VERSION 5.8 ;
BUSBITCHARS "[]" ;
DIVIDERCHAR "/" ;
UNITS
    DATABASE MICRONS 1000 ;
END UNITS

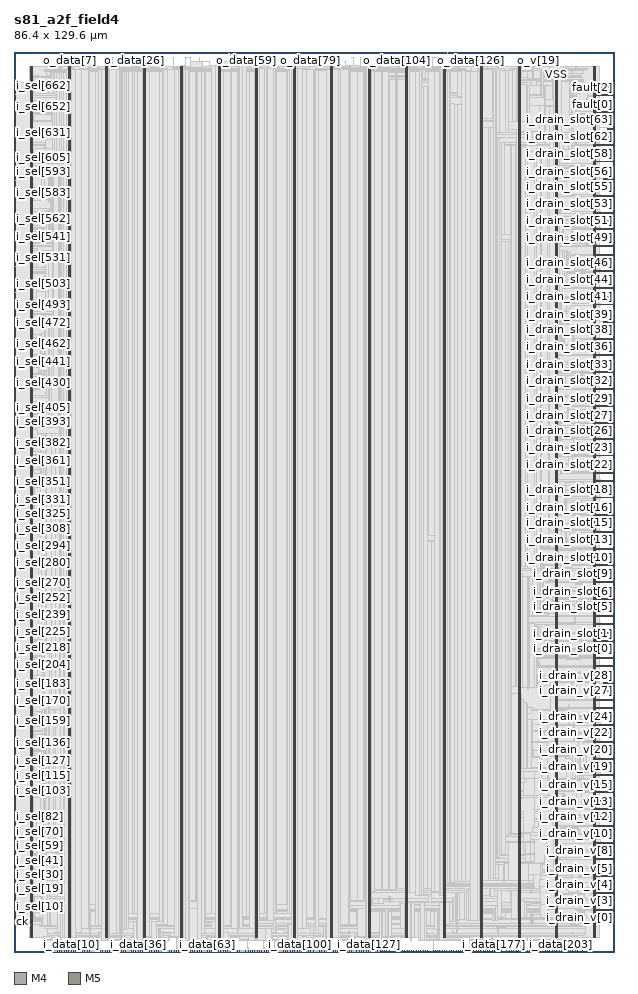
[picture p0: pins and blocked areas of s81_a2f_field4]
MACRO s81_a2f_field4
  FOREIGN s81_a2f_field4 0 0 ;
  CLASS BLOCK ;
  SIZE 86.4 BY 129.6 ;
  PIN ck
    DIRECTION INPUT ;
    USE SIGNAL ;
    PORT
      LAYER M4 ;
        RECT  0 4.32 0.192 4.344 ;
    END
  END ck
  PIN fault[0]
    DIRECTION OUTPUT ;
    USE SIGNAL ;
    PORT
      LAYER M4 ;
        RECT  86.208 120.96 86.4 120.984 ;
    END
    PORT
      LAYER M4 ;
        RECT  83.704 120.96 86.22 120.984 ;
    END
  END fault[0]
  PIN fault[1]
    DIRECTION OUTPUT ;
    USE SIGNAL ;
    PORT
      LAYER M4 ;
        RECT  86.208 122.256 86.4 122.28 ;
    END
    PORT
      LAYER M4 ;
        RECT  83.704 122.256 86.22 122.28 ;
    END
  END fault[1]
  PIN fault[2]
    DIRECTION OUTPUT ;
    USE SIGNAL ;
    PORT
      LAYER M4 ;
        RECT  86.208 123.408 86.4 123.432 ;
    END
    PORT
      LAYER M4 ;
        RECT  83.704 123.408 86.22 123.432 ;
    END
  END fault[2]
  PIN fault[3]
    DIRECTION OUTPUT ;
    USE SIGNAL ;
    PORT
      LAYER M4 ;
        RECT  86.208 124.56 86.4 124.584 ;
    END
    PORT
      LAYER M4 ;
        RECT  83.704 124.56 86.22 124.584 ;
    END
  END fault[3]
  PIN i_data[0]
    DIRECTION INPUT ;
    USE SIGNAL ;
    PORT
      LAYER M5 ;
        RECT  4.464 0 4.488 0.192 ;
    END
  END i_data[0]
  PIN i_data[100]
    DIRECTION INPUT ;
    USE SIGNAL ;
    PORT
      LAYER M5 ;
        RECT  41.136 0 41.16 0.192 ;
    END
  END i_data[100]
  PIN i_data[101]
    DIRECTION INPUT ;
    USE SIGNAL ;
    PORT
      LAYER M5 ;
        RECT  41.424 0 41.448 0.192 ;
    END
  END i_data[101]
  PIN i_data[102]
    DIRECTION INPUT ;
    USE SIGNAL ;
    PORT
      LAYER M5 ;
        RECT  41.712 0 41.736 0.192 ;
    END
  END i_data[102]
  PIN i_data[103]
    DIRECTION INPUT ;
    USE SIGNAL ;
    PORT
      LAYER M5 ;
        RECT  42.144 0 42.168 0.192 ;
    END
  END i_data[103]
  PIN i_data[104]
    DIRECTION INPUT ;
    USE SIGNAL ;
    PORT
      LAYER M5 ;
        RECT  42.432 0 42.456 0.192 ;
    END
  END i_data[104]
  PIN i_data[105]
    DIRECTION INPUT ;
    USE SIGNAL ;
    PORT
      LAYER M5 ;
        RECT  42.72 0 42.744 0.192 ;
    END
  END i_data[105]
  PIN i_data[106]
    DIRECTION INPUT ;
    USE SIGNAL ;
    PORT
      LAYER M5 ;
        RECT  43.152 0 43.176 0.192 ;
    END
  END i_data[106]
  PIN i_data[107]
    DIRECTION INPUT ;
    USE SIGNAL ;
    PORT
      LAYER M5 ;
        RECT  43.968 0 43.992 0.192 ;
    END
  END i_data[107]
  PIN i_data[108]
    DIRECTION INPUT ;
    USE SIGNAL ;
    PORT
      LAYER M5 ;
        RECT  44.256 0 44.28 0.192 ;
    END
  END i_data[108]
  PIN i_data[109]
    DIRECTION INPUT ;
    USE SIGNAL ;
    PORT
      LAYER M5 ;
        RECT  44.688 0 44.712 0.192 ;
    END
  END i_data[109]
  PIN i_data[10]
    DIRECTION INPUT ;
    USE SIGNAL ;
    PORT
      LAYER M5 ;
        RECT  8.304 0 8.328 0.192 ;
    END
  END i_data[10]
  PIN i_data[110]
    DIRECTION INPUT ;
    USE SIGNAL ;
    PORT
      LAYER M5 ;
        RECT  44.976 0 45 0.192 ;
    END
  END i_data[110]
  PIN i_data[111]
    DIRECTION INPUT ;
    USE SIGNAL ;
    PORT
      LAYER M5 ;
        RECT  45.264 0 45.288 0.192 ;
    END
  END i_data[111]
  PIN i_data[112]
    DIRECTION INPUT ;
    USE SIGNAL ;
    PORT
      LAYER M5 ;
        RECT  45.552 0 45.576 0.192 ;
    END
  END i_data[112]
  PIN i_data[113]
    DIRECTION INPUT ;
    USE SIGNAL ;
    PORT
      LAYER M5 ;
        RECT  45.984 0 46.008 0.192 ;
    END
  END i_data[113]
  PIN i_data[114]
    DIRECTION INPUT ;
    USE SIGNAL ;
    PORT
      LAYER M5 ;
        RECT  46.272 0 46.296 0.192 ;
    END
  END i_data[114]
  PIN i_data[115]
    DIRECTION INPUT ;
    USE SIGNAL ;
    PORT
      LAYER M5 ;
        RECT  46.56 0 46.584 0.192 ;
    END
  END i_data[115]
  PIN i_data[116]
    DIRECTION INPUT ;
    USE SIGNAL ;
    PORT
      LAYER M5 ;
        RECT  46.992 0 47.016 0.192 ;
    END
  END i_data[116]
  PIN i_data[117]
    DIRECTION INPUT ;
    USE SIGNAL ;
    PORT
      LAYER M5 ;
        RECT  47.28 0 47.304 0.192 ;
    END
  END i_data[117]
  PIN i_data[118]
    DIRECTION INPUT ;
    USE SIGNAL ;
    PORT
      LAYER M5 ;
        RECT  47.568 0 47.592 0.192 ;
    END
  END i_data[118]
  PIN i_data[119]
    DIRECTION INPUT ;
    USE SIGNAL ;
    PORT
      LAYER M5 ;
        RECT  48 0 48.024 0.192 ;
    END
  END i_data[119]
  PIN i_data[11]
    DIRECTION INPUT ;
    USE SIGNAL ;
    PORT
      LAYER M5 ;
        RECT  8.592 0 8.616 0.192 ;
    END
  END i_data[11]
  PIN i_data[120]
    DIRECTION INPUT ;
    USE SIGNAL ;
    PORT
      LAYER M5 ;
        RECT  48.288 0 48.312 0.192 ;
    END
  END i_data[120]
  PIN i_data[121]
    DIRECTION INPUT ;
    USE SIGNAL ;
    PORT
      LAYER M5 ;
        RECT  48.576 0 48.6 0.192 ;
    END
  END i_data[121]
  PIN i_data[122]
    DIRECTION INPUT ;
    USE SIGNAL ;
    PORT
      LAYER M5 ;
        RECT  49.344 0 49.368 0.192 ;
    END
  END i_data[122]
  PIN i_data[123]
    DIRECTION INPUT ;
    USE SIGNAL ;
    PORT
      LAYER M5 ;
        RECT  49.776 0 49.8 0.192 ;
    END
  END i_data[123]
  PIN i_data[124]
    DIRECTION INPUT ;
    USE SIGNAL ;
    PORT
      LAYER M5 ;
        RECT  50.064 0 50.088 0.192 ;
    END
  END i_data[124]
  PIN i_data[125]
    DIRECTION INPUT ;
    USE SIGNAL ;
    PORT
      LAYER M5 ;
        RECT  50.352 0 50.376 0.192 ;
    END
  END i_data[125]
  PIN i_data[126]
    DIRECTION INPUT ;
    USE SIGNAL ;
    PORT
      LAYER M5 ;
        RECT  50.784 0 50.808 0.192 ;
    END
  END i_data[126]
  PIN i_data[127]
    DIRECTION INPUT ;
    USE SIGNAL ;
    PORT
      LAYER M5 ;
        RECT  51.072 0 51.096 0.192 ;
    END
  END i_data[127]
  PIN i_data[128]
    DIRECTION INPUT ;
    USE SIGNAL ;
    PORT
      LAYER M5 ;
        RECT  51.36 0 51.384 0.192 ;
    END
  END i_data[128]
  PIN i_data[129]
    DIRECTION INPUT ;
    USE SIGNAL ;
    PORT
      LAYER M5 ;
        RECT  51.792 0 51.816 0.192 ;
    END
  END i_data[129]
  PIN i_data[12]
    DIRECTION INPUT ;
    USE SIGNAL ;
    PORT
      LAYER M5 ;
        RECT  8.88 0 8.904 0.192 ;
    END
  END i_data[12]
  PIN i_data[130]
    DIRECTION INPUT ;
    USE SIGNAL ;
    PORT
      LAYER M5 ;
        RECT  52.08 0 52.104 0.192 ;
    END
  END i_data[130]
  PIN i_data[131]
    DIRECTION INPUT ;
    USE SIGNAL ;
    PORT
      LAYER M5 ;
        RECT  52.368 0 52.392 0.192 ;
    END
  END i_data[131]
  PIN i_data[132]
    DIRECTION INPUT ;
    USE SIGNAL ;
    PORT
      LAYER M5 ;
        RECT  52.8 0 52.824 0.192 ;
    END
  END i_data[132]
  PIN i_data[133]
    DIRECTION INPUT ;
    USE SIGNAL ;
    PORT
      LAYER M5 ;
        RECT  53.088 0 53.112 0.192 ;
    END
  END i_data[133]
  PIN i_data[134]
    DIRECTION INPUT ;
    USE SIGNAL ;
    PORT
      LAYER M5 ;
        RECT  53.376 0 53.4 0.192 ;
    END
  END i_data[134]
  PIN i_data[135]
    DIRECTION INPUT ;
    USE SIGNAL ;
    PORT
      LAYER M5 ;
        RECT  53.664 0 53.688 0.192 ;
    END
  END i_data[135]
  PIN i_data[136]
    DIRECTION INPUT ;
    USE SIGNAL ;
    PORT
      LAYER M5 ;
        RECT  54.096 0 54.12 0.192 ;
    END
  END i_data[136]
  PIN i_data[137]
    DIRECTION INPUT ;
    USE SIGNAL ;
    PORT
      LAYER M5 ;
        RECT  54.912 0 54.936 0.192 ;
    END
  END i_data[137]
  PIN i_data[138]
    DIRECTION INPUT ;
    USE SIGNAL ;
    PORT
      LAYER M5 ;
        RECT  55.2 0 55.224 0.192 ;
    END
  END i_data[138]
  PIN i_data[139]
    DIRECTION INPUT ;
    USE SIGNAL ;
    PORT
      LAYER M5 ;
        RECT  55.632 0 55.656 0.192 ;
    END
  END i_data[139]
  PIN i_data[13]
    DIRECTION INPUT ;
    USE SIGNAL ;
    PORT
      LAYER M5 ;
        RECT  9.312 0 9.336 0.192 ;
    END
  END i_data[13]
  PIN i_data[140]
    DIRECTION INPUT ;
    USE SIGNAL ;
    PORT
      LAYER M5 ;
        RECT  55.92 0 55.944 0.192 ;
    END
  END i_data[140]
  PIN i_data[141]
    DIRECTION INPUT ;
    USE SIGNAL ;
    PORT
      LAYER M5 ;
        RECT  56.208 0 56.232 0.192 ;
    END
  END i_data[141]
  PIN i_data[142]
    DIRECTION INPUT ;
    USE SIGNAL ;
    PORT
      LAYER M5 ;
        RECT  56.64 0 56.664 0.192 ;
    END
  END i_data[142]
  PIN i_data[143]
    DIRECTION INPUT ;
    USE SIGNAL ;
    PORT
      LAYER M5 ;
        RECT  56.928 0 56.952 0.192 ;
    END
  END i_data[143]
  PIN i_data[144]
    DIRECTION INPUT ;
    USE SIGNAL ;
    PORT
      LAYER M5 ;
        RECT  57.216 0 57.24 0.192 ;
    END
  END i_data[144]
  PIN i_data[145]
    DIRECTION INPUT ;
    USE SIGNAL ;
    PORT
      LAYER M5 ;
        RECT  57.504 0 57.528 0.192 ;
    END
  END i_data[145]
  PIN i_data[146]
    DIRECTION INPUT ;
    USE SIGNAL ;
    PORT
      LAYER M5 ;
        RECT  57.936 0 57.96 0.192 ;
    END
  END i_data[146]
  PIN i_data[147]
    DIRECTION INPUT ;
    USE SIGNAL ;
    PORT
      LAYER M5 ;
        RECT  58.224 0 58.248 0.192 ;
    END
  END i_data[147]
  PIN i_data[148]
    DIRECTION INPUT ;
    USE SIGNAL ;
    PORT
      LAYER M5 ;
        RECT  58.512 0 58.536 0.192 ;
    END
  END i_data[148]
  PIN i_data[149]
    DIRECTION INPUT ;
    USE SIGNAL ;
    PORT
      LAYER M5 ;
        RECT  58.944 0 58.968 0.192 ;
    END
  END i_data[149]
  PIN i_data[14]
    DIRECTION INPUT ;
    USE SIGNAL ;
    PORT
      LAYER M5 ;
        RECT  9.6 0 9.624 0.192 ;
    END
  END i_data[14]
  PIN i_data[150]
    DIRECTION INPUT ;
    USE SIGNAL ;
    PORT
      LAYER M5 ;
        RECT  59.232 0 59.256 0.192 ;
    END
  END i_data[150]
  PIN i_data[151]
    DIRECTION INPUT ;
    USE SIGNAL ;
    PORT
      LAYER M5 ;
        RECT  59.52 0 59.544 0.192 ;
    END
  END i_data[151]
  PIN i_data[152]
    DIRECTION INPUT ;
    USE SIGNAL ;
    PORT
      LAYER M5 ;
        RECT  60.432 0 60.456 0.192 ;
    END
  END i_data[152]
  PIN i_data[153]
    DIRECTION INPUT ;
    USE SIGNAL ;
    PORT
      LAYER M5 ;
        RECT  60.72 0 60.744 0.192 ;
    END
  END i_data[153]
  PIN i_data[154]
    DIRECTION INPUT ;
    USE SIGNAL ;
    PORT
      LAYER M5 ;
        RECT  61.008 0 61.032 0.192 ;
    END
  END i_data[154]
  PIN i_data[155]
    DIRECTION INPUT ;
    USE SIGNAL ;
    PORT
      LAYER M5 ;
        RECT  61.296 0 61.32 0.192 ;
    END
  END i_data[155]
  PIN i_data[156]
    DIRECTION INPUT ;
    USE SIGNAL ;
    PORT
      LAYER M5 ;
        RECT  61.728 0 61.752 0.192 ;
    END
  END i_data[156]
  PIN i_data[157]
    DIRECTION INPUT ;
    USE SIGNAL ;
    PORT
      LAYER M5 ;
        RECT  62.016 0 62.04 0.192 ;
    END
  END i_data[157]
  PIN i_data[158]
    DIRECTION INPUT ;
    USE SIGNAL ;
    PORT
      LAYER M5 ;
        RECT  62.304 0 62.328 0.192 ;
    END
  END i_data[158]
  PIN i_data[159]
    DIRECTION INPUT ;
    USE SIGNAL ;
    PORT
      LAYER M5 ;
        RECT  62.736 0 62.76 0.192 ;
    END
  END i_data[159]
  PIN i_data[15]
    DIRECTION INPUT ;
    USE SIGNAL ;
    PORT
      LAYER M5 ;
        RECT  9.888 0 9.912 0.192 ;
    END
  END i_data[15]
  PIN i_data[160]
    DIRECTION INPUT ;
    USE SIGNAL ;
    PORT
      LAYER M5 ;
        RECT  63.024 0 63.048 0.192 ;
    END
  END i_data[160]
  PIN i_data[161]
    DIRECTION INPUT ;
    USE SIGNAL ;
    PORT
      LAYER M5 ;
        RECT  63.312 0 63.336 0.192 ;
    END
  END i_data[161]
  PIN i_data[162]
    DIRECTION INPUT ;
    USE SIGNAL ;
    PORT
      LAYER M5 ;
        RECT  63.744 0 63.768 0.192 ;
    END
  END i_data[162]
  PIN i_data[163]
    DIRECTION INPUT ;
    USE SIGNAL ;
    PORT
      LAYER M5 ;
        RECT  64.032 0 64.056 0.192 ;
    END
  END i_data[163]
  PIN i_data[164]
    DIRECTION INPUT ;
    USE SIGNAL ;
    PORT
      LAYER M5 ;
        RECT  64.32 0 64.344 0.192 ;
    END
  END i_data[164]
  PIN i_data[165]
    DIRECTION INPUT ;
    USE SIGNAL ;
    PORT
      LAYER M5 ;
        RECT  64.608 0 64.632 0.192 ;
    END
  END i_data[165]
  PIN i_data[166]
    DIRECTION INPUT ;
    USE SIGNAL ;
    PORT
      LAYER M5 ;
        RECT  65.568 0 65.592 0.192 ;
    END
  END i_data[166]
  PIN i_data[167]
    DIRECTION INPUT ;
    USE SIGNAL ;
    PORT
      LAYER M5 ;
        RECT  65.856 0 65.88 0.192 ;
    END
  END i_data[167]
  PIN i_data[168]
    DIRECTION INPUT ;
    USE SIGNAL ;
    PORT
      LAYER M5 ;
        RECT  66.144 0 66.168 0.192 ;
    END
  END i_data[168]
  PIN i_data[169]
    DIRECTION INPUT ;
    USE SIGNAL ;
    PORT
      LAYER M5 ;
        RECT  66.576 0 66.6 0.192 ;
    END
  END i_data[169]
  PIN i_data[16]
    DIRECTION INPUT ;
    USE SIGNAL ;
    PORT
      LAYER M5 ;
        RECT  10.176 0 10.2 0.192 ;
    END
  END i_data[16]
  PIN i_data[170]
    DIRECTION INPUT ;
    USE SIGNAL ;
    PORT
      LAYER M5 ;
        RECT  66.864 0 66.888 0.192 ;
    END
  END i_data[170]
  PIN i_data[171]
    DIRECTION INPUT ;
    USE SIGNAL ;
    PORT
      LAYER M5 ;
        RECT  67.152 0 67.176 0.192 ;
    END
  END i_data[171]
  PIN i_data[172]
    DIRECTION INPUT ;
    USE SIGNAL ;
    PORT
      LAYER M5 ;
        RECT  67.584 0 67.608 0.192 ;
    END
  END i_data[172]
  PIN i_data[173]
    DIRECTION INPUT ;
    USE SIGNAL ;
    PORT
      LAYER M5 ;
        RECT  67.872 0 67.896 0.192 ;
    END
  END i_data[173]
  PIN i_data[174]
    DIRECTION INPUT ;
    USE SIGNAL ;
    PORT
      LAYER M5 ;
        RECT  68.16 0 68.184 0.192 ;
    END
  END i_data[174]
  PIN i_data[175]
    DIRECTION INPUT ;
    USE SIGNAL ;
    PORT
      LAYER M5 ;
        RECT  68.448 0 68.472 0.192 ;
    END
  END i_data[175]
  PIN i_data[176]
    DIRECTION INPUT ;
    USE SIGNAL ;
    PORT
      LAYER M5 ;
        RECT  68.88 0 68.904 0.192 ;
    END
  END i_data[176]
  PIN i_data[177]
    DIRECTION INPUT ;
    USE SIGNAL ;
    PORT
      LAYER M5 ;
        RECT  69.168 0 69.192 0.192 ;
    END
  END i_data[177]
  PIN i_data[178]
    DIRECTION INPUT ;
    USE SIGNAL ;
    PORT
      LAYER M5 ;
        RECT  69.456 0 69.48 0.192 ;
    END
  END i_data[178]
  PIN i_data[179]
    DIRECTION INPUT ;
    USE SIGNAL ;
    PORT
      LAYER M5 ;
        RECT  69.888 0 69.912 0.192 ;
    END
  END i_data[179]
  PIN i_data[17]
    DIRECTION INPUT ;
    USE SIGNAL ;
    PORT
      LAYER M5 ;
        RECT  10.608 0 10.632 0.192 ;
    END
  END i_data[17]
  PIN i_data[180]
    DIRECTION INPUT ;
    USE SIGNAL ;
    PORT
      LAYER M5 ;
        RECT  70.176 0 70.2 0.192 ;
    END
  END i_data[180]
  PIN i_data[181]
    DIRECTION INPUT ;
    USE SIGNAL ;
    PORT
      LAYER M5 ;
        RECT  70.944 0 70.968 0.192 ;
    END
  END i_data[181]
  PIN i_data[182]
    DIRECTION INPUT ;
    USE SIGNAL ;
    PORT
      LAYER M5 ;
        RECT  71.376 0 71.4 0.192 ;
    END
  END i_data[182]
  PIN i_data[183]
    DIRECTION INPUT ;
    USE SIGNAL ;
    PORT
      LAYER M5 ;
        RECT  71.664 0 71.688 0.192 ;
    END
  END i_data[183]
  PIN i_data[184]
    DIRECTION INPUT ;
    USE SIGNAL ;
    PORT
      LAYER M5 ;
        RECT  71.952 0 71.976 0.192 ;
    END
  END i_data[184]
  PIN i_data[185]
    DIRECTION INPUT ;
    USE SIGNAL ;
    PORT
      LAYER M5 ;
        RECT  72.384 0 72.408 0.192 ;
    END
  END i_data[185]
  PIN i_data[186]
    DIRECTION INPUT ;
    USE SIGNAL ;
    PORT
      LAYER M5 ;
        RECT  72.672 0 72.696 0.192 ;
    END
  END i_data[186]
  PIN i_data[187]
    DIRECTION INPUT ;
    USE SIGNAL ;
    PORT
      LAYER M5 ;
        RECT  72.96 0 72.984 0.192 ;
    END
  END i_data[187]
  PIN i_data[188]
    DIRECTION INPUT ;
    USE SIGNAL ;
    PORT
      LAYER M5 ;
        RECT  73.248 0 73.272 0.192 ;
    END
  END i_data[188]
  PIN i_data[189]
    DIRECTION INPUT ;
    USE SIGNAL ;
    PORT
      LAYER M5 ;
        RECT  73.68 0 73.704 0.192 ;
    END
  END i_data[189]
  PIN i_data[18]
    DIRECTION INPUT ;
    USE SIGNAL ;
    PORT
      LAYER M5 ;
        RECT  10.896 0 10.92 0.192 ;
    END
  END i_data[18]
  PIN i_data[190]
    DIRECTION INPUT ;
    USE SIGNAL ;
    PORT
      LAYER M5 ;
        RECT  73.968 0 73.992 0.192 ;
    END
  END i_data[190]
  PIN i_data[191]
    DIRECTION INPUT ;
    USE SIGNAL ;
    PORT
      LAYER M5 ;
        RECT  74.256 0 74.28 0.192 ;
    END
  END i_data[191]
  PIN i_data[192]
    DIRECTION INPUT ;
    USE SIGNAL ;
    PORT
      LAYER M5 ;
        RECT  74.688 0 74.712 0.192 ;
    END
  END i_data[192]
  PIN i_data[193]
    DIRECTION INPUT ;
    USE SIGNAL ;
    PORT
      LAYER M5 ;
        RECT  74.976 0 75 0.192 ;
    END
  END i_data[193]
  PIN i_data[194]
    DIRECTION INPUT ;
    USE SIGNAL ;
    PORT
      LAYER M5 ;
        RECT  75.264 0 75.288 0.192 ;
    END
  END i_data[194]
  PIN i_data[195]
    DIRECTION INPUT ;
    USE SIGNAL ;
    PORT
      LAYER M5 ;
        RECT  75.696 0 75.72 0.192 ;
    END
  END i_data[195]
  PIN i_data[196]
    DIRECTION INPUT ;
    USE SIGNAL ;
    PORT
      LAYER M5 ;
        RECT  76.512 0 76.536 0.192 ;
    END
  END i_data[196]
  PIN i_data[197]
    DIRECTION INPUT ;
    USE SIGNAL ;
    PORT
      LAYER M5 ;
        RECT  76.8 0 76.824 0.192 ;
    END
  END i_data[197]
  PIN i_data[198]
    DIRECTION INPUT ;
    USE SIGNAL ;
    PORT
      LAYER M5 ;
        RECT  77.088 0 77.112 0.192 ;
    END
  END i_data[198]
  PIN i_data[199]
    DIRECTION INPUT ;
    USE SIGNAL ;
    PORT
      LAYER M5 ;
        RECT  77.52 0 77.544 0.192 ;
    END
  END i_data[199]
  PIN i_data[19]
    DIRECTION INPUT ;
    USE SIGNAL ;
    PORT
      LAYER M5 ;
        RECT  11.712 0 11.736 0.192 ;
    END
  END i_data[19]
  PIN i_data[1]
    DIRECTION INPUT ;
    USE SIGNAL ;
    PORT
      LAYER M5 ;
        RECT  4.752 0 4.776 0.192 ;
    END
  END i_data[1]
  PIN i_data[200]
    DIRECTION INPUT ;
    USE SIGNAL ;
    PORT
      LAYER M5 ;
        RECT  77.808 0 77.832 0.192 ;
    END
  END i_data[200]
  PIN i_data[201]
    DIRECTION INPUT ;
    USE SIGNAL ;
    PORT
      LAYER M5 ;
        RECT  78.096 0 78.12 0.192 ;
    END
  END i_data[201]
  PIN i_data[202]
    DIRECTION INPUT ;
    USE SIGNAL ;
    PORT
      LAYER M5 ;
        RECT  78.528 0 78.552 0.192 ;
    END
  END i_data[202]
  PIN i_data[203]
    DIRECTION INPUT ;
    USE SIGNAL ;
    PORT
      LAYER M5 ;
        RECT  78.816 0 78.84 0.192 ;
    END
  END i_data[203]
  PIN i_data[204]
    DIRECTION INPUT ;
    USE SIGNAL ;
    PORT
      LAYER M5 ;
        RECT  79.104 0 79.128 0.192 ;
    END
  END i_data[204]
  PIN i_data[205]
    DIRECTION INPUT ;
    USE SIGNAL ;
    PORT
      LAYER M5 ;
        RECT  79.536 0 79.56 0.192 ;
    END
  END i_data[205]
  PIN i_data[206]
    DIRECTION INPUT ;
    USE SIGNAL ;
    PORT
      LAYER M5 ;
        RECT  79.824 0 79.848 0.192 ;
    END
  END i_data[206]
  PIN i_data[207]
    DIRECTION INPUT ;
    USE SIGNAL ;
    PORT
      LAYER M5 ;
        RECT  80.112 0 80.136 0.192 ;
    END
  END i_data[207]
  PIN i_data[208]
    DIRECTION INPUT ;
    USE SIGNAL ;
    PORT
      LAYER M5 ;
        RECT  80.4 0 80.424 0.192 ;
    END
  END i_data[208]
  PIN i_data[209]
    DIRECTION INPUT ;
    USE SIGNAL ;
    PORT
      LAYER M5 ;
        RECT  80.832 0 80.856 0.192 ;
    END
  END i_data[209]
  PIN i_data[20]
    DIRECTION INPUT ;
    USE SIGNAL ;
    PORT
      LAYER M5 ;
        RECT  12.144 0 12.168 0.192 ;
    END
  END i_data[20]
  PIN i_data[210]
    DIRECTION INPUT ;
    USE SIGNAL ;
    PORT
      LAYER M5 ;
        RECT  81.12 0 81.144 0.192 ;
    END
  END i_data[210]
  PIN i_data[211]
    DIRECTION INPUT ;
    USE SIGNAL ;
    PORT
      LAYER M5 ;
        RECT  81.888 0 81.912 0.192 ;
    END
  END i_data[211]
  PIN i_data[21]
    DIRECTION INPUT ;
    USE SIGNAL ;
    PORT
      LAYER M5 ;
        RECT  12.432 0 12.456 0.192 ;
    END
  END i_data[21]
  PIN i_data[22]
    DIRECTION INPUT ;
    USE SIGNAL ;
    PORT
      LAYER M5 ;
        RECT  12.72 0 12.744 0.192 ;
    END
  END i_data[22]
  PIN i_data[23]
    DIRECTION INPUT ;
    USE SIGNAL ;
    PORT
      LAYER M5 ;
        RECT  13.152 0 13.176 0.192 ;
    END
  END i_data[23]
  PIN i_data[24]
    DIRECTION INPUT ;
    USE SIGNAL ;
    PORT
      LAYER M5 ;
        RECT  13.44 0 13.464 0.192 ;
    END
  END i_data[24]
  PIN i_data[25]
    DIRECTION INPUT ;
    USE SIGNAL ;
    PORT
      LAYER M5 ;
        RECT  13.728 0 13.752 0.192 ;
    END
  END i_data[25]
  PIN i_data[26]
    DIRECTION INPUT ;
    USE SIGNAL ;
    PORT
      LAYER M5 ;
        RECT  14.16 0 14.184 0.192 ;
    END
  END i_data[26]
  PIN i_data[27]
    DIRECTION INPUT ;
    USE SIGNAL ;
    PORT
      LAYER M5 ;
        RECT  14.448 0 14.472 0.192 ;
    END
  END i_data[27]
  PIN i_data[28]
    DIRECTION INPUT ;
    USE SIGNAL ;
    PORT
      LAYER M5 ;
        RECT  14.736 0 14.76 0.192 ;
    END
  END i_data[28]
  PIN i_data[29]
    DIRECTION INPUT ;
    USE SIGNAL ;
    PORT
      LAYER M5 ;
        RECT  15.024 0 15.048 0.192 ;
    END
  END i_data[29]
  PIN i_data[2]
    DIRECTION INPUT ;
    USE SIGNAL ;
    PORT
      LAYER M5 ;
        RECT  5.04 0 5.064 0.192 ;
    END
  END i_data[2]
  PIN i_data[30]
    DIRECTION INPUT ;
    USE SIGNAL ;
    PORT
      LAYER M5 ;
        RECT  15.456 0 15.48 0.192 ;
    END
  END i_data[30]
  PIN i_data[31]
    DIRECTION INPUT ;
    USE SIGNAL ;
    PORT
      LAYER M5 ;
        RECT  15.744 0 15.768 0.192 ;
    END
  END i_data[31]
  PIN i_data[32]
    DIRECTION INPUT ;
    USE SIGNAL ;
    PORT
      LAYER M5 ;
        RECT  16.032 0 16.056 0.192 ;
    END
  END i_data[32]
  PIN i_data[33]
    DIRECTION INPUT ;
    USE SIGNAL ;
    PORT
      LAYER M5 ;
        RECT  16.944 0 16.968 0.192 ;
    END
  END i_data[33]
  PIN i_data[34]
    DIRECTION INPUT ;
    USE SIGNAL ;
    PORT
      LAYER M5 ;
        RECT  17.232 0 17.256 0.192 ;
    END
  END i_data[34]
  PIN i_data[35]
    DIRECTION INPUT ;
    USE SIGNAL ;
    PORT
      LAYER M5 ;
        RECT  17.52 0 17.544 0.192 ;
    END
  END i_data[35]
  PIN i_data[36]
    DIRECTION INPUT ;
    USE SIGNAL ;
    PORT
      LAYER M5 ;
        RECT  17.952 0 17.976 0.192 ;
    END
  END i_data[36]
  PIN i_data[37]
    DIRECTION INPUT ;
    USE SIGNAL ;
    PORT
      LAYER M5 ;
        RECT  18.24 0 18.264 0.192 ;
    END
  END i_data[37]
  PIN i_data[38]
    DIRECTION INPUT ;
    USE SIGNAL ;
    PORT
      LAYER M5 ;
        RECT  18.528 0 18.552 0.192 ;
    END
  END i_data[38]
  PIN i_data[39]
    DIRECTION INPUT ;
    USE SIGNAL ;
    PORT
      LAYER M5 ;
        RECT  18.816 0 18.84 0.192 ;
    END
  END i_data[39]
  PIN i_data[3]
    DIRECTION INPUT ;
    USE SIGNAL ;
    PORT
      LAYER M5 ;
        RECT  5.472 0 5.496 0.192 ;
    END
  END i_data[3]
  PIN i_data[40]
    DIRECTION INPUT ;
    USE SIGNAL ;
    PORT
      LAYER M5 ;
        RECT  19.248 0 19.272 0.192 ;
    END
  END i_data[40]
  PIN i_data[41]
    DIRECTION INPUT ;
    USE SIGNAL ;
    PORT
      LAYER M5 ;
        RECT  19.536 0 19.56 0.192 ;
    END
  END i_data[41]
  PIN i_data[42]
    DIRECTION INPUT ;
    USE SIGNAL ;
    PORT
      LAYER M5 ;
        RECT  19.824 0 19.848 0.192 ;
    END
  END i_data[42]
  PIN i_data[43]
    DIRECTION INPUT ;
    USE SIGNAL ;
    PORT
      LAYER M5 ;
        RECT  20.256 0 20.28 0.192 ;
    END
  END i_data[43]
  PIN i_data[44]
    DIRECTION INPUT ;
    USE SIGNAL ;
    PORT
      LAYER M5 ;
        RECT  20.544 0 20.568 0.192 ;
    END
  END i_data[44]
  PIN i_data[45]
    DIRECTION INPUT ;
    USE SIGNAL ;
    PORT
      LAYER M5 ;
        RECT  20.832 0 20.856 0.192 ;
    END
  END i_data[45]
  PIN i_data[46]
    DIRECTION INPUT ;
    USE SIGNAL ;
    PORT
      LAYER M5 ;
        RECT  21.264 0 21.288 0.192 ;
    END
  END i_data[46]
  PIN i_data[47]
    DIRECTION INPUT ;
    USE SIGNAL ;
    PORT
      LAYER M5 ;
        RECT  21.552 0 21.576 0.192 ;
    END
  END i_data[47]
  PIN i_data[48]
    DIRECTION INPUT ;
    USE SIGNAL ;
    PORT
      LAYER M5 ;
        RECT  22.368 0 22.392 0.192 ;
    END
  END i_data[48]
  PIN i_data[49]
    DIRECTION INPUT ;
    USE SIGNAL ;
    PORT
      LAYER M5 ;
        RECT  22.656 0 22.68 0.192 ;
    END
  END i_data[49]
  PIN i_data[4]
    DIRECTION INPUT ;
    USE SIGNAL ;
    PORT
      LAYER M5 ;
        RECT  6.288 0 6.312 0.192 ;
    END
  END i_data[4]
  PIN i_data[50]
    DIRECTION INPUT ;
    USE SIGNAL ;
    PORT
      LAYER M5 ;
        RECT  23.088 0 23.112 0.192 ;
    END
  END i_data[50]
  PIN i_data[51]
    DIRECTION INPUT ;
    USE SIGNAL ;
    PORT
      LAYER M5 ;
        RECT  23.376 0 23.4 0.192 ;
    END
  END i_data[51]
  PIN i_data[52]
    DIRECTION INPUT ;
    USE SIGNAL ;
    PORT
      LAYER M5 ;
        RECT  23.664 0 23.688 0.192 ;
    END
  END i_data[52]
  PIN i_data[53]
    DIRECTION INPUT ;
    USE SIGNAL ;
    PORT
      LAYER M5 ;
        RECT  24.096 0 24.12 0.192 ;
    END
  END i_data[53]
  PIN i_data[54]
    DIRECTION INPUT ;
    USE SIGNAL ;
    PORT
      LAYER M5 ;
        RECT  24.384 0 24.408 0.192 ;
    END
  END i_data[54]
  PIN i_data[55]
    DIRECTION INPUT ;
    USE SIGNAL ;
    PORT
      LAYER M5 ;
        RECT  24.672 0 24.696 0.192 ;
    END
  END i_data[55]
  PIN i_data[56]
    DIRECTION INPUT ;
    USE SIGNAL ;
    PORT
      LAYER M5 ;
        RECT  25.104 0 25.128 0.192 ;
    END
  END i_data[56]
  PIN i_data[57]
    DIRECTION INPUT ;
    USE SIGNAL ;
    PORT
      LAYER M5 ;
        RECT  25.392 0 25.416 0.192 ;
    END
  END i_data[57]
  PIN i_data[58]
    DIRECTION INPUT ;
    USE SIGNAL ;
    PORT
      LAYER M5 ;
        RECT  25.68 0 25.704 0.192 ;
    END
  END i_data[58]
  PIN i_data[59]
    DIRECTION INPUT ;
    USE SIGNAL ;
    PORT
      LAYER M5 ;
        RECT  25.968 0 25.992 0.192 ;
    END
  END i_data[59]
  PIN i_data[5]
    DIRECTION INPUT ;
    USE SIGNAL ;
    PORT
      LAYER M5 ;
        RECT  6.576 0 6.6 0.192 ;
    END
  END i_data[5]
  PIN i_data[60]
    DIRECTION INPUT ;
    USE SIGNAL ;
    PORT
      LAYER M5 ;
        RECT  26.4 0 26.424 0.192 ;
    END
  END i_data[60]
  PIN i_data[61]
    DIRECTION INPUT ;
    USE SIGNAL ;
    PORT
      LAYER M5 ;
        RECT  26.688 0 26.712 0.192 ;
    END
  END i_data[61]
  PIN i_data[62]
    DIRECTION INPUT ;
    USE SIGNAL ;
    PORT
      LAYER M5 ;
        RECT  26.976 0 27 0.192 ;
    END
  END i_data[62]
  PIN i_data[63]
    DIRECTION INPUT ;
    USE SIGNAL ;
    PORT
      LAYER M5 ;
        RECT  27.888 0 27.912 0.192 ;
    END
  END i_data[63]
  PIN i_data[64]
    DIRECTION INPUT ;
    USE SIGNAL ;
    PORT
      LAYER M5 ;
        RECT  28.176 0 28.2 0.192 ;
    END
  END i_data[64]
  PIN i_data[65]
    DIRECTION INPUT ;
    USE SIGNAL ;
    PORT
      LAYER M5 ;
        RECT  28.464 0 28.488 0.192 ;
    END
  END i_data[65]
  PIN i_data[66]
    DIRECTION INPUT ;
    USE SIGNAL ;
    PORT
      LAYER M5 ;
        RECT  28.896 0 28.92 0.192 ;
    END
  END i_data[66]
  PIN i_data[67]
    DIRECTION INPUT ;
    USE SIGNAL ;
    PORT
      LAYER M5 ;
        RECT  29.184 0 29.208 0.192 ;
    END
  END i_data[67]
  PIN i_data[68]
    DIRECTION INPUT ;
    USE SIGNAL ;
    PORT
      LAYER M5 ;
        RECT  29.472 0 29.496 0.192 ;
    END
  END i_data[68]
  PIN i_data[69]
    DIRECTION INPUT ;
    USE SIGNAL ;
    PORT
      LAYER M5 ;
        RECT  29.76 0 29.784 0.192 ;
    END
  END i_data[69]
  PIN i_data[6]
    DIRECTION INPUT ;
    USE SIGNAL ;
    PORT
      LAYER M5 ;
        RECT  6.864 0 6.888 0.192 ;
    END
  END i_data[6]
  PIN i_data[70]
    DIRECTION INPUT ;
    USE SIGNAL ;
    PORT
      LAYER M5 ;
        RECT  30.192 0 30.216 0.192 ;
    END
  END i_data[70]
  PIN i_data[71]
    DIRECTION INPUT ;
    USE SIGNAL ;
    PORT
      LAYER M5 ;
        RECT  30.48 0 30.504 0.192 ;
    END
  END i_data[71]
  PIN i_data[72]
    DIRECTION INPUT ;
    USE SIGNAL ;
    PORT
      LAYER M5 ;
        RECT  30.768 0 30.792 0.192 ;
    END
  END i_data[72]
  PIN i_data[73]
    DIRECTION INPUT ;
    USE SIGNAL ;
    PORT
      LAYER M5 ;
        RECT  31.2 0 31.224 0.192 ;
    END
  END i_data[73]
  PIN i_data[74]
    DIRECTION INPUT ;
    USE SIGNAL ;
    PORT
      LAYER M5 ;
        RECT  31.488 0 31.512 0.192 ;
    END
  END i_data[74]
  PIN i_data[75]
    DIRECTION INPUT ;
    USE SIGNAL ;
    PORT
      LAYER M5 ;
        RECT  31.776 0 31.8 0.192 ;
    END
  END i_data[75]
  PIN i_data[76]
    DIRECTION INPUT ;
    USE SIGNAL ;
    PORT
      LAYER M5 ;
        RECT  32.208 0 32.232 0.192 ;
    END
  END i_data[76]
  PIN i_data[77]
    DIRECTION INPUT ;
    USE SIGNAL ;
    PORT
      LAYER M5 ;
        RECT  32.496 0 32.52 0.192 ;
    END
  END i_data[77]
  PIN i_data[78]
    DIRECTION INPUT ;
    USE SIGNAL ;
    PORT
      LAYER M5 ;
        RECT  33.312 0 33.336 0.192 ;
    END
  END i_data[78]
  PIN i_data[79]
    DIRECTION INPUT ;
    USE SIGNAL ;
    PORT
      LAYER M5 ;
        RECT  33.744 0 33.768 0.192 ;
    END
  END i_data[79]
  PIN i_data[7]
    DIRECTION INPUT ;
    USE SIGNAL ;
    PORT
      LAYER M5 ;
        RECT  7.296 0 7.32 0.192 ;
    END
  END i_data[7]
  PIN i_data[80]
    DIRECTION INPUT ;
    USE SIGNAL ;
    PORT
      LAYER M5 ;
        RECT  34.032 0 34.056 0.192 ;
    END
  END i_data[80]
  PIN i_data[81]
    DIRECTION INPUT ;
    USE SIGNAL ;
    PORT
      LAYER M5 ;
        RECT  34.32 0 34.344 0.192 ;
    END
  END i_data[81]
  PIN i_data[82]
    DIRECTION INPUT ;
    USE SIGNAL ;
    PORT
      LAYER M5 ;
        RECT  34.608 0 34.632 0.192 ;
    END
  END i_data[82]
  PIN i_data[83]
    DIRECTION INPUT ;
    USE SIGNAL ;
    PORT
      LAYER M5 ;
        RECT  35.04 0 35.064 0.192 ;
    END
  END i_data[83]
  PIN i_data[84]
    DIRECTION INPUT ;
    USE SIGNAL ;
    PORT
      LAYER M5 ;
        RECT  35.328 0 35.352 0.192 ;
    END
  END i_data[84]
  PIN i_data[85]
    DIRECTION INPUT ;
    USE SIGNAL ;
    PORT
      LAYER M5 ;
        RECT  35.616 0 35.64 0.192 ;
    END
  END i_data[85]
  PIN i_data[86]
    DIRECTION INPUT ;
    USE SIGNAL ;
    PORT
      LAYER M5 ;
        RECT  36.048 0 36.072 0.192 ;
    END
  END i_data[86]
  PIN i_data[87]
    DIRECTION INPUT ;
    USE SIGNAL ;
    PORT
      LAYER M5 ;
        RECT  36.336 0 36.36 0.192 ;
    END
  END i_data[87]
  PIN i_data[88]
    DIRECTION INPUT ;
    USE SIGNAL ;
    PORT
      LAYER M5 ;
        RECT  36.624 0 36.648 0.192 ;
    END
  END i_data[88]
  PIN i_data[89]
    DIRECTION INPUT ;
    USE SIGNAL ;
    PORT
      LAYER M5 ;
        RECT  37.056 0 37.08 0.192 ;
    END
  END i_data[89]
  PIN i_data[8]
    DIRECTION INPUT ;
    USE SIGNAL ;
    PORT
      LAYER M5 ;
        RECT  7.584 0 7.608 0.192 ;
    END
  END i_data[8]
  PIN i_data[90]
    DIRECTION INPUT ;
    USE SIGNAL ;
    PORT
      LAYER M5 ;
        RECT  37.344 0 37.368 0.192 ;
    END
  END i_data[90]
  PIN i_data[91]
    DIRECTION INPUT ;
    USE SIGNAL ;
    PORT
      LAYER M5 ;
        RECT  37.632 0 37.656 0.192 ;
    END
  END i_data[91]
  PIN i_data[92]
    DIRECTION INPUT ;
    USE SIGNAL ;
    PORT
      LAYER M5 ;
        RECT  37.92 0 37.944 0.192 ;
    END
  END i_data[92]
  PIN i_data[93]
    DIRECTION INPUT ;
    USE SIGNAL ;
    PORT
      LAYER M5 ;
        RECT  38.832 0 38.856 0.192 ;
    END
  END i_data[93]
  PIN i_data[94]
    DIRECTION INPUT ;
    USE SIGNAL ;
    PORT
      LAYER M5 ;
        RECT  39.12 0 39.144 0.192 ;
    END
  END i_data[94]
  PIN i_data[95]
    DIRECTION INPUT ;
    USE SIGNAL ;
    PORT
      LAYER M5 ;
        RECT  39.408 0 39.432 0.192 ;
    END
  END i_data[95]
  PIN i_data[96]
    DIRECTION INPUT ;
    USE SIGNAL ;
    PORT
      LAYER M5 ;
        RECT  39.84 0 39.864 0.192 ;
    END
  END i_data[96]
  PIN i_data[97]
    DIRECTION INPUT ;
    USE SIGNAL ;
    PORT
      LAYER M5 ;
        RECT  40.128 0 40.152 0.192 ;
    END
  END i_data[97]
  PIN i_data[98]
    DIRECTION INPUT ;
    USE SIGNAL ;
    PORT
      LAYER M5 ;
        RECT  40.416 0 40.44 0.192 ;
    END
  END i_data[98]
  PIN i_data[99]
    DIRECTION INPUT ;
    USE SIGNAL ;
    PORT
      LAYER M5 ;
        RECT  40.848 0 40.872 0.192 ;
    END
  END i_data[99]
  PIN i_data[9]
    DIRECTION INPUT ;
    USE SIGNAL ;
    PORT
      LAYER M5 ;
        RECT  7.872 0 7.896 0.192 ;
    END
  END i_data[9]
  PIN i_drain_slot[0]
    DIRECTION INPUT ;
    USE SIGNAL ;
    PORT
      LAYER M4 ;
        RECT  86.208 43.632 86.4 43.656 ;
    END
    PORT
      LAYER M4 ;
        RECT  83.704 43.632 86.22 43.656 ;
    END
  END i_drain_slot[0]
  PIN i_drain_slot[10]
    DIRECTION INPUT ;
    USE SIGNAL ;
    PORT
      LAYER M4 ;
        RECT  86.208 55.728 86.4 55.752 ;
    END
    PORT
      LAYER M4 ;
        RECT  83.704 55.728 86.22 55.752 ;
    END
  END i_drain_slot[10]
  PIN i_drain_slot[11]
    DIRECTION INPUT ;
    USE SIGNAL ;
    PORT
      LAYER M4 ;
        RECT  86.208 56.88 86.4 56.904 ;
    END
    PORT
      LAYER M4 ;
        RECT  83.704 56.88 86.22 56.904 ;
    END
  END i_drain_slot[11]
  PIN i_drain_slot[12]
    DIRECTION INPUT ;
    USE SIGNAL ;
    PORT
      LAYER M4 ;
        RECT  86.208 58.032 86.4 58.056 ;
    END
    PORT
      LAYER M4 ;
        RECT  83.704 58.032 86.22 58.056 ;
    END
  END i_drain_slot[12]
  PIN i_drain_slot[13]
    DIRECTION INPUT ;
    USE SIGNAL ;
    PORT
      LAYER M4 ;
        RECT  86.208 59.328 86.4 59.352 ;
    END
    PORT
      LAYER M4 ;
        RECT  84.913 59.328 86.22 59.352 ;
    END
  END i_drain_slot[13]
  PIN i_drain_slot[14]
    DIRECTION INPUT ;
    USE SIGNAL ;
    PORT
      LAYER M4 ;
        RECT  86.208 60.48 86.4 60.504 ;
    END
    PORT
      LAYER M4 ;
        RECT  83.704 60.48 86.22 60.504 ;
    END
  END i_drain_slot[14]
  PIN i_drain_slot[15]
    DIRECTION INPUT ;
    USE SIGNAL ;
    PORT
      LAYER M4 ;
        RECT  86.208 61.776 86.4 61.8 ;
    END
    PORT
      LAYER M4 ;
        RECT  84.913 61.776 86.22 61.8 ;
    END
  END i_drain_slot[15]
  PIN i_drain_slot[16]
    DIRECTION INPUT ;
    USE SIGNAL ;
    PORT
      LAYER M4 ;
        RECT  86.208 62.928 86.4 62.952 ;
    END
    PORT
      LAYER M4 ;
        RECT  83.704 62.928 86.22 62.952 ;
    END
  END i_drain_slot[16]
  PIN i_drain_slot[17]
    DIRECTION INPUT ;
    USE SIGNAL ;
    PORT
      LAYER M4 ;
        RECT  86.208 64.08 86.4 64.104 ;
    END
    PORT
      LAYER M4 ;
        RECT  83.704 64.08 86.22 64.104 ;
    END
  END i_drain_slot[17]
  PIN i_drain_slot[18]
    DIRECTION INPUT ;
    USE SIGNAL ;
    PORT
      LAYER M4 ;
        RECT  86.208 65.376 86.4 65.4 ;
    END
    PORT
      LAYER M4 ;
        RECT  83.704 65.376 86.22 65.4 ;
    END
  END i_drain_slot[18]
  PIN i_drain_slot[19]
    DIRECTION INPUT ;
    USE SIGNAL ;
    PORT
      LAYER M4 ;
        RECT  86.208 66.528 86.4 66.552 ;
    END
    PORT
      LAYER M4 ;
        RECT  83.704 66.528 86.22 66.552 ;
    END
  END i_drain_slot[19]
  PIN i_drain_slot[1]
    DIRECTION INPUT ;
    USE SIGNAL ;
    PORT
      LAYER M4 ;
        RECT  86.208 44.784 86.4 44.808 ;
    END
    PORT
      LAYER M4 ;
        RECT  83.704 44.784 86.22 44.808 ;
    END
  END i_drain_slot[1]
  PIN i_drain_slot[20]
    DIRECTION INPUT ;
    USE SIGNAL ;
    PORT
      LAYER M4 ;
        RECT  86.208 67.824 86.4 67.848 ;
    END
    PORT
      LAYER M4 ;
        RECT  83.704 67.824 86.22 67.848 ;
    END
  END i_drain_slot[20]
  PIN i_drain_slot[21]
    DIRECTION INPUT ;
    USE SIGNAL ;
    PORT
      LAYER M4 ;
        RECT  86.208 68.976 86.4 69 ;
    END
    PORT
      LAYER M4 ;
        RECT  83.704 68.976 86.22 69 ;
    END
  END i_drain_slot[21]
  PIN i_drain_slot[22]
    DIRECTION INPUT ;
    USE SIGNAL ;
    PORT
      LAYER M4 ;
        RECT  86.208 70.128 86.4 70.152 ;
    END
    PORT
      LAYER M4 ;
        RECT  84.913 70.128 86.22 70.152 ;
    END
  END i_drain_slot[22]
  PIN i_drain_slot[23]
    DIRECTION INPUT ;
    USE SIGNAL ;
    PORT
      LAYER M4 ;
        RECT  86.208 71.424 86.4 71.448 ;
    END
    PORT
      LAYER M4 ;
        RECT  83.704 71.424 86.22 71.448 ;
    END
  END i_drain_slot[23]
  PIN i_drain_slot[24]
    DIRECTION INPUT ;
    USE SIGNAL ;
    PORT
      LAYER M4 ;
        RECT  86.208 72.576 86.4 72.6 ;
    END
    PORT
      LAYER M4 ;
        RECT  83.704 72.576 86.22 72.6 ;
    END
  END i_drain_slot[24]
  PIN i_drain_slot[25]
    DIRECTION INPUT ;
    USE SIGNAL ;
    PORT
      LAYER M4 ;
        RECT  86.208 73.872 86.4 73.896 ;
    END
    PORT
      LAYER M4 ;
        RECT  83.704 73.872 86.22 73.896 ;
    END
  END i_drain_slot[25]
  PIN i_drain_slot[26]
    DIRECTION INPUT ;
    USE SIGNAL ;
    PORT
      LAYER M4 ;
        RECT  86.208 75.024 86.4 75.048 ;
    END
    PORT
      LAYER M4 ;
        RECT  84.913 75.024 86.22 75.048 ;
    END
  END i_drain_slot[26]
  PIN i_drain_slot[27]
    DIRECTION INPUT ;
    USE SIGNAL ;
    PORT
      LAYER M4 ;
        RECT  86.208 76.176 86.4 76.2 ;
    END
    PORT
      LAYER M4 ;
        RECT  83.704 76.176 86.22 76.2 ;
    END
  END i_drain_slot[27]
  PIN i_drain_slot[28]
    DIRECTION INPUT ;
    USE SIGNAL ;
    PORT
      LAYER M4 ;
        RECT  86.208 77.472 86.4 77.496 ;
    END
    PORT
      LAYER M4 ;
        RECT  83.704 77.472 86.22 77.496 ;
    END
  END i_drain_slot[28]
  PIN i_drain_slot[29]
    DIRECTION INPUT ;
    USE SIGNAL ;
    PORT
      LAYER M4 ;
        RECT  86.208 78.624 86.4 78.648 ;
    END
    PORT
      LAYER M4 ;
        RECT  83.704 78.624 86.22 78.648 ;
    END
  END i_drain_slot[29]
  PIN i_drain_slot[2]
    DIRECTION INPUT ;
    USE SIGNAL ;
    PORT
      LAYER M4 ;
        RECT  86.208 45.936 86.4 45.96 ;
    END
    PORT
      LAYER M4 ;
        RECT  83.704 45.936 86.22 45.96 ;
    END
  END i_drain_slot[2]
  PIN i_drain_slot[30]
    DIRECTION INPUT ;
    USE SIGNAL ;
    PORT
      LAYER M4 ;
        RECT  86.208 79.92 86.4 79.944 ;
    END
    PORT
      LAYER M4 ;
        RECT  83.704 79.92 86.22 79.944 ;
    END
  END i_drain_slot[30]
  PIN i_drain_slot[31]
    DIRECTION INPUT ;
    USE SIGNAL ;
    PORT
      LAYER M4 ;
        RECT  86.208 81.072 86.4 81.096 ;
    END
    PORT
      LAYER M4 ;
        RECT  83.704 81.072 86.22 81.096 ;
    END
  END i_drain_slot[31]
  PIN i_drain_slot[32]
    DIRECTION INPUT ;
    USE SIGNAL ;
    PORT
      LAYER M4 ;
        RECT  86.208 82.224 86.4 82.248 ;
    END
    PORT
      LAYER M4 ;
        RECT  84.913 82.224 86.22 82.248 ;
    END
  END i_drain_slot[32]
  PIN i_drain_slot[33]
    DIRECTION INPUT ;
    USE SIGNAL ;
    PORT
      LAYER M4 ;
        RECT  86.208 83.52 86.4 83.544 ;
    END
    PORT
      LAYER M4 ;
        RECT  83.704 83.52 86.22 83.544 ;
    END
  END i_drain_slot[33]
  PIN i_drain_slot[34]
    DIRECTION INPUT ;
    USE SIGNAL ;
    PORT
      LAYER M4 ;
        RECT  86.208 84.672 86.4 84.696 ;
    END
    PORT
      LAYER M4 ;
        RECT  83.704 84.672 86.22 84.696 ;
    END
  END i_drain_slot[34]
  PIN i_drain_slot[35]
    DIRECTION INPUT ;
    USE SIGNAL ;
    PORT
      LAYER M4 ;
        RECT  86.208 85.968 86.4 85.992 ;
    END
    PORT
      LAYER M4 ;
        RECT  83.704 85.968 86.22 85.992 ;
    END
  END i_drain_slot[35]
  PIN i_drain_slot[36]
    DIRECTION INPUT ;
    USE SIGNAL ;
    PORT
      LAYER M4 ;
        RECT  86.208 87.12 86.4 87.144 ;
    END
    PORT
      LAYER M4 ;
        RECT  85.489 87.12 86.22 87.144 ;
    END
  END i_drain_slot[36]
  PIN i_drain_slot[37]
    DIRECTION INPUT ;
    USE SIGNAL ;
    PORT
      LAYER M4 ;
        RECT  86.208 88.272 86.4 88.296 ;
    END
    PORT
      LAYER M4 ;
        RECT  83.704 88.272 86.22 88.296 ;
    END
  END i_drain_slot[37]
  PIN i_drain_slot[38]
    DIRECTION INPUT ;
    USE SIGNAL ;
    PORT
      LAYER M4 ;
        RECT  86.208 89.568 86.4 89.592 ;
    END
    PORT
      LAYER M4 ;
        RECT  85.489 89.568 86.22 89.592 ;
    END
  END i_drain_slot[38]
  PIN i_drain_slot[39]
    DIRECTION INPUT ;
    USE SIGNAL ;
    PORT
      LAYER M4 ;
        RECT  86.208 90.72 86.4 90.744 ;
    END
    PORT
      LAYER M4 ;
        RECT  84.913 90.72 86.22 90.744 ;
    END
  END i_drain_slot[39]
  PIN i_drain_slot[3]
    DIRECTION INPUT ;
    USE SIGNAL ;
    PORT
      LAYER M4 ;
        RECT  86.208 47.232 86.4 47.256 ;
    END
    PORT
      LAYER M4 ;
        RECT  83.704 47.232 86.22 47.256 ;
    END
  END i_drain_slot[3]
  PIN i_drain_slot[40]
    DIRECTION INPUT ;
    USE SIGNAL ;
    PORT
      LAYER M4 ;
        RECT  86.208 92.016 86.4 92.04 ;
    END
    PORT
      LAYER M4 ;
        RECT  83.704 92.016 86.22 92.04 ;
    END
  END i_drain_slot[40]
  PIN i_drain_slot[41]
    DIRECTION INPUT ;
    USE SIGNAL ;
    PORT
      LAYER M4 ;
        RECT  86.208 93.168 86.4 93.192 ;
    END
    PORT
      LAYER M4 ;
        RECT  83.704 93.168 86.22 93.192 ;
    END
  END i_drain_slot[41]
  PIN i_drain_slot[42]
    DIRECTION INPUT ;
    USE SIGNAL ;
    PORT
      LAYER M4 ;
        RECT  86.208 94.32 86.4 94.344 ;
    END
    PORT
      LAYER M4 ;
        RECT  83.704 94.32 86.22 94.344 ;
    END
  END i_drain_slot[42]
  PIN i_drain_slot[43]
    DIRECTION INPUT ;
    USE SIGNAL ;
    PORT
      LAYER M4 ;
        RECT  86.208 95.616 86.4 95.64 ;
    END
    PORT
      LAYER M4 ;
        RECT  83.704 95.616 86.22 95.64 ;
    END
  END i_drain_slot[43]
  PIN i_drain_slot[44]
    DIRECTION INPUT ;
    USE SIGNAL ;
    PORT
      LAYER M4 ;
        RECT  86.208 96.768 86.4 96.792 ;
    END
    PORT
      LAYER M4 ;
        RECT  84.913 96.768 86.22 96.792 ;
    END
  END i_drain_slot[44]
  PIN i_drain_slot[45]
    DIRECTION INPUT ;
    USE SIGNAL ;
    PORT
      LAYER M4 ;
        RECT  86.208 98.064 86.4 98.088 ;
    END
    PORT
      LAYER M4 ;
        RECT  83.704 98.064 86.22 98.088 ;
    END
  END i_drain_slot[45]
  PIN i_drain_slot[46]
    DIRECTION INPUT ;
    USE SIGNAL ;
    PORT
      LAYER M4 ;
        RECT  86.208 99.216 86.4 99.24 ;
    END
    PORT
      LAYER M4 ;
        RECT  84.913 99.216 86.22 99.24 ;
    END
  END i_drain_slot[46]
  PIN i_drain_slot[47]
    DIRECTION INPUT ;
    USE SIGNAL ;
    PORT
      LAYER M4 ;
        RECT  86.208 100.368 86.4 100.392 ;
    END
    PORT
      LAYER M4 ;
        RECT  83.704 100.368 86.22 100.392 ;
    END
  END i_drain_slot[47]
  PIN i_drain_slot[48]
    DIRECTION INPUT ;
    USE SIGNAL ;
    PORT
      LAYER M4 ;
        RECT  86.208 101.664 86.4 101.688 ;
    END
    PORT
      LAYER M4 ;
        RECT  83.704 101.664 86.22 101.688 ;
    END
  END i_drain_slot[48]
  PIN i_drain_slot[49]
    DIRECTION INPUT ;
    USE SIGNAL ;
    PORT
      LAYER M4 ;
        RECT  86.208 102.816 86.4 102.84 ;
    END
    PORT
      LAYER M4 ;
        RECT  84.913 102.816 86.22 102.84 ;
    END
  END i_drain_slot[49]
  PIN i_drain_slot[4]
    DIRECTION INPUT ;
    USE SIGNAL ;
    PORT
      LAYER M4 ;
        RECT  86.208 48.384 86.4 48.408 ;
    END
    PORT
      LAYER M4 ;
        RECT  83.704 48.384 86.22 48.408 ;
    END
  END i_drain_slot[4]
  PIN i_drain_slot[50]
    DIRECTION INPUT ;
    USE SIGNAL ;
    PORT
      LAYER M4 ;
        RECT  86.208 104.112 86.4 104.136 ;
    END
    PORT
      LAYER M4 ;
        RECT  83.704 104.112 86.22 104.136 ;
    END
  END i_drain_slot[50]
  PIN i_drain_slot[51]
    DIRECTION INPUT ;
    USE SIGNAL ;
    PORT
      LAYER M4 ;
        RECT  86.208 105.264 86.4 105.288 ;
    END
    PORT
      LAYER M4 ;
        RECT  84.913 105.264 86.22 105.288 ;
    END
  END i_drain_slot[51]
  PIN i_drain_slot[52]
    DIRECTION INPUT ;
    USE SIGNAL ;
    PORT
      LAYER M4 ;
        RECT  86.208 106.416 86.4 106.44 ;
    END
    PORT
      LAYER M4 ;
        RECT  83.704 106.416 86.22 106.44 ;
    END
  END i_drain_slot[52]
  PIN i_drain_slot[53]
    DIRECTION INPUT ;
    USE SIGNAL ;
    PORT
      LAYER M4 ;
        RECT  86.208 107.712 86.4 107.736 ;
    END
    PORT
      LAYER M4 ;
        RECT  84.913 107.712 86.22 107.736 ;
    END
  END i_drain_slot[53]
  PIN i_drain_slot[54]
    DIRECTION INPUT ;
    USE SIGNAL ;
    PORT
      LAYER M4 ;
        RECT  86.208 108.864 86.4 108.888 ;
    END
    PORT
      LAYER M4 ;
        RECT  83.704 108.864 86.22 108.888 ;
    END
  END i_drain_slot[54]
  PIN i_drain_slot[55]
    DIRECTION INPUT ;
    USE SIGNAL ;
    PORT
      LAYER M4 ;
        RECT  86.208 110.16 86.4 110.184 ;
    END
    PORT
      LAYER M4 ;
        RECT  84.913 110.16 86.22 110.184 ;
    END
  END i_drain_slot[55]
  PIN i_drain_slot[56]
    DIRECTION INPUT ;
    USE SIGNAL ;
    PORT
      LAYER M4 ;
        RECT  86.208 111.312 86.4 111.336 ;
    END
    PORT
      LAYER M4 ;
        RECT  84.913 111.312 86.22 111.336 ;
    END
  END i_drain_slot[56]
  PIN i_drain_slot[57]
    DIRECTION INPUT ;
    USE SIGNAL ;
    PORT
      LAYER M4 ;
        RECT  86.208 112.464 86.4 112.488 ;
    END
    PORT
      LAYER M4 ;
        RECT  83.704 112.464 86.22 112.488 ;
    END
  END i_drain_slot[57]
  PIN i_drain_slot[58]
    DIRECTION INPUT ;
    USE SIGNAL ;
    PORT
      LAYER M4 ;
        RECT  86.208 113.76 86.4 113.784 ;
    END
    PORT
      LAYER M4 ;
        RECT  83.704 113.76 86.22 113.784 ;
    END
  END i_drain_slot[58]
  PIN i_drain_slot[59]
    DIRECTION INPUT ;
    USE SIGNAL ;
    PORT
      LAYER M4 ;
        RECT  86.208 114.912 86.4 114.936 ;
    END
    PORT
      LAYER M4 ;
        RECT  83.704 114.912 86.22 114.936 ;
    END
  END i_drain_slot[59]
  PIN i_drain_slot[5]
    DIRECTION INPUT ;
    USE SIGNAL ;
    PORT
      LAYER M4 ;
        RECT  86.208 49.68 86.4 49.704 ;
    END
    PORT
      LAYER M4 ;
        RECT  84.913 49.68 86.22 49.704 ;
    END
  END i_drain_slot[5]
  PIN i_drain_slot[60]
    DIRECTION INPUT ;
    USE SIGNAL ;
    PORT
      LAYER M4 ;
        RECT  86.208 116.208 86.4 116.232 ;
    END
    PORT
      LAYER M4 ;
        RECT  83.704 116.208 86.22 116.232 ;
    END
  END i_drain_slot[60]
  PIN i_drain_slot[61]
    DIRECTION INPUT ;
    USE SIGNAL ;
    PORT
      LAYER M4 ;
        RECT  86.208 117.36 86.4 117.384 ;
    END
    PORT
      LAYER M4 ;
        RECT  83.704 117.36 86.22 117.384 ;
    END
  END i_drain_slot[61]
  PIN i_drain_slot[62]
    DIRECTION INPUT ;
    USE SIGNAL ;
    PORT
      LAYER M4 ;
        RECT  86.208 118.512 86.4 118.536 ;
    END
    PORT
      LAYER M4 ;
        RECT  85.489 118.512 86.22 118.536 ;
    END
  END i_drain_slot[62]
  PIN i_drain_slot[63]
    DIRECTION INPUT ;
    USE SIGNAL ;
    PORT
      LAYER M4 ;
        RECT  86.208 119.808 86.4 119.832 ;
    END
    PORT
      LAYER M4 ;
        RECT  85.489 119.808 86.22 119.832 ;
    END
  END i_drain_slot[63]
  PIN i_drain_slot[6]
    DIRECTION INPUT ;
    USE SIGNAL ;
    PORT
      LAYER M4 ;
        RECT  86.208 50.832 86.4 50.856 ;
    END
    PORT
      LAYER M4 ;
        RECT  83.704 50.832 86.22 50.856 ;
    END
  END i_drain_slot[6]
  PIN i_drain_slot[7]
    DIRECTION INPUT ;
    USE SIGNAL ;
    PORT
      LAYER M4 ;
        RECT  86.208 51.984 86.4 52.008 ;
    END
    PORT
      LAYER M4 ;
        RECT  83.704 51.984 86.22 52.008 ;
    END
  END i_drain_slot[7]
  PIN i_drain_slot[8]
    DIRECTION INPUT ;
    USE SIGNAL ;
    PORT
      LAYER M4 ;
        RECT  86.208 53.28 86.4 53.304 ;
    END
    PORT
      LAYER M4 ;
        RECT  83.704 53.28 86.22 53.304 ;
    END
  END i_drain_slot[8]
  PIN i_drain_slot[9]
    DIRECTION INPUT ;
    USE SIGNAL ;
    PORT
      LAYER M4 ;
        RECT  86.208 54.432 86.4 54.456 ;
    END
    PORT
      LAYER M4 ;
        RECT  84.913 54.432 86.22 54.456 ;
    END
  END i_drain_slot[9]
  PIN i_drain_v[0]
    DIRECTION INPUT ;
    USE SIGNAL ;
    PORT
      LAYER M4 ;
        RECT  86.208 4.896 86.4 4.92 ;
    END
    PORT
      LAYER M4 ;
        RECT  83.704 4.896 86.22 4.92 ;
    END
  END i_drain_v[0]
  PIN i_drain_v[10]
    DIRECTION INPUT ;
    USE SIGNAL ;
    PORT
      LAYER M4 ;
        RECT  86.208 16.992 86.4 17.016 ;
    END
    PORT
      LAYER M4 ;
        RECT  84.913 16.992 86.22 17.016 ;
    END
  END i_drain_v[10]
  PIN i_drain_v[11]
    DIRECTION INPUT ;
    USE SIGNAL ;
    PORT
      LAYER M4 ;
        RECT  86.208 18.144 86.4 18.168 ;
    END
    PORT
      LAYER M4 ;
        RECT  83.704 18.144 86.22 18.168 ;
    END
  END i_drain_v[11]
  PIN i_drain_v[12]
    DIRECTION INPUT ;
    USE SIGNAL ;
    PORT
      LAYER M4 ;
        RECT  86.208 19.44 86.4 19.464 ;
    END
    PORT
      LAYER M4 ;
        RECT  83.704 19.44 86.22 19.464 ;
    END
  END i_drain_v[12]
  PIN i_drain_v[13]
    DIRECTION INPUT ;
    USE SIGNAL ;
    PORT
      LAYER M4 ;
        RECT  86.208 20.592 86.4 20.616 ;
    END
    PORT
      LAYER M4 ;
        RECT  83.704 20.592 86.22 20.616 ;
    END
  END i_drain_v[13]
  PIN i_drain_v[14]
    DIRECTION INPUT ;
    USE SIGNAL ;
    PORT
      LAYER M4 ;
        RECT  86.208 21.744 86.4 21.768 ;
    END
    PORT
      LAYER M4 ;
        RECT  83.704 21.744 86.22 21.768 ;
    END
  END i_drain_v[14]
  PIN i_drain_v[15]
    DIRECTION INPUT ;
    USE SIGNAL ;
    PORT
      LAYER M4 ;
        RECT  86.208 23.04 86.4 23.064 ;
    END
    PORT
      LAYER M4 ;
        RECT  83.704 23.04 86.22 23.064 ;
    END
  END i_drain_v[15]
  PIN i_drain_v[16]
    DIRECTION INPUT ;
    USE SIGNAL ;
    PORT
      LAYER M4 ;
        RECT  86.208 24.192 86.4 24.216 ;
    END
    PORT
      LAYER M4 ;
        RECT  83.704 24.192 86.22 24.216 ;
    END
  END i_drain_v[16]
  PIN i_drain_v[17]
    DIRECTION INPUT ;
    USE SIGNAL ;
    PORT
      LAYER M4 ;
        RECT  86.208 25.488 86.4 25.512 ;
    END
    PORT
      LAYER M4 ;
        RECT  83.704 25.488 86.22 25.512 ;
    END
  END i_drain_v[17]
  PIN i_drain_v[18]
    DIRECTION INPUT ;
    USE SIGNAL ;
    PORT
      LAYER M4 ;
        RECT  86.208 26.64 86.4 26.664 ;
    END
    PORT
      LAYER M4 ;
        RECT  83.704 26.64 86.22 26.664 ;
    END
  END i_drain_v[18]
  PIN i_drain_v[19]
    DIRECTION INPUT ;
    USE SIGNAL ;
    PORT
      LAYER M4 ;
        RECT  86.208 27.792 86.4 27.816 ;
    END
    PORT
      LAYER M4 ;
        RECT  83.704 27.792 86.22 27.816 ;
    END
  END i_drain_v[19]
  PIN i_drain_v[1]
    DIRECTION INPUT ;
    USE SIGNAL ;
    PORT
      LAYER M4 ;
        RECT  86.208 6.048 86.4 6.072 ;
    END
    PORT
      LAYER M4 ;
        RECT  83.704 6.048 86.22 6.072 ;
    END
  END i_drain_v[1]
  PIN i_drain_v[20]
    DIRECTION INPUT ;
    USE SIGNAL ;
    PORT
      LAYER M4 ;
        RECT  86.208 29.088 86.4 29.112 ;
    END
    PORT
      LAYER M4 ;
        RECT  84.913 29.088 86.22 29.112 ;
    END
  END i_drain_v[20]
  PIN i_drain_v[21]
    DIRECTION INPUT ;
    USE SIGNAL ;
    PORT
      LAYER M4 ;
        RECT  86.208 30.24 86.4 30.264 ;
    END
    PORT
      LAYER M4 ;
        RECT  83.704 30.24 86.22 30.264 ;
    END
  END i_drain_v[21]
  PIN i_drain_v[22]
    DIRECTION INPUT ;
    USE SIGNAL ;
    PORT
      LAYER M4 ;
        RECT  86.208 31.536 86.4 31.56 ;
    END
    PORT
      LAYER M4 ;
        RECT  83.704 31.536 86.22 31.56 ;
    END
  END i_drain_v[22]
  PIN i_drain_v[23]
    DIRECTION INPUT ;
    USE SIGNAL ;
    PORT
      LAYER M4 ;
        RECT  86.208 32.688 86.4 32.712 ;
    END
    PORT
      LAYER M4 ;
        RECT  83.704 32.688 86.22 32.712 ;
    END
  END i_drain_v[23]
  PIN i_drain_v[24]
    DIRECTION INPUT ;
    USE SIGNAL ;
    PORT
      LAYER M4 ;
        RECT  86.208 33.84 86.4 33.864 ;
    END
    PORT
      LAYER M4 ;
        RECT  83.704 33.84 86.22 33.864 ;
    END
  END i_drain_v[24]
  PIN i_drain_v[25]
    DIRECTION INPUT ;
    USE SIGNAL ;
    PORT
      LAYER M4 ;
        RECT  86.208 35.136 86.4 35.16 ;
    END
    PORT
      LAYER M4 ;
        RECT  83.704 35.136 86.22 35.16 ;
    END
  END i_drain_v[25]
  PIN i_drain_v[26]
    DIRECTION INPUT ;
    USE SIGNAL ;
    PORT
      LAYER M4 ;
        RECT  86.208 36.288 86.4 36.312 ;
    END
    PORT
      LAYER M4 ;
        RECT  83.704 36.288 86.22 36.312 ;
    END
  END i_drain_v[26]
  PIN i_drain_v[27]
    DIRECTION INPUT ;
    USE SIGNAL ;
    PORT
      LAYER M4 ;
        RECT  86.208 37.584 86.4 37.608 ;
    END
    PORT
      LAYER M4 ;
        RECT  84.913 37.584 86.22 37.608 ;
    END
  END i_drain_v[27]
  PIN i_drain_v[28]
    DIRECTION INPUT ;
    USE SIGNAL ;
    PORT
      LAYER M4 ;
        RECT  86.208 38.736 86.4 38.76 ;
    END
    PORT
      LAYER M4 ;
        RECT  84.913 38.736 86.22 38.76 ;
    END
  END i_drain_v[28]
  PIN i_drain_v[29]
    DIRECTION INPUT ;
    USE SIGNAL ;
    PORT
      LAYER M4 ;
        RECT  86.208 39.888 86.4 39.912 ;
    END
    PORT
      LAYER M4 ;
        RECT  84.913 39.888 86.22 39.912 ;
    END
  END i_drain_v[29]
  PIN i_drain_v[2]
    DIRECTION INPUT ;
    USE SIGNAL ;
    PORT
      LAYER M4 ;
        RECT  86.208 7.344 86.4 7.368 ;
    END
    PORT
      LAYER M4 ;
        RECT  83.704 7.344 86.22 7.368 ;
    END
  END i_drain_v[2]
  PIN i_drain_v[30]
    DIRECTION INPUT ;
    USE SIGNAL ;
    PORT
      LAYER M4 ;
        RECT  86.208 41.184 86.4 41.208 ;
    END
    PORT
      LAYER M4 ;
        RECT  83.704 41.184 86.22 41.208 ;
    END
  END i_drain_v[30]
  PIN i_drain_v[31]
    DIRECTION INPUT ;
    USE SIGNAL ;
    PORT
      LAYER M4 ;
        RECT  86.208 42.336 86.4 42.36 ;
    END
    PORT
      LAYER M4 ;
        RECT  83.704 42.336 86.22 42.36 ;
    END
  END i_drain_v[31]
  PIN i_drain_v[3]
    DIRECTION INPUT ;
    USE SIGNAL ;
    PORT
      LAYER M4 ;
        RECT  86.208 8.496 86.4 8.52 ;
    END
    PORT
      LAYER M4 ;
        RECT  83.704 8.496 86.22 8.52 ;
    END
  END i_drain_v[3]
  PIN i_drain_v[4]
    DIRECTION INPUT ;
    USE SIGNAL ;
    PORT
      LAYER M4 ;
        RECT  86.208 9.648 86.4 9.672 ;
    END
    PORT
      LAYER M4 ;
        RECT  84.913 9.648 86.22 9.672 ;
    END
  END i_drain_v[4]
  PIN i_drain_v[5]
    DIRECTION INPUT ;
    USE SIGNAL ;
    PORT
      LAYER M4 ;
        RECT  86.208 10.944 86.4 10.968 ;
    END
    PORT
      LAYER M4 ;
        RECT  83.704 10.944 86.22 10.968 ;
    END
  END i_drain_v[5]
  PIN i_drain_v[6]
    DIRECTION INPUT ;
    USE SIGNAL ;
    PORT
      LAYER M4 ;
        RECT  86.208 12.096 86.4 12.12 ;
    END
    PORT
      LAYER M4 ;
        RECT  83.704 12.096 86.22 12.12 ;
    END
  END i_drain_v[6]
  PIN i_drain_v[7]
    DIRECTION INPUT ;
    USE SIGNAL ;
    PORT
      LAYER M4 ;
        RECT  86.208 13.392 86.4 13.416 ;
    END
    PORT
      LAYER M4 ;
        RECT  83.704 13.392 86.22 13.416 ;
    END
  END i_drain_v[7]
  PIN i_drain_v[8]
    DIRECTION INPUT ;
    USE SIGNAL ;
    PORT
      LAYER M4 ;
        RECT  86.208 14.544 86.4 14.568 ;
    END
    PORT
      LAYER M4 ;
        RECT  83.704 14.544 86.22 14.568 ;
    END
  END i_drain_v[8]
  PIN i_drain_v[9]
    DIRECTION INPUT ;
    USE SIGNAL ;
    PORT
      LAYER M4 ;
        RECT  86.208 15.696 86.4 15.72 ;
    END
    PORT
      LAYER M4 ;
        RECT  83.704 15.696 86.22 15.72 ;
    END
  END i_drain_v[9]
  PIN i_sel[0]
    DIRECTION INPUT ;
    USE SIGNAL ;
    PORT
      LAYER M4 ;
        RECT  0 4.752 0.192 4.776 ;
    END
  END i_sel[0]
  PIN i_sel[100]
    DIRECTION INPUT ;
    USE SIGNAL ;
    PORT
      LAYER M4 ;
        RECT  0 22.608 0.192 22.632 ;
    END
  END i_sel[100]
  PIN i_sel[101]
    DIRECTION INPUT ;
    USE SIGNAL ;
    PORT
      LAYER M4 ;
        RECT  0 22.752 0.192 22.776 ;
    END
  END i_sel[101]
  PIN i_sel[102]
    DIRECTION INPUT ;
    USE SIGNAL ;
    PORT
      LAYER M4 ;
        RECT  0 23.04 0.192 23.064 ;
    END
  END i_sel[102]
  PIN i_sel[103]
    DIRECTION INPUT ;
    USE SIGNAL ;
    PORT
      LAYER M4 ;
        RECT  0 23.184 0.192 23.208 ;
    END
  END i_sel[103]
  PIN i_sel[104]
    DIRECTION INPUT ;
    USE SIGNAL ;
    PORT
      LAYER M4 ;
        RECT  0 23.328 0.192 23.352 ;
    END
  END i_sel[104]
  PIN i_sel[105]
    DIRECTION INPUT ;
    USE SIGNAL ;
    PORT
      LAYER M4 ;
        RECT  0 23.472 0.192 23.496 ;
    END
  END i_sel[105]
  PIN i_sel[106]
    DIRECTION INPUT ;
    USE SIGNAL ;
    PORT
      LAYER M4 ;
        RECT  0 23.76 0.192 23.784 ;
    END
  END i_sel[106]
  PIN i_sel[107]
    DIRECTION INPUT ;
    USE SIGNAL ;
    PORT
      LAYER M4 ;
        RECT  0 23.904 0.192 23.928 ;
    END
  END i_sel[107]
  PIN i_sel[108]
    DIRECTION INPUT ;
    USE SIGNAL ;
    PORT
      LAYER M4 ;
        RECT  0 24.048 0.192 24.072 ;
    END
  END i_sel[108]
  PIN i_sel[109]
    DIRECTION INPUT ;
    USE SIGNAL ;
    PORT
      LAYER M4 ;
        RECT  0 24.192 0.192 24.216 ;
    END
  END i_sel[109]
  PIN i_sel[10]
    DIRECTION INPUT ;
    USE SIGNAL ;
    PORT
      LAYER M4 ;
        RECT  0 6.48 0.192 6.504 ;
    END
  END i_sel[10]
  PIN i_sel[110]
    DIRECTION INPUT ;
    USE SIGNAL ;
    PORT
      LAYER M4 ;
        RECT  0 24.48 0.192 24.504 ;
    END
  END i_sel[110]
  PIN i_sel[111]
    DIRECTION INPUT ;
    USE SIGNAL ;
    PORT
      LAYER M4 ;
        RECT  0 24.624 0.192 24.648 ;
    END
  END i_sel[111]
  PIN i_sel[112]
    DIRECTION INPUT ;
    USE SIGNAL ;
    PORT
      LAYER M4 ;
        RECT  0 24.768 0.192 24.792 ;
    END
  END i_sel[112]
  PIN i_sel[113]
    DIRECTION INPUT ;
    USE SIGNAL ;
    PORT
      LAYER M4 ;
        RECT  0 24.912 0.192 24.936 ;
    END
  END i_sel[113]
  PIN i_sel[114]
    DIRECTION INPUT ;
    USE SIGNAL ;
    PORT
      LAYER M4 ;
        RECT  0 25.2 0.192 25.224 ;
    END
  END i_sel[114]
  PIN i_sel[115]
    DIRECTION INPUT ;
    USE SIGNAL ;
    PORT
      LAYER M4 ;
        RECT  0 25.344 0.192 25.368 ;
    END
  END i_sel[115]
  PIN i_sel[116]
    DIRECTION INPUT ;
    USE SIGNAL ;
    PORT
      LAYER M4 ;
        RECT  0 25.488 0.192 25.512 ;
    END
  END i_sel[116]
  PIN i_sel[117]
    DIRECTION INPUT ;
    USE SIGNAL ;
    PORT
      LAYER M4 ;
        RECT  0 25.632 0.192 25.656 ;
    END
  END i_sel[117]
  PIN i_sel[118]
    DIRECTION INPUT ;
    USE SIGNAL ;
    PORT
      LAYER M4 ;
        RECT  0 25.92 0.192 25.944 ;
    END
  END i_sel[118]
  PIN i_sel[119]
    DIRECTION INPUT ;
    USE SIGNAL ;
    PORT
      LAYER M4 ;
        RECT  0 26.064 0.192 26.088 ;
    END
  END i_sel[119]
  PIN i_sel[11]
    DIRECTION INPUT ;
    USE SIGNAL ;
    PORT
      LAYER M4 ;
        RECT  0 6.624 0.192 6.648 ;
    END
  END i_sel[11]
  PIN i_sel[120]
    DIRECTION INPUT ;
    USE SIGNAL ;
    PORT
      LAYER M4 ;
        RECT  0 26.208 0.192 26.232 ;
    END
  END i_sel[120]
  PIN i_sel[121]
    DIRECTION INPUT ;
    USE SIGNAL ;
    PORT
      LAYER M4 ;
        RECT  0 26.352 0.192 26.376 ;
    END
  END i_sel[121]
  PIN i_sel[122]
    DIRECTION INPUT ;
    USE SIGNAL ;
    PORT
      LAYER M4 ;
        RECT  0 26.64 0.192 26.664 ;
    END
  END i_sel[122]
  PIN i_sel[123]
    DIRECTION INPUT ;
    USE SIGNAL ;
    PORT
      LAYER M4 ;
        RECT  0 26.784 0.192 26.808 ;
    END
  END i_sel[123]
  PIN i_sel[124]
    DIRECTION INPUT ;
    USE SIGNAL ;
    PORT
      LAYER M4 ;
        RECT  0 26.928 0.192 26.952 ;
    END
  END i_sel[124]
  PIN i_sel[125]
    DIRECTION INPUT ;
    USE SIGNAL ;
    PORT
      LAYER M4 ;
        RECT  0 27.072 0.192 27.096 ;
    END
  END i_sel[125]
  PIN i_sel[126]
    DIRECTION INPUT ;
    USE SIGNAL ;
    PORT
      LAYER M4 ;
        RECT  0 27.36 0.192 27.384 ;
    END
  END i_sel[126]
  PIN i_sel[127]
    DIRECTION INPUT ;
    USE SIGNAL ;
    PORT
      LAYER M4 ;
        RECT  0 27.504 0.192 27.528 ;
    END
  END i_sel[127]
  PIN i_sel[128]
    DIRECTION INPUT ;
    USE SIGNAL ;
    PORT
      LAYER M4 ;
        RECT  0 27.648 0.192 27.672 ;
    END
  END i_sel[128]
  PIN i_sel[129]
    DIRECTION INPUT ;
    USE SIGNAL ;
    PORT
      LAYER M4 ;
        RECT  0 27.792 0.192 27.816 ;
    END
  END i_sel[129]
  PIN i_sel[12]
    DIRECTION INPUT ;
    USE SIGNAL ;
    PORT
      LAYER M4 ;
        RECT  0 6.912 0.192 6.936 ;
    END
  END i_sel[12]
  PIN i_sel[130]
    DIRECTION INPUT ;
    USE SIGNAL ;
    PORT
      LAYER M4 ;
        RECT  0 28.08 0.192 28.104 ;
    END
  END i_sel[130]
  PIN i_sel[131]
    DIRECTION INPUT ;
    USE SIGNAL ;
    PORT
      LAYER M4 ;
        RECT  0 28.224 0.192 28.248 ;
    END
  END i_sel[131]
  PIN i_sel[132]
    DIRECTION INPUT ;
    USE SIGNAL ;
    PORT
      LAYER M4 ;
        RECT  0 28.368 0.192 28.392 ;
    END
  END i_sel[132]
  PIN i_sel[133]
    DIRECTION INPUT ;
    USE SIGNAL ;
    PORT
      LAYER M4 ;
        RECT  0 28.512 0.192 28.536 ;
    END
  END i_sel[133]
  PIN i_sel[134]
    DIRECTION INPUT ;
    USE SIGNAL ;
    PORT
      LAYER M4 ;
        RECT  0 28.8 0.192 28.824 ;
    END
  END i_sel[134]
  PIN i_sel[135]
    DIRECTION INPUT ;
    USE SIGNAL ;
    PORT
      LAYER M4 ;
        RECT  0 28.944 0.192 28.968 ;
    END
  END i_sel[135]
  PIN i_sel[136]
    DIRECTION INPUT ;
    USE SIGNAL ;
    PORT
      LAYER M4 ;
        RECT  0 29.088 0.192 29.112 ;
    END
  END i_sel[136]
  PIN i_sel[137]
    DIRECTION INPUT ;
    USE SIGNAL ;
    PORT
      LAYER M4 ;
        RECT  0 29.232 0.192 29.256 ;
    END
  END i_sel[137]
  PIN i_sel[138]
    DIRECTION INPUT ;
    USE SIGNAL ;
    PORT
      LAYER M4 ;
        RECT  0 29.52 0.192 29.544 ;
    END
  END i_sel[138]
  PIN i_sel[139]
    DIRECTION INPUT ;
    USE SIGNAL ;
    PORT
      LAYER M4 ;
        RECT  0 29.664 0.192 29.688 ;
    END
  END i_sel[139]
  PIN i_sel[13]
    DIRECTION INPUT ;
    USE SIGNAL ;
    PORT
      LAYER M4 ;
        RECT  0 7.056 0.192 7.08 ;
    END
  END i_sel[13]
  PIN i_sel[140]
    DIRECTION INPUT ;
    USE SIGNAL ;
    PORT
      LAYER M4 ;
        RECT  0 29.808 0.192 29.832 ;
    END
  END i_sel[140]
  PIN i_sel[141]
    DIRECTION INPUT ;
    USE SIGNAL ;
    PORT
      LAYER M4 ;
        RECT  0 29.952 0.192 29.976 ;
    END
  END i_sel[141]
  PIN i_sel[142]
    DIRECTION INPUT ;
    USE SIGNAL ;
    PORT
      LAYER M4 ;
        RECT  0 30.24 0.192 30.264 ;
    END
  END i_sel[142]
  PIN i_sel[143]
    DIRECTION INPUT ;
    USE SIGNAL ;
    PORT
      LAYER M4 ;
        RECT  0 30.384 0.192 30.408 ;
    END
  END i_sel[143]
  PIN i_sel[144]
    DIRECTION INPUT ;
    USE SIGNAL ;
    PORT
      LAYER M4 ;
        RECT  0 30.528 0.192 30.552 ;
    END
  END i_sel[144]
  PIN i_sel[145]
    DIRECTION INPUT ;
    USE SIGNAL ;
    PORT
      LAYER M4 ;
        RECT  0 30.672 0.192 30.696 ;
    END
  END i_sel[145]
  PIN i_sel[146]
    DIRECTION INPUT ;
    USE SIGNAL ;
    PORT
      LAYER M4 ;
        RECT  0 30.96 0.192 30.984 ;
    END
  END i_sel[146]
  PIN i_sel[147]
    DIRECTION INPUT ;
    USE SIGNAL ;
    PORT
      LAYER M4 ;
        RECT  0 31.104 0.192 31.128 ;
    END
  END i_sel[147]
  PIN i_sel[148]
    DIRECTION INPUT ;
    USE SIGNAL ;
    PORT
      LAYER M4 ;
        RECT  0 31.248 0.192 31.272 ;
    END
  END i_sel[148]
  PIN i_sel[149]
    DIRECTION INPUT ;
    USE SIGNAL ;
    PORT
      LAYER M4 ;
        RECT  0 31.392 0.192 31.416 ;
    END
  END i_sel[149]
  PIN i_sel[14]
    DIRECTION INPUT ;
    USE SIGNAL ;
    PORT
      LAYER M4 ;
        RECT  0 7.2 0.192 7.224 ;
    END
  END i_sel[14]
  PIN i_sel[150]
    DIRECTION INPUT ;
    USE SIGNAL ;
    PORT
      LAYER M4 ;
        RECT  0 31.68 0.192 31.704 ;
    END
  END i_sel[150]
  PIN i_sel[151]
    DIRECTION INPUT ;
    USE SIGNAL ;
    PORT
      LAYER M4 ;
        RECT  0 31.824 0.192 31.848 ;
    END
  END i_sel[151]
  PIN i_sel[152]
    DIRECTION INPUT ;
    USE SIGNAL ;
    PORT
      LAYER M4 ;
        RECT  0 31.968 0.192 31.992 ;
    END
  END i_sel[152]
  PIN i_sel[153]
    DIRECTION INPUT ;
    USE SIGNAL ;
    PORT
      LAYER M4 ;
        RECT  0 32.112 0.192 32.136 ;
    END
  END i_sel[153]
  PIN i_sel[154]
    DIRECTION INPUT ;
    USE SIGNAL ;
    PORT
      LAYER M4 ;
        RECT  0 32.4 0.192 32.424 ;
    END
  END i_sel[154]
  PIN i_sel[155]
    DIRECTION INPUT ;
    USE SIGNAL ;
    PORT
      LAYER M4 ;
        RECT  0 32.544 0.192 32.568 ;
    END
  END i_sel[155]
  PIN i_sel[156]
    DIRECTION INPUT ;
    USE SIGNAL ;
    PORT
      LAYER M4 ;
        RECT  0 32.688 0.192 32.712 ;
    END
  END i_sel[156]
  PIN i_sel[157]
    DIRECTION INPUT ;
    USE SIGNAL ;
    PORT
      LAYER M4 ;
        RECT  0 32.832 0.192 32.856 ;
    END
  END i_sel[157]
  PIN i_sel[158]
    DIRECTION INPUT ;
    USE SIGNAL ;
    PORT
      LAYER M4 ;
        RECT  0 33.12 0.192 33.144 ;
    END
  END i_sel[158]
  PIN i_sel[159]
    DIRECTION INPUT ;
    USE SIGNAL ;
    PORT
      LAYER M4 ;
        RECT  0 33.264 0.192 33.288 ;
    END
  END i_sel[159]
  PIN i_sel[15]
    DIRECTION INPUT ;
    USE SIGNAL ;
    PORT
      LAYER M4 ;
        RECT  0 7.344 0.192 7.368 ;
    END
  END i_sel[15]
  PIN i_sel[160]
    DIRECTION INPUT ;
    USE SIGNAL ;
    PORT
      LAYER M4 ;
        RECT  0 33.408 0.192 33.432 ;
    END
  END i_sel[160]
  PIN i_sel[161]
    DIRECTION INPUT ;
    USE SIGNAL ;
    PORT
      LAYER M4 ;
        RECT  0 33.552 0.192 33.576 ;
    END
  END i_sel[161]
  PIN i_sel[162]
    DIRECTION INPUT ;
    USE SIGNAL ;
    PORT
      LAYER M4 ;
        RECT  0 33.84 0.192 33.864 ;
    END
  END i_sel[162]
  PIN i_sel[163]
    DIRECTION INPUT ;
    USE SIGNAL ;
    PORT
      LAYER M4 ;
        RECT  0 33.984 0.192 34.008 ;
    END
  END i_sel[163]
  PIN i_sel[164]
    DIRECTION INPUT ;
    USE SIGNAL ;
    PORT
      LAYER M4 ;
        RECT  0 34.128 0.192 34.152 ;
    END
  END i_sel[164]
  PIN i_sel[165]
    DIRECTION INPUT ;
    USE SIGNAL ;
    PORT
      LAYER M4 ;
        RECT  0 34.272 0.192 34.296 ;
    END
  END i_sel[165]
  PIN i_sel[166]
    DIRECTION INPUT ;
    USE SIGNAL ;
    PORT
      LAYER M4 ;
        RECT  0 34.56 0.192 34.584 ;
    END
  END i_sel[166]
  PIN i_sel[167]
    DIRECTION INPUT ;
    USE SIGNAL ;
    PORT
      LAYER M4 ;
        RECT  0 34.704 0.192 34.728 ;
    END
  END i_sel[167]
  PIN i_sel[168]
    DIRECTION INPUT ;
    USE SIGNAL ;
    PORT
      LAYER M4 ;
        RECT  0 34.848 0.192 34.872 ;
    END
  END i_sel[168]
  PIN i_sel[169]
    DIRECTION INPUT ;
    USE SIGNAL ;
    PORT
      LAYER M4 ;
        RECT  0 34.992 0.192 35.016 ;
    END
  END i_sel[169]
  PIN i_sel[16]
    DIRECTION INPUT ;
    USE SIGNAL ;
    PORT
      LAYER M4 ;
        RECT  0 7.632 0.192 7.656 ;
    END
  END i_sel[16]
  PIN i_sel[170]
    DIRECTION INPUT ;
    USE SIGNAL ;
    PORT
      LAYER M4 ;
        RECT  0 35.136 0.192 35.16 ;
    END
  END i_sel[170]
  PIN i_sel[171]
    DIRECTION INPUT ;
    USE SIGNAL ;
    PORT
      LAYER M4 ;
        RECT  0 35.424 0.192 35.448 ;
    END
  END i_sel[171]
  PIN i_sel[172]
    DIRECTION INPUT ;
    USE SIGNAL ;
    PORT
      LAYER M4 ;
        RECT  0 35.568 0.192 35.592 ;
    END
  END i_sel[172]
  PIN i_sel[173]
    DIRECTION INPUT ;
    USE SIGNAL ;
    PORT
      LAYER M4 ;
        RECT  0 35.712 0.192 35.736 ;
    END
  END i_sel[173]
  PIN i_sel[174]
    DIRECTION INPUT ;
    USE SIGNAL ;
    PORT
      LAYER M4 ;
        RECT  0 35.856 0.192 35.88 ;
    END
  END i_sel[174]
  PIN i_sel[175]
    DIRECTION INPUT ;
    USE SIGNAL ;
    PORT
      LAYER M4 ;
        RECT  0 36.144 0.192 36.168 ;
    END
  END i_sel[175]
  PIN i_sel[176]
    DIRECTION INPUT ;
    USE SIGNAL ;
    PORT
      LAYER M4 ;
        RECT  0 36.288 0.192 36.312 ;
    END
  END i_sel[176]
  PIN i_sel[177]
    DIRECTION INPUT ;
    USE SIGNAL ;
    PORT
      LAYER M4 ;
        RECT  0 36.432 0.192 36.456 ;
    END
  END i_sel[177]
  PIN i_sel[178]
    DIRECTION INPUT ;
    USE SIGNAL ;
    PORT
      LAYER M4 ;
        RECT  0 36.576 0.192 36.6 ;
    END
  END i_sel[178]
  PIN i_sel[179]
    DIRECTION INPUT ;
    USE SIGNAL ;
    PORT
      LAYER M4 ;
        RECT  0 36.864 0.192 36.888 ;
    END
  END i_sel[179]
  PIN i_sel[17]
    DIRECTION INPUT ;
    USE SIGNAL ;
    PORT
      LAYER M4 ;
        RECT  0 7.776 0.192 7.8 ;
    END
  END i_sel[17]
  PIN i_sel[180]
    DIRECTION INPUT ;
    USE SIGNAL ;
    PORT
      LAYER M4 ;
        RECT  0 37.008 0.192 37.032 ;
    END
  END i_sel[180]
  PIN i_sel[181]
    DIRECTION INPUT ;
    USE SIGNAL ;
    PORT
      LAYER M4 ;
        RECT  0 37.152 0.192 37.176 ;
    END
  END i_sel[181]
  PIN i_sel[182]
    DIRECTION INPUT ;
    USE SIGNAL ;
    PORT
      LAYER M4 ;
        RECT  0 37.296 0.192 37.32 ;
    END
  END i_sel[182]
  PIN i_sel[183]
    DIRECTION INPUT ;
    USE SIGNAL ;
    PORT
      LAYER M4 ;
        RECT  0 37.584 0.192 37.608 ;
    END
  END i_sel[183]
  PIN i_sel[184]
    DIRECTION INPUT ;
    USE SIGNAL ;
    PORT
      LAYER M4 ;
        RECT  0 37.728 0.192 37.752 ;
    END
  END i_sel[184]
  PIN i_sel[185]
    DIRECTION INPUT ;
    USE SIGNAL ;
    PORT
      LAYER M4 ;
        RECT  0 37.872 0.192 37.896 ;
    END
  END i_sel[185]
  PIN i_sel[186]
    DIRECTION INPUT ;
    USE SIGNAL ;
    PORT
      LAYER M4 ;
        RECT  0 38.016 0.192 38.04 ;
    END
  END i_sel[186]
  PIN i_sel[187]
    DIRECTION INPUT ;
    USE SIGNAL ;
    PORT
      LAYER M4 ;
        RECT  0 38.304 0.192 38.328 ;
    END
  END i_sel[187]
  PIN i_sel[188]
    DIRECTION INPUT ;
    USE SIGNAL ;
    PORT
      LAYER M4 ;
        RECT  0 38.448 0.192 38.472 ;
    END
  END i_sel[188]
  PIN i_sel[189]
    DIRECTION INPUT ;
    USE SIGNAL ;
    PORT
      LAYER M4 ;
        RECT  0 38.592 0.192 38.616 ;
    END
  END i_sel[189]
  PIN i_sel[18]
    DIRECTION INPUT ;
    USE SIGNAL ;
    PORT
      LAYER M4 ;
        RECT  0 7.92 0.192 7.944 ;
    END
  END i_sel[18]
  PIN i_sel[190]
    DIRECTION INPUT ;
    USE SIGNAL ;
    PORT
      LAYER M4 ;
        RECT  0 38.736 0.192 38.76 ;
    END
  END i_sel[190]
  PIN i_sel[191]
    DIRECTION INPUT ;
    USE SIGNAL ;
    PORT
      LAYER M4 ;
        RECT  0 39.024 0.192 39.048 ;
    END
  END i_sel[191]
  PIN i_sel[192]
    DIRECTION INPUT ;
    USE SIGNAL ;
    PORT
      LAYER M4 ;
        RECT  0 39.168 0.192 39.192 ;
    END
  END i_sel[192]
  PIN i_sel[193]
    DIRECTION INPUT ;
    USE SIGNAL ;
    PORT
      LAYER M4 ;
        RECT  0 39.312 0.192 39.336 ;
    END
  END i_sel[193]
  PIN i_sel[194]
    DIRECTION INPUT ;
    USE SIGNAL ;
    PORT
      LAYER M4 ;
        RECT  0 39.456 0.192 39.48 ;
    END
  END i_sel[194]
  PIN i_sel[195]
    DIRECTION INPUT ;
    USE SIGNAL ;
    PORT
      LAYER M4 ;
        RECT  0 39.744 0.192 39.768 ;
    END
  END i_sel[195]
  PIN i_sel[196]
    DIRECTION INPUT ;
    USE SIGNAL ;
    PORT
      LAYER M4 ;
        RECT  0 39.888 0.192 39.912 ;
    END
  END i_sel[196]
  PIN i_sel[197]
    DIRECTION INPUT ;
    USE SIGNAL ;
    PORT
      LAYER M4 ;
        RECT  0 40.032 0.192 40.056 ;
    END
  END i_sel[197]
  PIN i_sel[198]
    DIRECTION INPUT ;
    USE SIGNAL ;
    PORT
      LAYER M4 ;
        RECT  0 40.176 0.192 40.2 ;
    END
  END i_sel[198]
  PIN i_sel[199]
    DIRECTION INPUT ;
    USE SIGNAL ;
    PORT
      LAYER M4 ;
        RECT  0 40.464 0.192 40.488 ;
    END
  END i_sel[199]
  PIN i_sel[19]
    DIRECTION INPUT ;
    USE SIGNAL ;
    PORT
      LAYER M4 ;
        RECT  0 8.064 0.192 8.088 ;
    END
  END i_sel[19]
  PIN i_sel[1]
    DIRECTION INPUT ;
    USE SIGNAL ;
    PORT
      LAYER M4 ;
        RECT  0 4.896 0.192 4.92 ;
    END
  END i_sel[1]
  PIN i_sel[200]
    DIRECTION INPUT ;
    USE SIGNAL ;
    PORT
      LAYER M4 ;
        RECT  0 40.608 0.192 40.632 ;
    END
  END i_sel[200]
  PIN i_sel[201]
    DIRECTION INPUT ;
    USE SIGNAL ;
    PORT
      LAYER M4 ;
        RECT  0 40.752 0.192 40.776 ;
    END
  END i_sel[201]
  PIN i_sel[202]
    DIRECTION INPUT ;
    USE SIGNAL ;
    PORT
      LAYER M4 ;
        RECT  0 40.896 0.192 40.92 ;
    END
  END i_sel[202]
  PIN i_sel[203]
    DIRECTION INPUT ;
    USE SIGNAL ;
    PORT
      LAYER M4 ;
        RECT  0 41.184 0.192 41.208 ;
    END
  END i_sel[203]
  PIN i_sel[204]
    DIRECTION INPUT ;
    USE SIGNAL ;
    PORT
      LAYER M4 ;
        RECT  0 41.328 0.192 41.352 ;
    END
  END i_sel[204]
  PIN i_sel[205]
    DIRECTION INPUT ;
    USE SIGNAL ;
    PORT
      LAYER M4 ;
        RECT  0 41.472 0.192 41.496 ;
    END
  END i_sel[205]
  PIN i_sel[206]
    DIRECTION INPUT ;
    USE SIGNAL ;
    PORT
      LAYER M4 ;
        RECT  0 41.616 0.192 41.64 ;
    END
  END i_sel[206]
  PIN i_sel[207]
    DIRECTION INPUT ;
    USE SIGNAL ;
    PORT
      LAYER M4 ;
        RECT  0 41.904 0.192 41.928 ;
    END
  END i_sel[207]
  PIN i_sel[208]
    DIRECTION INPUT ;
    USE SIGNAL ;
    PORT
      LAYER M4 ;
        RECT  0 42.048 0.192 42.072 ;
    END
  END i_sel[208]
  PIN i_sel[209]
    DIRECTION INPUT ;
    USE SIGNAL ;
    PORT
      LAYER M4 ;
        RECT  0 42.192 0.192 42.216 ;
    END
  END i_sel[209]
  PIN i_sel[20]
    DIRECTION INPUT ;
    USE SIGNAL ;
    PORT
      LAYER M4 ;
        RECT  0 8.352 0.192 8.376 ;
    END
  END i_sel[20]
  PIN i_sel[210]
    DIRECTION INPUT ;
    USE SIGNAL ;
    PORT
      LAYER M4 ;
        RECT  0 42.336 0.192 42.36 ;
    END
  END i_sel[210]
  PIN i_sel[211]
    DIRECTION INPUT ;
    USE SIGNAL ;
    PORT
      LAYER M4 ;
        RECT  0 42.624 0.192 42.648 ;
    END
  END i_sel[211]
  PIN i_sel[212]
    DIRECTION INPUT ;
    USE SIGNAL ;
    PORT
      LAYER M4 ;
        RECT  0 42.768 0.192 42.792 ;
    END
  END i_sel[212]
  PIN i_sel[213]
    DIRECTION INPUT ;
    USE SIGNAL ;
    PORT
      LAYER M4 ;
        RECT  0 42.912 0.192 42.936 ;
    END
  END i_sel[213]
  PIN i_sel[214]
    DIRECTION INPUT ;
    USE SIGNAL ;
    PORT
      LAYER M4 ;
        RECT  0 43.056 0.192 43.08 ;
    END
  END i_sel[214]
  PIN i_sel[215]
    DIRECTION INPUT ;
    USE SIGNAL ;
    PORT
      LAYER M4 ;
        RECT  0 43.344 0.192 43.368 ;
    END
  END i_sel[215]
  PIN i_sel[216]
    DIRECTION INPUT ;
    USE SIGNAL ;
    PORT
      LAYER M4 ;
        RECT  0 43.488 0.192 43.512 ;
    END
  END i_sel[216]
  PIN i_sel[217]
    DIRECTION INPUT ;
    USE SIGNAL ;
    PORT
      LAYER M4 ;
        RECT  0 43.632 0.192 43.656 ;
    END
  END i_sel[217]
  PIN i_sel[218]
    DIRECTION INPUT ;
    USE SIGNAL ;
    PORT
      LAYER M4 ;
        RECT  0 43.776 0.192 43.8 ;
    END
  END i_sel[218]
  PIN i_sel[219]
    DIRECTION INPUT ;
    USE SIGNAL ;
    PORT
      LAYER M4 ;
        RECT  0 44.064 0.192 44.088 ;
    END
  END i_sel[219]
  PIN i_sel[21]
    DIRECTION INPUT ;
    USE SIGNAL ;
    PORT
      LAYER M4 ;
        RECT  0 8.496 0.192 8.52 ;
    END
  END i_sel[21]
  PIN i_sel[220]
    DIRECTION INPUT ;
    USE SIGNAL ;
    PORT
      LAYER M4 ;
        RECT  0 44.208 0.192 44.232 ;
    END
  END i_sel[220]
  PIN i_sel[221]
    DIRECTION INPUT ;
    USE SIGNAL ;
    PORT
      LAYER M4 ;
        RECT  0 44.352 0.192 44.376 ;
    END
  END i_sel[221]
  PIN i_sel[222]
    DIRECTION INPUT ;
    USE SIGNAL ;
    PORT
      LAYER M4 ;
        RECT  0 44.496 0.192 44.52 ;
    END
  END i_sel[222]
  PIN i_sel[223]
    DIRECTION INPUT ;
    USE SIGNAL ;
    PORT
      LAYER M4 ;
        RECT  0 44.784 0.192 44.808 ;
    END
  END i_sel[223]
  PIN i_sel[224]
    DIRECTION INPUT ;
    USE SIGNAL ;
    PORT
      LAYER M4 ;
        RECT  0 44.928 0.192 44.952 ;
    END
  END i_sel[224]
  PIN i_sel[225]
    DIRECTION INPUT ;
    USE SIGNAL ;
    PORT
      LAYER M4 ;
        RECT  0 45.072 0.192 45.096 ;
    END
  END i_sel[225]
  PIN i_sel[226]
    DIRECTION INPUT ;
    USE SIGNAL ;
    PORT
      LAYER M4 ;
        RECT  0 45.216 0.192 45.24 ;
    END
  END i_sel[226]
  PIN i_sel[227]
    DIRECTION INPUT ;
    USE SIGNAL ;
    PORT
      LAYER M4 ;
        RECT  0 45.504 0.192 45.528 ;
    END
  END i_sel[227]
  PIN i_sel[228]
    DIRECTION INPUT ;
    USE SIGNAL ;
    PORT
      LAYER M4 ;
        RECT  0 45.648 0.192 45.672 ;
    END
  END i_sel[228]
  PIN i_sel[229]
    DIRECTION INPUT ;
    USE SIGNAL ;
    PORT
      LAYER M4 ;
        RECT  0 45.792 0.192 45.816 ;
    END
  END i_sel[229]
  PIN i_sel[22]
    DIRECTION INPUT ;
    USE SIGNAL ;
    PORT
      LAYER M4 ;
        RECT  0 8.64 0.192 8.664 ;
    END
  END i_sel[22]
  PIN i_sel[230]
    DIRECTION INPUT ;
    USE SIGNAL ;
    PORT
      LAYER M4 ;
        RECT  0 45.936 0.192 45.96 ;
    END
  END i_sel[230]
  PIN i_sel[231]
    DIRECTION INPUT ;
    USE SIGNAL ;
    PORT
      LAYER M4 ;
        RECT  0 46.224 0.192 46.248 ;
    END
  END i_sel[231]
  PIN i_sel[232]
    DIRECTION INPUT ;
    USE SIGNAL ;
    PORT
      LAYER M4 ;
        RECT  0 46.368 0.192 46.392 ;
    END
  END i_sel[232]
  PIN i_sel[233]
    DIRECTION INPUT ;
    USE SIGNAL ;
    PORT
      LAYER M4 ;
        RECT  0 46.512 0.192 46.536 ;
    END
  END i_sel[233]
  PIN i_sel[234]
    DIRECTION INPUT ;
    USE SIGNAL ;
    PORT
      LAYER M4 ;
        RECT  0 46.656 0.192 46.68 ;
    END
  END i_sel[234]
  PIN i_sel[235]
    DIRECTION INPUT ;
    USE SIGNAL ;
    PORT
      LAYER M4 ;
        RECT  0 46.8 0.192 46.824 ;
    END
  END i_sel[235]
  PIN i_sel[236]
    DIRECTION INPUT ;
    USE SIGNAL ;
    PORT
      LAYER M4 ;
        RECT  0 47.088 0.192 47.112 ;
    END
  END i_sel[236]
  PIN i_sel[237]
    DIRECTION INPUT ;
    USE SIGNAL ;
    PORT
      LAYER M4 ;
        RECT  0 47.232 0.192 47.256 ;
    END
  END i_sel[237]
  PIN i_sel[238]
    DIRECTION INPUT ;
    USE SIGNAL ;
    PORT
      LAYER M4 ;
        RECT  0 47.376 0.192 47.4 ;
    END
  END i_sel[238]
  PIN i_sel[239]
    DIRECTION INPUT ;
    USE SIGNAL ;
    PORT
      LAYER M4 ;
        RECT  0 47.52 0.192 47.544 ;
    END
  END i_sel[239]
  PIN i_sel[23]
    DIRECTION INPUT ;
    USE SIGNAL ;
    PORT
      LAYER M4 ;
        RECT  0 8.784 0.192 8.808 ;
    END
  END i_sel[23]
  PIN i_sel[240]
    DIRECTION INPUT ;
    USE SIGNAL ;
    PORT
      LAYER M4 ;
        RECT  0 47.808 0.192 47.832 ;
    END
  END i_sel[240]
  PIN i_sel[241]
    DIRECTION INPUT ;
    USE SIGNAL ;
    PORT
      LAYER M4 ;
        RECT  0 47.952 0.192 47.976 ;
    END
  END i_sel[241]
  PIN i_sel[242]
    DIRECTION INPUT ;
    USE SIGNAL ;
    PORT
      LAYER M4 ;
        RECT  0 48.096 0.192 48.12 ;
    END
  END i_sel[242]
  PIN i_sel[243]
    DIRECTION INPUT ;
    USE SIGNAL ;
    PORT
      LAYER M4 ;
        RECT  0 48.24 0.192 48.264 ;
    END
  END i_sel[243]
  PIN i_sel[244]
    DIRECTION INPUT ;
    USE SIGNAL ;
    PORT
      LAYER M4 ;
        RECT  0 48.528 0.192 48.552 ;
    END
  END i_sel[244]
  PIN i_sel[245]
    DIRECTION INPUT ;
    USE SIGNAL ;
    PORT
      LAYER M4 ;
        RECT  0 48.672 0.192 48.696 ;
    END
  END i_sel[245]
  PIN i_sel[246]
    DIRECTION INPUT ;
    USE SIGNAL ;
    PORT
      LAYER M4 ;
        RECT  0 48.816 0.192 48.84 ;
    END
  END i_sel[246]
  PIN i_sel[247]
    DIRECTION INPUT ;
    USE SIGNAL ;
    PORT
      LAYER M4 ;
        RECT  0 48.96 0.192 48.984 ;
    END
  END i_sel[247]
  PIN i_sel[248]
    DIRECTION INPUT ;
    USE SIGNAL ;
    PORT
      LAYER M4 ;
        RECT  0 49.248 0.192 49.272 ;
    END
  END i_sel[248]
  PIN i_sel[249]
    DIRECTION INPUT ;
    USE SIGNAL ;
    PORT
      LAYER M4 ;
        RECT  0 49.392 0.192 49.416 ;
    END
  END i_sel[249]
  PIN i_sel[24]
    DIRECTION INPUT ;
    USE SIGNAL ;
    PORT
      LAYER M4 ;
        RECT  0 9.072 0.192 9.096 ;
    END
  END i_sel[24]
  PIN i_sel[250]
    DIRECTION INPUT ;
    USE SIGNAL ;
    PORT
      LAYER M4 ;
        RECT  0 49.536 0.192 49.56 ;
    END
  END i_sel[250]
  PIN i_sel[251]
    DIRECTION INPUT ;
    USE SIGNAL ;
    PORT
      LAYER M4 ;
        RECT  0 49.68 0.192 49.704 ;
    END
  END i_sel[251]
  PIN i_sel[252]
    DIRECTION INPUT ;
    USE SIGNAL ;
    PORT
      LAYER M4 ;
        RECT  0 49.968 0.192 49.992 ;
    END
  END i_sel[252]
  PIN i_sel[253]
    DIRECTION INPUT ;
    USE SIGNAL ;
    PORT
      LAYER M4 ;
        RECT  0 50.112 0.192 50.136 ;
    END
  END i_sel[253]
  PIN i_sel[254]
    DIRECTION INPUT ;
    USE SIGNAL ;
    PORT
      LAYER M4 ;
        RECT  0 50.256 0.192 50.28 ;
    END
  END i_sel[254]
  PIN i_sel[255]
    DIRECTION INPUT ;
    USE SIGNAL ;
    PORT
      LAYER M4 ;
        RECT  0 50.4 0.192 50.424 ;
    END
  END i_sel[255]
  PIN i_sel[256]
    DIRECTION INPUT ;
    USE SIGNAL ;
    PORT
      LAYER M4 ;
        RECT  0 50.688 0.192 50.712 ;
    END
  END i_sel[256]
  PIN i_sel[257]
    DIRECTION INPUT ;
    USE SIGNAL ;
    PORT
      LAYER M4 ;
        RECT  0 50.832 0.192 50.856 ;
    END
  END i_sel[257]
  PIN i_sel[258]
    DIRECTION INPUT ;
    USE SIGNAL ;
    PORT
      LAYER M4 ;
        RECT  0 50.976 0.192 51 ;
    END
  END i_sel[258]
  PIN i_sel[259]
    DIRECTION INPUT ;
    USE SIGNAL ;
    PORT
      LAYER M4 ;
        RECT  0 51.12 0.192 51.144 ;
    END
  END i_sel[259]
  PIN i_sel[25]
    DIRECTION INPUT ;
    USE SIGNAL ;
    PORT
      LAYER M4 ;
        RECT  0 9.216 0.192 9.24 ;
    END
  END i_sel[25]
  PIN i_sel[260]
    DIRECTION INPUT ;
    USE SIGNAL ;
    PORT
      LAYER M4 ;
        RECT  0 51.408 0.192 51.432 ;
    END
  END i_sel[260]
  PIN i_sel[261]
    DIRECTION INPUT ;
    USE SIGNAL ;
    PORT
      LAYER M4 ;
        RECT  0 51.552 0.192 51.576 ;
    END
  END i_sel[261]
  PIN i_sel[262]
    DIRECTION INPUT ;
    USE SIGNAL ;
    PORT
      LAYER M4 ;
        RECT  0 51.696 0.192 51.72 ;
    END
  END i_sel[262]
  PIN i_sel[263]
    DIRECTION INPUT ;
    USE SIGNAL ;
    PORT
      LAYER M4 ;
        RECT  0 51.84 0.192 51.864 ;
    END
  END i_sel[263]
  PIN i_sel[264]
    DIRECTION INPUT ;
    USE SIGNAL ;
    PORT
      LAYER M4 ;
        RECT  0 52.128 0.192 52.152 ;
    END
  END i_sel[264]
  PIN i_sel[265]
    DIRECTION INPUT ;
    USE SIGNAL ;
    PORT
      LAYER M4 ;
        RECT  0 52.272 0.192 52.296 ;
    END
  END i_sel[265]
  PIN i_sel[266]
    DIRECTION INPUT ;
    USE SIGNAL ;
    PORT
      LAYER M4 ;
        RECT  0 52.416 0.192 52.44 ;
    END
  END i_sel[266]
  PIN i_sel[267]
    DIRECTION INPUT ;
    USE SIGNAL ;
    PORT
      LAYER M4 ;
        RECT  0 52.56 0.192 52.584 ;
    END
  END i_sel[267]
  PIN i_sel[268]
    DIRECTION INPUT ;
    USE SIGNAL ;
    PORT
      LAYER M4 ;
        RECT  0 52.848 0.192 52.872 ;
    END
  END i_sel[268]
  PIN i_sel[269]
    DIRECTION INPUT ;
    USE SIGNAL ;
    PORT
      LAYER M4 ;
        RECT  0 52.992 0.192 53.016 ;
    END
  END i_sel[269]
  PIN i_sel[26]
    DIRECTION INPUT ;
    USE SIGNAL ;
    PORT
      LAYER M4 ;
        RECT  0 9.36 0.192 9.384 ;
    END
  END i_sel[26]
  PIN i_sel[270]
    DIRECTION INPUT ;
    USE SIGNAL ;
    PORT
      LAYER M4 ;
        RECT  0 53.136 0.192 53.16 ;
    END
  END i_sel[270]
  PIN i_sel[271]
    DIRECTION INPUT ;
    USE SIGNAL ;
    PORT
      LAYER M4 ;
        RECT  0 53.28 0.192 53.304 ;
    END
  END i_sel[271]
  PIN i_sel[272]
    DIRECTION INPUT ;
    USE SIGNAL ;
    PORT
      LAYER M4 ;
        RECT  0 53.568 0.192 53.592 ;
    END
  END i_sel[272]
  PIN i_sel[273]
    DIRECTION INPUT ;
    USE SIGNAL ;
    PORT
      LAYER M4 ;
        RECT  0 53.712 0.192 53.736 ;
    END
  END i_sel[273]
  PIN i_sel[274]
    DIRECTION INPUT ;
    USE SIGNAL ;
    PORT
      LAYER M4 ;
        RECT  0 53.856 0.192 53.88 ;
    END
  END i_sel[274]
  PIN i_sel[275]
    DIRECTION INPUT ;
    USE SIGNAL ;
    PORT
      LAYER M4 ;
        RECT  0 54 0.192 54.024 ;
    END
  END i_sel[275]
  PIN i_sel[276]
    DIRECTION INPUT ;
    USE SIGNAL ;
    PORT
      LAYER M4 ;
        RECT  0 54.288 0.192 54.312 ;
    END
  END i_sel[276]
  PIN i_sel[277]
    DIRECTION INPUT ;
    USE SIGNAL ;
    PORT
      LAYER M4 ;
        RECT  0 54.432 0.192 54.456 ;
    END
  END i_sel[277]
  PIN i_sel[278]
    DIRECTION INPUT ;
    USE SIGNAL ;
    PORT
      LAYER M4 ;
        RECT  0 54.576 0.192 54.6 ;
    END
  END i_sel[278]
  PIN i_sel[279]
    DIRECTION INPUT ;
    USE SIGNAL ;
    PORT
      LAYER M4 ;
        RECT  0 54.72 0.192 54.744 ;
    END
  END i_sel[279]
  PIN i_sel[27]
    DIRECTION INPUT ;
    USE SIGNAL ;
    PORT
      LAYER M4 ;
        RECT  0 9.504 0.192 9.528 ;
    END
  END i_sel[27]
  PIN i_sel[280]
    DIRECTION INPUT ;
    USE SIGNAL ;
    PORT
      LAYER M4 ;
        RECT  0 55.008 0.192 55.032 ;
    END
  END i_sel[280]
  PIN i_sel[281]
    DIRECTION INPUT ;
    USE SIGNAL ;
    PORT
      LAYER M4 ;
        RECT  0 55.152 0.192 55.176 ;
    END
  END i_sel[281]
  PIN i_sel[282]
    DIRECTION INPUT ;
    USE SIGNAL ;
    PORT
      LAYER M4 ;
        RECT  0 55.296 0.192 55.32 ;
    END
  END i_sel[282]
  PIN i_sel[283]
    DIRECTION INPUT ;
    USE SIGNAL ;
    PORT
      LAYER M4 ;
        RECT  0 55.44 0.192 55.464 ;
    END
  END i_sel[283]
  PIN i_sel[284]
    DIRECTION INPUT ;
    USE SIGNAL ;
    PORT
      LAYER M4 ;
        RECT  0 55.728 0.192 55.752 ;
    END
  END i_sel[284]
  PIN i_sel[285]
    DIRECTION INPUT ;
    USE SIGNAL ;
    PORT
      LAYER M4 ;
        RECT  0 55.872 0.192 55.896 ;
    END
  END i_sel[285]
  PIN i_sel[286]
    DIRECTION INPUT ;
    USE SIGNAL ;
    PORT
      LAYER M4 ;
        RECT  0 56.016 0.192 56.04 ;
    END
  END i_sel[286]
  PIN i_sel[287]
    DIRECTION INPUT ;
    USE SIGNAL ;
    PORT
      LAYER M4 ;
        RECT  0 56.16 0.192 56.184 ;
    END
  END i_sel[287]
  PIN i_sel[288]
    DIRECTION INPUT ;
    USE SIGNAL ;
    PORT
      LAYER M4 ;
        RECT  0 56.448 0.192 56.472 ;
    END
  END i_sel[288]
  PIN i_sel[289]
    DIRECTION INPUT ;
    USE SIGNAL ;
    PORT
      LAYER M4 ;
        RECT  0 56.592 0.192 56.616 ;
    END
  END i_sel[289]
  PIN i_sel[28]
    DIRECTION INPUT ;
    USE SIGNAL ;
    PORT
      LAYER M4 ;
        RECT  0 9.792 0.192 9.816 ;
    END
  END i_sel[28]
  PIN i_sel[290]
    DIRECTION INPUT ;
    USE SIGNAL ;
    PORT
      LAYER M4 ;
        RECT  0 56.736 0.192 56.76 ;
    END
  END i_sel[290]
  PIN i_sel[291]
    DIRECTION INPUT ;
    USE SIGNAL ;
    PORT
      LAYER M4 ;
        RECT  0 56.88 0.192 56.904 ;
    END
  END i_sel[291]
  PIN i_sel[292]
    DIRECTION INPUT ;
    USE SIGNAL ;
    PORT
      LAYER M4 ;
        RECT  0 57.168 0.192 57.192 ;
    END
  END i_sel[292]
  PIN i_sel[293]
    DIRECTION INPUT ;
    USE SIGNAL ;
    PORT
      LAYER M4 ;
        RECT  0 57.312 0.192 57.336 ;
    END
  END i_sel[293]
  PIN i_sel[294]
    DIRECTION INPUT ;
    USE SIGNAL ;
    PORT
      LAYER M4 ;
        RECT  0 57.456 0.192 57.48 ;
    END
  END i_sel[294]
  PIN i_sel[295]
    DIRECTION INPUT ;
    USE SIGNAL ;
    PORT
      LAYER M4 ;
        RECT  0 57.6 0.192 57.624 ;
    END
  END i_sel[295]
  PIN i_sel[296]
    DIRECTION INPUT ;
    USE SIGNAL ;
    PORT
      LAYER M4 ;
        RECT  0 57.888 0.192 57.912 ;
    END
  END i_sel[296]
  PIN i_sel[297]
    DIRECTION INPUT ;
    USE SIGNAL ;
    PORT
      LAYER M4 ;
        RECT  0 58.032 0.192 58.056 ;
    END
  END i_sel[297]
  PIN i_sel[298]
    DIRECTION INPUT ;
    USE SIGNAL ;
    PORT
      LAYER M4 ;
        RECT  0 58.176 0.192 58.2 ;
    END
  END i_sel[298]
  PIN i_sel[299]
    DIRECTION INPUT ;
    USE SIGNAL ;
    PORT
      LAYER M4 ;
        RECT  0 58.32 0.192 58.344 ;
    END
  END i_sel[299]
  PIN i_sel[29]
    DIRECTION INPUT ;
    USE SIGNAL ;
    PORT
      LAYER M4 ;
        RECT  0 9.936 0.192 9.96 ;
    END
  END i_sel[29]
  PIN i_sel[2]
    DIRECTION INPUT ;
    USE SIGNAL ;
    PORT
      LAYER M4 ;
        RECT  0 5.04 0.192 5.064 ;
    END
  END i_sel[2]
  PIN i_sel[300]
    DIRECTION INPUT ;
    USE SIGNAL ;
    PORT
      LAYER M4 ;
        RECT  0 58.608 0.192 58.632 ;
    END
  END i_sel[300]
  PIN i_sel[301]
    DIRECTION INPUT ;
    USE SIGNAL ;
    PORT
      LAYER M4 ;
        RECT  0 58.752 0.192 58.776 ;
    END
  END i_sel[301]
  PIN i_sel[302]
    DIRECTION INPUT ;
    USE SIGNAL ;
    PORT
      LAYER M4 ;
        RECT  0 58.896 0.192 58.92 ;
    END
  END i_sel[302]
  PIN i_sel[303]
    DIRECTION INPUT ;
    USE SIGNAL ;
    PORT
      LAYER M4 ;
        RECT  0 59.04 0.192 59.064 ;
    END
  END i_sel[303]
  PIN i_sel[304]
    DIRECTION INPUT ;
    USE SIGNAL ;
    PORT
      LAYER M4 ;
        RECT  0 59.184 0.192 59.208 ;
    END
  END i_sel[304]
  PIN i_sel[305]
    DIRECTION INPUT ;
    USE SIGNAL ;
    PORT
      LAYER M4 ;
        RECT  0 59.472 0.192 59.496 ;
    END
  END i_sel[305]
  PIN i_sel[306]
    DIRECTION INPUT ;
    USE SIGNAL ;
    PORT
      LAYER M4 ;
        RECT  0 59.616 0.192 59.64 ;
    END
  END i_sel[306]
  PIN i_sel[307]
    DIRECTION INPUT ;
    USE SIGNAL ;
    PORT
      LAYER M4 ;
        RECT  0 59.76 0.192 59.784 ;
    END
  END i_sel[307]
  PIN i_sel[308]
    DIRECTION INPUT ;
    USE SIGNAL ;
    PORT
      LAYER M4 ;
        RECT  0 59.904 0.192 59.928 ;
    END
  END i_sel[308]
  PIN i_sel[309]
    DIRECTION INPUT ;
    USE SIGNAL ;
    PORT
      LAYER M4 ;
        RECT  0 60.192 0.192 60.216 ;
    END
  END i_sel[309]
  PIN i_sel[30]
    DIRECTION INPUT ;
    USE SIGNAL ;
    PORT
      LAYER M4 ;
        RECT  0 10.08 0.192 10.104 ;
    END
  END i_sel[30]
  PIN i_sel[310]
    DIRECTION INPUT ;
    USE SIGNAL ;
    PORT
      LAYER M4 ;
        RECT  0 60.336 0.192 60.36 ;
    END
  END i_sel[310]
  PIN i_sel[311]
    DIRECTION INPUT ;
    USE SIGNAL ;
    PORT
      LAYER M4 ;
        RECT  0 60.48 0.192 60.504 ;
    END
  END i_sel[311]
  PIN i_sel[312]
    DIRECTION INPUT ;
    USE SIGNAL ;
    PORT
      LAYER M4 ;
        RECT  0 60.624 0.192 60.648 ;
    END
  END i_sel[312]
  PIN i_sel[313]
    DIRECTION INPUT ;
    USE SIGNAL ;
    PORT
      LAYER M4 ;
        RECT  0 60.912 0.192 60.936 ;
    END
  END i_sel[313]
  PIN i_sel[314]
    DIRECTION INPUT ;
    USE SIGNAL ;
    PORT
      LAYER M4 ;
        RECT  0 61.056 0.192 61.08 ;
    END
  END i_sel[314]
  PIN i_sel[315]
    DIRECTION INPUT ;
    USE SIGNAL ;
    PORT
      LAYER M4 ;
        RECT  0 61.2 0.192 61.224 ;
    END
  END i_sel[315]
  PIN i_sel[316]
    DIRECTION INPUT ;
    USE SIGNAL ;
    PORT
      LAYER M4 ;
        RECT  0 61.344 0.192 61.368 ;
    END
  END i_sel[316]
  PIN i_sel[317]
    DIRECTION INPUT ;
    USE SIGNAL ;
    PORT
      LAYER M4 ;
        RECT  0 61.632 0.192 61.656 ;
    END
  END i_sel[317]
  PIN i_sel[318]
    DIRECTION INPUT ;
    USE SIGNAL ;
    PORT
      LAYER M4 ;
        RECT  0 61.776 0.192 61.8 ;
    END
  END i_sel[318]
  PIN i_sel[319]
    DIRECTION INPUT ;
    USE SIGNAL ;
    PORT
      LAYER M4 ;
        RECT  0 61.92 0.192 61.944 ;
    END
  END i_sel[319]
  PIN i_sel[31]
    DIRECTION INPUT ;
    USE SIGNAL ;
    PORT
      LAYER M4 ;
        RECT  0 10.224 0.192 10.248 ;
    END
  END i_sel[31]
  PIN i_sel[320]
    DIRECTION INPUT ;
    USE SIGNAL ;
    PORT
      LAYER M4 ;
        RECT  0 62.064 0.192 62.088 ;
    END
  END i_sel[320]
  PIN i_sel[321]
    DIRECTION INPUT ;
    USE SIGNAL ;
    PORT
      LAYER M4 ;
        RECT  0 62.352 0.192 62.376 ;
    END
  END i_sel[321]
  PIN i_sel[322]
    DIRECTION INPUT ;
    USE SIGNAL ;
    PORT
      LAYER M4 ;
        RECT  0 62.496 0.192 62.52 ;
    END
  END i_sel[322]
  PIN i_sel[323]
    DIRECTION INPUT ;
    USE SIGNAL ;
    PORT
      LAYER M4 ;
        RECT  0 62.64 0.192 62.664 ;
    END
  END i_sel[323]
  PIN i_sel[324]
    DIRECTION INPUT ;
    USE SIGNAL ;
    PORT
      LAYER M4 ;
        RECT  0 62.784 0.192 62.808 ;
    END
  END i_sel[324]
  PIN i_sel[325]
    DIRECTION INPUT ;
    USE SIGNAL ;
    PORT
      LAYER M4 ;
        RECT  0 63.072 0.192 63.096 ;
    END
  END i_sel[325]
  PIN i_sel[326]
    DIRECTION INPUT ;
    USE SIGNAL ;
    PORT
      LAYER M4 ;
        RECT  0 63.216 0.192 63.24 ;
    END
  END i_sel[326]
  PIN i_sel[327]
    DIRECTION INPUT ;
    USE SIGNAL ;
    PORT
      LAYER M4 ;
        RECT  0 63.36 0.192 63.384 ;
    END
  END i_sel[327]
  PIN i_sel[328]
    DIRECTION INPUT ;
    USE SIGNAL ;
    PORT
      LAYER M4 ;
        RECT  0 63.504 0.192 63.528 ;
    END
  END i_sel[328]
  PIN i_sel[329]
    DIRECTION INPUT ;
    USE SIGNAL ;
    PORT
      LAYER M4 ;
        RECT  0 63.792 0.192 63.816 ;
    END
  END i_sel[329]
  PIN i_sel[32]
    DIRECTION INPUT ;
    USE SIGNAL ;
    PORT
      LAYER M4 ;
        RECT  0 10.368 0.192 10.392 ;
    END
  END i_sel[32]
  PIN i_sel[330]
    DIRECTION INPUT ;
    USE SIGNAL ;
    PORT
      LAYER M4 ;
        RECT  0 63.936 0.192 63.96 ;
    END
  END i_sel[330]
  PIN i_sel[331]
    DIRECTION INPUT ;
    USE SIGNAL ;
    PORT
      LAYER M4 ;
        RECT  0 64.08 0.192 64.104 ;
    END
  END i_sel[331]
  PIN i_sel[332]
    DIRECTION INPUT ;
    USE SIGNAL ;
    PORT
      LAYER M4 ;
        RECT  0 64.224 0.192 64.248 ;
    END
  END i_sel[332]
  PIN i_sel[333]
    DIRECTION INPUT ;
    USE SIGNAL ;
    PORT
      LAYER M4 ;
        RECT  0 64.512 0.192 64.536 ;
    END
  END i_sel[333]
  PIN i_sel[334]
    DIRECTION INPUT ;
    USE SIGNAL ;
    PORT
      LAYER M4 ;
        RECT  0 64.656 0.192 64.68 ;
    END
  END i_sel[334]
  PIN i_sel[335]
    DIRECTION INPUT ;
    USE SIGNAL ;
    PORT
      LAYER M4 ;
        RECT  0 64.8 0.192 64.824 ;
    END
  END i_sel[335]
  PIN i_sel[336]
    DIRECTION INPUT ;
    USE SIGNAL ;
    PORT
      LAYER M4 ;
        RECT  0 64.944 0.192 64.968 ;
    END
  END i_sel[336]
  PIN i_sel[337]
    DIRECTION INPUT ;
    USE SIGNAL ;
    PORT
      LAYER M4 ;
        RECT  0 65.232 0.192 65.256 ;
    END
  END i_sel[337]
  PIN i_sel[338]
    DIRECTION INPUT ;
    USE SIGNAL ;
    PORT
      LAYER M4 ;
        RECT  0 65.376 0.192 65.4 ;
    END
  END i_sel[338]
  PIN i_sel[339]
    DIRECTION INPUT ;
    USE SIGNAL ;
    PORT
      LAYER M4 ;
        RECT  0 65.52 0.192 65.544 ;
    END
  END i_sel[339]
  PIN i_sel[33]
    DIRECTION INPUT ;
    USE SIGNAL ;
    PORT
      LAYER M4 ;
        RECT  0 10.656 0.192 10.68 ;
    END
  END i_sel[33]
  PIN i_sel[340]
    DIRECTION INPUT ;
    USE SIGNAL ;
    PORT
      LAYER M4 ;
        RECT  0 65.664 0.192 65.688 ;
    END
  END i_sel[340]
  PIN i_sel[341]
    DIRECTION INPUT ;
    USE SIGNAL ;
    PORT
      LAYER M4 ;
        RECT  0 65.952 0.192 65.976 ;
    END
  END i_sel[341]
  PIN i_sel[342]
    DIRECTION INPUT ;
    USE SIGNAL ;
    PORT
      LAYER M4 ;
        RECT  0 66.096 0.192 66.12 ;
    END
  END i_sel[342]
  PIN i_sel[343]
    DIRECTION INPUT ;
    USE SIGNAL ;
    PORT
      LAYER M4 ;
        RECT  0 66.24 0.192 66.264 ;
    END
  END i_sel[343]
  PIN i_sel[344]
    DIRECTION INPUT ;
    USE SIGNAL ;
    PORT
      LAYER M4 ;
        RECT  0 66.384 0.192 66.408 ;
    END
  END i_sel[344]
  PIN i_sel[345]
    DIRECTION INPUT ;
    USE SIGNAL ;
    PORT
      LAYER M4 ;
        RECT  0 66.672 0.192 66.696 ;
    END
  END i_sel[345]
  PIN i_sel[346]
    DIRECTION INPUT ;
    USE SIGNAL ;
    PORT
      LAYER M4 ;
        RECT  0 66.816 0.192 66.84 ;
    END
  END i_sel[346]
  PIN i_sel[347]
    DIRECTION INPUT ;
    USE SIGNAL ;
    PORT
      LAYER M4 ;
        RECT  0 66.96 0.192 66.984 ;
    END
  END i_sel[347]
  PIN i_sel[348]
    DIRECTION INPUT ;
    USE SIGNAL ;
    PORT
      LAYER M4 ;
        RECT  0 67.104 0.192 67.128 ;
    END
  END i_sel[348]
  PIN i_sel[349]
    DIRECTION INPUT ;
    USE SIGNAL ;
    PORT
      LAYER M4 ;
        RECT  0 67.392 0.192 67.416 ;
    END
  END i_sel[349]
  PIN i_sel[34]
    DIRECTION INPUT ;
    USE SIGNAL ;
    PORT
      LAYER M4 ;
        RECT  0 10.8 0.192 10.824 ;
    END
  END i_sel[34]
  PIN i_sel[350]
    DIRECTION INPUT ;
    USE SIGNAL ;
    PORT
      LAYER M4 ;
        RECT  0 67.536 0.192 67.56 ;
    END
  END i_sel[350]
  PIN i_sel[351]
    DIRECTION INPUT ;
    USE SIGNAL ;
    PORT
      LAYER M4 ;
        RECT  0 67.68 0.192 67.704 ;
    END
  END i_sel[351]
  PIN i_sel[352]
    DIRECTION INPUT ;
    USE SIGNAL ;
    PORT
      LAYER M4 ;
        RECT  0 67.824 0.192 67.848 ;
    END
  END i_sel[352]
  PIN i_sel[353]
    DIRECTION INPUT ;
    USE SIGNAL ;
    PORT
      LAYER M4 ;
        RECT  0 68.112 0.192 68.136 ;
    END
  END i_sel[353]
  PIN i_sel[354]
    DIRECTION INPUT ;
    USE SIGNAL ;
    PORT
      LAYER M4 ;
        RECT  0 68.256 0.192 68.28 ;
    END
  END i_sel[354]
  PIN i_sel[355]
    DIRECTION INPUT ;
    USE SIGNAL ;
    PORT
      LAYER M4 ;
        RECT  0 68.4 0.192 68.424 ;
    END
  END i_sel[355]
  PIN i_sel[356]
    DIRECTION INPUT ;
    USE SIGNAL ;
    PORT
      LAYER M4 ;
        RECT  0 68.544 0.192 68.568 ;
    END
  END i_sel[356]
  PIN i_sel[357]
    DIRECTION INPUT ;
    USE SIGNAL ;
    PORT
      LAYER M4 ;
        RECT  0 68.832 0.192 68.856 ;
    END
  END i_sel[357]
  PIN i_sel[358]
    DIRECTION INPUT ;
    USE SIGNAL ;
    PORT
      LAYER M4 ;
        RECT  0 68.976 0.192 69 ;
    END
  END i_sel[358]
  PIN i_sel[359]
    DIRECTION INPUT ;
    USE SIGNAL ;
    PORT
      LAYER M4 ;
        RECT  0 69.12 0.192 69.144 ;
    END
  END i_sel[359]
  PIN i_sel[35]
    DIRECTION INPUT ;
    USE SIGNAL ;
    PORT
      LAYER M4 ;
        RECT  0 10.944 0.192 10.968 ;
    END
  END i_sel[35]
  PIN i_sel[360]
    DIRECTION INPUT ;
    USE SIGNAL ;
    PORT
      LAYER M4 ;
        RECT  0 69.264 0.192 69.288 ;
    END
  END i_sel[360]
  PIN i_sel[361]
    DIRECTION INPUT ;
    USE SIGNAL ;
    PORT
      LAYER M4 ;
        RECT  0 69.552 0.192 69.576 ;
    END
  END i_sel[361]
  PIN i_sel[362]
    DIRECTION INPUT ;
    USE SIGNAL ;
    PORT
      LAYER M4 ;
        RECT  0 69.696 0.192 69.72 ;
    END
  END i_sel[362]
  PIN i_sel[363]
    DIRECTION INPUT ;
    USE SIGNAL ;
    PORT
      LAYER M4 ;
        RECT  0 69.84 0.192 69.864 ;
    END
  END i_sel[363]
  PIN i_sel[364]
    DIRECTION INPUT ;
    USE SIGNAL ;
    PORT
      LAYER M4 ;
        RECT  0 69.984 0.192 70.008 ;
    END
  END i_sel[364]
  PIN i_sel[365]
    DIRECTION INPUT ;
    USE SIGNAL ;
    PORT
      LAYER M4 ;
        RECT  0 70.272 0.192 70.296 ;
    END
  END i_sel[365]
  PIN i_sel[366]
    DIRECTION INPUT ;
    USE SIGNAL ;
    PORT
      LAYER M4 ;
        RECT  0 70.416 0.192 70.44 ;
    END
  END i_sel[366]
  PIN i_sel[367]
    DIRECTION INPUT ;
    USE SIGNAL ;
    PORT
      LAYER M4 ;
        RECT  0 70.56 0.192 70.584 ;
    END
  END i_sel[367]
  PIN i_sel[368]
    DIRECTION INPUT ;
    USE SIGNAL ;
    PORT
      LAYER M4 ;
        RECT  0 70.704 0.192 70.728 ;
    END
  END i_sel[368]
  PIN i_sel[369]
    DIRECTION INPUT ;
    USE SIGNAL ;
    PORT
      LAYER M4 ;
        RECT  0 70.848 0.192 70.872 ;
    END
  END i_sel[369]
  PIN i_sel[36]
    DIRECTION INPUT ;
    USE SIGNAL ;
    PORT
      LAYER M4 ;
        RECT  0 11.088 0.192 11.112 ;
    END
  END i_sel[36]
  PIN i_sel[370]
    DIRECTION INPUT ;
    USE SIGNAL ;
    PORT
      LAYER M4 ;
        RECT  0 71.136 0.192 71.16 ;
    END
  END i_sel[370]
  PIN i_sel[371]
    DIRECTION INPUT ;
    USE SIGNAL ;
    PORT
      LAYER M4 ;
        RECT  0 71.28 0.192 71.304 ;
    END
  END i_sel[371]
  PIN i_sel[372]
    DIRECTION INPUT ;
    USE SIGNAL ;
    PORT
      LAYER M4 ;
        RECT  0 71.424 0.192 71.448 ;
    END
  END i_sel[372]
  PIN i_sel[373]
    DIRECTION INPUT ;
    USE SIGNAL ;
    PORT
      LAYER M4 ;
        RECT  0 71.568 0.192 71.592 ;
    END
  END i_sel[373]
  PIN i_sel[374]
    DIRECTION INPUT ;
    USE SIGNAL ;
    PORT
      LAYER M4 ;
        RECT  0 71.856 0.192 71.88 ;
    END
  END i_sel[374]
  PIN i_sel[375]
    DIRECTION INPUT ;
    USE SIGNAL ;
    PORT
      LAYER M4 ;
        RECT  0 72 0.192 72.024 ;
    END
  END i_sel[375]
  PIN i_sel[376]
    DIRECTION INPUT ;
    USE SIGNAL ;
    PORT
      LAYER M4 ;
        RECT  0 72.144 0.192 72.168 ;
    END
  END i_sel[376]
  PIN i_sel[377]
    DIRECTION INPUT ;
    USE SIGNAL ;
    PORT
      LAYER M4 ;
        RECT  0 72.288 0.192 72.312 ;
    END
  END i_sel[377]
  PIN i_sel[378]
    DIRECTION INPUT ;
    USE SIGNAL ;
    PORT
      LAYER M4 ;
        RECT  0 72.576 0.192 72.6 ;
    END
  END i_sel[378]
  PIN i_sel[379]
    DIRECTION INPUT ;
    USE SIGNAL ;
    PORT
      LAYER M4 ;
        RECT  0 72.72 0.192 72.744 ;
    END
  END i_sel[379]
  PIN i_sel[37]
    DIRECTION INPUT ;
    USE SIGNAL ;
    PORT
      LAYER M4 ;
        RECT  0 11.376 0.192 11.4 ;
    END
  END i_sel[37]
  PIN i_sel[380]
    DIRECTION INPUT ;
    USE SIGNAL ;
    PORT
      LAYER M4 ;
        RECT  0 72.864 0.192 72.888 ;
    END
  END i_sel[380]
  PIN i_sel[381]
    DIRECTION INPUT ;
    USE SIGNAL ;
    PORT
      LAYER M4 ;
        RECT  0 73.008 0.192 73.032 ;
    END
  END i_sel[381]
  PIN i_sel[382]
    DIRECTION INPUT ;
    USE SIGNAL ;
    PORT
      LAYER M4 ;
        RECT  0 73.296 0.192 73.32 ;
    END
  END i_sel[382]
  PIN i_sel[383]
    DIRECTION INPUT ;
    USE SIGNAL ;
    PORT
      LAYER M4 ;
        RECT  0 73.44 0.192 73.464 ;
    END
  END i_sel[383]
  PIN i_sel[384]
    DIRECTION INPUT ;
    USE SIGNAL ;
    PORT
      LAYER M4 ;
        RECT  0 73.584 0.192 73.608 ;
    END
  END i_sel[384]
  PIN i_sel[385]
    DIRECTION INPUT ;
    USE SIGNAL ;
    PORT
      LAYER M4 ;
        RECT  0 73.728 0.192 73.752 ;
    END
  END i_sel[385]
  PIN i_sel[386]
    DIRECTION INPUT ;
    USE SIGNAL ;
    PORT
      LAYER M4 ;
        RECT  0 74.016 0.192 74.04 ;
    END
  END i_sel[386]
  PIN i_sel[387]
    DIRECTION INPUT ;
    USE SIGNAL ;
    PORT
      LAYER M4 ;
        RECT  0 74.16 0.192 74.184 ;
    END
  END i_sel[387]
  PIN i_sel[388]
    DIRECTION INPUT ;
    USE SIGNAL ;
    PORT
      LAYER M4 ;
        RECT  0 74.304 0.192 74.328 ;
    END
  END i_sel[388]
  PIN i_sel[389]
    DIRECTION INPUT ;
    USE SIGNAL ;
    PORT
      LAYER M4 ;
        RECT  0 74.448 0.192 74.472 ;
    END
  END i_sel[389]
  PIN i_sel[38]
    DIRECTION INPUT ;
    USE SIGNAL ;
    PORT
      LAYER M4 ;
        RECT  0 11.52 0.192 11.544 ;
    END
  END i_sel[38]
  PIN i_sel[390]
    DIRECTION INPUT ;
    USE SIGNAL ;
    PORT
      LAYER M4 ;
        RECT  0 74.736 0.192 74.76 ;
    END
  END i_sel[390]
  PIN i_sel[391]
    DIRECTION INPUT ;
    USE SIGNAL ;
    PORT
      LAYER M4 ;
        RECT  0 74.88 0.192 74.904 ;
    END
  END i_sel[391]
  PIN i_sel[392]
    DIRECTION INPUT ;
    USE SIGNAL ;
    PORT
      LAYER M4 ;
        RECT  0 75.024 0.192 75.048 ;
    END
  END i_sel[392]
  PIN i_sel[393]
    DIRECTION INPUT ;
    USE SIGNAL ;
    PORT
      LAYER M4 ;
        RECT  0 75.168 0.192 75.192 ;
    END
  END i_sel[393]
  PIN i_sel[394]
    DIRECTION INPUT ;
    USE SIGNAL ;
    PORT
      LAYER M4 ;
        RECT  0 75.456 0.192 75.48 ;
    END
  END i_sel[394]
  PIN i_sel[395]
    DIRECTION INPUT ;
    USE SIGNAL ;
    PORT
      LAYER M4 ;
        RECT  0 75.6 0.192 75.624 ;
    END
  END i_sel[395]
  PIN i_sel[396]
    DIRECTION INPUT ;
    USE SIGNAL ;
    PORT
      LAYER M4 ;
        RECT  0 75.744 0.192 75.768 ;
    END
  END i_sel[396]
  PIN i_sel[397]
    DIRECTION INPUT ;
    USE SIGNAL ;
    PORT
      LAYER M4 ;
        RECT  0 75.888 0.192 75.912 ;
    END
  END i_sel[397]
  PIN i_sel[398]
    DIRECTION INPUT ;
    USE SIGNAL ;
    PORT
      LAYER M4 ;
        RECT  0 76.176 0.192 76.2 ;
    END
  END i_sel[398]
  PIN i_sel[399]
    DIRECTION INPUT ;
    USE SIGNAL ;
    PORT
      LAYER M4 ;
        RECT  0 76.32 0.192 76.344 ;
    END
  END i_sel[399]
  PIN i_sel[39]
    DIRECTION INPUT ;
    USE SIGNAL ;
    PORT
      LAYER M4 ;
        RECT  0 11.664 0.192 11.688 ;
    END
  END i_sel[39]
  PIN i_sel[3]
    DIRECTION INPUT ;
    USE SIGNAL ;
    PORT
      LAYER M4 ;
        RECT  0 5.184 0.192 5.208 ;
    END
  END i_sel[3]
  PIN i_sel[400]
    DIRECTION INPUT ;
    USE SIGNAL ;
    PORT
      LAYER M4 ;
        RECT  0 76.464 0.192 76.488 ;
    END
  END i_sel[400]
  PIN i_sel[401]
    DIRECTION INPUT ;
    USE SIGNAL ;
    PORT
      LAYER M4 ;
        RECT  0 76.608 0.192 76.632 ;
    END
  END i_sel[401]
  PIN i_sel[402]
    DIRECTION INPUT ;
    USE SIGNAL ;
    PORT
      LAYER M4 ;
        RECT  0 76.896 0.192 76.92 ;
    END
  END i_sel[402]
  PIN i_sel[403]
    DIRECTION INPUT ;
    USE SIGNAL ;
    PORT
      LAYER M4 ;
        RECT  0 77.04 0.192 77.064 ;
    END
  END i_sel[403]
  PIN i_sel[404]
    DIRECTION INPUT ;
    USE SIGNAL ;
    PORT
      LAYER M4 ;
        RECT  0 77.184 0.192 77.208 ;
    END
  END i_sel[404]
  PIN i_sel[405]
    DIRECTION INPUT ;
    USE SIGNAL ;
    PORT
      LAYER M4 ;
        RECT  0 77.328 0.192 77.352 ;
    END
  END i_sel[405]
  PIN i_sel[406]
    DIRECTION INPUT ;
    USE SIGNAL ;
    PORT
      LAYER M4 ;
        RECT  0 77.616 0.192 77.64 ;
    END
  END i_sel[406]
  PIN i_sel[407]
    DIRECTION INPUT ;
    USE SIGNAL ;
    PORT
      LAYER M4 ;
        RECT  0 77.76 0.192 77.784 ;
    END
  END i_sel[407]
  PIN i_sel[408]
    DIRECTION INPUT ;
    USE SIGNAL ;
    PORT
      LAYER M4 ;
        RECT  0 77.904 0.192 77.928 ;
    END
  END i_sel[408]
  PIN i_sel[409]
    DIRECTION INPUT ;
    USE SIGNAL ;
    PORT
      LAYER M4 ;
        RECT  0 78.048 0.192 78.072 ;
    END
  END i_sel[409]
  PIN i_sel[40]
    DIRECTION INPUT ;
    USE SIGNAL ;
    PORT
      LAYER M4 ;
        RECT  0 11.808 0.192 11.832 ;
    END
  END i_sel[40]
  PIN i_sel[410]
    DIRECTION INPUT ;
    USE SIGNAL ;
    PORT
      LAYER M4 ;
        RECT  0 78.336 0.192 78.36 ;
    END
  END i_sel[410]
  PIN i_sel[411]
    DIRECTION INPUT ;
    USE SIGNAL ;
    PORT
      LAYER M4 ;
        RECT  0 78.48 0.192 78.504 ;
    END
  END i_sel[411]
  PIN i_sel[412]
    DIRECTION INPUT ;
    USE SIGNAL ;
    PORT
      LAYER M4 ;
        RECT  0 78.624 0.192 78.648 ;
    END
  END i_sel[412]
  PIN i_sel[413]
    DIRECTION INPUT ;
    USE SIGNAL ;
    PORT
      LAYER M4 ;
        RECT  0 78.768 0.192 78.792 ;
    END
  END i_sel[413]
  PIN i_sel[414]
    DIRECTION INPUT ;
    USE SIGNAL ;
    PORT
      LAYER M4 ;
        RECT  0 79.056 0.192 79.08 ;
    END
  END i_sel[414]
  PIN i_sel[415]
    DIRECTION INPUT ;
    USE SIGNAL ;
    PORT
      LAYER M4 ;
        RECT  0 79.2 0.192 79.224 ;
    END
  END i_sel[415]
  PIN i_sel[416]
    DIRECTION INPUT ;
    USE SIGNAL ;
    PORT
      LAYER M4 ;
        RECT  0 79.344 0.192 79.368 ;
    END
  END i_sel[416]
  PIN i_sel[417]
    DIRECTION INPUT ;
    USE SIGNAL ;
    PORT
      LAYER M4 ;
        RECT  0 79.488 0.192 79.512 ;
    END
  END i_sel[417]
  PIN i_sel[418]
    DIRECTION INPUT ;
    USE SIGNAL ;
    PORT
      LAYER M4 ;
        RECT  0 79.776 0.192 79.8 ;
    END
  END i_sel[418]
  PIN i_sel[419]
    DIRECTION INPUT ;
    USE SIGNAL ;
    PORT
      LAYER M4 ;
        RECT  0 79.92 0.192 79.944 ;
    END
  END i_sel[419]
  PIN i_sel[41]
    DIRECTION INPUT ;
    USE SIGNAL ;
    PORT
      LAYER M4 ;
        RECT  0 12.096 0.192 12.12 ;
    END
  END i_sel[41]
  PIN i_sel[420]
    DIRECTION INPUT ;
    USE SIGNAL ;
    PORT
      LAYER M4 ;
        RECT  0 80.064 0.192 80.088 ;
    END
  END i_sel[420]
  PIN i_sel[421]
    DIRECTION INPUT ;
    USE SIGNAL ;
    PORT
      LAYER M4 ;
        RECT  0 80.208 0.192 80.232 ;
    END
  END i_sel[421]
  PIN i_sel[422]
    DIRECTION INPUT ;
    USE SIGNAL ;
    PORT
      LAYER M4 ;
        RECT  0 80.496 0.192 80.52 ;
    END
  END i_sel[422]
  PIN i_sel[423]
    DIRECTION INPUT ;
    USE SIGNAL ;
    PORT
      LAYER M4 ;
        RECT  0 80.64 0.192 80.664 ;
    END
  END i_sel[423]
  PIN i_sel[424]
    DIRECTION INPUT ;
    USE SIGNAL ;
    PORT
      LAYER M4 ;
        RECT  0 80.784 0.192 80.808 ;
    END
  END i_sel[424]
  PIN i_sel[425]
    DIRECTION INPUT ;
    USE SIGNAL ;
    PORT
      LAYER M4 ;
        RECT  0 80.928 0.192 80.952 ;
    END
  END i_sel[425]
  PIN i_sel[426]
    DIRECTION INPUT ;
    USE SIGNAL ;
    PORT
      LAYER M4 ;
        RECT  0 81.216 0.192 81.24 ;
    END
  END i_sel[426]
  PIN i_sel[427]
    DIRECTION INPUT ;
    USE SIGNAL ;
    PORT
      LAYER M4 ;
        RECT  0 81.36 0.192 81.384 ;
    END
  END i_sel[427]
  PIN i_sel[428]
    DIRECTION INPUT ;
    USE SIGNAL ;
    PORT
      LAYER M4 ;
        RECT  0 81.504 0.192 81.528 ;
    END
  END i_sel[428]
  PIN i_sel[429]
    DIRECTION INPUT ;
    USE SIGNAL ;
    PORT
      LAYER M4 ;
        RECT  0 81.648 0.192 81.672 ;
    END
  END i_sel[429]
  PIN i_sel[42]
    DIRECTION INPUT ;
    USE SIGNAL ;
    PORT
      LAYER M4 ;
        RECT  0 12.24 0.192 12.264 ;
    END
  END i_sel[42]
  PIN i_sel[430]
    DIRECTION INPUT ;
    USE SIGNAL ;
    PORT
      LAYER M4 ;
        RECT  0 81.936 0.192 81.96 ;
    END
  END i_sel[430]
  PIN i_sel[431]
    DIRECTION INPUT ;
    USE SIGNAL ;
    PORT
      LAYER M4 ;
        RECT  0 82.08 0.192 82.104 ;
    END
  END i_sel[431]
  PIN i_sel[432]
    DIRECTION INPUT ;
    USE SIGNAL ;
    PORT
      LAYER M4 ;
        RECT  0 82.224 0.192 82.248 ;
    END
  END i_sel[432]
  PIN i_sel[433]
    DIRECTION INPUT ;
    USE SIGNAL ;
    PORT
      LAYER M4 ;
        RECT  0 82.368 0.192 82.392 ;
    END
  END i_sel[433]
  PIN i_sel[434]
    DIRECTION INPUT ;
    USE SIGNAL ;
    PORT
      LAYER M4 ;
        RECT  0 82.656 0.192 82.68 ;
    END
  END i_sel[434]
  PIN i_sel[435]
    DIRECTION INPUT ;
    USE SIGNAL ;
    PORT
      LAYER M4 ;
        RECT  0 82.8 0.192 82.824 ;
    END
  END i_sel[435]
  PIN i_sel[436]
    DIRECTION INPUT ;
    USE SIGNAL ;
    PORT
      LAYER M4 ;
        RECT  0 82.944 0.192 82.968 ;
    END
  END i_sel[436]
  PIN i_sel[437]
    DIRECTION INPUT ;
    USE SIGNAL ;
    PORT
      LAYER M4 ;
        RECT  0 83.088 0.192 83.112 ;
    END
  END i_sel[437]
  PIN i_sel[438]
    DIRECTION INPUT ;
    USE SIGNAL ;
    PORT
      LAYER M4 ;
        RECT  0 83.232 0.192 83.256 ;
    END
  END i_sel[438]
  PIN i_sel[439]
    DIRECTION INPUT ;
    USE SIGNAL ;
    PORT
      LAYER M4 ;
        RECT  0 83.52 0.192 83.544 ;
    END
  END i_sel[439]
  PIN i_sel[43]
    DIRECTION INPUT ;
    USE SIGNAL ;
    PORT
      LAYER M4 ;
        RECT  0 12.384 0.192 12.408 ;
    END
  END i_sel[43]
  PIN i_sel[440]
    DIRECTION INPUT ;
    USE SIGNAL ;
    PORT
      LAYER M4 ;
        RECT  0 83.664 0.192 83.688 ;
    END
  END i_sel[440]
  PIN i_sel[441]
    DIRECTION INPUT ;
    USE SIGNAL ;
    PORT
      LAYER M4 ;
        RECT  0 83.808 0.192 83.832 ;
    END
  END i_sel[441]
  PIN i_sel[442]
    DIRECTION INPUT ;
    USE SIGNAL ;
    PORT
      LAYER M4 ;
        RECT  0 83.952 0.192 83.976 ;
    END
  END i_sel[442]
  PIN i_sel[443]
    DIRECTION INPUT ;
    USE SIGNAL ;
    PORT
      LAYER M4 ;
        RECT  0 84.24 0.192 84.264 ;
    END
  END i_sel[443]
  PIN i_sel[444]
    DIRECTION INPUT ;
    USE SIGNAL ;
    PORT
      LAYER M4 ;
        RECT  0 84.384 0.192 84.408 ;
    END
  END i_sel[444]
  PIN i_sel[445]
    DIRECTION INPUT ;
    USE SIGNAL ;
    PORT
      LAYER M4 ;
        RECT  0 84.528 0.192 84.552 ;
    END
  END i_sel[445]
  PIN i_sel[446]
    DIRECTION INPUT ;
    USE SIGNAL ;
    PORT
      LAYER M4 ;
        RECT  0 84.672 0.192 84.696 ;
    END
  END i_sel[446]
  PIN i_sel[447]
    DIRECTION INPUT ;
    USE SIGNAL ;
    PORT
      LAYER M4 ;
        RECT  0 84.96 0.192 84.984 ;
    END
  END i_sel[447]
  PIN i_sel[448]
    DIRECTION INPUT ;
    USE SIGNAL ;
    PORT
      LAYER M4 ;
        RECT  0 85.104 0.192 85.128 ;
    END
  END i_sel[448]
  PIN i_sel[449]
    DIRECTION INPUT ;
    USE SIGNAL ;
    PORT
      LAYER M4 ;
        RECT  0 85.248 0.192 85.272 ;
    END
  END i_sel[449]
  PIN i_sel[44]
    DIRECTION INPUT ;
    USE SIGNAL ;
    PORT
      LAYER M4 ;
        RECT  0 12.528 0.192 12.552 ;
    END
  END i_sel[44]
  PIN i_sel[450]
    DIRECTION INPUT ;
    USE SIGNAL ;
    PORT
      LAYER M4 ;
        RECT  0 85.392 0.192 85.416 ;
    END
  END i_sel[450]
  PIN i_sel[451]
    DIRECTION INPUT ;
    USE SIGNAL ;
    PORT
      LAYER M4 ;
        RECT  0 85.68 0.192 85.704 ;
    END
  END i_sel[451]
  PIN i_sel[452]
    DIRECTION INPUT ;
    USE SIGNAL ;
    PORT
      LAYER M4 ;
        RECT  0 85.824 0.192 85.848 ;
    END
  END i_sel[452]
  PIN i_sel[453]
    DIRECTION INPUT ;
    USE SIGNAL ;
    PORT
      LAYER M4 ;
        RECT  0 85.968 0.192 85.992 ;
    END
  END i_sel[453]
  PIN i_sel[454]
    DIRECTION INPUT ;
    USE SIGNAL ;
    PORT
      LAYER M4 ;
        RECT  0 86.112 0.192 86.136 ;
    END
  END i_sel[454]
  PIN i_sel[455]
    DIRECTION INPUT ;
    USE SIGNAL ;
    PORT
      LAYER M4 ;
        RECT  0 86.4 0.192 86.424 ;
    END
  END i_sel[455]
  PIN i_sel[456]
    DIRECTION INPUT ;
    USE SIGNAL ;
    PORT
      LAYER M4 ;
        RECT  0 86.544 0.192 86.568 ;
    END
  END i_sel[456]
  PIN i_sel[457]
    DIRECTION INPUT ;
    USE SIGNAL ;
    PORT
      LAYER M4 ;
        RECT  0 86.688 0.192 86.712 ;
    END
  END i_sel[457]
  PIN i_sel[458]
    DIRECTION INPUT ;
    USE SIGNAL ;
    PORT
      LAYER M4 ;
        RECT  0 86.832 0.192 86.856 ;
    END
  END i_sel[458]
  PIN i_sel[459]
    DIRECTION INPUT ;
    USE SIGNAL ;
    PORT
      LAYER M4 ;
        RECT  0 87.12 0.192 87.144 ;
    END
  END i_sel[459]
  PIN i_sel[45]
    DIRECTION INPUT ;
    USE SIGNAL ;
    PORT
      LAYER M4 ;
        RECT  0 12.816 0.192 12.84 ;
    END
  END i_sel[45]
  PIN i_sel[460]
    DIRECTION INPUT ;
    USE SIGNAL ;
    PORT
      LAYER M4 ;
        RECT  0 87.264 0.192 87.288 ;
    END
  END i_sel[460]
  PIN i_sel[461]
    DIRECTION INPUT ;
    USE SIGNAL ;
    PORT
      LAYER M4 ;
        RECT  0 87.408 0.192 87.432 ;
    END
  END i_sel[461]
  PIN i_sel[462]
    DIRECTION INPUT ;
    USE SIGNAL ;
    PORT
      LAYER M4 ;
        RECT  0 87.552 0.192 87.576 ;
    END
  END i_sel[462]
  PIN i_sel[463]
    DIRECTION INPUT ;
    USE SIGNAL ;
    PORT
      LAYER M4 ;
        RECT  0 87.84 0.192 87.864 ;
    END
  END i_sel[463]
  PIN i_sel[464]
    DIRECTION INPUT ;
    USE SIGNAL ;
    PORT
      LAYER M4 ;
        RECT  0 87.984 0.192 88.008 ;
    END
  END i_sel[464]
  PIN i_sel[465]
    DIRECTION INPUT ;
    USE SIGNAL ;
    PORT
      LAYER M4 ;
        RECT  0 88.128 0.192 88.152 ;
    END
  END i_sel[465]
  PIN i_sel[466]
    DIRECTION INPUT ;
    USE SIGNAL ;
    PORT
      LAYER M4 ;
        RECT  0 88.272 0.192 88.296 ;
    END
  END i_sel[466]
  PIN i_sel[467]
    DIRECTION INPUT ;
    USE SIGNAL ;
    PORT
      LAYER M4 ;
        RECT  0 88.56 0.192 88.584 ;
    END
  END i_sel[467]
  PIN i_sel[468]
    DIRECTION INPUT ;
    USE SIGNAL ;
    PORT
      LAYER M4 ;
        RECT  0 88.704 0.192 88.728 ;
    END
  END i_sel[468]
  PIN i_sel[469]
    DIRECTION INPUT ;
    USE SIGNAL ;
    PORT
      LAYER M4 ;
        RECT  0 88.848 0.192 88.872 ;
    END
  END i_sel[469]
  PIN i_sel[46]
    DIRECTION INPUT ;
    USE SIGNAL ;
    PORT
      LAYER M4 ;
        RECT  0 12.96 0.192 12.984 ;
    END
  END i_sel[46]
  PIN i_sel[470]
    DIRECTION INPUT ;
    USE SIGNAL ;
    PORT
      LAYER M4 ;
        RECT  0 88.992 0.192 89.016 ;
    END
  END i_sel[470]
  PIN i_sel[471]
    DIRECTION INPUT ;
    USE SIGNAL ;
    PORT
      LAYER M4 ;
        RECT  0 89.28 0.192 89.304 ;
    END
  END i_sel[471]
  PIN i_sel[472]
    DIRECTION INPUT ;
    USE SIGNAL ;
    PORT
      LAYER M4 ;
        RECT  0 89.424 0.192 89.448 ;
    END
  END i_sel[472]
  PIN i_sel[473]
    DIRECTION INPUT ;
    USE SIGNAL ;
    PORT
      LAYER M4 ;
        RECT  0 89.568 0.192 89.592 ;
    END
  END i_sel[473]
  PIN i_sel[474]
    DIRECTION INPUT ;
    USE SIGNAL ;
    PORT
      LAYER M4 ;
        RECT  0 89.712 0.192 89.736 ;
    END
  END i_sel[474]
  PIN i_sel[475]
    DIRECTION INPUT ;
    USE SIGNAL ;
    PORT
      LAYER M4 ;
        RECT  0 90 0.192 90.024 ;
    END
  END i_sel[475]
  PIN i_sel[476]
    DIRECTION INPUT ;
    USE SIGNAL ;
    PORT
      LAYER M4 ;
        RECT  0 90.144 0.192 90.168 ;
    END
  END i_sel[476]
  PIN i_sel[477]
    DIRECTION INPUT ;
    USE SIGNAL ;
    PORT
      LAYER M4 ;
        RECT  0 90.288 0.192 90.312 ;
    END
  END i_sel[477]
  PIN i_sel[478]
    DIRECTION INPUT ;
    USE SIGNAL ;
    PORT
      LAYER M4 ;
        RECT  0 90.432 0.192 90.456 ;
    END
  END i_sel[478]
  PIN i_sel[479]
    DIRECTION INPUT ;
    USE SIGNAL ;
    PORT
      LAYER M4 ;
        RECT  0 90.72 0.192 90.744 ;
    END
  END i_sel[479]
  PIN i_sel[47]
    DIRECTION INPUT ;
    USE SIGNAL ;
    PORT
      LAYER M4 ;
        RECT  0 13.104 0.192 13.128 ;
    END
  END i_sel[47]
  PIN i_sel[480]
    DIRECTION INPUT ;
    USE SIGNAL ;
    PORT
      LAYER M4 ;
        RECT  0 90.864 0.192 90.888 ;
    END
  END i_sel[480]
  PIN i_sel[481]
    DIRECTION INPUT ;
    USE SIGNAL ;
    PORT
      LAYER M4 ;
        RECT  0 91.008 0.192 91.032 ;
    END
  END i_sel[481]
  PIN i_sel[482]
    DIRECTION INPUT ;
    USE SIGNAL ;
    PORT
      LAYER M4 ;
        RECT  0 91.152 0.192 91.176 ;
    END
  END i_sel[482]
  PIN i_sel[483]
    DIRECTION INPUT ;
    USE SIGNAL ;
    PORT
      LAYER M4 ;
        RECT  0 91.44 0.192 91.464 ;
    END
  END i_sel[483]
  PIN i_sel[484]
    DIRECTION INPUT ;
    USE SIGNAL ;
    PORT
      LAYER M4 ;
        RECT  0 91.584 0.192 91.608 ;
    END
  END i_sel[484]
  PIN i_sel[485]
    DIRECTION INPUT ;
    USE SIGNAL ;
    PORT
      LAYER M4 ;
        RECT  0 91.728 0.192 91.752 ;
    END
  END i_sel[485]
  PIN i_sel[486]
    DIRECTION INPUT ;
    USE SIGNAL ;
    PORT
      LAYER M4 ;
        RECT  0 91.872 0.192 91.896 ;
    END
  END i_sel[486]
  PIN i_sel[487]
    DIRECTION INPUT ;
    USE SIGNAL ;
    PORT
      LAYER M4 ;
        RECT  0 92.16 0.192 92.184 ;
    END
  END i_sel[487]
  PIN i_sel[488]
    DIRECTION INPUT ;
    USE SIGNAL ;
    PORT
      LAYER M4 ;
        RECT  0 92.304 0.192 92.328 ;
    END
  END i_sel[488]
  PIN i_sel[489]
    DIRECTION INPUT ;
    USE SIGNAL ;
    PORT
      LAYER M4 ;
        RECT  0 92.448 0.192 92.472 ;
    END
  END i_sel[489]
  PIN i_sel[48]
    DIRECTION INPUT ;
    USE SIGNAL ;
    PORT
      LAYER M4 ;
        RECT  0 13.248 0.192 13.272 ;
    END
  END i_sel[48]
  PIN i_sel[490]
    DIRECTION INPUT ;
    USE SIGNAL ;
    PORT
      LAYER M4 ;
        RECT  0 92.592 0.192 92.616 ;
    END
  END i_sel[490]
  PIN i_sel[491]
    DIRECTION INPUT ;
    USE SIGNAL ;
    PORT
      LAYER M4 ;
        RECT  0 92.88 0.192 92.904 ;
    END
  END i_sel[491]
  PIN i_sel[492]
    DIRECTION INPUT ;
    USE SIGNAL ;
    PORT
      LAYER M4 ;
        RECT  0 93.024 0.192 93.048 ;
    END
  END i_sel[492]
  PIN i_sel[493]
    DIRECTION INPUT ;
    USE SIGNAL ;
    PORT
      LAYER M4 ;
        RECT  0 93.168 0.192 93.192 ;
    END
  END i_sel[493]
  PIN i_sel[494]
    DIRECTION INPUT ;
    USE SIGNAL ;
    PORT
      LAYER M4 ;
        RECT  0 93.312 0.192 93.336 ;
    END
  END i_sel[494]
  PIN i_sel[495]
    DIRECTION INPUT ;
    USE SIGNAL ;
    PORT
      LAYER M4 ;
        RECT  0 93.6 0.192 93.624 ;
    END
  END i_sel[495]
  PIN i_sel[496]
    DIRECTION INPUT ;
    USE SIGNAL ;
    PORT
      LAYER M4 ;
        RECT  0 93.744 0.192 93.768 ;
    END
  END i_sel[496]
  PIN i_sel[497]
    DIRECTION INPUT ;
    USE SIGNAL ;
    PORT
      LAYER M4 ;
        RECT  0 93.888 0.192 93.912 ;
    END
  END i_sel[497]
  PIN i_sel[498]
    DIRECTION INPUT ;
    USE SIGNAL ;
    PORT
      LAYER M4 ;
        RECT  0 94.032 0.192 94.056 ;
    END
  END i_sel[498]
  PIN i_sel[499]
    DIRECTION INPUT ;
    USE SIGNAL ;
    PORT
      LAYER M4 ;
        RECT  0 94.32 0.192 94.344 ;
    END
  END i_sel[499]
  PIN i_sel[49]
    DIRECTION INPUT ;
    USE SIGNAL ;
    PORT
      LAYER M4 ;
        RECT  0 13.536 0.192 13.56 ;
    END
  END i_sel[49]
  PIN i_sel[4]
    DIRECTION INPUT ;
    USE SIGNAL ;
    PORT
      LAYER M4 ;
        RECT  0 5.472 0.192 5.496 ;
    END
  END i_sel[4]
  PIN i_sel[500]
    DIRECTION INPUT ;
    USE SIGNAL ;
    PORT
      LAYER M4 ;
        RECT  0 94.464 0.192 94.488 ;
    END
  END i_sel[500]
  PIN i_sel[501]
    DIRECTION INPUT ;
    USE SIGNAL ;
    PORT
      LAYER M4 ;
        RECT  0 94.608 0.192 94.632 ;
    END
  END i_sel[501]
  PIN i_sel[502]
    DIRECTION INPUT ;
    USE SIGNAL ;
    PORT
      LAYER M4 ;
        RECT  0 94.752 0.192 94.776 ;
    END
  END i_sel[502]
  PIN i_sel[503]
    DIRECTION INPUT ;
    USE SIGNAL ;
    PORT
      LAYER M4 ;
        RECT  0 95.04 0.192 95.064 ;
    END
  END i_sel[503]
  PIN i_sel[504]
    DIRECTION INPUT ;
    USE SIGNAL ;
    PORT
      LAYER M4 ;
        RECT  0 95.184 0.192 95.208 ;
    END
  END i_sel[504]
  PIN i_sel[505]
    DIRECTION INPUT ;
    USE SIGNAL ;
    PORT
      LAYER M4 ;
        RECT  0 95.328 0.192 95.352 ;
    END
  END i_sel[505]
  PIN i_sel[506]
    DIRECTION INPUT ;
    USE SIGNAL ;
    PORT
      LAYER M4 ;
        RECT  0 95.472 0.192 95.496 ;
    END
  END i_sel[506]
  PIN i_sel[507]
    DIRECTION INPUT ;
    USE SIGNAL ;
    PORT
      LAYER M4 ;
        RECT  0 95.616 0.192 95.64 ;
    END
  END i_sel[507]
  PIN i_sel[508]
    DIRECTION INPUT ;
    USE SIGNAL ;
    PORT
      LAYER M4 ;
        RECT  0 95.904 0.192 95.928 ;
    END
  END i_sel[508]
  PIN i_sel[509]
    DIRECTION INPUT ;
    USE SIGNAL ;
    PORT
      LAYER M4 ;
        RECT  0 96.048 0.192 96.072 ;
    END
  END i_sel[509]
  PIN i_sel[50]
    DIRECTION INPUT ;
    USE SIGNAL ;
    PORT
      LAYER M4 ;
        RECT  0 13.68 0.192 13.704 ;
    END
  END i_sel[50]
  PIN i_sel[510]
    DIRECTION INPUT ;
    USE SIGNAL ;
    PORT
      LAYER M4 ;
        RECT  0 96.192 0.192 96.216 ;
    END
  END i_sel[510]
  PIN i_sel[511]
    DIRECTION INPUT ;
    USE SIGNAL ;
    PORT
      LAYER M4 ;
        RECT  0 96.336 0.192 96.36 ;
    END
  END i_sel[511]
  PIN i_sel[512]
    DIRECTION INPUT ;
    USE SIGNAL ;
    PORT
      LAYER M4 ;
        RECT  0 96.624 0.192 96.648 ;
    END
  END i_sel[512]
  PIN i_sel[513]
    DIRECTION INPUT ;
    USE SIGNAL ;
    PORT
      LAYER M4 ;
        RECT  0 96.768 0.192 96.792 ;
    END
  END i_sel[513]
  PIN i_sel[514]
    DIRECTION INPUT ;
    USE SIGNAL ;
    PORT
      LAYER M4 ;
        RECT  0 96.912 0.192 96.936 ;
    END
  END i_sel[514]
  PIN i_sel[515]
    DIRECTION INPUT ;
    USE SIGNAL ;
    PORT
      LAYER M4 ;
        RECT  0 97.056 0.192 97.08 ;
    END
  END i_sel[515]
  PIN i_sel[516]
    DIRECTION INPUT ;
    USE SIGNAL ;
    PORT
      LAYER M4 ;
        RECT  0 97.344 0.192 97.368 ;
    END
  END i_sel[516]
  PIN i_sel[517]
    DIRECTION INPUT ;
    USE SIGNAL ;
    PORT
      LAYER M4 ;
        RECT  0 97.488 0.192 97.512 ;
    END
  END i_sel[517]
  PIN i_sel[518]
    DIRECTION INPUT ;
    USE SIGNAL ;
    PORT
      LAYER M4 ;
        RECT  0 97.632 0.192 97.656 ;
    END
  END i_sel[518]
  PIN i_sel[519]
    DIRECTION INPUT ;
    USE SIGNAL ;
    PORT
      LAYER M4 ;
        RECT  0 97.776 0.192 97.8 ;
    END
  END i_sel[519]
  PIN i_sel[51]
    DIRECTION INPUT ;
    USE SIGNAL ;
    PORT
      LAYER M4 ;
        RECT  0 13.824 0.192 13.848 ;
    END
  END i_sel[51]
  PIN i_sel[520]
    DIRECTION INPUT ;
    USE SIGNAL ;
    PORT
      LAYER M4 ;
        RECT  0 98.064 0.192 98.088 ;
    END
  END i_sel[520]
  PIN i_sel[521]
    DIRECTION INPUT ;
    USE SIGNAL ;
    PORT
      LAYER M4 ;
        RECT  0 98.208 0.192 98.232 ;
    END
  END i_sel[521]
  PIN i_sel[522]
    DIRECTION INPUT ;
    USE SIGNAL ;
    PORT
      LAYER M4 ;
        RECT  0 98.352 0.192 98.376 ;
    END
  END i_sel[522]
  PIN i_sel[523]
    DIRECTION INPUT ;
    USE SIGNAL ;
    PORT
      LAYER M4 ;
        RECT  0 98.496 0.192 98.52 ;
    END
  END i_sel[523]
  PIN i_sel[524]
    DIRECTION INPUT ;
    USE SIGNAL ;
    PORT
      LAYER M4 ;
        RECT  0 98.784 0.192 98.808 ;
    END
  END i_sel[524]
  PIN i_sel[525]
    DIRECTION INPUT ;
    USE SIGNAL ;
    PORT
      LAYER M4 ;
        RECT  0 98.928 0.192 98.952 ;
    END
  END i_sel[525]
  PIN i_sel[526]
    DIRECTION INPUT ;
    USE SIGNAL ;
    PORT
      LAYER M4 ;
        RECT  0 99.072 0.192 99.096 ;
    END
  END i_sel[526]
  PIN i_sel[527]
    DIRECTION INPUT ;
    USE SIGNAL ;
    PORT
      LAYER M4 ;
        RECT  0 99.216 0.192 99.24 ;
    END
  END i_sel[527]
  PIN i_sel[528]
    DIRECTION INPUT ;
    USE SIGNAL ;
    PORT
      LAYER M4 ;
        RECT  0 99.504 0.192 99.528 ;
    END
  END i_sel[528]
  PIN i_sel[529]
    DIRECTION INPUT ;
    USE SIGNAL ;
    PORT
      LAYER M4 ;
        RECT  0 99.648 0.192 99.672 ;
    END
  END i_sel[529]
  PIN i_sel[52]
    DIRECTION INPUT ;
    USE SIGNAL ;
    PORT
      LAYER M4 ;
        RECT  0 13.968 0.192 13.992 ;
    END
  END i_sel[52]
  PIN i_sel[530]
    DIRECTION INPUT ;
    USE SIGNAL ;
    PORT
      LAYER M4 ;
        RECT  0 99.792 0.192 99.816 ;
    END
  END i_sel[530]
  PIN i_sel[531]
    DIRECTION INPUT ;
    USE SIGNAL ;
    PORT
      LAYER M4 ;
        RECT  0 99.936 0.192 99.96 ;
    END
  END i_sel[531]
  PIN i_sel[532]
    DIRECTION INPUT ;
    USE SIGNAL ;
    PORT
      LAYER M4 ;
        RECT  0 100.224 0.192 100.248 ;
    END
  END i_sel[532]
  PIN i_sel[533]
    DIRECTION INPUT ;
    USE SIGNAL ;
    PORT
      LAYER M4 ;
        RECT  0 100.368 0.192 100.392 ;
    END
  END i_sel[533]
  PIN i_sel[534]
    DIRECTION INPUT ;
    USE SIGNAL ;
    PORT
      LAYER M4 ;
        RECT  0 100.512 0.192 100.536 ;
    END
  END i_sel[534]
  PIN i_sel[535]
    DIRECTION INPUT ;
    USE SIGNAL ;
    PORT
      LAYER M4 ;
        RECT  0 100.656 0.192 100.68 ;
    END
  END i_sel[535]
  PIN i_sel[536]
    DIRECTION INPUT ;
    USE SIGNAL ;
    PORT
      LAYER M4 ;
        RECT  0 100.944 0.192 100.968 ;
    END
  END i_sel[536]
  PIN i_sel[537]
    DIRECTION INPUT ;
    USE SIGNAL ;
    PORT
      LAYER M4 ;
        RECT  0 101.088 0.192 101.112 ;
    END
  END i_sel[537]
  PIN i_sel[538]
    DIRECTION INPUT ;
    USE SIGNAL ;
    PORT
      LAYER M4 ;
        RECT  0 101.232 0.192 101.256 ;
    END
  END i_sel[538]
  PIN i_sel[539]
    DIRECTION INPUT ;
    USE SIGNAL ;
    PORT
      LAYER M4 ;
        RECT  0 101.376 0.192 101.4 ;
    END
  END i_sel[539]
  PIN i_sel[53]
    DIRECTION INPUT ;
    USE SIGNAL ;
    PORT
      LAYER M4 ;
        RECT  0 14.256 0.192 14.28 ;
    END
  END i_sel[53]
  PIN i_sel[540]
    DIRECTION INPUT ;
    USE SIGNAL ;
    PORT
      LAYER M4 ;
        RECT  0 101.664 0.192 101.688 ;
    END
  END i_sel[540]
  PIN i_sel[541]
    DIRECTION INPUT ;
    USE SIGNAL ;
    PORT
      LAYER M4 ;
        RECT  0 101.808 0.192 101.832 ;
    END
  END i_sel[541]
  PIN i_sel[542]
    DIRECTION INPUT ;
    USE SIGNAL ;
    PORT
      LAYER M4 ;
        RECT  0 101.952 0.192 101.976 ;
    END
  END i_sel[542]
  PIN i_sel[543]
    DIRECTION INPUT ;
    USE SIGNAL ;
    PORT
      LAYER M4 ;
        RECT  0 102.096 0.192 102.12 ;
    END
  END i_sel[543]
  PIN i_sel[544]
    DIRECTION INPUT ;
    USE SIGNAL ;
    PORT
      LAYER M4 ;
        RECT  0 102.384 0.192 102.408 ;
    END
  END i_sel[544]
  PIN i_sel[545]
    DIRECTION INPUT ;
    USE SIGNAL ;
    PORT
      LAYER M4 ;
        RECT  0 102.528 0.192 102.552 ;
    END
  END i_sel[545]
  PIN i_sel[546]
    DIRECTION INPUT ;
    USE SIGNAL ;
    PORT
      LAYER M4 ;
        RECT  0 102.672 0.192 102.696 ;
    END
  END i_sel[546]
  PIN i_sel[547]
    DIRECTION INPUT ;
    USE SIGNAL ;
    PORT
      LAYER M4 ;
        RECT  0 102.816 0.192 102.84 ;
    END
  END i_sel[547]
  PIN i_sel[548]
    DIRECTION INPUT ;
    USE SIGNAL ;
    PORT
      LAYER M4 ;
        RECT  0 103.104 0.192 103.128 ;
    END
  END i_sel[548]
  PIN i_sel[549]
    DIRECTION INPUT ;
    USE SIGNAL ;
    PORT
      LAYER M4 ;
        RECT  0 103.248 0.192 103.272 ;
    END
  END i_sel[549]
  PIN i_sel[54]
    DIRECTION INPUT ;
    USE SIGNAL ;
    PORT
      LAYER M4 ;
        RECT  0 14.4 0.192 14.424 ;
    END
  END i_sel[54]
  PIN i_sel[550]
    DIRECTION INPUT ;
    USE SIGNAL ;
    PORT
      LAYER M4 ;
        RECT  0 103.392 0.192 103.416 ;
    END
  END i_sel[550]
  PIN i_sel[551]
    DIRECTION INPUT ;
    USE SIGNAL ;
    PORT
      LAYER M4 ;
        RECT  0 103.536 0.192 103.56 ;
    END
  END i_sel[551]
  PIN i_sel[552]
    DIRECTION INPUT ;
    USE SIGNAL ;
    PORT
      LAYER M4 ;
        RECT  0 103.824 0.192 103.848 ;
    END
  END i_sel[552]
  PIN i_sel[553]
    DIRECTION INPUT ;
    USE SIGNAL ;
    PORT
      LAYER M4 ;
        RECT  0 103.968 0.192 103.992 ;
    END
  END i_sel[553]
  PIN i_sel[554]
    DIRECTION INPUT ;
    USE SIGNAL ;
    PORT
      LAYER M4 ;
        RECT  0 104.112 0.192 104.136 ;
    END
  END i_sel[554]
  PIN i_sel[555]
    DIRECTION INPUT ;
    USE SIGNAL ;
    PORT
      LAYER M4 ;
        RECT  0 104.256 0.192 104.28 ;
    END
  END i_sel[555]
  PIN i_sel[556]
    DIRECTION INPUT ;
    USE SIGNAL ;
    PORT
      LAYER M4 ;
        RECT  0 104.544 0.192 104.568 ;
    END
  END i_sel[556]
  PIN i_sel[557]
    DIRECTION INPUT ;
    USE SIGNAL ;
    PORT
      LAYER M4 ;
        RECT  0 104.688 0.192 104.712 ;
    END
  END i_sel[557]
  PIN i_sel[558]
    DIRECTION INPUT ;
    USE SIGNAL ;
    PORT
      LAYER M4 ;
        RECT  0 104.832 0.192 104.856 ;
    END
  END i_sel[558]
  PIN i_sel[559]
    DIRECTION INPUT ;
    USE SIGNAL ;
    PORT
      LAYER M4 ;
        RECT  0 104.976 0.192 105 ;
    END
  END i_sel[559]
  PIN i_sel[55]
    DIRECTION INPUT ;
    USE SIGNAL ;
    PORT
      LAYER M4 ;
        RECT  0 14.544 0.192 14.568 ;
    END
  END i_sel[55]
  PIN i_sel[560]
    DIRECTION INPUT ;
    USE SIGNAL ;
    PORT
      LAYER M4 ;
        RECT  0 105.264 0.192 105.288 ;
    END
  END i_sel[560]
  PIN i_sel[561]
    DIRECTION INPUT ;
    USE SIGNAL ;
    PORT
      LAYER M4 ;
        RECT  0 105.408 0.192 105.432 ;
    END
  END i_sel[561]
  PIN i_sel[562]
    DIRECTION INPUT ;
    USE SIGNAL ;
    PORT
      LAYER M4 ;
        RECT  0 105.552 0.192 105.576 ;
    END
  END i_sel[562]
  PIN i_sel[563]
    DIRECTION INPUT ;
    USE SIGNAL ;
    PORT
      LAYER M4 ;
        RECT  0 105.696 0.192 105.72 ;
    END
  END i_sel[563]
  PIN i_sel[564]
    DIRECTION INPUT ;
    USE SIGNAL ;
    PORT
      LAYER M4 ;
        RECT  0 105.984 0.192 106.008 ;
    END
  END i_sel[564]
  PIN i_sel[565]
    DIRECTION INPUT ;
    USE SIGNAL ;
    PORT
      LAYER M4 ;
        RECT  0 106.128 0.192 106.152 ;
    END
  END i_sel[565]
  PIN i_sel[566]
    DIRECTION INPUT ;
    USE SIGNAL ;
    PORT
      LAYER M4 ;
        RECT  0 106.272 0.192 106.296 ;
    END
  END i_sel[566]
  PIN i_sel[567]
    DIRECTION INPUT ;
    USE SIGNAL ;
    PORT
      LAYER M4 ;
        RECT  0 106.416 0.192 106.44 ;
    END
  END i_sel[567]
  PIN i_sel[568]
    DIRECTION INPUT ;
    USE SIGNAL ;
    PORT
      LAYER M4 ;
        RECT  0 106.704 0.192 106.728 ;
    END
  END i_sel[568]
  PIN i_sel[569]
    DIRECTION INPUT ;
    USE SIGNAL ;
    PORT
      LAYER M4 ;
        RECT  0 106.848 0.192 106.872 ;
    END
  END i_sel[569]
  PIN i_sel[56]
    DIRECTION INPUT ;
    USE SIGNAL ;
    PORT
      LAYER M4 ;
        RECT  0 14.688 0.192 14.712 ;
    END
  END i_sel[56]
  PIN i_sel[570]
    DIRECTION INPUT ;
    USE SIGNAL ;
    PORT
      LAYER M4 ;
        RECT  0 106.992 0.192 107.016 ;
    END
  END i_sel[570]
  PIN i_sel[571]
    DIRECTION INPUT ;
    USE SIGNAL ;
    PORT
      LAYER M4 ;
        RECT  0 107.136 0.192 107.16 ;
    END
  END i_sel[571]
  PIN i_sel[572]
    DIRECTION INPUT ;
    USE SIGNAL ;
    PORT
      LAYER M4 ;
        RECT  0 107.28 0.192 107.304 ;
    END
  END i_sel[572]
  PIN i_sel[573]
    DIRECTION INPUT ;
    USE SIGNAL ;
    PORT
      LAYER M4 ;
        RECT  0 107.568 0.192 107.592 ;
    END
  END i_sel[573]
  PIN i_sel[574]
    DIRECTION INPUT ;
    USE SIGNAL ;
    PORT
      LAYER M4 ;
        RECT  0 107.712 0.192 107.736 ;
    END
  END i_sel[574]
  PIN i_sel[575]
    DIRECTION INPUT ;
    USE SIGNAL ;
    PORT
      LAYER M4 ;
        RECT  0 107.856 0.192 107.88 ;
    END
  END i_sel[575]
  PIN i_sel[576]
    DIRECTION INPUT ;
    USE SIGNAL ;
    PORT
      LAYER M4 ;
        RECT  0 108 0.192 108.024 ;
    END
  END i_sel[576]
  PIN i_sel[577]
    DIRECTION INPUT ;
    USE SIGNAL ;
    PORT
      LAYER M4 ;
        RECT  0 108.288 0.192 108.312 ;
    END
  END i_sel[577]
  PIN i_sel[578]
    DIRECTION INPUT ;
    USE SIGNAL ;
    PORT
      LAYER M4 ;
        RECT  0 108.432 0.192 108.456 ;
    END
  END i_sel[578]
  PIN i_sel[579]
    DIRECTION INPUT ;
    USE SIGNAL ;
    PORT
      LAYER M4 ;
        RECT  0 108.576 0.192 108.6 ;
    END
  END i_sel[579]
  PIN i_sel[57]
    DIRECTION INPUT ;
    USE SIGNAL ;
    PORT
      LAYER M4 ;
        RECT  0 14.976 0.192 15 ;
    END
  END i_sel[57]
  PIN i_sel[580]
    DIRECTION INPUT ;
    USE SIGNAL ;
    PORT
      LAYER M4 ;
        RECT  0 108.72 0.192 108.744 ;
    END
  END i_sel[580]
  PIN i_sel[581]
    DIRECTION INPUT ;
    USE SIGNAL ;
    PORT
      LAYER M4 ;
        RECT  0 109.008 0.192 109.032 ;
    END
  END i_sel[581]
  PIN i_sel[582]
    DIRECTION INPUT ;
    USE SIGNAL ;
    PORT
      LAYER M4 ;
        RECT  0 109.152 0.192 109.176 ;
    END
  END i_sel[582]
  PIN i_sel[583]
    DIRECTION INPUT ;
    USE SIGNAL ;
    PORT
      LAYER M4 ;
        RECT  0 109.296 0.192 109.32 ;
    END
  END i_sel[583]
  PIN i_sel[584]
    DIRECTION INPUT ;
    USE SIGNAL ;
    PORT
      LAYER M4 ;
        RECT  0 109.44 0.192 109.464 ;
    END
  END i_sel[584]
  PIN i_sel[585]
    DIRECTION INPUT ;
    USE SIGNAL ;
    PORT
      LAYER M4 ;
        RECT  0 109.728 0.192 109.752 ;
    END
  END i_sel[585]
  PIN i_sel[586]
    DIRECTION INPUT ;
    USE SIGNAL ;
    PORT
      LAYER M4 ;
        RECT  0 109.872 0.192 109.896 ;
    END
  END i_sel[586]
  PIN i_sel[587]
    DIRECTION INPUT ;
    USE SIGNAL ;
    PORT
      LAYER M4 ;
        RECT  0 110.016 0.192 110.04 ;
    END
  END i_sel[587]
  PIN i_sel[588]
    DIRECTION INPUT ;
    USE SIGNAL ;
    PORT
      LAYER M4 ;
        RECT  0 110.16 0.192 110.184 ;
    END
  END i_sel[588]
  PIN i_sel[589]
    DIRECTION INPUT ;
    USE SIGNAL ;
    PORT
      LAYER M4 ;
        RECT  0 110.448 0.192 110.472 ;
    END
  END i_sel[589]
  PIN i_sel[58]
    DIRECTION INPUT ;
    USE SIGNAL ;
    PORT
      LAYER M4 ;
        RECT  0 15.12 0.192 15.144 ;
    END
  END i_sel[58]
  PIN i_sel[590]
    DIRECTION INPUT ;
    USE SIGNAL ;
    PORT
      LAYER M4 ;
        RECT  0 110.592 0.192 110.616 ;
    END
  END i_sel[590]
  PIN i_sel[591]
    DIRECTION INPUT ;
    USE SIGNAL ;
    PORT
      LAYER M4 ;
        RECT  0 110.736 0.192 110.76 ;
    END
  END i_sel[591]
  PIN i_sel[592]
    DIRECTION INPUT ;
    USE SIGNAL ;
    PORT
      LAYER M4 ;
        RECT  0 110.88 0.192 110.904 ;
    END
  END i_sel[592]
  PIN i_sel[593]
    DIRECTION INPUT ;
    USE SIGNAL ;
    PORT
      LAYER M4 ;
        RECT  0 111.168 0.192 111.192 ;
    END
  END i_sel[593]
  PIN i_sel[594]
    DIRECTION INPUT ;
    USE SIGNAL ;
    PORT
      LAYER M4 ;
        RECT  0 111.312 0.192 111.336 ;
    END
  END i_sel[594]
  PIN i_sel[595]
    DIRECTION INPUT ;
    USE SIGNAL ;
    PORT
      LAYER M4 ;
        RECT  0 111.456 0.192 111.48 ;
    END
  END i_sel[595]
  PIN i_sel[596]
    DIRECTION INPUT ;
    USE SIGNAL ;
    PORT
      LAYER M4 ;
        RECT  0 111.6 0.192 111.624 ;
    END
  END i_sel[596]
  PIN i_sel[597]
    DIRECTION INPUT ;
    USE SIGNAL ;
    PORT
      LAYER M4 ;
        RECT  0 111.888 0.192 111.912 ;
    END
  END i_sel[597]
  PIN i_sel[598]
    DIRECTION INPUT ;
    USE SIGNAL ;
    PORT
      LAYER M4 ;
        RECT  0 112.032 0.192 112.056 ;
    END
  END i_sel[598]
  PIN i_sel[599]
    DIRECTION INPUT ;
    USE SIGNAL ;
    PORT
      LAYER M4 ;
        RECT  0 112.176 0.192 112.2 ;
    END
  END i_sel[599]
  PIN i_sel[59]
    DIRECTION INPUT ;
    USE SIGNAL ;
    PORT
      LAYER M4 ;
        RECT  0 15.264 0.192 15.288 ;
    END
  END i_sel[59]
  PIN i_sel[5]
    DIRECTION INPUT ;
    USE SIGNAL ;
    PORT
      LAYER M4 ;
        RECT  0 5.616 0.192 5.64 ;
    END
  END i_sel[5]
  PIN i_sel[600]
    DIRECTION INPUT ;
    USE SIGNAL ;
    PORT
      LAYER M4 ;
        RECT  0 112.32 0.192 112.344 ;
    END
  END i_sel[600]
  PIN i_sel[601]
    DIRECTION INPUT ;
    USE SIGNAL ;
    PORT
      LAYER M4 ;
        RECT  0 112.608 0.192 112.632 ;
    END
  END i_sel[601]
  PIN i_sel[602]
    DIRECTION INPUT ;
    USE SIGNAL ;
    PORT
      LAYER M4 ;
        RECT  0 112.752 0.192 112.776 ;
    END
  END i_sel[602]
  PIN i_sel[603]
    DIRECTION INPUT ;
    USE SIGNAL ;
    PORT
      LAYER M4 ;
        RECT  0 112.896 0.192 112.92 ;
    END
  END i_sel[603]
  PIN i_sel[604]
    DIRECTION INPUT ;
    USE SIGNAL ;
    PORT
      LAYER M4 ;
        RECT  0 113.04 0.192 113.064 ;
    END
  END i_sel[604]
  PIN i_sel[605]
    DIRECTION INPUT ;
    USE SIGNAL ;
    PORT
      LAYER M4 ;
        RECT  0 113.328 0.192 113.352 ;
    END
  END i_sel[605]
  PIN i_sel[606]
    DIRECTION INPUT ;
    USE SIGNAL ;
    PORT
      LAYER M4 ;
        RECT  0 113.472 0.192 113.496 ;
    END
  END i_sel[606]
  PIN i_sel[607]
    DIRECTION INPUT ;
    USE SIGNAL ;
    PORT
      LAYER M4 ;
        RECT  0 113.616 0.192 113.64 ;
    END
  END i_sel[607]
  PIN i_sel[608]
    DIRECTION INPUT ;
    USE SIGNAL ;
    PORT
      LAYER M4 ;
        RECT  0 113.76 0.192 113.784 ;
    END
  END i_sel[608]
  PIN i_sel[609]
    DIRECTION INPUT ;
    USE SIGNAL ;
    PORT
      LAYER M4 ;
        RECT  0 114.048 0.192 114.072 ;
    END
  END i_sel[609]
  PIN i_sel[60]
    DIRECTION INPUT ;
    USE SIGNAL ;
    PORT
      LAYER M4 ;
        RECT  0 15.408 0.192 15.432 ;
    END
  END i_sel[60]
  PIN i_sel[610]
    DIRECTION INPUT ;
    USE SIGNAL ;
    PORT
      LAYER M4 ;
        RECT  0 114.192 0.192 114.216 ;
    END
  END i_sel[610]
  PIN i_sel[611]
    DIRECTION INPUT ;
    USE SIGNAL ;
    PORT
      LAYER M4 ;
        RECT  0 114.336 0.192 114.36 ;
    END
  END i_sel[611]
  PIN i_sel[612]
    DIRECTION INPUT ;
    USE SIGNAL ;
    PORT
      LAYER M4 ;
        RECT  0 114.48 0.192 114.504 ;
    END
  END i_sel[612]
  PIN i_sel[613]
    DIRECTION INPUT ;
    USE SIGNAL ;
    PORT
      LAYER M4 ;
        RECT  0 114.768 0.192 114.792 ;
    END
  END i_sel[613]
  PIN i_sel[614]
    DIRECTION INPUT ;
    USE SIGNAL ;
    PORT
      LAYER M4 ;
        RECT  0 114.912 0.192 114.936 ;
    END
  END i_sel[614]
  PIN i_sel[615]
    DIRECTION INPUT ;
    USE SIGNAL ;
    PORT
      LAYER M4 ;
        RECT  0 115.056 0.192 115.08 ;
    END
  END i_sel[615]
  PIN i_sel[616]
    DIRECTION INPUT ;
    USE SIGNAL ;
    PORT
      LAYER M4 ;
        RECT  0 115.2 0.192 115.224 ;
    END
  END i_sel[616]
  PIN i_sel[617]
    DIRECTION INPUT ;
    USE SIGNAL ;
    PORT
      LAYER M4 ;
        RECT  0 115.488 0.192 115.512 ;
    END
  END i_sel[617]
  PIN i_sel[618]
    DIRECTION INPUT ;
    USE SIGNAL ;
    PORT
      LAYER M4 ;
        RECT  0 115.632 0.192 115.656 ;
    END
  END i_sel[618]
  PIN i_sel[619]
    DIRECTION INPUT ;
    USE SIGNAL ;
    PORT
      LAYER M4 ;
        RECT  0 115.776 0.192 115.8 ;
    END
  END i_sel[619]
  PIN i_sel[61]
    DIRECTION INPUT ;
    USE SIGNAL ;
    PORT
      LAYER M4 ;
        RECT  0 15.696 0.192 15.72 ;
    END
  END i_sel[61]
  PIN i_sel[620]
    DIRECTION INPUT ;
    USE SIGNAL ;
    PORT
      LAYER M4 ;
        RECT  0 115.92 0.192 115.944 ;
    END
  END i_sel[620]
  PIN i_sel[621]
    DIRECTION INPUT ;
    USE SIGNAL ;
    PORT
      LAYER M4 ;
        RECT  0 116.208 0.192 116.232 ;
    END
  END i_sel[621]
  PIN i_sel[622]
    DIRECTION INPUT ;
    USE SIGNAL ;
    PORT
      LAYER M4 ;
        RECT  0 116.352 0.192 116.376 ;
    END
  END i_sel[622]
  PIN i_sel[623]
    DIRECTION INPUT ;
    USE SIGNAL ;
    PORT
      LAYER M4 ;
        RECT  0 116.496 0.192 116.52 ;
    END
  END i_sel[623]
  PIN i_sel[624]
    DIRECTION INPUT ;
    USE SIGNAL ;
    PORT
      LAYER M4 ;
        RECT  0 116.64 0.192 116.664 ;
    END
  END i_sel[624]
  PIN i_sel[625]
    DIRECTION INPUT ;
    USE SIGNAL ;
    PORT
      LAYER M4 ;
        RECT  0 116.928 0.192 116.952 ;
    END
  END i_sel[625]
  PIN i_sel[626]
    DIRECTION INPUT ;
    USE SIGNAL ;
    PORT
      LAYER M4 ;
        RECT  0 117.072 0.192 117.096 ;
    END
  END i_sel[626]
  PIN i_sel[627]
    DIRECTION INPUT ;
    USE SIGNAL ;
    PORT
      LAYER M4 ;
        RECT  0 117.216 0.192 117.24 ;
    END
  END i_sel[627]
  PIN i_sel[628]
    DIRECTION INPUT ;
    USE SIGNAL ;
    PORT
      LAYER M4 ;
        RECT  0 117.36 0.192 117.384 ;
    END
  END i_sel[628]
  PIN i_sel[629]
    DIRECTION INPUT ;
    USE SIGNAL ;
    PORT
      LAYER M4 ;
        RECT  0 117.648 0.192 117.672 ;
    END
  END i_sel[629]
  PIN i_sel[62]
    DIRECTION INPUT ;
    USE SIGNAL ;
    PORT
      LAYER M4 ;
        RECT  0 15.84 0.192 15.864 ;
    END
  END i_sel[62]
  PIN i_sel[630]
    DIRECTION INPUT ;
    USE SIGNAL ;
    PORT
      LAYER M4 ;
        RECT  0 117.792 0.192 117.816 ;
    END
  END i_sel[630]
  PIN i_sel[631]
    DIRECTION INPUT ;
    USE SIGNAL ;
    PORT
      LAYER M4 ;
        RECT  0 117.936 0.192 117.96 ;
    END
  END i_sel[631]
  PIN i_sel[632]
    DIRECTION INPUT ;
    USE SIGNAL ;
    PORT
      LAYER M4 ;
        RECT  0 118.08 0.192 118.104 ;
    END
  END i_sel[632]
  PIN i_sel[633]
    DIRECTION INPUT ;
    USE SIGNAL ;
    PORT
      LAYER M4 ;
        RECT  0 118.368 0.192 118.392 ;
    END
  END i_sel[633]
  PIN i_sel[634]
    DIRECTION INPUT ;
    USE SIGNAL ;
    PORT
      LAYER M4 ;
        RECT  0 118.512 0.192 118.536 ;
    END
  END i_sel[634]
  PIN i_sel[635]
    DIRECTION INPUT ;
    USE SIGNAL ;
    PORT
      LAYER M4 ;
        RECT  0 118.656 0.192 118.68 ;
    END
  END i_sel[635]
  PIN i_sel[636]
    DIRECTION INPUT ;
    USE SIGNAL ;
    PORT
      LAYER M4 ;
        RECT  0 118.8 0.192 118.824 ;
    END
  END i_sel[636]
  PIN i_sel[637]
    DIRECTION INPUT ;
    USE SIGNAL ;
    PORT
      LAYER M4 ;
        RECT  0 119.088 0.192 119.112 ;
    END
  END i_sel[637]
  PIN i_sel[638]
    DIRECTION INPUT ;
    USE SIGNAL ;
    PORT
      LAYER M4 ;
        RECT  0 119.232 0.192 119.256 ;
    END
  END i_sel[638]
  PIN i_sel[639]
    DIRECTION INPUT ;
    USE SIGNAL ;
    PORT
      LAYER M4 ;
        RECT  0 119.376 0.192 119.4 ;
    END
  END i_sel[639]
  PIN i_sel[63]
    DIRECTION INPUT ;
    USE SIGNAL ;
    PORT
      LAYER M4 ;
        RECT  0 15.984 0.192 16.008 ;
    END
  END i_sel[63]
  PIN i_sel[640]
    DIRECTION INPUT ;
    USE SIGNAL ;
    PORT
      LAYER M4 ;
        RECT  0 119.52 0.192 119.544 ;
    END
  END i_sel[640]
  PIN i_sel[641]
    DIRECTION INPUT ;
    USE SIGNAL ;
    PORT
      LAYER M4 ;
        RECT  0 119.664 0.192 119.688 ;
    END
  END i_sel[641]
  PIN i_sel[642]
    DIRECTION INPUT ;
    USE SIGNAL ;
    PORT
      LAYER M4 ;
        RECT  0 119.952 0.192 119.976 ;
    END
  END i_sel[642]
  PIN i_sel[643]
    DIRECTION INPUT ;
    USE SIGNAL ;
    PORT
      LAYER M4 ;
        RECT  0 120.096 0.192 120.12 ;
    END
  END i_sel[643]
  PIN i_sel[644]
    DIRECTION INPUT ;
    USE SIGNAL ;
    PORT
      LAYER M4 ;
        RECT  0 120.24 0.192 120.264 ;
    END
  END i_sel[644]
  PIN i_sel[645]
    DIRECTION INPUT ;
    USE SIGNAL ;
    PORT
      LAYER M4 ;
        RECT  0 120.384 0.192 120.408 ;
    END
  END i_sel[645]
  PIN i_sel[646]
    DIRECTION INPUT ;
    USE SIGNAL ;
    PORT
      LAYER M4 ;
        RECT  0 120.672 0.192 120.696 ;
    END
  END i_sel[646]
  PIN i_sel[647]
    DIRECTION INPUT ;
    USE SIGNAL ;
    PORT
      LAYER M4 ;
        RECT  0 120.816 0.192 120.84 ;
    END
  END i_sel[647]
  PIN i_sel[648]
    DIRECTION INPUT ;
    USE SIGNAL ;
    PORT
      LAYER M4 ;
        RECT  0 120.96 0.192 120.984 ;
    END
  END i_sel[648]
  PIN i_sel[649]
    DIRECTION INPUT ;
    USE SIGNAL ;
    PORT
      LAYER M4 ;
        RECT  0 121.104 0.192 121.128 ;
    END
  END i_sel[649]
  PIN i_sel[64]
    DIRECTION INPUT ;
    USE SIGNAL ;
    PORT
      LAYER M4 ;
        RECT  0 16.128 0.192 16.152 ;
    END
  END i_sel[64]
  PIN i_sel[650]
    DIRECTION INPUT ;
    USE SIGNAL ;
    PORT
      LAYER M4 ;
        RECT  0 121.392 0.192 121.416 ;
    END
  END i_sel[650]
  PIN i_sel[651]
    DIRECTION INPUT ;
    USE SIGNAL ;
    PORT
      LAYER M4 ;
        RECT  0 121.536 0.192 121.56 ;
    END
  END i_sel[651]
  PIN i_sel[652]
    DIRECTION INPUT ;
    USE SIGNAL ;
    PORT
      LAYER M4 ;
        RECT  0 121.68 0.192 121.704 ;
    END
  END i_sel[652]
  PIN i_sel[653]
    DIRECTION INPUT ;
    USE SIGNAL ;
    PORT
      LAYER M4 ;
        RECT  0 121.824 0.192 121.848 ;
    END
  END i_sel[653]
  PIN i_sel[654]
    DIRECTION INPUT ;
    USE SIGNAL ;
    PORT
      LAYER M4 ;
        RECT  0 122.112 0.192 122.136 ;
    END
  END i_sel[654]
  PIN i_sel[655]
    DIRECTION INPUT ;
    USE SIGNAL ;
    PORT
      LAYER M4 ;
        RECT  0 122.256 0.192 122.28 ;
    END
  END i_sel[655]
  PIN i_sel[656]
    DIRECTION INPUT ;
    USE SIGNAL ;
    PORT
      LAYER M4 ;
        RECT  0 122.4 0.192 122.424 ;
    END
  END i_sel[656]
  PIN i_sel[657]
    DIRECTION INPUT ;
    USE SIGNAL ;
    PORT
      LAYER M4 ;
        RECT  0 122.544 0.192 122.568 ;
    END
  END i_sel[657]
  PIN i_sel[658]
    DIRECTION INPUT ;
    USE SIGNAL ;
    PORT
      LAYER M4 ;
        RECT  0 122.832 0.192 122.856 ;
    END
  END i_sel[658]
  PIN i_sel[659]
    DIRECTION INPUT ;
    USE SIGNAL ;
    PORT
      LAYER M4 ;
        RECT  0 122.976 0.192 123 ;
    END
  END i_sel[659]
  PIN i_sel[65]
    DIRECTION INPUT ;
    USE SIGNAL ;
    PORT
      LAYER M4 ;
        RECT  0 16.416 0.192 16.44 ;
    END
  END i_sel[65]
  PIN i_sel[660]
    DIRECTION INPUT ;
    USE SIGNAL ;
    PORT
      LAYER M4 ;
        RECT  0 123.12 0.192 123.144 ;
    END
  END i_sel[660]
  PIN i_sel[661]
    DIRECTION INPUT ;
    USE SIGNAL ;
    PORT
      LAYER M4 ;
        RECT  0 123.264 0.192 123.288 ;
    END
  END i_sel[661]
  PIN i_sel[662]
    DIRECTION INPUT ;
    USE SIGNAL ;
    PORT
      LAYER M4 ;
        RECT  0 123.552 0.192 123.576 ;
    END
  END i_sel[662]
  PIN i_sel[663]
    DIRECTION INPUT ;
    USE SIGNAL ;
    PORT
      LAYER M4 ;
        RECT  0 123.696 0.192 123.72 ;
    END
  END i_sel[663]
  PIN i_sel[664]
    DIRECTION INPUT ;
    USE SIGNAL ;
    PORT
      LAYER M4 ;
        RECT  0 123.84 0.192 123.864 ;
    END
  END i_sel[664]
  PIN i_sel[665]
    DIRECTION INPUT ;
    USE SIGNAL ;
    PORT
      LAYER M4 ;
        RECT  0 123.984 0.192 124.008 ;
    END
  END i_sel[665]
  PIN i_sel[666]
    DIRECTION INPUT ;
    USE SIGNAL ;
    PORT
      LAYER M4 ;
        RECT  0 124.272 0.192 124.296 ;
    END
  END i_sel[666]
  PIN i_sel[667]
    DIRECTION INPUT ;
    USE SIGNAL ;
    PORT
      LAYER M4 ;
        RECT  0 124.416 0.192 124.44 ;
    END
  END i_sel[667]
  PIN i_sel[668]
    DIRECTION INPUT ;
    USE SIGNAL ;
    PORT
      LAYER M4 ;
        RECT  0 124.56 0.192 124.584 ;
    END
  END i_sel[668]
  PIN i_sel[669]
    DIRECTION INPUT ;
    USE SIGNAL ;
    PORT
      LAYER M4 ;
        RECT  0 124.704 0.192 124.728 ;
    END
  END i_sel[669]
  PIN i_sel[66]
    DIRECTION INPUT ;
    USE SIGNAL ;
    PORT
      LAYER M4 ;
        RECT  0 16.56 0.192 16.584 ;
    END
  END i_sel[66]
  PIN i_sel[670]
    DIRECTION INPUT ;
    USE SIGNAL ;
    PORT
      LAYER M4 ;
        RECT  0 124.992 0.192 125.016 ;
    END
  END i_sel[670]
  PIN i_sel[671]
    DIRECTION INPUT ;
    USE SIGNAL ;
    PORT
      LAYER M4 ;
        RECT  0 125.136 0.192 125.16 ;
    END
  END i_sel[671]
  PIN i_sel[67]
    DIRECTION INPUT ;
    USE SIGNAL ;
    PORT
      LAYER M4 ;
        RECT  0 16.704 0.192 16.728 ;
    END
  END i_sel[67]
  PIN i_sel[68]
    DIRECTION INPUT ;
    USE SIGNAL ;
    PORT
      LAYER M4 ;
        RECT  0 16.848 0.192 16.872 ;
    END
  END i_sel[68]
  PIN i_sel[69]
    DIRECTION INPUT ;
    USE SIGNAL ;
    PORT
      LAYER M4 ;
        RECT  0 17.136 0.192 17.16 ;
    END
  END i_sel[69]
  PIN i_sel[6]
    DIRECTION INPUT ;
    USE SIGNAL ;
    PORT
      LAYER M4 ;
        RECT  0 5.76 0.192 5.784 ;
    END
  END i_sel[6]
  PIN i_sel[70]
    DIRECTION INPUT ;
    USE SIGNAL ;
    PORT
      LAYER M4 ;
        RECT  0 17.28 0.192 17.304 ;
    END
  END i_sel[70]
  PIN i_sel[71]
    DIRECTION INPUT ;
    USE SIGNAL ;
    PORT
      LAYER M4 ;
        RECT  0 17.424 0.192 17.448 ;
    END
  END i_sel[71]
  PIN i_sel[72]
    DIRECTION INPUT ;
    USE SIGNAL ;
    PORT
      LAYER M4 ;
        RECT  0 17.568 0.192 17.592 ;
    END
  END i_sel[72]
  PIN i_sel[73]
    DIRECTION INPUT ;
    USE SIGNAL ;
    PORT
      LAYER M4 ;
        RECT  0 17.856 0.192 17.88 ;
    END
  END i_sel[73]
  PIN i_sel[74]
    DIRECTION INPUT ;
    USE SIGNAL ;
    PORT
      LAYER M4 ;
        RECT  0 18 0.192 18.024 ;
    END
  END i_sel[74]
  PIN i_sel[75]
    DIRECTION INPUT ;
    USE SIGNAL ;
    PORT
      LAYER M4 ;
        RECT  0 18.144 0.192 18.168 ;
    END
  END i_sel[75]
  PIN i_sel[76]
    DIRECTION INPUT ;
    USE SIGNAL ;
    PORT
      LAYER M4 ;
        RECT  0 18.288 0.192 18.312 ;
    END
  END i_sel[76]
  PIN i_sel[77]
    DIRECTION INPUT ;
    USE SIGNAL ;
    PORT
      LAYER M4 ;
        RECT  0 18.576 0.192 18.6 ;
    END
  END i_sel[77]
  PIN i_sel[78]
    DIRECTION INPUT ;
    USE SIGNAL ;
    PORT
      LAYER M4 ;
        RECT  0 18.72 0.192 18.744 ;
    END
  END i_sel[78]
  PIN i_sel[79]
    DIRECTION INPUT ;
    USE SIGNAL ;
    PORT
      LAYER M4 ;
        RECT  0 18.864 0.192 18.888 ;
    END
  END i_sel[79]
  PIN i_sel[7]
    DIRECTION INPUT ;
    USE SIGNAL ;
    PORT
      LAYER M4 ;
        RECT  0 5.904 0.192 5.928 ;
    END
  END i_sel[7]
  PIN i_sel[80]
    DIRECTION INPUT ;
    USE SIGNAL ;
    PORT
      LAYER M4 ;
        RECT  0 19.008 0.192 19.032 ;
    END
  END i_sel[80]
  PIN i_sel[81]
    DIRECTION INPUT ;
    USE SIGNAL ;
    PORT
      LAYER M4 ;
        RECT  0 19.296 0.192 19.32 ;
    END
  END i_sel[81]
  PIN i_sel[82]
    DIRECTION INPUT ;
    USE SIGNAL ;
    PORT
      LAYER M4 ;
        RECT  0 19.44 0.192 19.464 ;
    END
  END i_sel[82]
  PIN i_sel[83]
    DIRECTION INPUT ;
    USE SIGNAL ;
    PORT
      LAYER M4 ;
        RECT  0 19.584 0.192 19.608 ;
    END
  END i_sel[83]
  PIN i_sel[84]
    DIRECTION INPUT ;
    USE SIGNAL ;
    PORT
      LAYER M4 ;
        RECT  0 19.728 0.192 19.752 ;
    END
  END i_sel[84]
  PIN i_sel[85]
    DIRECTION INPUT ;
    USE SIGNAL ;
    PORT
      LAYER M4 ;
        RECT  0 20.016 0.192 20.04 ;
    END
  END i_sel[85]
  PIN i_sel[86]
    DIRECTION INPUT ;
    USE SIGNAL ;
    PORT
      LAYER M4 ;
        RECT  0 20.16 0.192 20.184 ;
    END
  END i_sel[86]
  PIN i_sel[87]
    DIRECTION INPUT ;
    USE SIGNAL ;
    PORT
      LAYER M4 ;
        RECT  0 20.304 0.192 20.328 ;
    END
  END i_sel[87]
  PIN i_sel[88]
    DIRECTION INPUT ;
    USE SIGNAL ;
    PORT
      LAYER M4 ;
        RECT  0 20.448 0.192 20.472 ;
    END
  END i_sel[88]
  PIN i_sel[89]
    DIRECTION INPUT ;
    USE SIGNAL ;
    PORT
      LAYER M4 ;
        RECT  0 20.736 0.192 20.76 ;
    END
  END i_sel[89]
  PIN i_sel[8]
    DIRECTION INPUT ;
    USE SIGNAL ;
    PORT
      LAYER M4 ;
        RECT  0 6.192 0.192 6.216 ;
    END
  END i_sel[8]
  PIN i_sel[90]
    DIRECTION INPUT ;
    USE SIGNAL ;
    PORT
      LAYER M4 ;
        RECT  0 20.88 0.192 20.904 ;
    END
  END i_sel[90]
  PIN i_sel[91]
    DIRECTION INPUT ;
    USE SIGNAL ;
    PORT
      LAYER M4 ;
        RECT  0 21.024 0.192 21.048 ;
    END
  END i_sel[91]
  PIN i_sel[92]
    DIRECTION INPUT ;
    USE SIGNAL ;
    PORT
      LAYER M4 ;
        RECT  0 21.168 0.192 21.192 ;
    END
  END i_sel[92]
  PIN i_sel[93]
    DIRECTION INPUT ;
    USE SIGNAL ;
    PORT
      LAYER M4 ;
        RECT  0 21.456 0.192 21.48 ;
    END
  END i_sel[93]
  PIN i_sel[94]
    DIRECTION INPUT ;
    USE SIGNAL ;
    PORT
      LAYER M4 ;
        RECT  0 21.6 0.192 21.624 ;
    END
  END i_sel[94]
  PIN i_sel[95]
    DIRECTION INPUT ;
    USE SIGNAL ;
    PORT
      LAYER M4 ;
        RECT  0 21.744 0.192 21.768 ;
    END
  END i_sel[95]
  PIN i_sel[96]
    DIRECTION INPUT ;
    USE SIGNAL ;
    PORT
      LAYER M4 ;
        RECT  0 21.888 0.192 21.912 ;
    END
  END i_sel[96]
  PIN i_sel[97]
    DIRECTION INPUT ;
    USE SIGNAL ;
    PORT
      LAYER M4 ;
        RECT  0 22.176 0.192 22.2 ;
    END
  END i_sel[97]
  PIN i_sel[98]
    DIRECTION INPUT ;
    USE SIGNAL ;
    PORT
      LAYER M4 ;
        RECT  0 22.32 0.192 22.344 ;
    END
  END i_sel[98]
  PIN i_sel[99]
    DIRECTION INPUT ;
    USE SIGNAL ;
    PORT
      LAYER M4 ;
        RECT  0 22.464 0.192 22.488 ;
    END
  END i_sel[99]
  PIN i_sel[9]
    DIRECTION INPUT ;
    USE SIGNAL ;
    PORT
      LAYER M4 ;
        RECT  0 6.336 0.192 6.36 ;
    END
  END i_sel[9]
  PIN o_data[0]
    DIRECTION OUTPUT ;
    USE SIGNAL ;
    PORT
      LAYER M5 ;
        RECT  4.464 129.408 4.488 129.6 ;
    END
  END o_data[0]
  PIN o_data[100]
    DIRECTION OUTPUT ;
    USE SIGNAL ;
    PORT
      LAYER M5 ;
        RECT  52.944 129.408 52.968 129.6 ;
    END
  END o_data[100]
  PIN o_data[101]
    DIRECTION OUTPUT ;
    USE SIGNAL ;
    PORT
      LAYER M5 ;
        RECT  53.376 129.408 53.4 129.6 ;
    END
  END o_data[101]
  PIN o_data[102]
    DIRECTION OUTPUT ;
    USE SIGNAL ;
    PORT
      LAYER M5 ;
        RECT  53.808 129.408 53.832 129.6 ;
    END
  END o_data[102]
  PIN o_data[103]
    DIRECTION OUTPUT ;
    USE SIGNAL ;
    PORT
      LAYER M5 ;
        RECT  54.768 129.408 54.792 129.6 ;
    END
  END o_data[103]
  PIN o_data[104]
    DIRECTION OUTPUT ;
    USE SIGNAL ;
    PORT
      LAYER M5 ;
        RECT  55.2 129.408 55.224 129.6 ;
    END
  END o_data[104]
  PIN o_data[105]
    DIRECTION OUTPUT ;
    USE SIGNAL ;
    PORT
      LAYER M5 ;
        RECT  55.632 129.408 55.656 129.6 ;
    END
  END o_data[105]
  PIN o_data[106]
    DIRECTION OUTPUT ;
    USE SIGNAL ;
    PORT
      LAYER M5 ;
        RECT  56.064 129.408 56.088 129.6 ;
    END
  END o_data[106]
  PIN o_data[107]
    DIRECTION OUTPUT ;
    USE SIGNAL ;
    PORT
      LAYER M5 ;
        RECT  56.496 129.408 56.52 129.6 ;
    END
  END o_data[107]
  PIN o_data[108]
    DIRECTION OUTPUT ;
    USE SIGNAL ;
    PORT
      LAYER M5 ;
        RECT  56.928 129.408 56.952 129.6 ;
    END
  END o_data[108]
  PIN o_data[109]
    DIRECTION OUTPUT ;
    USE SIGNAL ;
    PORT
      LAYER M5 ;
        RECT  57.36 129.408 57.384 129.6 ;
    END
  END o_data[109]
  PIN o_data[10]
    DIRECTION OUTPUT ;
    USE SIGNAL ;
    PORT
      LAYER M5 ;
        RECT  9.456 129.408 9.48 129.6 ;
    END
  END o_data[10]
  PIN o_data[110]
    DIRECTION OUTPUT ;
    USE SIGNAL ;
    PORT
      LAYER M5 ;
        RECT  57.936 129.408 57.96 129.6 ;
    END
  END o_data[110]
  PIN o_data[111]
    DIRECTION OUTPUT ;
    USE SIGNAL ;
    PORT
      LAYER M5 ;
        RECT  58.368 129.408 58.392 129.6 ;
    END
  END o_data[111]
  PIN o_data[112]
    DIRECTION OUTPUT ;
    USE SIGNAL ;
    PORT
      LAYER M5 ;
        RECT  58.8 129.408 58.824 129.6 ;
    END
  END o_data[112]
  PIN o_data[113]
    DIRECTION OUTPUT ;
    USE SIGNAL ;
    PORT
      LAYER M5 ;
        RECT  59.232 129.408 59.256 129.6 ;
    END
  END o_data[113]
  PIN o_data[114]
    DIRECTION OUTPUT ;
    USE SIGNAL ;
    PORT
      LAYER M5 ;
        RECT  60.144 129.408 60.168 129.6 ;
    END
  END o_data[114]
  PIN o_data[115]
    DIRECTION OUTPUT ;
    USE SIGNAL ;
    PORT
      LAYER M5 ;
        RECT  60.576 129.408 60.6 129.6 ;
    END
  END o_data[115]
  PIN o_data[116]
    DIRECTION OUTPUT ;
    USE SIGNAL ;
    PORT
      LAYER M5 ;
        RECT  61.008 129.408 61.032 129.6 ;
    END
  END o_data[116]
  PIN o_data[117]
    DIRECTION OUTPUT ;
    USE SIGNAL ;
    PORT
      LAYER M5 ;
        RECT  61.44 129.408 61.464 129.6 ;
    END
  END o_data[117]
  PIN o_data[118]
    DIRECTION OUTPUT ;
    USE SIGNAL ;
    PORT
      LAYER M5 ;
        RECT  61.872 129.408 61.896 129.6 ;
    END
  END o_data[118]
  PIN o_data[119]
    DIRECTION OUTPUT ;
    USE SIGNAL ;
    PORT
      LAYER M5 ;
        RECT  62.304 129.408 62.328 129.6 ;
    END
  END o_data[119]
  PIN o_data[11]
    DIRECTION OUTPUT ;
    USE SIGNAL ;
    PORT
      LAYER M5 ;
        RECT  9.888 129.408 9.912 129.6 ;
    END
  END o_data[11]
  PIN o_data[120]
    DIRECTION OUTPUT ;
    USE SIGNAL ;
    PORT
      LAYER M5 ;
        RECT  62.736 129.408 62.76 129.6 ;
    END
  END o_data[120]
  PIN o_data[121]
    DIRECTION OUTPUT ;
    USE SIGNAL ;
    PORT
      LAYER M5 ;
        RECT  63.168 129.408 63.192 129.6 ;
    END
  END o_data[121]
  PIN o_data[122]
    DIRECTION OUTPUT ;
    USE SIGNAL ;
    PORT
      LAYER M5 ;
        RECT  63.6 129.408 63.624 129.6 ;
    END
  END o_data[122]
  PIN o_data[123]
    DIRECTION OUTPUT ;
    USE SIGNAL ;
    PORT
      LAYER M5 ;
        RECT  64.032 129.408 64.056 129.6 ;
    END
  END o_data[123]
  PIN o_data[124]
    DIRECTION OUTPUT ;
    USE SIGNAL ;
    PORT
      LAYER M5 ;
        RECT  64.464 129.408 64.488 129.6 ;
    END
  END o_data[124]
  PIN o_data[125]
    DIRECTION OUTPUT ;
    USE SIGNAL ;
    PORT
      LAYER M5 ;
        RECT  64.896 129.408 64.92 129.6 ;
    END
  END o_data[125]
  PIN o_data[126]
    DIRECTION OUTPUT ;
    USE SIGNAL ;
    PORT
      LAYER M5 ;
        RECT  65.856 129.408 65.88 129.6 ;
    END
  END o_data[126]
  PIN o_data[127]
    DIRECTION OUTPUT ;
    USE SIGNAL ;
    PORT
      LAYER M5 ;
        RECT  66.288 129.408 66.312 129.6 ;
    END
  END o_data[127]
  PIN o_data[12]
    DIRECTION OUTPUT ;
    USE SIGNAL ;
    PORT
      LAYER M5 ;
        RECT  10.32 129.408 10.344 129.6 ;
    END
  END o_data[12]
  PIN o_data[13]
    DIRECTION OUTPUT ;
    USE SIGNAL ;
    PORT
      LAYER M5 ;
        RECT  10.752 129.408 10.776 129.6 ;
    END
  END o_data[13]
  PIN o_data[14]
    DIRECTION OUTPUT ;
    USE SIGNAL ;
    PORT
      LAYER M5 ;
        RECT  11.712 129.408 11.736 129.6 ;
    END
  END o_data[14]
  PIN o_data[15]
    DIRECTION OUTPUT ;
    USE SIGNAL ;
    PORT
      LAYER M5 ;
        RECT  12.144 129.408 12.168 129.6 ;
    END
  END o_data[15]
  PIN o_data[16]
    DIRECTION OUTPUT ;
    USE SIGNAL ;
    PORT
      LAYER M5 ;
        RECT  12.576 129.408 12.6 129.6 ;
    END
  END o_data[16]
  PIN o_data[17]
    DIRECTION OUTPUT ;
    USE SIGNAL ;
    PORT
      LAYER M5 ;
        RECT  13.008 129.408 13.032 129.6 ;
    END
  END o_data[17]
  PIN o_data[18]
    DIRECTION OUTPUT ;
    USE SIGNAL ;
    PORT
      LAYER M5 ;
        RECT  13.44 129.408 13.464 129.6 ;
    END
  END o_data[18]
  PIN o_data[19]
    DIRECTION OUTPUT ;
    USE SIGNAL ;
    PORT
      LAYER M5 ;
        RECT  13.872 129.408 13.896 129.6 ;
    END
  END o_data[19]
  PIN o_data[1]
    DIRECTION OUTPUT ;
    USE SIGNAL ;
    PORT
      LAYER M5 ;
        RECT  4.896 129.408 4.92 129.6 ;
    END
  END o_data[1]
  PIN o_data[20]
    DIRECTION OUTPUT ;
    USE SIGNAL ;
    PORT
      LAYER M5 ;
        RECT  14.304 129.408 14.328 129.6 ;
    END
  END o_data[20]
  PIN o_data[21]
    DIRECTION OUTPUT ;
    USE SIGNAL ;
    PORT
      LAYER M5 ;
        RECT  14.736 129.408 14.76 129.6 ;
    END
  END o_data[21]
  PIN o_data[22]
    DIRECTION OUTPUT ;
    USE SIGNAL ;
    PORT
      LAYER M5 ;
        RECT  15.168 129.408 15.192 129.6 ;
    END
  END o_data[22]
  PIN o_data[23]
    DIRECTION OUTPUT ;
    USE SIGNAL ;
    PORT
      LAYER M5 ;
        RECT  15.6 129.408 15.624 129.6 ;
    END
  END o_data[23]
  PIN o_data[24]
    DIRECTION OUTPUT ;
    USE SIGNAL ;
    PORT
      LAYER M5 ;
        RECT  16.032 129.408 16.056 129.6 ;
    END
  END o_data[24]
  PIN o_data[25]
    DIRECTION OUTPUT ;
    USE SIGNAL ;
    PORT
      LAYER M5 ;
        RECT  16.944 129.408 16.968 129.6 ;
    END
  END o_data[25]
  PIN o_data[26]
    DIRECTION OUTPUT ;
    USE SIGNAL ;
    PORT
      LAYER M5 ;
        RECT  17.376 129.408 17.4 129.6 ;
    END
  END o_data[26]
  PIN o_data[27]
    DIRECTION OUTPUT ;
    USE SIGNAL ;
    PORT
      LAYER M5 ;
        RECT  17.808 129.408 17.832 129.6 ;
    END
  END o_data[27]
  PIN o_data[28]
    DIRECTION OUTPUT ;
    USE SIGNAL ;
    PORT
      LAYER M5 ;
        RECT  18.24 129.408 18.264 129.6 ;
    END
  END o_data[28]
  PIN o_data[29]
    DIRECTION OUTPUT ;
    USE SIGNAL ;
    PORT
      LAYER M5 ;
        RECT  18.672 129.408 18.696 129.6 ;
    END
  END o_data[29]
  PIN o_data[2]
    DIRECTION OUTPUT ;
    USE SIGNAL ;
    PORT
      LAYER M5 ;
        RECT  5.328 129.408 5.352 129.6 ;
    END
  END o_data[2]
  PIN o_data[30]
    DIRECTION OUTPUT ;
    USE SIGNAL ;
    PORT
      LAYER M5 ;
        RECT  19.248 129.408 19.272 129.6 ;
    END
  END o_data[30]
  PIN o_data[31]
    DIRECTION OUTPUT ;
    USE SIGNAL ;
    PORT
      LAYER M5 ;
        RECT  19.68 129.408 19.704 129.6 ;
    END
  END o_data[31]
  PIN o_data[32]
    DIRECTION OUTPUT ;
    USE SIGNAL ;
    PORT
      LAYER M5 ;
        RECT  20.112 129.408 20.136 129.6 ;
    END
  END o_data[32]
  PIN o_data[33]
    DIRECTION OUTPUT ;
    USE SIGNAL ;
    PORT
      LAYER M5 ;
        RECT  20.544 129.408 20.568 129.6 ;
    END
  END o_data[33]
  PIN o_data[34]
    DIRECTION OUTPUT ;
    USE SIGNAL ;
    PORT
      LAYER M5 ;
        RECT  20.976 129.408 21 129.6 ;
    END
  END o_data[34]
  PIN o_data[35]
    DIRECTION OUTPUT ;
    USE SIGNAL ;
    PORT
      LAYER M5 ;
        RECT  21.408 129.408 21.432 129.6 ;
    END
  END o_data[35]
  PIN o_data[36]
    DIRECTION OUTPUT ;
    USE SIGNAL ;
    PORT
      LAYER M5 ;
        RECT  22.368 129.408 22.392 129.6 ;
    END
  END o_data[36]
  PIN o_data[37]
    DIRECTION OUTPUT ;
    USE SIGNAL ;
    PORT
      LAYER M5 ;
        RECT  22.8 129.408 22.824 129.6 ;
    END
  END o_data[37]
  PIN o_data[38]
    DIRECTION OUTPUT ;
    USE SIGNAL ;
    PORT
      LAYER M5 ;
        RECT  23.232 129.408 23.256 129.6 ;
    END
  END o_data[38]
  PIN o_data[39]
    DIRECTION OUTPUT ;
    USE SIGNAL ;
    PORT
      LAYER M5 ;
        RECT  23.664 129.408 23.688 129.6 ;
    END
  END o_data[39]
  PIN o_data[3]
    DIRECTION OUTPUT ;
    USE SIGNAL ;
    PORT
      LAYER M5 ;
        RECT  6.288 129.408 6.312 129.6 ;
    END
  END o_data[3]
  PIN o_data[40]
    DIRECTION OUTPUT ;
    USE SIGNAL ;
    PORT
      LAYER M5 ;
        RECT  24.096 129.408 24.12 129.6 ;
    END
  END o_data[40]
  PIN o_data[41]
    DIRECTION OUTPUT ;
    USE SIGNAL ;
    PORT
      LAYER M5 ;
        RECT  24.528 129.408 24.552 129.6 ;
    END
  END o_data[41]
  PIN o_data[42]
    DIRECTION OUTPUT ;
    USE SIGNAL ;
    PORT
      LAYER M5 ;
        RECT  24.96 129.408 24.984 129.6 ;
    END
  END o_data[42]
  PIN o_data[43]
    DIRECTION OUTPUT ;
    USE SIGNAL ;
    PORT
      LAYER M5 ;
        RECT  25.392 129.408 25.416 129.6 ;
    END
  END o_data[43]
  PIN o_data[44]
    DIRECTION OUTPUT ;
    USE SIGNAL ;
    PORT
      LAYER M5 ;
        RECT  25.824 129.408 25.848 129.6 ;
    END
  END o_data[44]
  PIN o_data[45]
    DIRECTION OUTPUT ;
    USE SIGNAL ;
    PORT
      LAYER M5 ;
        RECT  26.256 129.408 26.28 129.6 ;
    END
  END o_data[45]
  PIN o_data[46]
    DIRECTION OUTPUT ;
    USE SIGNAL ;
    PORT
      LAYER M5 ;
        RECT  26.688 129.408 26.712 129.6 ;
    END
  END o_data[46]
  PIN o_data[47]
    DIRECTION OUTPUT ;
    USE SIGNAL ;
    PORT
      LAYER M5 ;
        RECT  27.12 129.408 27.144 129.6 ;
    END
  END o_data[47]
  PIN o_data[48]
    DIRECTION OUTPUT ;
    USE SIGNAL ;
    PORT
      LAYER M5 ;
        RECT  28.032 129.408 28.056 129.6 ;
    END
  END o_data[48]
  PIN o_data[49]
    DIRECTION OUTPUT ;
    USE SIGNAL ;
    PORT
      LAYER M5 ;
        RECT  28.464 129.408 28.488 129.6 ;
    END
  END o_data[49]
  PIN o_data[4]
    DIRECTION OUTPUT ;
    USE SIGNAL ;
    PORT
      LAYER M5 ;
        RECT  6.72 129.408 6.744 129.6 ;
    END
  END o_data[4]
  PIN o_data[50]
    DIRECTION OUTPUT ;
    USE SIGNAL ;
    PORT
      LAYER M5 ;
        RECT  29.04 129.408 29.064 129.6 ;
    END
  END o_data[50]
  PIN o_data[51]
    DIRECTION OUTPUT ;
    USE SIGNAL ;
    PORT
      LAYER M5 ;
        RECT  29.472 129.408 29.496 129.6 ;
    END
  END o_data[51]
  PIN o_data[52]
    DIRECTION OUTPUT ;
    USE SIGNAL ;
    PORT
      LAYER M5 ;
        RECT  29.904 129.408 29.928 129.6 ;
    END
  END o_data[52]
  PIN o_data[53]
    DIRECTION OUTPUT ;
    USE SIGNAL ;
    PORT
      LAYER M5 ;
        RECT  30.336 129.408 30.36 129.6 ;
    END
  END o_data[53]
  PIN o_data[54]
    DIRECTION OUTPUT ;
    USE SIGNAL ;
    PORT
      LAYER M5 ;
        RECT  30.768 129.408 30.792 129.6 ;
    END
  END o_data[54]
  PIN o_data[55]
    DIRECTION OUTPUT ;
    USE SIGNAL ;
    PORT
      LAYER M5 ;
        RECT  31.2 129.408 31.224 129.6 ;
    END
  END o_data[55]
  PIN o_data[56]
    DIRECTION OUTPUT ;
    USE SIGNAL ;
    PORT
      LAYER M5 ;
        RECT  31.632 129.408 31.656 129.6 ;
    END
  END o_data[56]
  PIN o_data[57]
    DIRECTION OUTPUT ;
    USE SIGNAL ;
    PORT
      LAYER M5 ;
        RECT  32.064 129.408 32.088 129.6 ;
    END
  END o_data[57]
  PIN o_data[58]
    DIRECTION OUTPUT ;
    USE SIGNAL ;
    PORT
      LAYER M5 ;
        RECT  32.496 129.408 32.52 129.6 ;
    END
  END o_data[58]
  PIN o_data[59]
    DIRECTION OUTPUT ;
    USE SIGNAL ;
    PORT
      LAYER M5 ;
        RECT  33.456 129.408 33.48 129.6 ;
    END
  END o_data[59]
  PIN o_data[5]
    DIRECTION OUTPUT ;
    USE SIGNAL ;
    PORT
      LAYER M5 ;
        RECT  7.152 129.408 7.176 129.6 ;
    END
  END o_data[5]
  PIN o_data[60]
    DIRECTION OUTPUT ;
    USE SIGNAL ;
    PORT
      LAYER M5 ;
        RECT  33.888 129.408 33.912 129.6 ;
    END
  END o_data[60]
  PIN o_data[61]
    DIRECTION OUTPUT ;
    USE SIGNAL ;
    PORT
      LAYER M5 ;
        RECT  34.32 129.408 34.344 129.6 ;
    END
  END o_data[61]
  PIN o_data[62]
    DIRECTION OUTPUT ;
    USE SIGNAL ;
    PORT
      LAYER M5 ;
        RECT  34.752 129.408 34.776 129.6 ;
    END
  END o_data[62]
  PIN o_data[63]
    DIRECTION OUTPUT ;
    USE SIGNAL ;
    PORT
      LAYER M5 ;
        RECT  35.184 129.408 35.208 129.6 ;
    END
  END o_data[63]
  PIN o_data[64]
    DIRECTION OUTPUT ;
    USE SIGNAL ;
    PORT
      LAYER M5 ;
        RECT  35.616 129.408 35.64 129.6 ;
    END
  END o_data[64]
  PIN o_data[65]
    DIRECTION OUTPUT ;
    USE SIGNAL ;
    PORT
      LAYER M5 ;
        RECT  36.048 129.408 36.072 129.6 ;
    END
  END o_data[65]
  PIN o_data[66]
    DIRECTION OUTPUT ;
    USE SIGNAL ;
    PORT
      LAYER M5 ;
        RECT  36.48 129.408 36.504 129.6 ;
    END
  END o_data[66]
  PIN o_data[67]
    DIRECTION OUTPUT ;
    USE SIGNAL ;
    PORT
      LAYER M5 ;
        RECT  36.912 129.408 36.936 129.6 ;
    END
  END o_data[67]
  PIN o_data[68]
    DIRECTION OUTPUT ;
    USE SIGNAL ;
    PORT
      LAYER M5 ;
        RECT  37.344 129.408 37.368 129.6 ;
    END
  END o_data[68]
  PIN o_data[69]
    DIRECTION OUTPUT ;
    USE SIGNAL ;
    PORT
      LAYER M5 ;
        RECT  37.776 129.408 37.8 129.6 ;
    END
  END o_data[69]
  PIN o_data[6]
    DIRECTION OUTPUT ;
    USE SIGNAL ;
    PORT
      LAYER M5 ;
        RECT  7.584 129.408 7.608 129.6 ;
    END
  END o_data[6]
  PIN o_data[70]
    DIRECTION OUTPUT ;
    USE SIGNAL ;
    PORT
      LAYER M5 ;
        RECT  38.832 129.408 38.856 129.6 ;
    END
  END o_data[70]
  PIN o_data[71]
    DIRECTION OUTPUT ;
    USE SIGNAL ;
    PORT
      LAYER M5 ;
        RECT  39.264 129.408 39.288 129.6 ;
    END
  END o_data[71]
  PIN o_data[72]
    DIRECTION OUTPUT ;
    USE SIGNAL ;
    PORT
      LAYER M5 ;
        RECT  39.696 129.408 39.72 129.6 ;
    END
  END o_data[72]
  PIN o_data[73]
    DIRECTION OUTPUT ;
    USE SIGNAL ;
    PORT
      LAYER M5 ;
        RECT  40.128 129.408 40.152 129.6 ;
    END
  END o_data[73]
  PIN o_data[74]
    DIRECTION OUTPUT ;
    USE SIGNAL ;
    PORT
      LAYER M5 ;
        RECT  40.56 129.408 40.584 129.6 ;
    END
  END o_data[74]
  PIN o_data[75]
    DIRECTION OUTPUT ;
    USE SIGNAL ;
    PORT
      LAYER M5 ;
        RECT  40.992 129.408 41.016 129.6 ;
    END
  END o_data[75]
  PIN o_data[76]
    DIRECTION OUTPUT ;
    USE SIGNAL ;
    PORT
      LAYER M5 ;
        RECT  41.424 129.408 41.448 129.6 ;
    END
  END o_data[76]
  PIN o_data[77]
    DIRECTION OUTPUT ;
    USE SIGNAL ;
    PORT
      LAYER M5 ;
        RECT  41.856 129.408 41.88 129.6 ;
    END
  END o_data[77]
  PIN o_data[78]
    DIRECTION OUTPUT ;
    USE SIGNAL ;
    PORT
      LAYER M5 ;
        RECT  42.288 129.408 42.312 129.6 ;
    END
  END o_data[78]
  PIN o_data[79]
    DIRECTION OUTPUT ;
    USE SIGNAL ;
    PORT
      LAYER M5 ;
        RECT  42.72 129.408 42.744 129.6 ;
    END
  END o_data[79]
  PIN o_data[7]
    DIRECTION OUTPUT ;
    USE SIGNAL ;
    PORT
      LAYER M5 ;
        RECT  8.016 129.408 8.04 129.6 ;
    END
  END o_data[7]
  PIN o_data[80]
    DIRECTION OUTPUT ;
    USE SIGNAL ;
    PORT
      LAYER M5 ;
        RECT  43.152 129.408 43.176 129.6 ;
    END
  END o_data[80]
  PIN o_data[81]
    DIRECTION OUTPUT ;
    USE SIGNAL ;
    PORT
      LAYER M5 ;
        RECT  44.112 129.408 44.136 129.6 ;
    END
  END o_data[81]
  PIN o_data[82]
    DIRECTION OUTPUT ;
    USE SIGNAL ;
    PORT
      LAYER M5 ;
        RECT  44.544 129.408 44.568 129.6 ;
    END
  END o_data[82]
  PIN o_data[83]
    DIRECTION OUTPUT ;
    USE SIGNAL ;
    PORT
      LAYER M5 ;
        RECT  44.976 129.408 45 129.6 ;
    END
  END o_data[83]
  PIN o_data[84]
    DIRECTION OUTPUT ;
    USE SIGNAL ;
    PORT
      LAYER M5 ;
        RECT  45.408 129.408 45.432 129.6 ;
    END
  END o_data[84]
  PIN o_data[85]
    DIRECTION OUTPUT ;
    USE SIGNAL ;
    PORT
      LAYER M5 ;
        RECT  45.84 129.408 45.864 129.6 ;
    END
  END o_data[85]
  PIN o_data[86]
    DIRECTION OUTPUT ;
    USE SIGNAL ;
    PORT
      LAYER M5 ;
        RECT  46.272 129.408 46.296 129.6 ;
    END
  END o_data[86]
  PIN o_data[87]
    DIRECTION OUTPUT ;
    USE SIGNAL ;
    PORT
      LAYER M5 ;
        RECT  46.704 129.408 46.728 129.6 ;
    END
  END o_data[87]
  PIN o_data[88]
    DIRECTION OUTPUT ;
    USE SIGNAL ;
    PORT
      LAYER M5 ;
        RECT  47.136 129.408 47.16 129.6 ;
    END
  END o_data[88]
  PIN o_data[89]
    DIRECTION OUTPUT ;
    USE SIGNAL ;
    PORT
      LAYER M5 ;
        RECT  47.568 129.408 47.592 129.6 ;
    END
  END o_data[89]
  PIN o_data[8]
    DIRECTION OUTPUT ;
    USE SIGNAL ;
    PORT
      LAYER M5 ;
        RECT  8.448 129.408 8.472 129.6 ;
    END
  END o_data[8]
  PIN o_data[90]
    DIRECTION OUTPUT ;
    USE SIGNAL ;
    PORT
      LAYER M5 ;
        RECT  48.144 129.408 48.168 129.6 ;
    END
  END o_data[90]
  PIN o_data[91]
    DIRECTION OUTPUT ;
    USE SIGNAL ;
    PORT
      LAYER M5 ;
        RECT  48.576 129.408 48.6 129.6 ;
    END
  END o_data[91]
  PIN o_data[92]
    DIRECTION OUTPUT ;
    USE SIGNAL ;
    PORT
      LAYER M5 ;
        RECT  49.488 129.408 49.512 129.6 ;
    END
  END o_data[92]
  PIN o_data[93]
    DIRECTION OUTPUT ;
    USE SIGNAL ;
    PORT
      LAYER M5 ;
        RECT  49.92 129.408 49.944 129.6 ;
    END
  END o_data[93]
  PIN o_data[94]
    DIRECTION OUTPUT ;
    USE SIGNAL ;
    PORT
      LAYER M5 ;
        RECT  50.352 129.408 50.376 129.6 ;
    END
  END o_data[94]
  PIN o_data[95]
    DIRECTION OUTPUT ;
    USE SIGNAL ;
    PORT
      LAYER M5 ;
        RECT  50.784 129.408 50.808 129.6 ;
    END
  END o_data[95]
  PIN o_data[96]
    DIRECTION OUTPUT ;
    USE SIGNAL ;
    PORT
      LAYER M5 ;
        RECT  51.216 129.408 51.24 129.6 ;
    END
  END o_data[96]
  PIN o_data[97]
    DIRECTION OUTPUT ;
    USE SIGNAL ;
    PORT
      LAYER M5 ;
        RECT  51.648 129.408 51.672 129.6 ;
    END
  END o_data[97]
  PIN o_data[98]
    DIRECTION OUTPUT ;
    USE SIGNAL ;
    PORT
      LAYER M5 ;
        RECT  52.08 129.408 52.104 129.6 ;
    END
  END o_data[98]
  PIN o_data[99]
    DIRECTION OUTPUT ;
    USE SIGNAL ;
    PORT
      LAYER M5 ;
        RECT  52.512 129.408 52.536 129.6 ;
    END
  END o_data[99]
  PIN o_data[9]
    DIRECTION OUTPUT ;
    USE SIGNAL ;
    PORT
      LAYER M5 ;
        RECT  8.88 129.408 8.904 129.6 ;
    END
  END o_data[9]
  PIN o_v[0]
    DIRECTION OUTPUT ;
    USE SIGNAL ;
    PORT
      LAYER M5 ;
        RECT  66.72 129.408 66.744 129.6 ;
    END
  END o_v[0]
  PIN o_v[10]
    DIRECTION OUTPUT ;
    USE SIGNAL ;
    PORT
      LAYER M5 ;
        RECT  71.664 129.408 71.688 129.6 ;
    END
  END o_v[10]
  PIN o_v[11]
    DIRECTION OUTPUT ;
    USE SIGNAL ;
    PORT
      LAYER M5 ;
        RECT  72.096 129.408 72.12 129.6 ;
    END
  END o_v[11]
  PIN o_v[12]
    DIRECTION OUTPUT ;
    USE SIGNAL ;
    PORT
      LAYER M5 ;
        RECT  72.528 129.408 72.552 129.6 ;
    END
  END o_v[12]
  PIN o_v[13]
    DIRECTION OUTPUT ;
    USE SIGNAL ;
    PORT
      LAYER M5 ;
        RECT  72.96 129.408 72.984 129.6 ;
    END
  END o_v[13]
  PIN o_v[14]
    DIRECTION OUTPUT ;
    USE SIGNAL ;
    PORT
      LAYER M5 ;
        RECT  73.392 129.408 73.416 129.6 ;
    END
  END o_v[14]
  PIN o_v[15]
    DIRECTION OUTPUT ;
    USE SIGNAL ;
    PORT
      LAYER M5 ;
        RECT  73.824 129.408 73.848 129.6 ;
    END
  END o_v[15]
  PIN o_v[16]
    DIRECTION OUTPUT ;
    USE SIGNAL ;
    PORT
      LAYER M5 ;
        RECT  74.256 129.408 74.28 129.6 ;
    END
  END o_v[16]
  PIN o_v[17]
    DIRECTION OUTPUT ;
    USE SIGNAL ;
    PORT
      LAYER M5 ;
        RECT  74.688 129.408 74.712 129.6 ;
    END
  END o_v[17]
  PIN o_v[18]
    DIRECTION OUTPUT ;
    USE SIGNAL ;
    PORT
      LAYER M5 ;
        RECT  75.12 129.408 75.144 129.6 ;
    END
  END o_v[18]
  PIN o_v[19]
    DIRECTION OUTPUT ;
    USE SIGNAL ;
    PORT
      LAYER M5 ;
        RECT  75.552 129.408 75.576 129.6 ;
    END
  END o_v[19]
  PIN o_v[1]
    DIRECTION OUTPUT ;
    USE SIGNAL ;
    PORT
      LAYER M5 ;
        RECT  67.152 129.408 67.176 129.6 ;
    END
  END o_v[1]
  PIN o_v[20]
    DIRECTION OUTPUT ;
    USE SIGNAL ;
    PORT
      LAYER M5 ;
        RECT  76.512 129.408 76.536 129.6 ;
    END
  END o_v[20]
  PIN o_v[21]
    DIRECTION OUTPUT ;
    USE SIGNAL ;
    PORT
      LAYER M5 ;
        RECT  76.944 129.408 76.968 129.6 ;
    END
  END o_v[21]
  PIN o_v[22]
    DIRECTION OUTPUT ;
    USE SIGNAL ;
    PORT
      LAYER M5 ;
        RECT  77.52 129.408 77.544 129.6 ;
    END
  END o_v[22]
  PIN o_v[23]
    DIRECTION OUTPUT ;
    USE SIGNAL ;
    PORT
      LAYER M5 ;
        RECT  77.952 129.408 77.976 129.6 ;
    END
  END o_v[23]
  PIN o_v[24]
    DIRECTION OUTPUT ;
    USE SIGNAL ;
    PORT
      LAYER M5 ;
        RECT  78.384 129.408 78.408 129.6 ;
    END
  END o_v[24]
  PIN o_v[25]
    DIRECTION OUTPUT ;
    USE SIGNAL ;
    PORT
      LAYER M5 ;
        RECT  78.816 129.408 78.84 129.6 ;
    END
  END o_v[25]
  PIN o_v[26]
    DIRECTION OUTPUT ;
    USE SIGNAL ;
    PORT
      LAYER M5 ;
        RECT  79.248 129.408 79.272 129.6 ;
    END
  END o_v[26]
  PIN o_v[27]
    DIRECTION OUTPUT ;
    USE SIGNAL ;
    PORT
      LAYER M5 ;
        RECT  79.68 129.408 79.704 129.6 ;
    END
  END o_v[27]
  PIN o_v[28]
    DIRECTION OUTPUT ;
    USE SIGNAL ;
    PORT
      LAYER M5 ;
        RECT  80.112 129.408 80.136 129.6 ;
    END
  END o_v[28]
  PIN o_v[29]
    DIRECTION OUTPUT ;
    USE SIGNAL ;
    PORT
      LAYER M5 ;
        RECT  80.544 129.408 80.568 129.6 ;
    END
  END o_v[29]
  PIN o_v[2]
    DIRECTION OUTPUT ;
    USE SIGNAL ;
    PORT
      LAYER M5 ;
        RECT  67.728 129.408 67.752 129.6 ;
    END
  END o_v[2]
  PIN o_v[30]
    DIRECTION OUTPUT ;
    USE SIGNAL ;
    PORT
      LAYER M5 ;
        RECT  80.976 129.408 81 129.6 ;
    END
  END o_v[30]
  PIN o_v[31]
    DIRECTION OUTPUT ;
    USE SIGNAL ;
    PORT
      LAYER M5 ;
        RECT  81.888 129.408 81.912 129.6 ;
    END
  END o_v[31]
  PIN o_v[3]
    DIRECTION OUTPUT ;
    USE SIGNAL ;
    PORT
      LAYER M5 ;
        RECT  68.16 129.408 68.184 129.6 ;
    END
  END o_v[3]
  PIN o_v[4]
    DIRECTION OUTPUT ;
    USE SIGNAL ;
    PORT
      LAYER M5 ;
        RECT  68.592 129.408 68.616 129.6 ;
    END
  END o_v[4]
  PIN o_v[5]
    DIRECTION OUTPUT ;
    USE SIGNAL ;
    PORT
      LAYER M5 ;
        RECT  69.024 129.408 69.048 129.6 ;
    END
  END o_v[5]
  PIN o_v[6]
    DIRECTION OUTPUT ;
    USE SIGNAL ;
    PORT
      LAYER M5 ;
        RECT  69.456 129.408 69.48 129.6 ;
    END
  END o_v[6]
  PIN o_v[7]
    DIRECTION OUTPUT ;
    USE SIGNAL ;
    PORT
      LAYER M5 ;
        RECT  69.888 129.408 69.912 129.6 ;
    END
  END o_v[7]
  PIN o_v[8]
    DIRECTION OUTPUT ;
    USE SIGNAL ;
    PORT
      LAYER M5 ;
        RECT  70.32 129.408 70.344 129.6 ;
    END
  END o_v[8]
  PIN o_v[9]
    DIRECTION OUTPUT ;
    USE SIGNAL ;
    PORT
      LAYER M5 ;
        RECT  71.232 129.408 71.256 129.6 ;
    END
  END o_v[9]
  PIN rst_n
    DIRECTION INPUT ;
    USE SIGNAL ;
    PORT
      LAYER M4 ;
        RECT  0 4.464 0.192 4.488 ;
    END
  END rst_n
  PIN VDD
    DIRECTION INOUT ;
    USE POWER ;
    PORT
      LAYER M5 ;
        RECT  83.592 2.151 83.712 127.449 ;
        RECT  78.192 2.151 78.312 127.449 ;
        RECT  72.792 2.151 72.912 127.449 ;
        RECT  67.392 2.151 67.512 127.449 ;
        RECT  61.992 2.151 62.112 127.449 ;
        RECT  56.592 2.151 56.712 127.449 ;
        RECT  51.192 2.151 51.312 127.449 ;
        RECT  45.792 2.151 45.912 127.449 ;
        RECT  40.392 2.151 40.512 127.449 ;
        RECT  34.992 2.151 35.112 127.449 ;
        RECT  29.592 2.151 29.712 127.449 ;
        RECT  24.192 2.151 24.312 127.449 ;
        RECT  18.792 2.151 18.912 127.449 ;
        RECT  13.392 2.151 13.512 127.449 ;
        RECT  7.992 2.151 8.112 127.449 ;
        RECT  2.592 2.151 2.712 127.449 ;
    END
  END VDD
  PIN VSS
    DIRECTION INOUT ;
    USE GROUND ;
    PORT
      LAYER M5 ;
        RECT  83.4 2.137 83.52 127.463 ;
        RECT  78 2.137 78.12 127.463 ;
        RECT  72.6 2.137 72.72 127.463 ;
        RECT  67.2 2.137 67.32 127.463 ;
        RECT  61.8 2.137 61.92 127.463 ;
        RECT  56.4 2.137 56.52 127.463 ;
        RECT  51 2.137 51.12 127.463 ;
        RECT  45.6 2.137 45.72 127.463 ;
        RECT  40.2 2.137 40.32 127.463 ;
        RECT  34.8 2.137 34.92 127.463 ;
        RECT  29.4 2.137 29.52 127.463 ;
        RECT  24 2.137 24.12 127.463 ;
        RECT  18.6 2.137 18.72 127.463 ;
        RECT  13.2 2.137 13.32 127.463 ;
        RECT  7.8 2.137 7.92 127.463 ;
        RECT  2.4 2.137 2.52 127.463 ;
    END
  END VSS
  # OT_OBS_CLOSED layer=M5 d_um=1.536 added=470
  OBS
    LAYER RVTN ;
     RECT  2.16 2.16 84.24 2.295 ;
     RECT  2.16 2.565 84.24 2.835 ;
     RECT  2.16 3.105 84.24 3.375 ;
     RECT  2.16 3.645 84.24 3.915 ;
     RECT  2.16 4.185 84.24 4.455 ;
     RECT  2.16 4.725 84.24 4.995 ;
     RECT  2.16 5.265 84.24 5.535 ;
     RECT  2.16 5.805 84.24 6.075 ;
     RECT  2.16 6.345 84.24 6.615 ;
     RECT  2.16 6.885 84.24 7.155 ;
     RECT  2.16 7.425 84.24 7.695 ;
     RECT  2.16 7.965 84.24 8.235 ;
     RECT  2.16 8.505 84.24 8.775 ;
     RECT  2.16 9.045 84.24 9.315 ;
     RECT  2.16 9.585 84.24 9.855 ;
     RECT  2.16 10.125 84.24 10.395 ;
     RECT  2.16 10.665 84.24 10.935 ;
     RECT  2.16 11.205 84.24 11.475 ;
     RECT  2.16 11.745 84.24 12.015 ;
     RECT  2.16 12.285 84.24 12.555 ;
     RECT  2.16 12.825 84.24 13.095 ;
     RECT  2.16 13.365 84.24 13.635 ;
     RECT  2.16 13.905 84.24 14.175 ;
     RECT  2.16 14.445 84.24 14.715 ;
     RECT  2.16 14.985 84.24 15.255 ;
     RECT  2.16 15.525 84.24 15.795 ;
     RECT  2.16 16.065 84.24 16.335 ;
     RECT  2.16 16.605 84.24 16.875 ;
     RECT  2.16 17.145 84.24 17.415 ;
     RECT  2.16 17.685 84.24 17.955 ;
     RECT  2.16 18.225 84.24 18.495 ;
     RECT  2.16 18.765 84.24 19.035 ;
     RECT  2.16 19.305 84.24 19.575 ;
     RECT  2.16 19.845 84.24 20.115 ;
     RECT  2.16 20.385 84.24 20.655 ;
     RECT  2.16 20.925 84.24 21.195 ;
     RECT  2.16 21.465 84.24 21.735 ;
     RECT  2.16 22.005 84.24 22.275 ;
     RECT  2.16 22.545 84.24 22.815 ;
     RECT  2.16 23.085 84.24 23.355 ;
     RECT  2.16 23.625 84.24 23.895 ;
     RECT  2.16 24.165 84.24 24.435 ;
     RECT  2.16 24.705 84.24 24.975 ;
     RECT  2.16 25.245 84.24 25.515 ;
     RECT  2.16 25.785 84.24 26.055 ;
     RECT  2.16 26.325 84.24 26.595 ;
     RECT  2.16 26.865 84.24 27.135 ;
     RECT  2.16 27.405 84.24 27.675 ;
     RECT  2.16 27.945 84.24 28.215 ;
     RECT  2.16 28.485 84.24 28.755 ;
     RECT  2.16 29.025 84.24 29.295 ;
     RECT  2.16 29.565 84.24 29.835 ;
     RECT  2.16 30.105 84.24 30.375 ;
     RECT  2.16 30.645 84.24 30.915 ;
     RECT  2.16 31.185 84.24 31.455 ;
     RECT  2.16 31.725 84.24 31.995 ;
     RECT  2.16 32.265 84.24 32.535 ;
     RECT  2.16 32.805 84.24 33.075 ;
     RECT  2.16 33.345 84.24 33.615 ;
     RECT  2.16 33.885 84.24 34.155 ;
     RECT  2.16 34.425 84.24 34.695 ;
     RECT  2.16 34.965 84.24 35.235 ;
     RECT  2.16 35.505 84.24 35.775 ;
     RECT  2.16 36.045 84.24 36.315 ;
     RECT  2.16 36.585 84.24 36.855 ;
     RECT  2.16 37.125 84.24 37.395 ;
     RECT  2.16 37.665 84.24 37.935 ;
     RECT  2.16 38.205 84.24 38.475 ;
     RECT  2.16 38.745 84.24 39.015 ;
     RECT  2.16 39.285 84.24 39.555 ;
     RECT  2.16 39.825 84.24 40.095 ;
     RECT  2.16 40.365 84.24 40.635 ;
     RECT  2.16 40.905 84.24 41.175 ;
     RECT  2.16 41.445 84.24 41.715 ;
     RECT  2.16 41.985 84.24 42.255 ;
     RECT  2.16 42.525 84.24 42.795 ;
     RECT  2.16 43.065 84.24 43.335 ;
     RECT  2.16 43.605 84.24 43.875 ;
     RECT  2.16 44.145 84.24 44.415 ;
     RECT  2.16 44.685 84.24 44.955 ;
     RECT  2.16 45.225 84.24 45.495 ;
     RECT  2.16 45.765 84.24 46.035 ;
     RECT  2.16 46.305 84.24 46.575 ;
     RECT  2.16 46.845 84.24 47.115 ;
     RECT  2.16 47.385 84.24 47.655 ;
     RECT  2.16 47.925 84.24 48.195 ;
     RECT  2.16 48.465 84.24 48.735 ;
     RECT  2.16 49.005 84.24 49.275 ;
     RECT  2.16 49.545 84.24 49.815 ;
     RECT  2.16 50.085 84.24 50.355 ;
     RECT  2.16 50.625 84.24 50.895 ;
     RECT  2.16 51.165 84.24 51.435 ;
     RECT  2.16 51.705 84.24 51.975 ;
     RECT  2.16 52.245 84.24 52.515 ;
     RECT  2.16 52.785 84.24 53.055 ;
     RECT  2.16 53.325 84.24 53.595 ;
     RECT  2.16 53.865 84.24 54.135 ;
     RECT  2.16 54.405 84.24 54.675 ;
     RECT  2.16 54.945 84.24 55.215 ;
     RECT  2.16 55.485 84.24 55.755 ;
     RECT  2.16 56.025 84.24 56.295 ;
     RECT  2.16 56.565 84.24 56.835 ;
     RECT  2.16 57.105 84.24 57.375 ;
     RECT  2.16 57.645 84.24 57.915 ;
     RECT  2.16 58.185 84.24 58.455 ;
     RECT  2.16 58.725 84.24 58.995 ;
     RECT  2.16 59.265 84.24 59.535 ;
     RECT  2.16 59.805 84.24 60.075 ;
     RECT  2.16 60.345 84.24 60.615 ;
     RECT  2.16 60.885 84.24 61.155 ;
     RECT  2.16 61.425 84.24 61.695 ;
     RECT  2.16 61.965 84.24 62.235 ;
     RECT  2.16 62.505 84.24 62.775 ;
     RECT  2.16 63.045 84.24 63.315 ;
     RECT  2.16 63.585 84.24 63.855 ;
     RECT  2.16 64.125 84.24 64.395 ;
     RECT  2.16 64.665 84.24 64.935 ;
     RECT  2.16 65.205 84.24 65.475 ;
     RECT  2.16 65.745 84.24 66.015 ;
     RECT  2.16 66.285 84.24 66.555 ;
     RECT  2.16 66.825 84.24 67.095 ;
     RECT  2.16 67.365 84.24 67.635 ;
     RECT  2.16 67.905 84.24 68.175 ;
     RECT  2.16 68.445 84.24 68.715 ;
     RECT  2.16 68.985 84.24 69.255 ;
     RECT  2.16 69.525 84.24 69.795 ;
     RECT  2.16 70.065 84.24 70.335 ;
     RECT  2.16 70.605 84.24 70.875 ;
     RECT  2.16 71.145 84.24 71.415 ;
     RECT  2.16 71.685 84.24 71.955 ;
     RECT  2.16 72.225 84.24 72.495 ;
     RECT  2.16 72.765 84.24 73.035 ;
     RECT  2.16 73.305 84.24 73.575 ;
     RECT  2.16 73.845 84.24 74.115 ;
     RECT  2.16 74.385 84.24 74.655 ;
     RECT  2.16 74.925 84.24 75.195 ;
     RECT  2.16 75.465 84.24 75.735 ;
     RECT  2.16 76.005 84.24 76.275 ;
     RECT  2.16 76.545 84.24 76.815 ;
     RECT  2.16 77.085 84.24 77.355 ;
     RECT  2.16 77.625 84.24 77.895 ;
     RECT  2.16 78.165 84.24 78.435 ;
     RECT  2.16 78.705 84.24 78.975 ;
     RECT  2.16 79.245 84.24 79.515 ;
     RECT  2.16 79.785 84.24 80.055 ;
     RECT  2.16 80.325 84.24 80.595 ;
     RECT  2.16 80.865 84.24 81.135 ;
     RECT  2.16 81.405 84.24 81.675 ;
     RECT  2.16 81.945 84.24 82.215 ;
     RECT  2.16 82.485 84.24 82.755 ;
     RECT  2.16 83.025 84.24 83.295 ;
     RECT  2.16 83.565 84.24 83.835 ;
     RECT  2.16 84.105 84.24 84.375 ;
     RECT  2.16 84.645 84.24 84.915 ;
     RECT  2.16 85.185 84.24 85.455 ;
     RECT  2.16 85.725 84.24 85.995 ;
     RECT  2.16 86.265 84.24 86.535 ;
     RECT  2.16 86.805 84.24 87.075 ;
     RECT  2.16 87.345 84.24 87.615 ;
     RECT  2.16 87.885 84.24 88.155 ;
     RECT  2.16 88.425 84.24 88.695 ;
     RECT  2.16 88.965 84.24 89.235 ;
     RECT  2.16 89.505 84.24 89.775 ;
     RECT  2.16 90.045 84.24 90.315 ;
     RECT  2.16 90.585 84.24 90.855 ;
     RECT  2.16 91.125 84.24 91.395 ;
     RECT  2.16 91.665 84.24 91.935 ;
     RECT  2.16 92.205 84.24 92.475 ;
     RECT  2.16 92.745 84.24 93.015 ;
     RECT  2.16 93.285 84.24 93.555 ;
     RECT  2.16 93.825 84.24 94.095 ;
     RECT  2.16 94.365 84.24 94.635 ;
     RECT  2.16 94.905 84.24 95.175 ;
     RECT  2.16 95.445 84.24 95.715 ;
     RECT  2.16 95.985 84.24 96.255 ;
     RECT  2.16 96.525 84.24 96.795 ;
     RECT  2.16 97.065 84.24 97.335 ;
     RECT  2.16 97.605 84.24 97.875 ;
     RECT  2.16 98.145 84.24 98.415 ;
     RECT  2.16 98.685 84.24 98.955 ;
     RECT  2.16 99.225 84.24 99.495 ;
     RECT  2.16 99.765 84.24 100.035 ;
     RECT  2.16 100.305 84.24 100.575 ;
     RECT  2.16 100.845 84.24 101.115 ;
     RECT  2.16 101.385 84.24 101.655 ;
     RECT  2.16 101.925 84.24 102.195 ;
     RECT  2.16 102.465 84.24 102.735 ;
     RECT  2.16 103.005 84.24 103.275 ;
     RECT  2.16 103.545 84.24 103.815 ;
     RECT  2.16 104.085 84.24 104.355 ;
     RECT  2.16 104.625 84.24 104.895 ;
     RECT  2.16 105.165 84.24 105.435 ;
     RECT  2.16 105.705 84.24 105.975 ;
     RECT  2.16 106.245 84.24 106.515 ;
     RECT  2.16 106.785 84.24 107.055 ;
     RECT  2.16 107.325 84.24 107.595 ;
     RECT  2.16 107.865 84.24 108.135 ;
     RECT  2.16 108.405 84.24 108.675 ;
     RECT  2.16 108.945 84.24 109.215 ;
     RECT  2.16 109.485 84.24 109.755 ;
     RECT  2.16 110.025 84.24 110.295 ;
     RECT  2.16 110.565 84.24 110.835 ;
     RECT  2.16 111.105 84.24 111.375 ;
     RECT  2.16 111.645 84.24 111.915 ;
     RECT  2.16 112.185 84.24 112.455 ;
     RECT  2.16 112.725 84.24 112.995 ;
     RECT  2.16 113.265 84.24 113.535 ;
     RECT  2.16 113.805 84.24 114.075 ;
     RECT  2.16 114.345 84.24 114.615 ;
     RECT  2.16 114.885 84.24 115.155 ;
     RECT  2.16 115.425 84.24 115.695 ;
     RECT  2.16 115.965 84.24 116.235 ;
     RECT  2.16 116.505 84.24 116.775 ;
     RECT  2.16 117.045 84.24 117.315 ;
     RECT  2.16 117.585 84.24 117.855 ;
     RECT  2.16 118.125 84.24 118.395 ;
     RECT  2.16 118.665 84.24 118.935 ;
     RECT  2.16 119.205 84.24 119.475 ;
     RECT  2.16 119.745 84.24 120.015 ;
     RECT  2.16 120.285 84.24 120.555 ;
     RECT  2.16 120.825 84.24 121.095 ;
     RECT  2.16 121.365 84.24 121.635 ;
     RECT  2.16 121.905 84.24 122.175 ;
     RECT  2.16 122.445 84.24 122.715 ;
     RECT  2.16 122.985 84.24 123.255 ;
     RECT  2.16 123.525 84.24 123.795 ;
     RECT  2.16 124.065 84.24 124.335 ;
     RECT  2.16 124.605 84.24 124.875 ;
     RECT  2.16 125.145 84.24 125.415 ;
     RECT  2.16 125.685 84.24 125.955 ;
     RECT  2.16 126.225 84.24 126.495 ;
     RECT  2.16 126.765 84.24 127.035 ;
     RECT  2.16 127.305 84.24 127.44 ;
    LAYER RVTP ;
     RECT  2.16 2.295 84.24 2.565 ;
     RECT  2.16 2.835 84.24 3.105 ;
     RECT  2.16 3.375 84.24 3.645 ;
     RECT  2.16 3.915 84.24 4.185 ;
     RECT  2.16 4.455 84.24 4.725 ;
     RECT  2.16 4.995 84.24 5.265 ;
     RECT  2.16 5.535 84.24 5.805 ;
     RECT  2.16 6.075 84.24 6.345 ;
     RECT  2.16 6.615 84.24 6.885 ;
     RECT  2.16 7.155 84.24 7.425 ;
     RECT  2.16 7.695 84.24 7.965 ;
     RECT  2.16 8.235 84.24 8.505 ;
     RECT  2.16 8.775 84.24 9.045 ;
     RECT  2.16 9.315 84.24 9.585 ;
     RECT  2.16 9.855 84.24 10.125 ;
     RECT  2.16 10.395 84.24 10.665 ;
     RECT  2.16 10.935 84.24 11.205 ;
     RECT  2.16 11.475 84.24 11.745 ;
     RECT  2.16 12.015 84.24 12.285 ;
     RECT  2.16 12.555 84.24 12.825 ;
     RECT  2.16 13.095 84.24 13.365 ;
     RECT  2.16 13.635 84.24 13.905 ;
     RECT  2.16 14.175 84.24 14.445 ;
     RECT  2.16 14.715 84.24 14.985 ;
     RECT  2.16 15.255 84.24 15.525 ;
     RECT  2.16 15.795 84.24 16.065 ;
     RECT  2.16 16.335 84.24 16.605 ;
     RECT  2.16 16.875 84.24 17.145 ;
     RECT  2.16 17.415 84.24 17.685 ;
     RECT  2.16 17.955 84.24 18.225 ;
     RECT  2.16 18.495 84.24 18.765 ;
     RECT  2.16 19.035 84.24 19.305 ;
     RECT  2.16 19.575 84.24 19.845 ;
     RECT  2.16 20.115 84.24 20.385 ;
     RECT  2.16 20.655 84.24 20.925 ;
     RECT  2.16 21.195 84.24 21.465 ;
     RECT  2.16 21.735 84.24 22.005 ;
     RECT  2.16 22.275 84.24 22.545 ;
     RECT  2.16 22.815 84.24 23.085 ;
     RECT  2.16 23.355 84.24 23.625 ;
     RECT  2.16 23.895 84.24 24.165 ;
     RECT  2.16 24.435 84.24 24.705 ;
     RECT  2.16 24.975 84.24 25.245 ;
     RECT  2.16 25.515 84.24 25.785 ;
     RECT  2.16 26.055 84.24 26.325 ;
     RECT  2.16 26.595 84.24 26.865 ;
     RECT  2.16 27.135 84.24 27.405 ;
     RECT  2.16 27.675 84.24 27.945 ;
     RECT  2.16 28.215 84.24 28.485 ;
     RECT  2.16 28.755 84.24 29.025 ;
     RECT  2.16 29.295 84.24 29.565 ;
     RECT  2.16 29.835 84.24 30.105 ;
     RECT  2.16 30.375 84.24 30.645 ;
     RECT  2.16 30.915 84.24 31.185 ;
     RECT  2.16 31.455 84.24 31.725 ;
     RECT  2.16 31.995 84.24 32.265 ;
     RECT  2.16 32.535 84.24 32.805 ;
     RECT  2.16 33.075 84.24 33.345 ;
     RECT  2.16 33.615 84.24 33.885 ;
     RECT  2.16 34.155 84.24 34.425 ;
     RECT  2.16 34.695 84.24 34.965 ;
     RECT  2.16 35.235 84.24 35.505 ;
     RECT  2.16 35.775 84.24 36.045 ;
     RECT  2.16 36.315 84.24 36.585 ;
     RECT  2.16 36.855 84.24 37.125 ;
     RECT  2.16 37.395 84.24 37.665 ;
     RECT  2.16 37.935 84.24 38.205 ;
     RECT  2.16 38.475 84.24 38.745 ;
     RECT  2.16 39.015 84.24 39.285 ;
     RECT  2.16 39.555 84.24 39.825 ;
     RECT  2.16 40.095 84.24 40.365 ;
     RECT  2.16 40.635 84.24 40.905 ;
     RECT  2.16 41.175 84.24 41.445 ;
     RECT  2.16 41.715 84.24 41.985 ;
     RECT  2.16 42.255 84.24 42.525 ;
     RECT  2.16 42.795 84.24 43.065 ;
     RECT  2.16 43.335 84.24 43.605 ;
     RECT  2.16 43.875 84.24 44.145 ;
     RECT  2.16 44.415 84.24 44.685 ;
     RECT  2.16 44.955 84.24 45.225 ;
     RECT  2.16 45.495 84.24 45.765 ;
     RECT  2.16 46.035 84.24 46.305 ;
     RECT  2.16 46.575 84.24 46.845 ;
     RECT  2.16 47.115 84.24 47.385 ;
     RECT  2.16 47.655 84.24 47.925 ;
     RECT  2.16 48.195 84.24 48.465 ;
     RECT  2.16 48.735 84.24 49.005 ;
     RECT  2.16 49.275 84.24 49.545 ;
     RECT  2.16 49.815 84.24 50.085 ;
     RECT  2.16 50.355 84.24 50.625 ;
     RECT  2.16 50.895 84.24 51.165 ;
     RECT  2.16 51.435 84.24 51.705 ;
     RECT  2.16 51.975 84.24 52.245 ;
     RECT  2.16 52.515 84.24 52.785 ;
     RECT  2.16 53.055 84.24 53.325 ;
     RECT  2.16 53.595 84.24 53.865 ;
     RECT  2.16 54.135 84.24 54.405 ;
     RECT  2.16 54.675 84.24 54.945 ;
     RECT  2.16 55.215 84.24 55.485 ;
     RECT  2.16 55.755 84.24 56.025 ;
     RECT  2.16 56.295 84.24 56.565 ;
     RECT  2.16 56.835 84.24 57.105 ;
     RECT  2.16 57.375 84.24 57.645 ;
     RECT  2.16 57.915 84.24 58.185 ;
     RECT  2.16 58.455 84.24 58.725 ;
     RECT  2.16 58.995 84.24 59.265 ;
     RECT  2.16 59.535 84.24 59.805 ;
     RECT  2.16 60.075 84.24 60.345 ;
     RECT  2.16 60.615 84.24 60.885 ;
     RECT  2.16 61.155 84.24 61.425 ;
     RECT  2.16 61.695 84.24 61.965 ;
     RECT  2.16 62.235 84.24 62.505 ;
     RECT  2.16 62.775 84.24 63.045 ;
     RECT  2.16 63.315 84.24 63.585 ;
     RECT  2.16 63.855 84.24 64.125 ;
     RECT  2.16 64.395 84.24 64.665 ;
     RECT  2.16 64.935 84.24 65.205 ;
     RECT  2.16 65.475 84.24 65.745 ;
     RECT  2.16 66.015 84.24 66.285 ;
     RECT  2.16 66.555 84.24 66.825 ;
     RECT  2.16 67.095 84.24 67.365 ;
     RECT  2.16 67.635 84.24 67.905 ;
     RECT  2.16 68.175 84.24 68.445 ;
     RECT  2.16 68.715 84.24 68.985 ;
     RECT  2.16 69.255 84.24 69.525 ;
     RECT  2.16 69.795 84.24 70.065 ;
     RECT  2.16 70.335 84.24 70.605 ;
     RECT  2.16 70.875 84.24 71.145 ;
     RECT  2.16 71.415 84.24 71.685 ;
     RECT  2.16 71.955 84.24 72.225 ;
     RECT  2.16 72.495 84.24 72.765 ;
     RECT  2.16 73.035 84.24 73.305 ;
     RECT  2.16 73.575 84.24 73.845 ;
     RECT  2.16 74.115 84.24 74.385 ;
     RECT  2.16 74.655 84.24 74.925 ;
     RECT  2.16 75.195 84.24 75.465 ;
     RECT  2.16 75.735 84.24 76.005 ;
     RECT  2.16 76.275 84.24 76.545 ;
     RECT  2.16 76.815 84.24 77.085 ;
     RECT  2.16 77.355 84.24 77.625 ;
     RECT  2.16 77.895 84.24 78.165 ;
     RECT  2.16 78.435 84.24 78.705 ;
     RECT  2.16 78.975 84.24 79.245 ;
     RECT  2.16 79.515 84.24 79.785 ;
     RECT  2.16 80.055 84.24 80.325 ;
     RECT  2.16 80.595 84.24 80.865 ;
     RECT  2.16 81.135 84.24 81.405 ;
     RECT  2.16 81.675 84.24 81.945 ;
     RECT  2.16 82.215 84.24 82.485 ;
     RECT  2.16 82.755 84.24 83.025 ;
     RECT  2.16 83.295 84.24 83.565 ;
     RECT  2.16 83.835 84.24 84.105 ;
     RECT  2.16 84.375 84.24 84.645 ;
     RECT  2.16 84.915 84.24 85.185 ;
     RECT  2.16 85.455 84.24 85.725 ;
     RECT  2.16 85.995 84.24 86.265 ;
     RECT  2.16 86.535 84.24 86.805 ;
     RECT  2.16 87.075 84.24 87.345 ;
     RECT  2.16 87.615 84.24 87.885 ;
     RECT  2.16 88.155 84.24 88.425 ;
     RECT  2.16 88.695 84.24 88.965 ;
     RECT  2.16 89.235 84.24 89.505 ;
     RECT  2.16 89.775 84.24 90.045 ;
     RECT  2.16 90.315 84.24 90.585 ;
     RECT  2.16 90.855 84.24 91.125 ;
     RECT  2.16 91.395 84.24 91.665 ;
     RECT  2.16 91.935 84.24 92.205 ;
     RECT  2.16 92.475 84.24 92.745 ;
     RECT  2.16 93.015 84.24 93.285 ;
     RECT  2.16 93.555 84.24 93.825 ;
     RECT  2.16 94.095 84.24 94.365 ;
     RECT  2.16 94.635 84.24 94.905 ;
     RECT  2.16 95.175 84.24 95.445 ;
     RECT  2.16 95.715 84.24 95.985 ;
     RECT  2.16 96.255 84.24 96.525 ;
     RECT  2.16 96.795 84.24 97.065 ;
     RECT  2.16 97.335 84.24 97.605 ;
     RECT  2.16 97.875 84.24 98.145 ;
     RECT  2.16 98.415 84.24 98.685 ;
     RECT  2.16 98.955 84.24 99.225 ;
     RECT  2.16 99.495 84.24 99.765 ;
     RECT  2.16 100.035 84.24 100.305 ;
     RECT  2.16 100.575 84.24 100.845 ;
     RECT  2.16 101.115 84.24 101.385 ;
     RECT  2.16 101.655 84.24 101.925 ;
     RECT  2.16 102.195 84.24 102.465 ;
     RECT  2.16 102.735 84.24 103.005 ;
     RECT  2.16 103.275 84.24 103.545 ;
     RECT  2.16 103.815 84.24 104.085 ;
     RECT  2.16 104.355 84.24 104.625 ;
     RECT  2.16 104.895 84.24 105.165 ;
     RECT  2.16 105.435 84.24 105.705 ;
     RECT  2.16 105.975 84.24 106.245 ;
     RECT  2.16 106.515 84.24 106.785 ;
     RECT  2.16 107.055 84.24 107.325 ;
     RECT  2.16 107.595 84.24 107.865 ;
     RECT  2.16 108.135 84.24 108.405 ;
     RECT  2.16 108.675 84.24 108.945 ;
     RECT  2.16 109.215 84.24 109.485 ;
     RECT  2.16 109.755 84.24 110.025 ;
     RECT  2.16 110.295 84.24 110.565 ;
     RECT  2.16 110.835 84.24 111.105 ;
     RECT  2.16 111.375 84.24 111.645 ;
     RECT  2.16 111.915 84.24 112.185 ;
     RECT  2.16 112.455 84.24 112.725 ;
     RECT  2.16 112.995 84.24 113.265 ;
     RECT  2.16 113.535 84.24 113.805 ;
     RECT  2.16 114.075 84.24 114.345 ;
     RECT  2.16 114.615 84.24 114.885 ;
     RECT  2.16 115.155 84.24 115.425 ;
     RECT  2.16 115.695 84.24 115.965 ;
     RECT  2.16 116.235 84.24 116.505 ;
     RECT  2.16 116.775 84.24 117.045 ;
     RECT  2.16 117.315 84.24 117.585 ;
     RECT  2.16 117.855 84.24 118.125 ;
     RECT  2.16 118.395 84.24 118.665 ;
     RECT  2.16 118.935 84.24 119.205 ;
     RECT  2.16 119.475 84.24 119.745 ;
     RECT  2.16 120.015 84.24 120.285 ;
     RECT  2.16 120.555 84.24 120.825 ;
     RECT  2.16 121.095 84.24 121.365 ;
     RECT  2.16 121.635 84.24 121.905 ;
     RECT  2.16 122.175 84.24 122.445 ;
     RECT  2.16 122.715 84.24 122.985 ;
     RECT  2.16 123.255 84.24 123.525 ;
     RECT  2.16 123.795 84.24 124.065 ;
     RECT  2.16 124.335 84.24 124.605 ;
     RECT  2.16 124.875 84.24 125.145 ;
     RECT  2.16 125.415 84.24 125.685 ;
     RECT  2.16 125.955 84.24 126.225 ;
     RECT  2.16 126.495 84.24 126.765 ;
     RECT  2.16 127.035 84.24 127.305 ;
    LAYER M1 ;
     RECT  2.16 2.151 84.24 127.449 ;
    LAYER M2 ;
     RECT  0.211 12.528 2.16 12.546 ;
     RECT  0.211 23.328 2.16 23.346 ;
     RECT  0.211 29.034 2.16 29.052 ;
     RECT  0.535 32.346 2.16 32.364 ;
     RECT  1.147 49.014 2.16 49.032 ;
     RECT  0.535 79.056 2.16 79.074 ;
     RECT  0.535 80.91 2.16 80.928 ;
     RECT  0.211 89.982 2.16 90 ;
     RECT  0.211 95.112 2.16 95.13 ;
     RECT  2.16 2.151 22.819 127.449 ;
     RECT  22.819 2.106 23.675 127.449 ;
     RECT  23.675 2.151 29.083 127.449 ;
     RECT  29.083 2.106 29.327 127.449 ;
     RECT  29.327 2.151 48.307 127.449 ;
     RECT  48.307 2.106 49.127 127.449 ;
     RECT  49.127 2.151 84.24 127.449 ;
     RECT  84.24 4.968 84.407 4.986 ;
     RECT  84.24 6.12 84.407 6.138 ;
     RECT  84.24 7.398 84.407 7.416 ;
     RECT  84.24 8.514 84.407 8.532 ;
     RECT  84.24 10.98 84.407 10.998 ;
     RECT  84.24 13.608 84.407 13.626 ;
     RECT  84.24 14.76 84.407 14.778 ;
     RECT  84.24 16.11 84.407 16.128 ;
     RECT  84.24 18.198 84.407 18.216 ;
     RECT  84.24 19.62 84.407 19.638 ;
     RECT  84.24 20.7 84.407 20.718 ;
     RECT  84.24 21.78 84.407 21.798 ;
     RECT  84.24 23.13 84.407 23.148 ;
     RECT  84.24 24.48 84.407 24.498 ;
     RECT  84.24 25.758 84.407 25.776 ;
     RECT  84.24 26.64 84.407 26.658 ;
     RECT  84.24 27.918 84.407 27.936 ;
     RECT  84.24 30.42 84.407 30.438 ;
     RECT  84.24 33.048 84.407 33.066 ;
     RECT  84.24 33.93 84.407 33.948 ;
     RECT  84.24 35.208 84.407 35.226 ;
     RECT  84.24 36.36 84.407 36.378 ;
     RECT  84.24 41.22 84.407 41.238 ;
     RECT  84.24 42.3 84.407 42.318 ;
     RECT  84.24 43.65 84.407 43.668 ;
     RECT  84.24 44.73 84.407 44.748 ;
     RECT  84.24 46.008 84.407 46.026 ;
     RECT  84.24 47.43 84.407 47.448 ;
     RECT  84.24 48.438 84.407 48.456 ;
     RECT  84.24 50.94 84.407 50.958 ;
     RECT  84.24 52.02 84.407 52.038 ;
     RECT  84.24 53.37 84.407 53.388 ;
     RECT  84.24 55.8 84.407 55.818 ;
     RECT  84.24 56.88 84.407 56.898 ;
     RECT  84.24 57.96 84.407 57.978 ;
     RECT  84.24 60.66 84.407 60.678 ;
     RECT  84.24 63.018 84.407 63.036 ;
     RECT  84.24 64.17 84.407 64.188 ;
     RECT  84.24 65.52 84.407 65.538 ;
     RECT  84.24 67.95 84.407 67.968 ;
     RECT  84.24 68.958 84.407 68.976 ;
     RECT  84.24 71.46 84.407 71.478 ;
     RECT  84.24 72.54 84.407 72.558 ;
     RECT  84.24 74.088 84.407 74.106 ;
     RECT  84.24 77.67 84.407 77.688 ;
     RECT  84.24 80.1 84.407 80.118 ;
     RECT  84.24 83.538 84.407 83.556 ;
     RECT  84.24 84.888 84.407 84.906 ;
     RECT  84.24 86.04 84.407 86.058 ;
     RECT  84.24 88.2 84.407 88.218 ;
     RECT  84.24 92.178 84.407 92.196 ;
     RECT  84.24 93.33 84.407 93.348 ;
     RECT  84.24 94.338 84.407 94.356 ;
     RECT  84.24 95.688 84.407 95.706 ;
     RECT  84.24 98.19 84.407 98.208 ;
     RECT  84.24 100.278 84.407 100.296 ;
     RECT  84.24 101.7 84.407 101.718 ;
     RECT  84.24 104.292 84.407 104.31 ;
     RECT  84.24 106.56 84.407 106.578 ;
     RECT  84.24 108.99 84.407 109.008 ;
     RECT  84.24 112.77 84.407 112.788 ;
     RECT  84.24 116.208 84.407 116.226 ;
     RECT  84.24 117.63 84.407 117.648 ;
     RECT  84.24 9.9 84.947 9.918 ;
     RECT  84.24 16.956 84.947 16.974 ;
     RECT  84.24 29.34 84.947 29.358 ;
     RECT  84.24 37.98 84.947 38.7 ;
     RECT  84.24 40.068 84.947 40.086 ;
     RECT  84.24 49.86 84.947 49.878 ;
     RECT  84.24 54.45 84.947 54.468 ;
     RECT  84.24 59.238 84.947 59.256 ;
     RECT  84.24 61.74 84.947 61.758 ;
     RECT  84.24 70.38 84.947 70.398 ;
     RECT  84.24 74.97 84.947 74.988 ;
     RECT  84.24 82.53 84.947 82.548 ;
     RECT  84.24 90.828 84.947 90.846 ;
     RECT  84.24 96.84 84.947 96.858 ;
     RECT  84.24 99.162 84.947 99.18 ;
     RECT  84.24 102.978 84.947 102.996 ;
     RECT  84.24 105.21 84.947 105.228 ;
     RECT  84.24 107.91 84.947 107.928 ;
     RECT  84.24 110.34 84.947 110.358 ;
     RECT  84.24 111.42 84.947 111.438 ;
     RECT  84.24 87.39 85.523 87.408 ;
     RECT  84.24 89.478 85.523 89.496 ;
     RECT  84.24 118.71 85.523 118.728 ;
     RECT  84.24 119.682 85.523 119.7 ;
    LAYER M3 ;
     RECT  6.84 0.523 6.858 0.571 ;
     RECT  65.52 0.187 65.538 0.571 ;
     RECT  79.704 0.187 79.722 0.571 ;
     RECT  18.828 0.571 18.846 1.099 ;
     RECT  12.024 0.571 12.042 1.723 ;
     RECT  18.828 1.099 19.53 1.723 ;
     RECT  27.828 0.187 27.846 1.723 ;
     RECT  33.624 0.571 33.642 1.723 ;
     RECT  35.964 0.571 35.982 1.723 ;
     RECT  37.512 0.187 37.53 1.723 ;
     RECT  38.808 0.571 38.826 1.723 ;
     RECT  43.92 0.571 43.938 1.723 ;
     RECT  50.328 0.571 50.346 1.723 ;
     RECT  52.956 0.187 52.974 1.723 ;
     RECT  60.408 0.187 60.426 1.723 ;
     RECT  65.52 0.571 65.574 1.723 ;
     RECT  67.176 0.523 67.194 1.723 ;
     RECT  72.972 0.571 72.99 1.723 ;
     RECT  76.392 0.571 76.41 1.723 ;
     RECT  77.508 0.187 77.526 1.723 ;
     RECT  79.704 0.571 80.406 1.723 ;
     RECT  18.432 1.723 19.53 1.771 ;
     RECT  20.772 1.723 20.79 1.771 ;
     RECT  43.56 1.723 44.658 1.771 ;
     RECT  47.268 1.723 47.286 1.771 ;
     RECT  48.96 1.723 48.978 1.771 ;
     RECT  65.52 1.723 67.194 1.771 ;
     RECT  67.968 1.723 81.09 1.771 ;
     RECT  31.14 1.723 31.158 1.819 ;
     RECT  45.504 1.723 45.522 1.819 ;
     RECT  6.264 0.571 6.858 2.059 ;
     RECT  23.364 0.571 23.67 2.059 ;
     RECT  24.912 1.723 26.082 2.059 ;
     RECT  22.284 1.723 22.302 2.101 ;
     RECT  23.364 2.059 26.082 2.101 ;
     RECT  28.8 1.723 28.818 2.101 ;
     RECT  29.556 1.723 29.754 2.101 ;
     RECT  47.016 1.771 48.006 2.101 ;
     RECT  48.744 1.771 48.978 2.101 ;
     RECT  18.432 1.771 20.898 2.107 ;
     RECT  6.264 2.059 7.506 2.143 ;
     RECT  13.176 1.723 13.194 2.143 ;
     RECT  14.004 1.723 16.074 2.143 ;
     RECT  45.504 1.819 45.558 2.143 ;
     RECT  50.328 1.723 50.994 2.143 ;
     RECT  51.768 1.723 52.974 2.143 ;
     RECT  57.06 1.723 57.078 2.143 ;
     RECT  59.796 1.723 61.29 2.143 ;
     RECT  62.028 1.723 64.566 2.143 ;
     RECT  12.024 1.723 12.366 2.155 ;
     RECT  13.176 2.143 16.074 2.155 ;
     RECT  47.016 2.101 49.122 2.155 ;
     RECT  56.415 2.143 57.078 2.155 ;
     RECT  17.244 1.723 17.262 2.191 ;
     RECT  18.432 2.107 21.402 2.191 ;
     RECT  27.72 1.723 27.846 2.191 ;
     RECT  28.8 2.101 29.754 2.191 ;
     RECT  31.14 1.819 31.194 2.191 ;
     RECT  32.544 1.723 36.342 2.191 ;
     RECT  40.14 1.723 40.77 2.191 ;
     RECT  41.616 1.723 42.102 2.191 ;
     RECT  43.164 1.771 44.658 2.191 ;
     RECT  45.504 2.143 45.705 2.191 ;
     RECT  46.584 2.155 49.122 2.191 ;
     RECT  50.328 2.143 52.974 2.191 ;
     RECT  54.828 1.723 55.674 2.191 ;
     RECT  56.415 2.155 57.51 2.191 ;
     RECT  37.188 1.723 39.402 2.227 ;
     RECT  58.356 1.723 58.59 2.227 ;
     RECT  59.796 2.143 64.566 2.227 ;
     RECT  8.928 1.723 10.998 2.251 ;
     RECT  12.024 2.155 16.074 2.251 ;
     RECT  37.116 2.227 39.402 2.251 ;
     RECT  40.14 2.191 42.102 2.251 ;
     RECT  4.284 1.723 5.382 2.255 ;
     RECT  6.264 2.143 7.905 2.263 ;
     RECT  8.928 2.251 16.074 2.263 ;
     RECT  22.284 2.101 26.082 2.263 ;
     RECT  26.928 1.723 26.946 2.263 ;
     RECT  31.14 2.191 36.342 2.263 ;
     RECT  59.328 2.227 64.566 2.263 ;
     RECT  65.52 1.771 81.09 2.263 ;
     RECT  30.78 2.263 36.342 2.299 ;
     RECT  37.116 2.251 42.102 2.299 ;
     RECT  53.784 2.191 57.51 2.299 ;
     RECT  58.284 2.227 58.59 2.299 ;
     RECT  6.264 2.263 16.074 2.335 ;
     RECT  16.848 2.191 21.402 2.335 ;
     RECT  4.752 2.255 5.382 2.371 ;
     RECT  6.264 2.335 21.402 2.371 ;
     RECT  22.212 2.263 26.946 2.371 ;
     RECT  27.72 2.191 29.754 2.371 ;
     RECT  30.528 2.299 36.342 2.371 ;
     RECT  37.08 2.299 42.102 2.371 ;
     RECT  43.164 2.191 52.974 2.371 ;
     RECT  53.784 2.299 58.59 2.371 ;
     RECT  59.328 2.263 81.09 2.371 ;
     RECT  81.936 1.723 81.954 2.371 ;
     RECT  2.415 2.143 2.505 2.413 ;
     RECT  83.415 2.143 83.505 2.413 ;
     RECT  4.752 2.371 29.79 2.641 ;
     RECT  30.528 2.371 82.098 2.641 ;
     RECT  4.752 2.641 82.278 3.451 ;
     RECT  4.392 3.451 82.278 3.685 ;
     RECT  3.708 3.685 82.278 3.721 ;
     RECT  3.708 3.721 82.35 3.839 ;
     RECT  2.415 2.413 2.697 3.955 ;
     RECT  3.708 3.839 33.102 3.955 ;
     RECT  33.876 3.839 82.35 4.109 ;
     RECT  83.415 2.413 83.697 4.261 ;
     RECT  0.216 4.219 0.234 4.315 ;
     RECT  0.216 4.315 0.342 4.445 ;
     RECT  0.216 4.445 0.234 4.493 ;
     RECT  2.415 3.955 33.102 4.729 ;
     RECT  33.876 4.109 82.17 4.729 ;
     RECT  2.415 4.729 82.17 4.747 ;
     RECT  2.34 4.747 82.17 4.891 ;
     RECT  82.908 4.261 83.697 4.891 ;
     RECT  2.304 4.891 82.17 4.927 ;
     RECT  82.908 4.891 84.402 4.927 ;
     RECT  2.304 4.927 84.402 4.955 ;
     RECT  81.288 4.955 84.402 4.991 ;
     RECT  81.288 4.991 83.697 5.189 ;
     RECT  2.304 4.955 80.55 5.707 ;
     RECT  81.288 5.189 82.17 5.707 ;
     RECT  2.304 5.707 82.17 5.899 ;
     RECT  2.268 5.899 82.17 6.007 ;
     RECT  82.944 5.189 83.697 6.007 ;
     RECT  2.268 6.007 83.697 6.035 ;
     RECT  2.304 6.035 83.697 6.043 ;
     RECT  2.304 6.043 84.402 6.143 ;
     RECT  2.304 6.143 83.697 6.173 ;
     RECT  43.524 6.173 83.697 6.269 ;
     RECT  81.396 6.269 82.17 6.575 ;
     RECT  43.524 6.269 80.55 6.719 ;
     RECT  76.572 6.719 80.55 6.809 ;
     RECT  76.572 6.809 76.95 7.115 ;
     RECT  2.304 6.173 42.786 7.231 ;
     RECT  43.524 6.719 75.834 7.231 ;
     RECT  82.944 6.269 83.697 7.339 ;
     RECT  81.468 6.575 82.134 7.393 ;
     RECT  82.944 7.339 84.402 7.393 ;
     RECT  81.468 7.393 84.402 7.421 ;
     RECT  2.304 7.231 75.834 7.655 ;
     RECT  81.468 7.421 83.697 7.655 ;
     RECT  2.304 7.655 35.982 7.763 ;
     RECT  81.468 7.655 82.206 7.771 ;
     RECT  77.796 6.809 80.55 7.867 ;
     RECT  81.396 7.771 82.206 7.867 ;
     RECT  77.796 7.867 82.206 8.303 ;
     RECT  76.932 7.115 76.95 8.311 ;
     RECT  77.796 8.303 82.134 8.465 ;
     RECT  82.944 7.655 83.697 8.491 ;
     RECT  76.716 8.311 76.95 8.509 ;
     RECT  82.944 8.491 84.402 8.537 ;
     RECT  2.304 7.763 35.946 8.539 ;
     RECT  36.828 7.655 75.834 8.539 ;
     RECT  2.304 8.539 75.834 8.807 ;
     RECT  78.015 8.465 82.134 9.085 ;
     RECT  82.944 8.537 83.697 9.085 ;
     RECT  50.148 8.807 75.834 9.113 ;
     RECT  2.304 8.807 49.302 9.211 ;
     RECT  78.015 9.085 83.697 9.275 ;
     RECT  75.708 9.113 75.834 9.391 ;
     RECT  76.716 8.509 77.094 9.391 ;
     RECT  50.148 9.113 74.934 9.392 ;
     RECT  2.268 9.211 49.302 9.643 ;
     RECT  50.148 9.392 74.862 9.643 ;
     RECT  2.268 9.643 74.862 9.653 ;
     RECT  0.216 9.499 0.234 9.821 ;
     RECT  2.304 9.653 74.862 9.923 ;
     RECT  84.924 9.643 84.942 9.923 ;
     RECT  78.015 9.275 82.206 10.021 ;
     RECT  82.944 9.275 83.697 10.021 ;
     RECT  2.304 9.923 74.826 10.253 ;
     RECT  74.664 10.253 74.826 10.319 ;
     RECT  75.708 9.391 77.094 10.499 ;
     RECT  78.015 10.021 83.697 10.661 ;
     RECT  78.015 10.661 80.55 10.769 ;
     RECT  2.304 10.253 73.926 10.795 ;
     RECT  81.324 10.661 83.697 10.939 ;
     RECT  81.324 10.939 84.402 11.003 ;
     RECT  2.232 10.795 73.926 11.011 ;
     RECT  75.816 10.499 77.094 11.011 ;
     RECT  78.015 10.769 80.478 11.011 ;
     RECT  74.808 10.319 74.826 11.227 ;
     RECT  2.232 11.011 73.962 11.281 ;
     RECT  74.808 11.227 75.006 11.281 ;
     RECT  2.232 11.281 75.006 11.408 ;
     RECT  75.816 11.011 80.478 11.435 ;
     RECT  70.632 11.408 75.006 11.659 ;
     RECT  75.816 11.435 80.298 11.659 ;
     RECT  70.632 11.659 80.298 11.669 ;
     RECT  2.232 11.408 69.678 11.849 ;
     RECT  70.632 11.669 76.986 11.984 ;
     RECT  81.324 11.003 83.697 12.091 ;
     RECT  70.632 11.984 76.734 12.119 ;
     RECT  81.324 12.091 83.826 12.353 ;
     RECT  77.724 11.669 80.298 12.361 ;
     RECT  81.324 12.353 83.697 12.361 ;
     RECT  0.216 12.523 0.234 12.56 ;
     RECT  70.632 12.119 76.518 12.605 ;
     RECT  70.632 12.605 76.446 12.749 ;
     RECT  75.816 12.749 76.446 12.821 ;
     RECT  2.304 11.849 69.678 12.829 ;
     RECT  70.632 12.749 75.006 12.829 ;
     RECT  2.304 12.829 75.006 13.055 ;
     RECT  77.724 12.361 83.697 13.387 ;
     RECT  2.304 13.055 73.602 13.531 ;
     RECT  77.724 13.387 84.402 13.631 ;
     RECT  2.268 13.531 73.602 13.865 ;
     RECT  76.428 12.821 76.446 13.865 ;
     RECT  2.304 13.865 73.602 13.981 ;
     RECT  2.304 13.981 73.674 14.071 ;
     RECT  74.412 13.055 75.006 14.071 ;
     RECT  2.304 14.071 75.006 14.189 ;
     RECT  2.304 14.189 73.602 14.279 ;
     RECT  77.724 13.631 83.697 14.539 ;
     RECT  77.724 14.539 84.402 14.783 ;
     RECT  2.304 14.279 71.874 15.019 ;
     RECT  72.615 14.279 73.602 15.019 ;
     RECT  77.724 14.783 83.697 15.691 ;
     RECT  2.304 15.019 73.602 15.727 ;
     RECT  74.412 14.189 75.006 15.727 ;
     RECT  2.304 15.727 75.006 15.899 ;
     RECT  76.644 13.981 76.662 16.025 ;
     RECT  77.724 15.691 84.402 16.133 ;
     RECT  74.412 15.899 75.006 16.141 ;
     RECT  2.304 15.899 73.422 16.699 ;
     RECT  74.412 16.141 75.474 16.807 ;
     RECT  2.268 16.699 73.422 16.943 ;
     RECT  77.724 16.133 83.697 16.951 ;
     RECT  84.924 16.951 84.942 17.021 ;
     RECT  77.724 16.951 83.97 17.105 ;
     RECT  74.412 16.807 75.51 17.165 ;
     RECT  77.724 17.105 83.697 17.455 ;
     RECT  74.628 17.165 75.51 17.879 ;
     RECT  77.58 17.455 83.697 18.139 ;
     RECT  77.58 18.139 84.402 18.221 ;
     RECT  77.58 18.221 83.697 18.769 ;
     RECT  74.988 17.879 75.51 18.811 ;
     RECT  76.932 18.769 83.697 18.845 ;
     RECT  76.932 18.845 76.986 18.959 ;
     RECT  74.988 18.811 76.05 19.181 ;
     RECT  2.304 16.943 73.422 19.435 ;
     RECT  78.015 18.845 83.697 19.435 ;
     RECT  78.015 19.435 84.402 19.643 ;
     RECT  2.268 19.435 73.422 19.805 ;
     RECT  74.988 19.181 75.51 20.191 ;
     RECT  2.304 19.805 73.422 20.219 ;
     RECT  74.988 20.191 75.978 20.539 ;
     RECT  74.844 20.539 75.978 20.579 ;
     RECT  78.015 19.643 83.697 20.587 ;
     RECT  78.015 20.587 84.402 20.723 ;
     RECT  2.304 20.219 72.897 21.001 ;
     RECT  78.015 20.723 83.826 21.155 ;
     RECT  2.304 21.001 72.99 21.595 ;
     RECT  81.72 21.155 83.826 21.739 ;
     RECT  2.268 21.595 72.99 21.767 ;
     RECT  81.72 21.739 84.402 21.803 ;
     RECT  2.304 21.767 72.99 22.045 ;
     RECT  2.304 22.045 73.206 22.513 ;
     RECT  81.72 21.803 83.697 23.035 ;
     RECT  78.015 21.155 80.982 23.125 ;
     RECT  81.72 23.035 84.402 23.125 ;
     RECT  78.015 23.125 84.402 23.153 ;
     RECT  2.304 22.513 73.386 23.179 ;
     RECT  78.015 23.153 83.697 23.279 ;
     RECT  2.268 23.179 73.386 23.315 ;
     RECT  0.216 23.323 0.234 23.501 ;
     RECT  81.72 23.279 83.697 24.187 ;
     RECT  81.72 24.187 84.402 24.503 ;
     RECT  81.72 24.503 83.898 24.629 ;
     RECT  76.968 18.959 76.986 24.709 ;
     RECT  78.015 23.279 80.982 24.745 ;
     RECT  81.72 24.629 83.826 24.745 ;
     RECT  78.015 24.745 83.826 24.797 ;
     RECT  81.72 24.797 83.826 25.037 ;
     RECT  82.008 25.037 83.826 25.483 ;
     RECT  82.008 25.483 84.402 25.781 ;
     RECT  2.304 23.315 73.386 25.951 ;
     RECT  74.124 25.861 74.142 25.951 ;
     RECT  74.988 20.579 75.978 25.951 ;
     RECT  76.824 24.709 76.986 25.979 ;
     RECT  82.008 25.781 83.697 26.015 ;
     RECT  78.015 24.797 80.982 26.257 ;
     RECT  82.008 26.015 82.494 26.257 ;
     RECT  78.015 26.257 82.494 26.333 ;
     RECT  78.015 26.333 80.982 26.491 ;
     RECT  77.904 26.491 80.982 26.528 ;
     RECT  83.415 26.015 83.697 26.629 ;
     RECT  83.415 26.629 84.402 26.669 ;
     RECT  82.008 26.333 82.494 26.941 ;
     RECT  83.415 26.669 83.697 26.941 ;
     RECT  82.008 26.941 83.697 27.203 ;
     RECT  78.015 26.528 80.982 27.211 ;
     RECT  82.008 27.203 82.494 27.211 ;
     RECT  78.015 27.211 82.494 27.341 ;
     RECT  0.252 27.499 0.27 27.629 ;
     RECT  83.415 27.203 83.697 27.787 ;
     RECT  83.415 27.787 84.402 27.941 ;
     RECT  2.304 25.951 75.978 28.075 ;
     RECT  83.415 27.941 83.79 28.175 ;
     RECT  82.008 27.341 82.494 28.183 ;
     RECT  78.015 27.341 81.018 28.247 ;
     RECT  2.268 28.075 75.978 28.283 ;
     RECT  81.828 28.183 82.494 28.319 ;
     RECT  2.304 28.283 75.978 28.525 ;
     RECT  76.824 25.979 76.842 28.525 ;
     RECT  2.304 28.525 76.842 28.921 ;
     RECT  2.304 28.921 76.986 28.973 ;
     RECT  2.304 28.973 76.842 29.057 ;
     RECT  0.216 29.029 0.234 29.117 ;
     RECT  84.924 29.083 84.942 29.363 ;
     RECT  82.008 28.319 82.494 29.371 ;
     RECT  83.415 28.175 83.697 29.371 ;
     RECT  78.015 28.247 80.982 29.731 ;
     RECT  2.304 29.057 3.546 30.145 ;
     RECT  4.32 29.057 76.842 30.145 ;
     RECT  82.008 29.371 83.697 30.235 ;
     RECT  78.015 29.731 81.234 30.307 ;
     RECT  77.796 30.307 81.234 30.331 ;
     RECT  82.008 30.235 84.402 30.331 ;
     RECT  77.796 30.331 84.402 30.365 ;
     RECT  78.015 30.365 84.402 30.443 ;
     RECT  78.015 30.443 83.697 31.495 ;
     RECT  78.015 31.495 83.826 31.565 ;
     RECT  2.304 30.145 76.842 31.819 ;
     RECT  2.268 31.819 76.842 31.955 ;
     RECT  78.015 31.565 83.697 32.683 ;
     RECT  0.54 32.341 0.558 32.717 ;
     RECT  2.304 31.955 76.842 32.881 ;
     RECT  78.015 32.683 84.402 33.071 ;
     RECT  2.304 32.881 77.274 33.403 ;
     RECT  78.015 33.071 83.697 33.403 ;
     RECT  2.268 33.403 83.697 33.449 ;
     RECT  78.015 33.449 83.697 33.835 ;
     RECT  78.015 33.835 84.402 33.953 ;
     RECT  78.015 33.953 83.697 35.131 ;
     RECT  78.015 35.131 84.402 35.231 ;
     RECT  0.216 35.131 0.234 35.261 ;
     RECT  78.015 35.231 83.697 36.283 ;
     RECT  78.015 36.283 84.402 36.383 ;
     RECT  0.216 37.291 0.234 37.421 ;
     RECT  2.304 33.449 77.274 38.309 ;
     RECT  84.924 37.579 84.942 38.765 ;
     RECT  78.015 36.383 83.697 38.821 ;
     RECT  78.015 38.821 84.114 38.939 ;
     RECT  0.252 39.163 0.27 39.293 ;
     RECT  2.304 38.309 77.238 39.352 ;
     RECT  78.015 38.939 83.697 39.352 ;
     RECT  2.304 39.352 83.697 39.389 ;
     RECT  2.304 39.389 77.238 39.785 ;
     RECT  2.304 39.785 2.697 39.883 ;
     RECT  84.924 39.883 84.942 40.091 ;
     RECT  78.015 39.389 83.697 40.171 ;
     RECT  78.015 40.171 84.042 40.289 ;
     RECT  2.268 39.883 2.697 40.865 ;
     RECT  2.304 40.865 2.697 40.909 ;
     RECT  3.42 39.785 77.238 40.909 ;
     RECT  78.015 40.289 83.697 40.909 ;
     RECT  2.304 40.909 83.697 41.179 ;
     RECT  2.304 41.179 84.402 41.243 ;
     RECT  0.252 41.323 0.27 41.453 ;
     RECT  2.304 41.243 83.697 42.295 ;
     RECT  2.304 42.295 84.402 42.365 ;
     RECT  2.304 42.365 83.697 42.619 ;
     RECT  2.268 42.619 83.697 42.755 ;
     RECT  2.304 42.755 83.697 43.627 ;
     RECT  2.304 43.627 84.402 43.673 ;
     RECT  2.304 43.673 83.697 44.725 ;
     RECT  2.304 44.725 84.402 44.813 ;
     RECT  2.304 44.813 83.697 45.931 ;
     RECT  2.304 45.931 84.402 46.031 ;
     RECT  0.396 46.363 0.414 46.507 ;
     RECT  0.288 46.507 0.414 46.541 ;
     RECT  0.288 46.541 0.306 46.637 ;
     RECT  2.304 46.031 83.697 47.191 ;
     RECT  2.304 47.191 83.934 47.227 ;
     RECT  2.304 47.227 84.402 47.453 ;
     RECT  2.304 47.453 83.697 48.379 ;
     RECT  2.304 48.379 84.402 48.461 ;
     RECT  1.152 49.003 1.17 49.043 ;
     RECT  84.924 49.675 84.942 49.883 ;
     RECT  2.304 48.461 83.697 49.891 ;
     RECT  2.304 49.891 83.826 50.045 ;
     RECT  2.304 50.045 83.697 50.431 ;
     RECT  2.268 50.431 83.697 50.827 ;
     RECT  2.268 50.827 84.402 50.963 ;
     RECT  2.268 50.963 83.697 51.979 ;
     RECT  2.268 51.979 84.402 52.043 ;
     RECT  2.268 52.043 83.697 52.511 ;
     RECT  2.304 52.511 83.697 53.275 ;
     RECT  2.304 53.275 84.402 53.393 ;
     RECT  84.924 54.427 84.942 54.473 ;
     RECT  2.304 53.393 83.697 55.003 ;
     RECT  2.268 55.003 83.697 55.283 ;
     RECT  0.216 55.435 0.234 55.565 ;
     RECT  2.304 55.283 83.697 55.723 ;
     RECT  2.304 55.723 84.402 55.823 ;
     RECT  2.304 55.823 83.697 56.869 ;
     RECT  2.304 56.869 84.402 56.909 ;
     RECT  0.216 57.595 0.234 57.725 ;
     RECT  2.304 56.909 83.697 57.955 ;
     RECT  2.304 57.955 84.402 58.061 ;
     RECT  2.304 58.061 83.697 58.315 ;
     RECT  2.268 58.315 83.697 58.955 ;
     RECT  2.304 58.955 83.697 59.071 ;
     RECT  2.304 59.071 83.934 59.189 ;
     RECT  84.924 59.233 84.942 59.357 ;
     RECT  2.304 59.189 83.697 60.475 ;
     RECT  2.304 60.475 84.402 60.683 ;
     RECT  2.304 60.683 83.934 60.845 ;
     RECT  84.924 61.735 84.942 61.805 ;
     RECT  2.304 60.845 83.697 62.923 ;
     RECT  2.304 62.923 84.402 63.041 ;
     RECT  2.304 63.041 83.697 63.419 ;
     RECT  2.304 63.419 53.982 63.779 ;
     RECT  54.756 63.419 83.697 64.075 ;
     RECT  54.756 64.075 84.402 64.193 ;
     RECT  2.304 63.779 53.874 65.011 ;
     RECT  54.756 64.193 83.697 65.011 ;
     RECT  2.304 65.011 83.697 65.371 ;
     RECT  2.268 65.371 84.402 65.543 ;
     RECT  2.304 65.543 83.697 66.523 ;
     RECT  2.304 66.523 83.826 66.623 ;
     RECT  0.252 67.531 0.27 67.661 ;
     RECT  2.304 66.623 83.697 67.819 ;
     RECT  2.304 67.819 84.402 67.973 ;
     RECT  2.304 67.973 83.697 68.953 ;
     RECT  2.304 68.953 84.402 69.005 ;
     RECT  2.304 69.005 83.697 69.251 ;
     RECT  2.304 69.251 2.754 69.691 ;
     RECT  2.268 69.691 2.754 69.755 ;
     RECT  2.304 69.755 2.754 69.979 ;
     RECT  2.304 69.979 2.79 70.141 ;
     RECT  3.528 69.251 83.697 70.141 ;
     RECT  84.924 70.123 84.942 70.403 ;
     RECT  2.304 70.141 83.697 70.699 ;
     RECT  2.268 70.699 83.697 70.835 ;
     RECT  0.252 71.275 0.27 71.405 ;
     RECT  2.304 70.835 83.697 71.419 ;
     RECT  2.304 71.419 84.402 71.483 ;
     RECT  2.304 71.483 83.898 71.609 ;
     RECT  2.304 71.609 83.697 72.535 ;
     RECT  2.304 72.535 84.402 72.605 ;
     RECT  2.304 72.605 83.754 72.725 ;
     RECT  2.304 72.725 83.697 73.867 ;
     RECT  2.304 73.867 84.402 74.111 ;
     RECT  84.924 74.965 84.942 75.053 ;
     RECT  2.304 74.111 83.697 75.595 ;
     RECT  2.268 75.595 83.697 75.839 ;
     RECT  2.304 75.839 83.697 76.171 ;
     RECT  2.304 76.171 83.826 76.271 ;
     RECT  0.252 76.171 0.27 76.301 ;
     RECT  2.304 76.271 83.697 77.179 ;
     RECT  2.268 77.179 83.697 77.467 ;
     RECT  2.268 77.467 84.402 77.585 ;
     RECT  2.304 77.585 84.402 77.693 ;
     RECT  0.252 77.755 0.27 77.885 ;
     RECT  2.304 77.693 83.934 78.619 ;
     RECT  2.304 78.619 84.042 78.665 ;
     RECT  2.304 78.665 83.697 78.763 ;
     RECT  2.268 78.763 83.697 78.935 ;
     RECT  0.54 79.051 0.558 79.373 ;
     RECT  2.304 78.935 83.697 79.915 ;
     RECT  2.304 79.915 84.402 80.123 ;
     RECT  0.54 80.905 0.558 80.957 ;
     RECT  2.304 80.123 83.697 81.067 ;
     RECT  2.304 81.067 83.826 81.131 ;
     RECT  2.304 81.131 83.697 81.203 ;
     RECT  2.304 81.203 3.366 81.239 ;
     RECT  4.104 81.203 83.697 82.147 ;
     RECT  2.304 81.239 2.97 82.219 ;
     RECT  3.996 82.147 83.697 82.219 ;
     RECT  84.924 82.219 84.942 82.553 ;
     RECT  2.304 82.219 83.697 83.291 ;
     RECT  3.528 83.291 83.697 83.515 ;
     RECT  3.528 83.515 84.402 83.561 ;
     RECT  2.304 83.291 2.697 84.109 ;
     RECT  3.528 83.561 83.697 84.109 ;
     RECT  2.304 84.109 83.697 84.667 ;
     RECT  2.304 84.667 84.402 84.911 ;
     RECT  2.304 84.911 83.697 85.963 ;
     RECT  2.304 85.963 84.402 86.063 ;
     RECT  2.304 86.063 83.697 87.385 ;
     RECT  85.5 87.115 85.518 87.413 ;
     RECT  2.268 87.385 83.697 87.437 ;
     RECT  2.304 87.437 83.697 88.195 ;
     RECT  2.304 88.195 84.402 88.301 ;
     RECT  85.5 89.473 85.518 89.597 ;
     RECT  0.216 89.977 0.234 90.173 ;
     RECT  84.924 90.715 84.942 90.851 ;
     RECT  2.304 88.301 83.697 90.931 ;
     RECT  2.304 90.931 84.042 91.193 ;
     RECT  2.304 91.193 83.697 92.011 ;
     RECT  2.304 92.011 84.402 92.201 ;
     RECT  2.304 92.201 83.934 93.163 ;
     RECT  2.304 93.163 84.402 93.353 ;
     RECT  2.304 93.353 83.697 93.883 ;
     RECT  2.268 93.883 83.697 94.055 ;
     RECT  2.304 94.055 83.697 94.315 ;
     RECT  2.304 94.315 84.402 94.361 ;
     RECT  0.252 94.603 0.27 94.733 ;
     RECT  0.216 95.107 0.234 95.213 ;
     RECT  2.304 94.361 83.697 95.611 ;
     RECT  2.304 95.611 84.402 95.711 ;
     RECT  2.304 95.711 83.697 96.619 ;
     RECT  2.268 96.619 83.697 96.827 ;
     RECT  84.924 96.763 84.942 96.863 ;
     RECT  2.304 96.827 83.697 97.771 ;
     RECT  2.268 97.771 83.697 97.835 ;
     RECT  2.304 97.835 83.697 98.059 ;
     RECT  2.304 98.059 84.402 98.213 ;
     RECT  84.924 99.157 84.942 99.245 ;
     RECT  2.304 98.213 83.697 100.273 ;
     RECT  2.304 100.273 84.402 100.397 ;
     RECT  0.252 101.227 0.27 101.357 ;
     RECT  2.304 100.397 83.697 101.659 ;
     RECT  2.304 101.659 84.402 101.723 ;
     RECT  2.304 101.723 83.898 102.091 ;
     RECT  2.268 102.091 83.898 102.155 ;
     RECT  2.268 102.155 83.79 102.263 ;
     RECT  2.304 102.263 83.79 102.659 ;
     RECT  84.924 102.811 84.942 103.001 ;
     RECT  0.252 103.387 0.27 103.517 ;
     RECT  2.304 102.659 83.697 104.107 ;
     RECT  2.304 104.107 84.402 104.251 ;
     RECT  2.268 104.251 84.402 104.315 ;
     RECT  2.268 104.315 83.898 104.387 ;
     RECT  2.304 104.387 83.898 104.549 ;
     RECT  2.304 104.549 83.697 104.891 ;
     RECT  2.304 104.891 3.042 105.259 ;
     RECT  84.924 105.205 84.942 105.293 ;
     RECT  2.268 105.259 3.042 105.395 ;
     RECT  2.304 105.395 3.042 105.907 ;
     RECT  3.816 104.891 83.697 105.907 ;
     RECT  2.304 105.907 83.697 106.321 ;
     RECT  2.268 106.321 83.697 106.411 ;
     RECT  2.268 106.411 84.402 106.583 ;
     RECT  2.268 106.583 84.042 107.123 ;
     RECT  84.924 107.707 84.942 107.933 ;
     RECT  0.252 108.571 0.27 108.701 ;
     RECT  2.304 107.123 84.042 108.859 ;
     RECT  2.304 108.859 84.402 109.013 ;
     RECT  84.924 110.155 84.942 110.363 ;
     RECT  84.924 111.307 84.942 111.443 ;
     RECT  2.304 109.013 84.042 112.459 ;
     RECT  2.304 112.459 84.402 112.793 ;
     RECT  2.304 112.793 84.042 113.323 ;
     RECT  2.268 113.323 84.042 113.495 ;
     RECT  2.304 113.495 84.042 114.475 ;
     RECT  2.268 114.475 84.042 114.575 ;
     RECT  2.304 114.575 84.042 116.197 ;
     RECT  2.304 116.197 84.402 116.237 ;
     RECT  2.304 116.237 84.042 116.635 ;
     RECT  2.268 116.635 84.042 117.275 ;
     RECT  2.304 117.275 84.042 117.355 ;
     RECT  2.304 117.355 84.402 117.653 ;
     RECT  85.5 118.507 85.518 118.733 ;
     RECT  2.304 117.653 84.042 119.551 ;
     RECT  2.304 119.551 84.114 119.669 ;
     RECT  2.304 119.669 84.042 119.705 ;
     RECT  85.5 119.677 85.518 119.837 ;
     RECT  2.304 119.705 59.31 120.631 ;
     RECT  60.228 119.705 84.042 120.631 ;
     RECT  2.304 120.631 84.114 120.785 ;
     RECT  2.304 120.785 59.382 120.955 ;
     RECT  60.264 120.785 84.114 120.989 ;
     RECT  2.268 120.955 59.382 121.055 ;
     RECT  2.268 121.055 46.206 121.703 ;
     RECT  60.264 120.989 84.042 121.703 ;
     RECT  2.304 121.703 46.206 121.801 ;
     RECT  46.944 121.055 59.382 121.801 ;
     RECT  60.264 121.703 81.234 121.801 ;
     RECT  2.304 121.801 81.234 121.937 ;
     RECT  82.044 121.703 84.042 122.171 ;
     RECT  82.368 122.171 84.042 122.369 ;
     RECT  83.415 122.369 84.042 122.513 ;
     RECT  0.216 122.539 0.234 122.669 ;
     RECT  82.368 122.369 82.602 123.053 ;
     RECT  2.304 121.937 80.982 123.115 ;
     RECT  82.584 123.053 82.602 123.151 ;
     RECT  83.415 122.513 83.697 123.151 ;
     RECT  2.268 123.115 80.982 123.287 ;
     RECT  82.584 123.151 83.697 123.331 ;
     RECT  82.584 123.331 83.862 123.403 ;
     RECT  2.304 123.287 80.982 123.593 ;
     RECT  5.688 123.593 80.982 123.601 ;
     RECT  5.688 123.601 81.522 123.719 ;
     RECT  82.584 123.403 84.114 123.719 ;
     RECT  83.415 123.719 83.862 123.755 ;
     RECT  82.584 123.719 82.602 123.827 ;
     RECT  5.688 123.719 80.946 124.067 ;
     RECT  5.688 124.067 13.734 124.097 ;
     RECT  2.304 123.593 4.95 124.363 ;
     RECT  5.688 124.097 8.37 124.363 ;
     RECT  14.688 124.067 80.946 124.367 ;
     RECT  83.415 123.755 83.697 124.555 ;
     RECT  14.76 124.367 80.946 124.565 ;
     RECT  2.304 124.363 8.37 124.699 ;
     RECT  83.415 124.555 84.114 124.771 ;
     RECT  83.304 124.771 84.114 124.829 ;
     RECT  2.268 124.699 8.37 124.835 ;
     RECT  2.304 124.835 8.37 124.843 ;
     RECT  9.144 124.097 13.734 124.843 ;
     RECT  83.415 124.829 84.114 125.069 ;
     RECT  2.304 124.843 14.022 125.105 ;
     RECT  83.415 125.069 83.862 125.105 ;
     RECT  2.34 125.105 14.022 125.165 ;
     RECT  3.42 125.165 14.022 125.185 ;
     RECT  14.76 124.565 74.538 125.185 ;
     RECT  2.34 125.165 2.697 125.213 ;
     RECT  75.276 124.565 80.946 125.419 ;
     RECT  81.72 125.347 81.738 125.419 ;
     RECT  3.42 125.185 74.538 125.491 ;
     RECT  75.276 125.419 81.99 125.491 ;
     RECT  3.42 125.491 81.99 125.609 ;
     RECT  3.42 125.609 81.738 125.951 ;
     RECT  2.415 125.213 2.697 125.995 ;
     RECT  3.42 125.951 3.582 125.995 ;
     RECT  4.572 125.951 81.738 126.029 ;
     RECT  2.415 125.995 3.582 126.149 ;
     RECT  4.608 126.029 81.738 126.149 ;
     RECT  59.868 126.149 81.738 126.499 ;
     RECT  59.868 126.499 82.026 126.509 ;
     RECT  59.868 126.509 65.97 126.689 ;
     RECT  4.608 126.149 59.094 126.769 ;
     RECT  4.428 126.769 59.094 126.959 ;
     RECT  59.868 126.689 65.898 126.959 ;
     RECT  66.708 126.509 82.026 126.959 ;
     RECT  4.536 126.959 59.094 126.967 ;
     RECT  59.868 126.959 64.998 126.967 ;
     RECT  71.352 126.959 76.374 126.989 ;
     RECT  77.148 126.959 82.026 127.075 ;
     RECT  4.536 126.967 64.998 127.103 ;
     RECT  4.536 127.103 6.858 127.133 ;
     RECT  7.632 127.103 42.534 127.133 ;
     RECT  43.308 127.103 64.998 127.133 ;
     RECT  2.415 126.149 2.697 127.187 ;
     RECT  83.415 125.105 83.697 127.187 ;
     RECT  5.076 127.133 6.858 127.229 ;
     RECT  7.632 127.133 8.694 127.229 ;
     RECT  9.468 127.133 22.086 127.229 ;
     RECT  22.932 127.133 42.534 127.229 ;
     RECT  43.452 127.133 64.998 127.229 ;
     RECT  65.808 126.959 65.826 127.229 ;
     RECT  66.708 126.959 70.614 127.229 ;
     RECT  71.352 126.989 75.942 127.229 ;
     RECT  77.148 127.075 82.53 127.229 ;
     RECT  5.076 127.229 6.822 127.265 ;
     RECT  19.764 127.229 22.086 127.265 ;
     RECT  28.188 127.229 33.894 127.265 ;
     RECT  69.732 127.229 70.362 127.265 ;
     RECT  72.504 127.229 73.35 127.265 ;
     RECT  74.592 127.229 74.754 127.265 ;
     RECT  75.672 127.229 75.69 127.265 ;
     RECT  10.764 127.229 12.33 127.301 ;
     RECT  13.104 127.229 18.705 127.301 ;
     RECT  19.764 127.265 21.69 127.301 ;
     RECT  34.704 127.229 36.558 127.301 ;
     RECT  42.516 127.229 42.534 127.301 ;
     RECT  45.54 127.229 46.53 127.301 ;
     RECT  47.268 127.229 54.018 127.301 ;
     RECT  55.224 127.229 57.942 127.301 ;
     RECT  60.3 127.229 62.766 127.301 ;
     RECT  19.944 127.301 21.69 127.337 ;
     RECT  22.932 127.229 27.126 127.373 ;
     RECT  47.7 127.301 49.914 127.373 ;
     RECT  51.015 127.301 54.018 127.373 ;
     RECT  6.516 127.265 6.822 127.409 ;
     RECT  13.215 127.301 18.705 127.409 ;
     RECT  19.944 127.337 21.546 127.409 ;
     RECT  23.868 127.373 27.126 127.409 ;
     RECT  37.692 127.229 38.286 127.409 ;
     RECT  39.096 127.229 39.15 127.409 ;
     RECT  52.128 127.373 54.018 127.409 ;
     RECT  56.052 127.301 57.942 127.409 ;
     RECT  58.824 127.229 59.094 127.409 ;
     RECT  60.3 127.301 61.905 127.409 ;
     RECT  63.612 127.229 64.17 127.409 ;
     RECT  66.816 127.229 67.305 127.409 ;
     RECT  68.22 127.229 68.238 127.409 ;
     RECT  69.732 127.265 69.75 127.409 ;
     RECT  77.148 127.229 77.166 127.409 ;
     RECT  79.272 127.229 79.578 127.409 ;
     RECT  80.892 127.229 81.054 127.409 ;
     RECT  74.736 127.265 74.754 127.421 ;
     RECT  2.415 127.187 2.505 127.457 ;
     RECT  7.815 127.229 7.905 127.457 ;
     RECT  13.215 127.409 14.238 127.457 ;
     RECT  18.144 127.409 18.705 127.457 ;
     RECT  24.015 127.409 24.642 127.457 ;
     RECT  29.415 127.265 33.894 127.457 ;
     RECT  34.704 127.301 34.905 127.457 ;
     RECT  45.615 127.301 46.53 127.457 ;
     RECT  51.015 127.373 51.39 127.457 ;
     RECT  61.416 127.409 61.905 127.457 ;
     RECT  67.215 127.409 67.305 127.457 ;
     RECT  78.015 127.229 78.105 127.457 ;
     RECT  83.415 127.187 83.505 127.457 ;
     RECT  13.644 127.457 14.238 127.565 ;
     RECT  51.156 127.457 51.39 127.565 ;
     RECT  72.504 127.265 72.99 127.565 ;
     RECT  24.408 127.457 24.642 127.613 ;
     RECT  34.704 127.457 34.758 127.613 ;
     RECT  15.192 127.409 16.974 127.661 ;
     RECT  28.188 127.265 28.494 127.661 ;
     RECT  47.736 127.373 49.914 127.661 ;
     RECT  58.824 127.409 58.842 127.661 ;
     RECT  6.516 127.409 6.534 127.709 ;
     RECT  20.16 127.409 21.546 127.709 ;
     RECT  29.988 127.457 33.894 127.709 ;
     RECT  35.64 127.301 36.558 127.709 ;
     RECT  39.888 127.229 40.878 127.709 ;
     RECT  48.816 127.661 49.914 127.709 ;
     RECT  51.156 127.565 51.174 127.709 ;
     RECT  61.416 127.457 61.758 128.045 ;
     RECT  11.628 127.301 11.646 128.237 ;
     RECT  15.912 127.661 16.974 128.237 ;
     RECT  18.144 127.457 18.558 128.237 ;
     RECT  20.16 127.709 21.006 128.237 ;
     RECT  25.38 127.409 27.126 128.237 ;
     RECT  28.188 127.661 28.206 128.237 ;
     RECT  33.876 127.709 33.894 128.237 ;
     RECT  47.736 127.661 47.754 128.237 ;
     RECT  52.92 127.409 54.018 128.237 ;
     RECT  57.924 127.409 57.942 128.237 ;
     RECT  29.988 127.709 32.31 128.285 ;
     RECT  37.692 127.409 37.71 128.285 ;
     RECT  5.076 127.265 5.094 128.861 ;
     RECT  10.764 127.301 10.782 128.861 ;
     RECT  14.22 127.565 14.238 128.861 ;
     RECT  15.912 128.237 15.93 128.861 ;
     RECT  18.54 128.237 18.558 128.861 ;
     RECT  20.16 128.237 20.538 128.861 ;
     RECT  22.932 127.373 22.95 128.861 ;
     RECT  24.624 127.613 24.642 128.861 ;
     RECT  25.38 128.237 25.398 128.861 ;
     RECT  26.748 128.237 26.766 128.861 ;
     RECT  29.988 128.285 30.006 128.861 ;
     RECT  31.176 128.285 32.31 128.861 ;
     RECT  34.74 127.613 34.758 128.861 ;
     RECT  35.64 127.709 35.658 128.861 ;
     RECT  39.096 127.409 39.114 128.861 ;
     RECT  40.86 127.709 40.878 128.861 ;
     RECT  46.008 127.457 46.53 128.861 ;
     RECT  48.816 127.709 48.834 128.861 ;
     RECT  49.896 127.709 49.914 128.861 ;
     RECT  52.128 127.409 52.146 128.861 ;
     RECT  52.92 128.237 52.938 128.861 ;
     RECT  55.224 127.301 55.242 128.861 ;
     RECT  56.052 127.409 56.754 128.861 ;
     RECT  60.3 127.409 60.318 128.861 ;
     RECT  61.416 128.045 61.434 128.861 ;
     RECT  62.748 127.301 62.766 128.861 ;
     RECT  64.152 127.409 64.17 128.861 ;
     RECT  31.176 128.861 31.194 129.389 ;
     RECT  6.696 129.355 6.714 129.485 ;
     RECT  62.352 129.355 62.37 129.485 ;
    LAYER M4 ;
     RECT  0.192 4.32 0.205 4.344 ;
     RECT  0.156 4.344 0.205 4.464 ;
     RECT  0.192 4.464 0.205 4.488 ;
     RECT  0.156 4.488 0.205 4.752 ;
     RECT  0.192 4.752 0.205 4.776 ;
     RECT  0.156 4.776 0.205 4.896 ;
     RECT  0.192 4.896 0.205 4.92 ;
     RECT  0.156 4.92 0.205 5.04 ;
     RECT  0.192 5.04 0.205 5.064 ;
     RECT  0.156 5.064 0.205 5.184 ;
     RECT  0.192 5.184 0.205 5.208 ;
     RECT  0.156 5.208 0.205 5.472 ;
     RECT  0.192 5.472 0.205 5.496 ;
     RECT  0.156 5.496 0.205 5.616 ;
     RECT  0.192 5.616 0.205 5.64 ;
     RECT  0.156 5.64 0.205 5.76 ;
     RECT  0.192 5.76 0.205 5.784 ;
     RECT  0.156 5.784 0.205 5.904 ;
     RECT  0.192 5.904 0.205 5.928 ;
     RECT  0.156 5.928 0.205 6.192 ;
     RECT  0.192 6.192 0.205 6.216 ;
     RECT  0.156 6.216 0.205 6.336 ;
     RECT  0.192 6.336 0.205 6.36 ;
     RECT  0.156 6.36 0.205 6.48 ;
     RECT  0.192 6.48 0.205 6.504 ;
     RECT  0.156 6.504 0.205 6.624 ;
     RECT  0.192 6.624 0.205 6.648 ;
     RECT  0.156 6.648 0.205 6.912 ;
     RECT  0.192 6.912 0.205 6.936 ;
     RECT  0.156 6.936 0.205 7.056 ;
     RECT  0.192 7.056 0.205 7.08 ;
     RECT  0.156 7.08 0.205 7.2 ;
     RECT  0.192 7.2 0.205 7.224 ;
     RECT  0.156 7.224 0.205 7.344 ;
     RECT  0.192 7.344 0.205 7.368 ;
     RECT  0.156 7.368 0.205 7.632 ;
     RECT  0.192 7.632 0.205 7.656 ;
     RECT  0.156 7.656 0.205 7.776 ;
     RECT  0.192 7.776 0.205 7.8 ;
     RECT  0.156 7.8 0.205 7.92 ;
     RECT  0.192 7.92 0.205 7.944 ;
     RECT  0.156 7.944 0.205 8.064 ;
     RECT  0.192 8.064 0.205 8.088 ;
     RECT  0.156 8.088 0.205 8.352 ;
     RECT  0.192 8.352 0.205 8.376 ;
     RECT  0.156 8.376 0.205 8.496 ;
     RECT  0.192 8.496 0.205 8.52 ;
     RECT  0.156 8.52 0.205 8.64 ;
     RECT  0.192 8.64 0.205 8.664 ;
     RECT  0.156 8.664 0.205 8.784 ;
     RECT  0.192 8.784 0.205 8.808 ;
     RECT  0.156 8.808 0.205 9.072 ;
     RECT  0.192 9.072 0.205 9.096 ;
     RECT  0.156 9.096 0.205 9.216 ;
     RECT  0.192 9.216 0.205 9.24 ;
     RECT  0.156 9.24 0.205 9.36 ;
     RECT  0.192 9.36 0.205 9.384 ;
     RECT  0.156 9.384 0.205 9.504 ;
     RECT  0.192 9.504 0.205 9.528 ;
     RECT  0.156 9.528 0.205 9.792 ;
     RECT  0.192 9.792 0.205 9.816 ;
     RECT  0.156 9.816 0.205 9.936 ;
     RECT  0.192 9.936 0.205 9.96 ;
     RECT  0.156 9.96 0.205 10.08 ;
     RECT  0.192 10.08 0.205 10.104 ;
     RECT  0.156 10.104 0.205 10.224 ;
     RECT  0.192 10.224 0.205 10.248 ;
     RECT  0.156 10.248 0.205 10.368 ;
     RECT  0.192 10.368 0.205 10.392 ;
     RECT  0.156 10.392 0.205 10.656 ;
     RECT  0.192 10.656 0.205 10.68 ;
     RECT  0.156 10.68 0.205 10.8 ;
     RECT  0.192 10.8 0.205 10.824 ;
     RECT  0.156 10.824 0.205 10.944 ;
     RECT  0.192 10.944 0.205 10.968 ;
     RECT  0.156 10.968 0.205 11.088 ;
     RECT  0.192 11.088 0.205 11.112 ;
     RECT  0.156 11.112 0.205 11.376 ;
     RECT  0.192 11.376 0.205 11.4 ;
     RECT  0.156 11.4 0.205 11.52 ;
     RECT  0.192 11.52 0.205 11.544 ;
     RECT  0.156 11.544 0.205 11.664 ;
     RECT  0.192 11.664 0.205 11.688 ;
     RECT  0.156 11.688 0.205 11.808 ;
     RECT  0.192 11.808 0.205 11.832 ;
     RECT  0.156 11.832 0.205 12.096 ;
     RECT  0.192 12.096 0.205 12.12 ;
     RECT  0.156 12.12 0.205 12.24 ;
     RECT  0.192 12.24 0.205 12.264 ;
     RECT  0.156 12.264 0.205 12.384 ;
     RECT  0.192 12.384 0.205 12.408 ;
     RECT  0.156 12.408 0.205 12.528 ;
     RECT  0.192 12.528 0.205 12.552 ;
     RECT  0.156 12.552 0.205 12.816 ;
     RECT  0.192 12.816 0.205 12.84 ;
     RECT  0.156 12.84 0.205 12.96 ;
     RECT  0.192 12.96 0.205 12.984 ;
     RECT  0.156 12.984 0.205 13.104 ;
     RECT  0.192 13.104 0.205 13.128 ;
     RECT  0.156 13.128 0.205 13.248 ;
     RECT  0.192 13.248 0.205 13.272 ;
     RECT  0.156 13.272 0.205 13.536 ;
     RECT  0.192 13.536 0.205 13.56 ;
     RECT  0.156 13.56 0.205 13.68 ;
     RECT  0.192 13.68 0.205 13.704 ;
     RECT  0.156 13.704 0.205 13.824 ;
     RECT  0.192 13.824 0.205 13.848 ;
     RECT  0.156 13.848 0.205 13.968 ;
     RECT  0.192 13.968 0.205 13.992 ;
     RECT  0.156 13.992 0.205 14.256 ;
     RECT  0.192 14.256 0.205 14.28 ;
     RECT  0.156 14.28 0.205 14.4 ;
     RECT  0.192 14.4 0.205 14.424 ;
     RECT  0.156 14.424 0.205 14.544 ;
     RECT  0.192 14.544 0.205 14.568 ;
     RECT  0.156 14.568 0.205 14.688 ;
     RECT  0.192 14.688 0.205 14.712 ;
     RECT  0.156 14.712 0.205 14.976 ;
     RECT  0.192 14.976 0.205 15 ;
     RECT  0.156 15 0.205 15.12 ;
     RECT  0.192 15.12 0.205 15.144 ;
     RECT  0.156 15.144 0.205 15.264 ;
     RECT  0.192 15.264 0.205 15.288 ;
     RECT  0.156 15.288 0.205 15.408 ;
     RECT  0.192 15.408 0.205 15.432 ;
     RECT  0.156 15.432 0.205 15.696 ;
     RECT  0.192 15.696 0.205 15.72 ;
     RECT  0.156 15.72 0.205 15.84 ;
     RECT  0.192 15.84 0.205 15.864 ;
     RECT  0.156 15.864 0.205 15.984 ;
     RECT  0.192 15.984 0.205 16.008 ;
     RECT  0.156 16.008 0.205 16.128 ;
     RECT  0.192 16.128 0.205 16.152 ;
     RECT  0.156 16.152 0.205 16.416 ;
     RECT  0.192 16.416 0.205 16.44 ;
     RECT  0.156 16.44 0.205 16.56 ;
     RECT  0.192 16.56 0.205 16.584 ;
     RECT  0.156 16.584 0.205 16.704 ;
     RECT  0.192 16.704 0.205 16.728 ;
     RECT  0.156 16.728 0.205 16.848 ;
     RECT  0.192 16.848 0.205 16.872 ;
     RECT  0.156 16.872 0.205 17.136 ;
     RECT  0.192 17.136 0.205 17.16 ;
     RECT  0.156 17.16 0.205 17.28 ;
     RECT  0.192 17.28 0.205 17.304 ;
     RECT  0.156 17.304 0.205 17.424 ;
     RECT  0.192 17.424 0.205 17.448 ;
     RECT  0.156 17.448 0.205 17.568 ;
     RECT  0.192 17.568 0.205 17.592 ;
     RECT  0.156 17.592 0.205 17.856 ;
     RECT  0.192 17.856 0.205 17.88 ;
     RECT  0.156 17.88 0.205 18 ;
     RECT  0.192 18 0.205 18.024 ;
     RECT  0.156 18.024 0.205 18.144 ;
     RECT  0.192 18.144 0.205 18.168 ;
     RECT  0.156 18.168 0.205 18.288 ;
     RECT  0.192 18.288 0.205 18.312 ;
     RECT  0.156 18.312 0.205 18.576 ;
     RECT  0.192 18.576 0.205 18.6 ;
     RECT  0.156 18.6 0.205 18.72 ;
     RECT  0.192 18.72 0.205 18.744 ;
     RECT  0.156 18.744 0.205 18.864 ;
     RECT  0.192 18.864 0.205 18.888 ;
     RECT  0.156 18.888 0.205 19.008 ;
     RECT  0.192 19.008 0.205 19.032 ;
     RECT  0.156 19.032 0.205 19.296 ;
     RECT  0.192 19.296 0.205 19.32 ;
     RECT  0.156 19.32 0.205 19.44 ;
     RECT  0.192 19.44 0.205 19.464 ;
     RECT  0.156 19.464 0.205 19.584 ;
     RECT  0.192 19.584 0.205 19.608 ;
     RECT  0.156 19.608 0.205 19.728 ;
     RECT  0.192 19.728 0.205 19.752 ;
     RECT  0.156 19.752 0.205 20.016 ;
     RECT  0.192 20.016 0.205 20.04 ;
     RECT  0.156 20.04 0.205 20.16 ;
     RECT  0.192 20.16 0.205 20.184 ;
     RECT  0.156 20.184 0.205 20.304 ;
     RECT  0.192 20.304 0.205 20.328 ;
     RECT  0.156 20.328 0.205 20.448 ;
     RECT  0.192 20.448 0.205 20.472 ;
     RECT  0.156 20.472 0.205 20.736 ;
     RECT  0.192 20.736 0.205 20.76 ;
     RECT  0.156 20.76 0.205 20.88 ;
     RECT  0.192 20.88 0.205 20.904 ;
     RECT  0.156 20.904 0.205 21.024 ;
     RECT  0.192 21.024 0.205 21.048 ;
     RECT  0.156 21.048 0.205 21.168 ;
     RECT  0.192 21.168 0.205 21.192 ;
     RECT  0.156 21.192 0.205 21.456 ;
     RECT  0.192 21.456 0.205 21.48 ;
     RECT  0.156 21.48 0.205 21.6 ;
     RECT  0.192 21.6 0.205 21.624 ;
     RECT  0.156 21.624 0.205 21.744 ;
     RECT  0.192 21.744 0.205 21.768 ;
     RECT  0.156 21.768 0.205 21.888 ;
     RECT  0.192 21.888 0.205 21.912 ;
     RECT  0.156 21.912 0.205 22.176 ;
     RECT  0.192 22.176 0.205 22.2 ;
     RECT  0.156 22.2 0.205 22.32 ;
     RECT  0.192 22.32 0.205 22.344 ;
     RECT  0.156 22.344 0.205 22.464 ;
     RECT  0.192 22.464 0.205 22.488 ;
     RECT  0.156 22.488 0.205 22.608 ;
     RECT  0.192 22.608 0.205 22.632 ;
     RECT  0.156 22.632 0.205 22.752 ;
     RECT  0.192 22.752 0.205 22.776 ;
     RECT  0.156 22.776 0.205 23.04 ;
     RECT  0.192 23.04 0.205 23.064 ;
     RECT  0.156 23.064 0.205 23.184 ;
     RECT  0.192 23.184 0.205 23.208 ;
     RECT  0.156 23.208 0.205 23.328 ;
     RECT  0.192 23.328 0.205 23.352 ;
     RECT  0.156 23.352 0.205 23.472 ;
     RECT  0.192 23.472 0.205 23.496 ;
     RECT  0.156 23.496 0.205 23.76 ;
     RECT  0.192 23.76 0.205 23.784 ;
     RECT  0.156 23.784 0.205 23.904 ;
     RECT  0.192 23.904 0.205 23.928 ;
     RECT  0.156 23.928 0.205 24.048 ;
     RECT  0.192 24.048 0.205 24.072 ;
     RECT  0.156 24.072 0.205 24.192 ;
     RECT  0.192 24.192 0.205 24.216 ;
     RECT  0.156 24.216 0.205 24.48 ;
     RECT  0.192 24.48 0.205 24.504 ;
     RECT  0.156 24.504 0.205 24.624 ;
     RECT  0.192 24.624 0.205 24.648 ;
     RECT  0.156 24.648 0.205 24.768 ;
     RECT  0.192 24.768 0.205 24.792 ;
     RECT  0.156 24.792 0.205 24.912 ;
     RECT  0.192 24.912 0.205 24.936 ;
     RECT  0.156 24.936 0.205 25.2 ;
     RECT  0.192 25.2 0.205 25.224 ;
     RECT  0.156 25.224 0.205 25.344 ;
     RECT  0.192 25.344 0.205 25.368 ;
     RECT  0.156 25.368 0.205 25.488 ;
     RECT  0.192 25.488 0.205 25.512 ;
     RECT  0.156 25.512 0.205 25.632 ;
     RECT  0.192 25.632 0.205 25.656 ;
     RECT  0.156 25.656 0.205 25.92 ;
     RECT  0.192 25.92 0.205 25.944 ;
     RECT  0.156 25.944 0.205 26.064 ;
     RECT  0.192 26.064 0.205 26.088 ;
     RECT  0.156 26.088 0.205 26.208 ;
     RECT  0.192 26.208 0.205 26.232 ;
     RECT  0.156 26.232 0.205 26.352 ;
     RECT  0.192 26.352 0.205 26.376 ;
     RECT  0.156 26.376 0.205 26.64 ;
     RECT  0.192 26.64 0.205 26.664 ;
     RECT  0.156 26.664 0.205 26.784 ;
     RECT  0.192 26.784 0.205 26.808 ;
     RECT  0.156 26.808 0.205 26.928 ;
     RECT  0.192 26.928 0.205 26.952 ;
     RECT  0.156 26.952 0.205 27.072 ;
     RECT  0.192 27.072 0.205 27.096 ;
     RECT  0.156 27.096 0.205 27.36 ;
     RECT  0.192 27.36 0.205 27.384 ;
     RECT  0.156 27.384 0.205 27.504 ;
     RECT  0.192 27.504 0.205 27.528 ;
     RECT  0.156 27.528 0.205 27.648 ;
     RECT  0.192 27.648 0.205 27.672 ;
     RECT  0.156 27.672 0.205 27.792 ;
     RECT  0.192 27.792 0.205 27.816 ;
     RECT  0.156 27.816 0.205 28.08 ;
     RECT  0.192 28.08 0.205 28.104 ;
     RECT  0.156 28.104 0.205 28.224 ;
     RECT  0.192 28.224 0.205 28.248 ;
     RECT  0.156 28.248 0.205 28.368 ;
     RECT  0.192 28.368 0.205 28.392 ;
     RECT  0.156 28.392 0.205 28.512 ;
     RECT  0.192 28.512 0.205 28.536 ;
     RECT  0.156 28.536 0.205 28.8 ;
     RECT  0.192 28.8 0.205 28.824 ;
     RECT  0.156 28.824 0.205 28.944 ;
     RECT  0.192 28.944 0.205 28.968 ;
     RECT  0.156 28.968 0.205 29.088 ;
     RECT  0.192 29.088 0.205 29.112 ;
     RECT  0.156 29.112 0.205 29.232 ;
     RECT  0.192 29.232 0.205 29.256 ;
     RECT  0.156 29.256 0.205 29.52 ;
     RECT  0.192 29.52 0.205 29.544 ;
     RECT  0.156 29.544 0.205 29.664 ;
     RECT  0.192 29.664 0.205 29.688 ;
     RECT  0.156 29.688 0.205 29.808 ;
     RECT  0.192 29.808 0.205 29.832 ;
     RECT  0.156 29.832 0.205 29.952 ;
     RECT  0.192 29.952 0.205 29.976 ;
     RECT  0.156 29.976 0.205 30.24 ;
     RECT  0.192 30.24 0.205 30.264 ;
     RECT  0.156 30.264 0.205 30.384 ;
     RECT  0.192 30.384 0.205 30.408 ;
     RECT  0.156 30.408 0.205 30.528 ;
     RECT  0.192 30.528 0.205 30.552 ;
     RECT  0.156 30.552 0.205 30.672 ;
     RECT  0.192 30.672 0.205 30.696 ;
     RECT  0.156 30.696 0.205 30.96 ;
     RECT  0.192 30.96 0.205 30.984 ;
     RECT  0.156 30.984 0.205 31.104 ;
     RECT  0.192 31.104 0.205 31.128 ;
     RECT  0.156 31.128 0.205 31.248 ;
     RECT  0.192 31.248 0.205 31.272 ;
     RECT  0.156 31.272 0.205 31.392 ;
     RECT  0.192 31.392 0.205 31.416 ;
     RECT  0.156 31.416 0.205 31.68 ;
     RECT  0.192 31.68 0.205 31.704 ;
     RECT  0.156 31.704 0.205 31.824 ;
     RECT  0.192 31.824 0.205 31.848 ;
     RECT  0.156 31.848 0.205 31.968 ;
     RECT  0.192 31.968 0.205 31.992 ;
     RECT  0.156 31.992 0.205 32.112 ;
     RECT  0.192 32.112 0.205 32.136 ;
     RECT  0.156 32.136 0.205 32.4 ;
     RECT  0.192 32.4 0.205 32.424 ;
     RECT  0.156 32.424 0.205 32.544 ;
     RECT  0.192 32.544 0.205 32.568 ;
     RECT  0.156 32.568 0.205 32.688 ;
     RECT  0.192 32.688 0.205 32.712 ;
     RECT  0.156 32.712 0.205 32.832 ;
     RECT  0.192 32.832 0.205 32.856 ;
     RECT  0.156 32.856 0.205 33.12 ;
     RECT  0.192 33.12 0.205 33.144 ;
     RECT  0.156 33.144 0.205 33.264 ;
     RECT  0.192 33.264 0.205 33.288 ;
     RECT  0.156 33.288 0.205 33.408 ;
     RECT  0.192 33.408 0.205 33.432 ;
     RECT  0.156 33.432 0.205 33.552 ;
     RECT  0.192 33.552 0.205 33.576 ;
     RECT  0.156 33.576 0.205 33.84 ;
     RECT  0.192 33.84 0.205 33.864 ;
     RECT  0.156 33.864 0.205 33.984 ;
     RECT  0.192 33.984 0.205 34.008 ;
     RECT  0.156 34.008 0.205 34.128 ;
     RECT  0.192 34.128 0.205 34.152 ;
     RECT  0.156 34.152 0.205 34.272 ;
     RECT  0.192 34.272 0.205 34.296 ;
     RECT  0.156 34.296 0.205 34.56 ;
     RECT  0.192 34.56 0.205 34.584 ;
     RECT  0.156 34.584 0.205 34.704 ;
     RECT  0.192 34.704 0.205 34.728 ;
     RECT  0.156 34.728 0.205 34.848 ;
     RECT  0.192 34.848 0.205 34.872 ;
     RECT  0.156 34.872 0.205 34.992 ;
     RECT  0.192 34.992 0.205 35.016 ;
     RECT  0.156 35.016 0.205 35.136 ;
     RECT  0.192 35.136 0.205 35.16 ;
     RECT  0.156 35.16 0.205 35.424 ;
     RECT  0.192 35.424 0.205 35.448 ;
     RECT  0.156 35.448 0.205 35.568 ;
     RECT  0.192 35.568 0.205 35.592 ;
     RECT  0.156 35.592 0.205 35.712 ;
     RECT  0.192 35.712 0.205 35.736 ;
     RECT  0.156 35.736 0.205 35.856 ;
     RECT  0.192 35.856 0.205 35.88 ;
     RECT  0.156 35.88 0.205 36.144 ;
     RECT  0.192 36.144 0.205 36.168 ;
     RECT  0.156 36.168 0.205 36.288 ;
     RECT  0.192 36.288 0.205 36.312 ;
     RECT  0.156 36.312 0.205 36.432 ;
     RECT  0.192 36.432 0.205 36.456 ;
     RECT  0.156 36.456 0.205 36.576 ;
     RECT  0.192 36.576 0.205 36.6 ;
     RECT  0.156 36.6 0.205 36.864 ;
     RECT  0.192 36.864 0.205 36.888 ;
     RECT  0.156 36.888 0.205 37.008 ;
     RECT  0.192 37.008 0.205 37.032 ;
     RECT  0.156 37.032 0.205 37.152 ;
     RECT  0.192 37.152 0.205 37.176 ;
     RECT  0.156 37.176 0.205 37.296 ;
     RECT  0.192 37.296 0.205 37.32 ;
     RECT  0.156 37.32 0.205 37.584 ;
     RECT  0.192 37.584 0.205 37.608 ;
     RECT  0.156 37.608 0.205 37.728 ;
     RECT  0.192 37.728 0.205 37.752 ;
     RECT  0.156 37.752 0.205 37.872 ;
     RECT  0.192 37.872 0.205 37.896 ;
     RECT  0.156 37.896 0.205 38.016 ;
     RECT  0.192 38.016 0.205 38.04 ;
     RECT  0.156 38.04 0.205 38.304 ;
     RECT  0.192 38.304 0.205 38.328 ;
     RECT  0.156 38.328 0.205 38.448 ;
     RECT  0.192 38.448 0.205 38.472 ;
     RECT  0.156 38.472 0.205 38.592 ;
     RECT  0.192 38.592 0.205 38.616 ;
     RECT  0.156 38.616 0.205 38.736 ;
     RECT  0.192 38.736 0.205 38.76 ;
     RECT  0.156 38.76 0.205 39.024 ;
     RECT  0.192 39.024 0.205 39.048 ;
     RECT  0.156 39.048 0.205 39.168 ;
     RECT  0.192 39.168 0.205 39.192 ;
     RECT  0.156 39.192 0.205 39.312 ;
     RECT  0.192 39.312 0.205 39.336 ;
     RECT  0.156 39.336 0.205 39.456 ;
     RECT  0.192 39.456 0.205 39.48 ;
     RECT  0.156 39.48 0.205 39.744 ;
     RECT  0.192 39.744 0.205 39.768 ;
     RECT  0.156 39.768 0.205 39.888 ;
     RECT  0.192 39.888 0.205 39.912 ;
     RECT  0.156 39.912 0.205 40.032 ;
     RECT  0.192 40.032 0.205 40.056 ;
     RECT  0.156 40.056 0.205 40.176 ;
     RECT  0.192 40.176 0.205 40.2 ;
     RECT  0.156 40.2 0.205 40.464 ;
     RECT  0.192 40.464 0.205 40.488 ;
     RECT  0.156 40.488 0.205 40.608 ;
     RECT  0.192 40.608 0.205 40.632 ;
     RECT  0.156 40.632 0.205 40.752 ;
     RECT  0.192 40.752 0.205 40.776 ;
     RECT  0.156 40.776 0.205 40.896 ;
     RECT  0.192 40.896 0.205 40.92 ;
     RECT  0.156 40.92 0.205 41.184 ;
     RECT  0.192 41.184 0.205 41.208 ;
     RECT  0.156 41.208 0.205 41.328 ;
     RECT  0.192 41.328 0.205 41.352 ;
     RECT  0.156 41.352 0.205 41.472 ;
     RECT  0.192 41.472 0.205 41.496 ;
     RECT  0.156 41.496 0.205 41.616 ;
     RECT  0.192 41.616 0.205 41.64 ;
     RECT  0.156 41.64 0.205 41.904 ;
     RECT  0.192 41.904 0.205 41.928 ;
     RECT  0.156 41.928 0.205 42.048 ;
     RECT  0.192 42.048 0.205 42.072 ;
     RECT  0.156 42.072 0.205 42.192 ;
     RECT  0.192 42.192 0.205 42.216 ;
     RECT  0.156 42.216 0.205 42.336 ;
     RECT  0.192 42.336 0.205 42.36 ;
     RECT  0.156 42.36 0.205 42.624 ;
     RECT  0.192 42.624 0.205 42.648 ;
     RECT  0.156 42.648 0.205 42.768 ;
     RECT  0.192 42.768 0.205 42.792 ;
     RECT  0.156 42.792 0.205 42.912 ;
     RECT  0.192 42.912 0.205 42.936 ;
     RECT  0.156 42.936 0.205 43.056 ;
     RECT  0.192 43.056 0.205 43.08 ;
     RECT  0.156 43.08 0.205 43.344 ;
     RECT  0.192 43.344 0.205 43.368 ;
     RECT  0.156 43.368 0.205 43.488 ;
     RECT  0.192 43.488 0.205 43.512 ;
     RECT  0.156 43.512 0.205 43.632 ;
     RECT  0.192 43.632 0.205 43.656 ;
     RECT  0.156 43.656 0.205 43.776 ;
     RECT  0.192 43.776 0.205 43.8 ;
     RECT  0.156 43.8 0.205 44.064 ;
     RECT  0.192 44.064 0.205 44.088 ;
     RECT  0.156 44.088 0.205 44.208 ;
     RECT  0.192 44.208 0.205 44.232 ;
     RECT  0.156 44.232 0.205 44.352 ;
     RECT  0.192 44.352 0.205 44.376 ;
     RECT  0.156 44.376 0.205 44.496 ;
     RECT  0.192 44.496 0.205 44.52 ;
     RECT  0.156 44.52 0.205 44.784 ;
     RECT  0.192 44.784 0.205 44.808 ;
     RECT  0.156 44.808 0.205 44.928 ;
     RECT  0.192 44.928 0.205 44.952 ;
     RECT  0.156 44.952 0.205 45.072 ;
     RECT  0.192 45.072 0.205 45.096 ;
     RECT  0.156 45.096 0.205 45.216 ;
     RECT  0.192 45.216 0.205 45.24 ;
     RECT  0.156 45.24 0.205 45.504 ;
     RECT  0.192 45.504 0.205 45.528 ;
     RECT  0.156 45.528 0.205 45.648 ;
     RECT  0.192 45.648 0.205 45.672 ;
     RECT  0.156 45.672 0.205 45.792 ;
     RECT  0.192 45.792 0.205 45.816 ;
     RECT  0.156 45.816 0.205 45.936 ;
     RECT  0.192 45.936 0.205 45.96 ;
     RECT  0.156 45.96 0.205 46.224 ;
     RECT  0.192 46.224 0.205 46.248 ;
     RECT  0.156 46.248 0.205 46.368 ;
     RECT  0.192 46.368 0.205 46.392 ;
     RECT  0.156 46.392 0.205 46.512 ;
     RECT  0.192 46.512 0.205 46.536 ;
     RECT  0.156 46.536 0.205 46.656 ;
     RECT  0.192 46.656 0.205 46.68 ;
     RECT  0.156 46.68 0.205 46.8 ;
     RECT  0.192 46.8 0.205 46.824 ;
     RECT  0.156 46.824 0.205 47.088 ;
     RECT  0.192 47.088 0.205 47.112 ;
     RECT  0.156 47.112 0.205 47.232 ;
     RECT  0.192 47.232 0.205 47.256 ;
     RECT  0.156 47.256 0.205 47.376 ;
     RECT  0.192 47.376 0.205 47.4 ;
     RECT  0.156 47.4 0.205 47.52 ;
     RECT  0.192 47.52 0.205 47.544 ;
     RECT  0.156 47.544 0.205 47.808 ;
     RECT  0.192 47.808 0.205 47.832 ;
     RECT  0.156 47.832 0.205 47.952 ;
     RECT  0.192 47.952 0.205 47.976 ;
     RECT  0.156 47.976 0.205 48.096 ;
     RECT  0.192 48.096 0.205 48.12 ;
     RECT  0.156 48.12 0.205 48.24 ;
     RECT  0.192 48.24 0.205 48.264 ;
     RECT  0.156 48.264 0.205 48.528 ;
     RECT  0.192 48.528 0.205 48.552 ;
     RECT  0.156 48.552 0.205 48.672 ;
     RECT  0.192 48.672 0.205 48.696 ;
     RECT  0.156 48.696 0.205 48.816 ;
     RECT  0.192 48.816 0.205 48.84 ;
     RECT  0.156 48.84 0.205 48.96 ;
     RECT  0.192 48.96 0.205 48.984 ;
     RECT  0.156 48.984 0.205 49.248 ;
     RECT  0.192 49.248 0.205 49.272 ;
     RECT  0.156 49.272 0.205 49.392 ;
     RECT  0.192 49.392 0.205 49.416 ;
     RECT  0.156 49.416 0.205 49.536 ;
     RECT  0.192 49.536 0.205 49.56 ;
     RECT  0.156 49.56 0.205 49.68 ;
     RECT  0.192 49.68 0.205 49.704 ;
     RECT  0.156 49.704 0.205 49.968 ;
     RECT  0.192 49.968 0.205 49.992 ;
     RECT  0.156 49.992 0.205 50.112 ;
     RECT  0.192 50.112 0.205 50.136 ;
     RECT  0.156 50.136 0.205 50.256 ;
     RECT  0.192 50.256 0.205 50.28 ;
     RECT  0.156 50.28 0.205 50.4 ;
     RECT  0.192 50.4 0.205 50.424 ;
     RECT  0.156 50.424 0.205 50.688 ;
     RECT  0.192 50.688 0.205 50.712 ;
     RECT  0.156 50.712 0.205 50.832 ;
     RECT  0.192 50.832 0.205 50.856 ;
     RECT  0.156 50.856 0.205 50.976 ;
     RECT  0.192 50.976 0.205 51 ;
     RECT  0.156 51 0.205 51.12 ;
     RECT  0.192 51.12 0.205 51.144 ;
     RECT  0.156 51.144 0.205 51.408 ;
     RECT  0.192 51.408 0.205 51.432 ;
     RECT  0.156 51.432 0.205 51.552 ;
     RECT  0.192 51.552 0.205 51.576 ;
     RECT  0.156 51.576 0.205 51.696 ;
     RECT  0.192 51.696 0.205 51.72 ;
     RECT  0.156 51.72 0.205 51.84 ;
     RECT  0.192 51.84 0.205 51.864 ;
     RECT  0.156 51.864 0.205 52.128 ;
     RECT  0.192 52.128 0.205 52.152 ;
     RECT  0.156 52.152 0.205 52.272 ;
     RECT  0.192 52.272 0.205 52.296 ;
     RECT  0.156 52.296 0.205 52.416 ;
     RECT  0.192 52.416 0.205 52.44 ;
     RECT  0.156 52.44 0.205 52.56 ;
     RECT  0.192 52.56 0.205 52.584 ;
     RECT  0.156 52.584 0.205 52.848 ;
     RECT  0.192 52.848 0.205 52.872 ;
     RECT  0.156 52.872 0.205 52.992 ;
     RECT  0.192 52.992 0.205 53.016 ;
     RECT  0.156 53.016 0.205 53.136 ;
     RECT  0.192 53.136 0.205 53.16 ;
     RECT  0.156 53.16 0.205 53.28 ;
     RECT  0.192 53.28 0.205 53.304 ;
     RECT  0.156 53.304 0.205 53.568 ;
     RECT  0.192 53.568 0.205 53.592 ;
     RECT  0.156 53.592 0.205 53.712 ;
     RECT  0.192 53.712 0.205 53.736 ;
     RECT  0.156 53.736 0.205 53.856 ;
     RECT  0.192 53.856 0.205 53.88 ;
     RECT  0.156 53.88 0.205 54 ;
     RECT  0.192 54 0.205 54.024 ;
     RECT  0.156 54.024 0.205 54.288 ;
     RECT  0.192 54.288 0.205 54.312 ;
     RECT  0.156 54.312 0.205 54.432 ;
     RECT  0.192 54.432 0.205 54.456 ;
     RECT  0.156 54.456 0.205 54.576 ;
     RECT  0.192 54.576 0.205 54.6 ;
     RECT  0.156 54.6 0.205 54.72 ;
     RECT  0.192 54.72 0.205 54.744 ;
     RECT  0.156 54.744 0.205 55.008 ;
     RECT  0.192 55.008 0.205 55.032 ;
     RECT  0.156 55.032 0.205 55.152 ;
     RECT  0.192 55.152 0.205 55.176 ;
     RECT  0.156 55.176 0.205 55.296 ;
     RECT  0.192 55.296 0.205 55.32 ;
     RECT  0.156 55.32 0.205 55.44 ;
     RECT  0.192 55.44 0.205 55.464 ;
     RECT  0.156 55.464 0.205 55.728 ;
     RECT  0.192 55.728 0.205 55.752 ;
     RECT  0.156 55.752 0.205 55.872 ;
     RECT  0.192 55.872 0.205 55.896 ;
     RECT  0.156 55.896 0.205 56.016 ;
     RECT  0.192 56.016 0.205 56.04 ;
     RECT  0.156 56.04 0.205 56.16 ;
     RECT  0.192 56.16 0.205 56.184 ;
     RECT  0.156 56.184 0.205 56.448 ;
     RECT  0.192 56.448 0.205 56.472 ;
     RECT  0.156 56.472 0.205 56.592 ;
     RECT  0.192 56.592 0.205 56.616 ;
     RECT  0.156 56.616 0.205 56.736 ;
     RECT  0.192 56.736 0.205 56.76 ;
     RECT  0.156 56.76 0.205 56.88 ;
     RECT  0.192 56.88 0.205 56.904 ;
     RECT  0.156 56.904 0.205 57.168 ;
     RECT  0.192 57.168 0.205 57.192 ;
     RECT  0.156 57.192 0.205 57.312 ;
     RECT  0.192 57.312 0.205 57.336 ;
     RECT  0.156 57.336 0.205 57.456 ;
     RECT  0.192 57.456 0.205 57.48 ;
     RECT  0.156 57.48 0.205 57.6 ;
     RECT  0.192 57.6 0.205 57.624 ;
     RECT  0.156 57.624 0.205 57.888 ;
     RECT  0.192 57.888 0.205 57.912 ;
     RECT  0.156 57.912 0.205 58.032 ;
     RECT  0.192 58.032 0.205 58.056 ;
     RECT  0.156 58.056 0.205 58.176 ;
     RECT  0.192 58.176 0.205 58.2 ;
     RECT  0.156 58.2 0.205 58.32 ;
     RECT  0.192 58.32 0.205 58.344 ;
     RECT  0.156 58.344 0.205 58.608 ;
     RECT  0.192 58.608 0.205 58.632 ;
     RECT  0.156 58.632 0.205 58.752 ;
     RECT  0.192 58.752 0.205 58.776 ;
     RECT  0.156 58.776 0.205 58.896 ;
     RECT  0.192 58.896 0.205 58.92 ;
     RECT  0.156 58.92 0.205 59.04 ;
     RECT  0.192 59.04 0.205 59.064 ;
     RECT  0.156 59.064 0.205 59.184 ;
     RECT  0.192 59.184 0.205 59.208 ;
     RECT  0.156 59.208 0.205 59.472 ;
     RECT  0.192 59.472 0.205 59.496 ;
     RECT  0.156 59.496 0.205 59.616 ;
     RECT  0.192 59.616 0.205 59.64 ;
     RECT  0.156 59.64 0.205 59.76 ;
     RECT  0.192 59.76 0.205 59.784 ;
     RECT  0.156 59.784 0.205 59.904 ;
     RECT  0.192 59.904 0.205 59.928 ;
     RECT  0.156 59.928 0.205 60.192 ;
     RECT  0.192 60.192 0.205 60.216 ;
     RECT  0.156 60.216 0.205 60.336 ;
     RECT  0.192 60.336 0.205 60.36 ;
     RECT  0.156 60.36 0.205 60.48 ;
     RECT  0.192 60.48 0.205 60.504 ;
     RECT  0.156 60.504 0.205 60.624 ;
     RECT  0.192 60.624 0.205 60.648 ;
     RECT  0.156 60.648 0.205 60.912 ;
     RECT  0.192 60.912 0.205 60.936 ;
     RECT  0.156 60.936 0.205 61.056 ;
     RECT  0.192 61.056 0.205 61.08 ;
     RECT  0.156 61.08 0.205 61.2 ;
     RECT  0.192 61.2 0.205 61.224 ;
     RECT  0.156 61.224 0.205 61.344 ;
     RECT  0.192 61.344 0.205 61.368 ;
     RECT  0.156 61.368 0.205 61.632 ;
     RECT  0.192 61.632 0.205 61.656 ;
     RECT  0.156 61.656 0.205 61.776 ;
     RECT  0.192 61.776 0.205 61.8 ;
     RECT  0.156 61.8 0.205 61.92 ;
     RECT  0.192 61.92 0.205 61.944 ;
     RECT  0.156 61.944 0.205 62.064 ;
     RECT  0.192 62.064 0.205 62.088 ;
     RECT  0.156 62.088 0.205 62.352 ;
     RECT  0.192 62.352 0.205 62.376 ;
     RECT  0.156 62.376 0.205 62.496 ;
     RECT  0.192 62.496 0.205 62.52 ;
     RECT  0.156 62.52 0.205 62.64 ;
     RECT  0.192 62.64 0.205 62.664 ;
     RECT  0.156 62.664 0.205 62.784 ;
     RECT  0.192 62.784 0.205 62.808 ;
     RECT  0.156 62.808 0.205 63.072 ;
     RECT  0.192 63.072 0.205 63.096 ;
     RECT  0.156 63.096 0.205 63.216 ;
     RECT  0.192 63.216 0.205 63.24 ;
     RECT  0.156 63.24 0.205 63.36 ;
     RECT  0.192 63.36 0.205 63.384 ;
     RECT  0.156 63.384 0.205 63.504 ;
     RECT  0.192 63.504 0.205 63.528 ;
     RECT  0.156 63.528 0.205 63.792 ;
     RECT  0.192 63.792 0.205 63.816 ;
     RECT  0.156 63.816 0.205 63.936 ;
     RECT  0.192 63.936 0.205 63.96 ;
     RECT  0.156 63.96 0.205 64.08 ;
     RECT  0.192 64.08 0.205 64.104 ;
     RECT  0.156 64.104 0.205 64.224 ;
     RECT  0.192 64.224 0.205 64.248 ;
     RECT  0.156 64.248 0.205 64.512 ;
     RECT  0.192 64.512 0.205 64.536 ;
     RECT  0.156 64.536 0.205 64.656 ;
     RECT  0.192 64.656 0.205 64.68 ;
     RECT  0.156 64.68 0.205 64.8 ;
     RECT  0.192 64.8 0.205 64.824 ;
     RECT  0.156 64.824 0.205 64.944 ;
     RECT  0.192 64.944 0.205 64.968 ;
     RECT  0.156 64.968 0.205 65.232 ;
     RECT  0.192 65.232 0.205 65.256 ;
     RECT  0.156 65.256 0.205 65.376 ;
     RECT  0.192 65.376 0.205 65.4 ;
     RECT  0.156 65.4 0.205 65.52 ;
     RECT  0.192 65.52 0.205 65.544 ;
     RECT  0.156 65.544 0.205 65.664 ;
     RECT  0.192 65.664 0.205 65.688 ;
     RECT  0.156 65.688 0.205 65.952 ;
     RECT  0.192 65.952 0.205 65.976 ;
     RECT  0.156 65.976 0.205 66.096 ;
     RECT  0.192 66.096 0.205 66.12 ;
     RECT  0.156 66.12 0.205 66.24 ;
     RECT  0.192 66.24 0.205 66.264 ;
     RECT  0.156 66.264 0.205 66.384 ;
     RECT  0.192 66.384 0.205 66.408 ;
     RECT  0.156 66.408 0.205 66.672 ;
     RECT  0.192 66.672 0.205 66.696 ;
     RECT  0.156 66.696 0.205 66.816 ;
     RECT  0.192 66.816 0.205 66.84 ;
     RECT  0.156 66.84 0.205 66.96 ;
     RECT  0.192 66.96 0.205 66.984 ;
     RECT  0.156 66.984 0.205 67.104 ;
     RECT  0.192 67.104 0.205 67.128 ;
     RECT  0.156 67.128 0.205 67.392 ;
     RECT  0.192 67.392 0.205 67.416 ;
     RECT  0.156 67.416 0.205 67.536 ;
     RECT  0.192 67.536 0.205 67.56 ;
     RECT  0.156 67.56 0.205 67.68 ;
     RECT  0.192 67.68 0.205 67.704 ;
     RECT  0.156 67.704 0.205 67.824 ;
     RECT  0.192 67.824 0.205 67.848 ;
     RECT  0.156 67.848 0.205 68.112 ;
     RECT  0.192 68.112 0.205 68.136 ;
     RECT  0.156 68.136 0.205 68.256 ;
     RECT  0.192 68.256 0.205 68.28 ;
     RECT  0.156 68.28 0.205 68.4 ;
     RECT  0.192 68.4 0.205 68.424 ;
     RECT  0.156 68.424 0.205 68.544 ;
     RECT  0.192 68.544 0.205 68.568 ;
     RECT  0.156 68.568 0.205 68.832 ;
     RECT  0.192 68.832 0.205 68.856 ;
     RECT  0.156 68.856 0.205 68.976 ;
     RECT  0.192 68.976 0.205 69 ;
     RECT  0.156 69 0.205 69.12 ;
     RECT  0.192 69.12 0.205 69.144 ;
     RECT  0.156 69.144 0.205 69.264 ;
     RECT  0.192 69.264 0.205 69.288 ;
     RECT  0.156 69.288 0.205 69.552 ;
     RECT  0.192 69.552 0.205 69.576 ;
     RECT  0.156 69.576 0.205 69.696 ;
     RECT  0.192 69.696 0.205 69.72 ;
     RECT  0.156 69.72 0.205 69.84 ;
     RECT  0.192 69.84 0.205 69.864 ;
     RECT  0.156 69.864 0.205 69.984 ;
     RECT  0.192 69.984 0.205 70.008 ;
     RECT  0.156 70.008 0.205 70.272 ;
     RECT  0.192 70.272 0.205 70.296 ;
     RECT  0.156 70.296 0.205 70.416 ;
     RECT  0.192 70.416 0.205 70.44 ;
     RECT  0.156 70.44 0.205 70.56 ;
     RECT  0.192 70.56 0.205 70.584 ;
     RECT  0.156 70.584 0.205 70.704 ;
     RECT  0.192 70.704 0.205 70.728 ;
     RECT  0.156 70.728 0.205 70.848 ;
     RECT  0.192 70.848 0.205 70.872 ;
     RECT  0.156 70.872 0.205 71.136 ;
     RECT  0.192 71.136 0.205 71.16 ;
     RECT  0.156 71.16 0.205 71.28 ;
     RECT  0.192 71.28 0.205 71.304 ;
     RECT  0.156 71.304 0.205 71.424 ;
     RECT  0.192 71.424 0.205 71.448 ;
     RECT  0.156 71.448 0.205 71.568 ;
     RECT  0.192 71.568 0.205 71.592 ;
     RECT  0.156 71.592 0.205 71.856 ;
     RECT  0.192 71.856 0.205 71.88 ;
     RECT  0.156 71.88 0.205 72 ;
     RECT  0.192 72 0.205 72.024 ;
     RECT  0.156 72.024 0.205 72.144 ;
     RECT  0.192 72.144 0.205 72.168 ;
     RECT  0.156 72.168 0.205 72.288 ;
     RECT  0.192 72.288 0.205 72.312 ;
     RECT  0.156 72.312 0.205 72.576 ;
     RECT  0.192 72.576 0.205 72.6 ;
     RECT  0.156 72.6 0.205 72.72 ;
     RECT  0.192 72.72 0.205 72.744 ;
     RECT  0.156 72.744 0.205 72.864 ;
     RECT  0.192 72.864 0.205 72.888 ;
     RECT  0.156 72.888 0.205 73.008 ;
     RECT  0.192 73.008 0.205 73.032 ;
     RECT  0.156 73.032 0.205 73.296 ;
     RECT  0.192 73.296 0.205 73.32 ;
     RECT  0.156 73.32 0.205 73.44 ;
     RECT  0.192 73.44 0.205 73.464 ;
     RECT  0.156 73.464 0.205 73.584 ;
     RECT  0.192 73.584 0.205 73.608 ;
     RECT  0.156 73.608 0.205 73.728 ;
     RECT  0.192 73.728 0.205 73.752 ;
     RECT  0.156 73.752 0.205 74.016 ;
     RECT  0.192 74.016 0.205 74.04 ;
     RECT  0.156 74.04 0.205 74.16 ;
     RECT  0.192 74.16 0.205 74.184 ;
     RECT  0.156 74.184 0.205 74.304 ;
     RECT  0.192 74.304 0.205 74.328 ;
     RECT  0.156 74.328 0.205 74.448 ;
     RECT  0.192 74.448 0.205 74.472 ;
     RECT  0.156 74.472 0.205 74.736 ;
     RECT  0.192 74.736 0.205 74.76 ;
     RECT  0.156 74.76 0.205 74.88 ;
     RECT  0.192 74.88 0.205 74.904 ;
     RECT  0.156 74.904 0.205 75.024 ;
     RECT  0.192 75.024 0.205 75.048 ;
     RECT  0.156 75.048 0.205 75.168 ;
     RECT  0.192 75.168 0.205 75.192 ;
     RECT  0.156 75.192 0.205 75.456 ;
     RECT  0.192 75.456 0.205 75.48 ;
     RECT  0.156 75.48 0.205 75.6 ;
     RECT  0.192 75.6 0.205 75.624 ;
     RECT  0.156 75.624 0.205 75.744 ;
     RECT  0.192 75.744 0.205 75.768 ;
     RECT  0.156 75.768 0.205 75.888 ;
     RECT  0.192 75.888 0.205 75.912 ;
     RECT  0.156 75.912 0.205 76.176 ;
     RECT  0.192 76.176 0.205 76.2 ;
     RECT  0.156 76.2 0.205 76.32 ;
     RECT  0.192 76.32 0.205 76.344 ;
     RECT  0.156 76.344 0.205 76.464 ;
     RECT  0.192 76.464 0.205 76.488 ;
     RECT  0.156 76.488 0.205 76.608 ;
     RECT  0.192 76.608 0.205 76.632 ;
     RECT  0.156 76.632 0.205 76.896 ;
     RECT  0.192 76.896 0.205 76.92 ;
     RECT  0.156 76.92 0.205 77.04 ;
     RECT  0.192 77.04 0.205 77.064 ;
     RECT  0.156 77.064 0.205 77.184 ;
     RECT  0.192 77.184 0.205 77.208 ;
     RECT  0.156 77.208 0.205 77.328 ;
     RECT  0.192 77.328 0.205 77.352 ;
     RECT  0.156 77.352 0.205 77.616 ;
     RECT  0.192 77.616 0.205 77.64 ;
     RECT  0.156 77.64 0.205 77.76 ;
     RECT  0.192 77.76 0.205 77.784 ;
     RECT  0.156 77.784 0.205 77.904 ;
     RECT  0.192 77.904 0.205 77.928 ;
     RECT  0.156 77.928 0.205 78.048 ;
     RECT  0.192 78.048 0.205 78.072 ;
     RECT  0.156 78.072 0.205 78.336 ;
     RECT  0.192 78.336 0.205 78.36 ;
     RECT  0.156 78.36 0.205 78.48 ;
     RECT  0.192 78.48 0.205 78.504 ;
     RECT  0.156 78.504 0.205 78.624 ;
     RECT  0.192 78.624 0.205 78.648 ;
     RECT  0.156 78.648 0.205 78.768 ;
     RECT  0.192 78.768 0.205 78.792 ;
     RECT  0.156 78.792 0.205 79.056 ;
     RECT  0.192 79.056 0.205 79.08 ;
     RECT  0.156 79.08 0.205 79.2 ;
     RECT  0.192 79.2 0.205 79.224 ;
     RECT  0.156 79.224 0.205 79.344 ;
     RECT  0.192 79.344 0.205 79.368 ;
     RECT  0.156 79.368 0.205 79.488 ;
     RECT  0.192 79.488 0.205 79.512 ;
     RECT  0.156 79.512 0.205 79.776 ;
     RECT  0.192 79.776 0.205 79.8 ;
     RECT  0.156 79.8 0.205 79.92 ;
     RECT  0.192 79.92 0.205 79.944 ;
     RECT  0.156 79.944 0.205 80.064 ;
     RECT  0.192 80.064 0.205 80.088 ;
     RECT  0.156 80.088 0.205 80.208 ;
     RECT  0.192 80.208 0.205 80.232 ;
     RECT  0.156 80.232 0.205 80.496 ;
     RECT  0.192 80.496 0.205 80.52 ;
     RECT  0.156 80.52 0.205 80.64 ;
     RECT  0.192 80.64 0.205 80.664 ;
     RECT  0.156 80.664 0.205 80.784 ;
     RECT  0.192 80.784 0.205 80.808 ;
     RECT  0.156 80.808 0.205 80.928 ;
     RECT  0.192 80.928 0.205 80.952 ;
     RECT  0.156 80.952 0.205 81.216 ;
     RECT  0.192 81.216 0.205 81.24 ;
     RECT  0.156 81.24 0.205 81.36 ;
     RECT  0.192 81.36 0.205 81.384 ;
     RECT  0.156 81.384 0.205 81.504 ;
     RECT  0.192 81.504 0.205 81.528 ;
     RECT  0.156 81.528 0.205 81.648 ;
     RECT  0.192 81.648 0.205 81.672 ;
     RECT  0.156 81.672 0.205 81.936 ;
     RECT  0.192 81.936 0.205 81.96 ;
     RECT  0.156 81.96 0.205 82.08 ;
     RECT  0.192 82.08 0.205 82.104 ;
     RECT  0.156 82.104 0.205 82.224 ;
     RECT  0.192 82.224 0.205 82.248 ;
     RECT  0.156 82.248 0.205 82.368 ;
     RECT  0.192 82.368 0.205 82.392 ;
     RECT  0.156 82.392 0.205 82.656 ;
     RECT  0.192 82.656 0.205 82.68 ;
     RECT  0.156 82.68 0.205 82.8 ;
     RECT  0.192 82.8 0.205 82.824 ;
     RECT  0.156 82.824 0.205 82.944 ;
     RECT  0.192 82.944 0.205 82.968 ;
     RECT  0.156 82.968 0.205 83.088 ;
     RECT  0.192 83.088 0.205 83.112 ;
     RECT  0.156 83.112 0.205 83.232 ;
     RECT  0.192 83.232 0.205 83.256 ;
     RECT  0.156 83.256 0.205 83.52 ;
     RECT  0.192 83.52 0.205 83.544 ;
     RECT  0.156 83.544 0.205 83.664 ;
     RECT  0.192 83.664 0.205 83.688 ;
     RECT  0.156 83.688 0.205 83.808 ;
     RECT  0.192 83.808 0.205 83.832 ;
     RECT  0.156 83.832 0.205 83.952 ;
     RECT  0.192 83.952 0.205 83.976 ;
     RECT  0.156 83.976 0.205 84.24 ;
     RECT  0.192 84.24 0.205 84.264 ;
     RECT  0.156 84.264 0.205 84.384 ;
     RECT  0.192 84.384 0.205 84.408 ;
     RECT  0.156 84.408 0.205 84.528 ;
     RECT  0.192 84.528 0.205 84.552 ;
     RECT  0.156 84.552 0.205 84.672 ;
     RECT  0.192 84.672 0.205 84.696 ;
     RECT  0.156 84.696 0.205 84.96 ;
     RECT  0.192 84.96 0.205 84.984 ;
     RECT  0.156 84.984 0.205 85.104 ;
     RECT  0.192 85.104 0.205 85.128 ;
     RECT  0.156 85.128 0.205 85.248 ;
     RECT  0.192 85.248 0.205 85.272 ;
     RECT  0.156 85.272 0.205 85.392 ;
     RECT  0.192 85.392 0.205 85.416 ;
     RECT  0.156 85.416 0.205 85.68 ;
     RECT  0.192 85.68 0.205 85.704 ;
     RECT  0.156 85.704 0.205 85.824 ;
     RECT  0.192 85.824 0.205 85.848 ;
     RECT  0.156 85.848 0.205 85.968 ;
     RECT  0.192 85.968 0.205 85.992 ;
     RECT  0.156 85.992 0.205 86.112 ;
     RECT  0.192 86.112 0.205 86.136 ;
     RECT  0.156 86.136 0.205 86.4 ;
     RECT  0.192 86.4 0.205 86.424 ;
     RECT  0.156 86.424 0.205 86.544 ;
     RECT  0.192 86.544 0.205 86.568 ;
     RECT  0.156 86.568 0.205 86.688 ;
     RECT  0.192 86.688 0.205 86.712 ;
     RECT  0.156 86.712 0.205 86.832 ;
     RECT  0.192 86.832 0.205 86.856 ;
     RECT  0.156 86.856 0.205 87.12 ;
     RECT  0.192 87.12 0.205 87.144 ;
     RECT  0.156 87.144 0.205 87.264 ;
     RECT  0.192 87.264 0.205 87.288 ;
     RECT  0.156 87.288 0.205 87.408 ;
     RECT  0.192 87.408 0.205 87.432 ;
     RECT  0.156 87.432 0.205 87.552 ;
     RECT  0.192 87.552 0.205 87.576 ;
     RECT  0.156 87.576 0.205 87.84 ;
     RECT  0.192 87.84 0.205 87.864 ;
     RECT  0.156 87.864 0.205 87.984 ;
     RECT  0.192 87.984 0.205 88.008 ;
     RECT  0.156 88.008 0.205 88.128 ;
     RECT  0.192 88.128 0.205 88.152 ;
     RECT  0.156 88.152 0.205 88.272 ;
     RECT  0.192 88.272 0.205 88.296 ;
     RECT  0.156 88.296 0.205 88.56 ;
     RECT  0.192 88.56 0.205 88.584 ;
     RECT  0.156 88.584 0.205 88.704 ;
     RECT  0.192 88.704 0.205 88.728 ;
     RECT  0.156 88.728 0.205 88.848 ;
     RECT  0.192 88.848 0.205 88.872 ;
     RECT  0.156 88.872 0.205 88.992 ;
     RECT  0.192 88.992 0.205 89.016 ;
     RECT  0.156 89.016 0.205 89.28 ;
     RECT  0.192 89.28 0.205 89.304 ;
     RECT  0.156 89.304 0.205 89.424 ;
     RECT  0.192 89.424 0.205 89.448 ;
     RECT  0.156 89.448 0.205 89.568 ;
     RECT  0.192 89.568 0.205 89.592 ;
     RECT  0.156 89.592 0.205 89.712 ;
     RECT  0.192 89.712 0.205 89.736 ;
     RECT  0.156 89.736 0.205 90 ;
     RECT  0.192 90 0.205 90.024 ;
     RECT  0.156 90.024 0.205 90.144 ;
     RECT  0.192 90.144 0.205 90.168 ;
     RECT  0.156 90.168 0.205 90.288 ;
     RECT  0.192 90.288 0.205 90.312 ;
     RECT  0.156 90.312 0.205 90.432 ;
     RECT  0.192 90.432 0.205 90.456 ;
     RECT  0.156 90.456 0.205 90.72 ;
     RECT  0.192 90.72 0.205 90.744 ;
     RECT  0.156 90.744 0.205 90.864 ;
     RECT  0.192 90.864 0.205 90.888 ;
     RECT  0.156 90.888 0.205 91.008 ;
     RECT  0.192 91.008 0.205 91.032 ;
     RECT  0.156 91.032 0.205 91.152 ;
     RECT  0.192 91.152 0.205 91.176 ;
     RECT  0.156 91.176 0.205 91.44 ;
     RECT  0.192 91.44 0.205 91.464 ;
     RECT  0.156 91.464 0.205 91.584 ;
     RECT  0.192 91.584 0.205 91.608 ;
     RECT  0.156 91.608 0.205 91.728 ;
     RECT  0.192 91.728 0.205 91.752 ;
     RECT  0.156 91.752 0.205 91.872 ;
     RECT  0.192 91.872 0.205 91.896 ;
     RECT  0.156 91.896 0.205 92.16 ;
     RECT  0.192 92.16 0.205 92.184 ;
     RECT  0.156 92.184 0.205 92.304 ;
     RECT  0.192 92.304 0.205 92.328 ;
     RECT  0.156 92.328 0.205 92.448 ;
     RECT  0.192 92.448 0.205 92.472 ;
     RECT  0.156 92.472 0.205 92.592 ;
     RECT  0.192 92.592 0.205 92.616 ;
     RECT  0.156 92.616 0.205 92.88 ;
     RECT  0.192 92.88 0.205 92.904 ;
     RECT  0.156 92.904 0.205 93.024 ;
     RECT  0.192 93.024 0.205 93.048 ;
     RECT  0.156 93.048 0.205 93.168 ;
     RECT  0.192 93.168 0.205 93.192 ;
     RECT  0.156 93.192 0.205 93.312 ;
     RECT  0.192 93.312 0.205 93.336 ;
     RECT  0.156 93.336 0.205 93.6 ;
     RECT  0.192 93.6 0.205 93.624 ;
     RECT  0.156 93.624 0.205 93.744 ;
     RECT  0.192 93.744 0.205 93.768 ;
     RECT  0.156 93.768 0.205 93.888 ;
     RECT  0.192 93.888 0.205 93.912 ;
     RECT  0.156 93.912 0.205 94.032 ;
     RECT  0.192 94.032 0.205 94.056 ;
     RECT  0.156 94.056 0.205 94.32 ;
     RECT  0.192 94.32 0.205 94.344 ;
     RECT  0.156 94.344 0.205 94.464 ;
     RECT  0.192 94.464 0.205 94.488 ;
     RECT  0.156 94.488 0.205 94.608 ;
     RECT  0.192 94.608 0.205 94.632 ;
     RECT  0.156 94.632 0.205 94.752 ;
     RECT  0.192 94.752 0.205 94.776 ;
     RECT  0.156 94.776 0.205 95.04 ;
     RECT  0.192 95.04 0.205 95.064 ;
     RECT  0.156 95.064 0.205 95.184 ;
     RECT  0.192 95.184 0.205 95.208 ;
     RECT  0.156 95.208 0.205 95.328 ;
     RECT  0.192 95.328 0.205 95.352 ;
     RECT  0.156 95.352 0.205 95.472 ;
     RECT  0.192 95.472 0.205 95.496 ;
     RECT  0.156 95.496 0.205 95.616 ;
     RECT  0.192 95.616 0.205 95.64 ;
     RECT  0.156 95.64 0.205 95.904 ;
     RECT  0.192 95.904 0.205 95.928 ;
     RECT  0.156 95.928 0.205 96.048 ;
     RECT  0.192 96.048 0.205 96.072 ;
     RECT  0.156 96.072 0.205 96.192 ;
     RECT  0.192 96.192 0.205 96.216 ;
     RECT  0.156 96.216 0.205 96.336 ;
     RECT  0.192 96.336 0.205 96.36 ;
     RECT  0.156 96.36 0.205 96.624 ;
     RECT  0.192 96.624 0.205 96.648 ;
     RECT  0.156 96.648 0.205 96.768 ;
     RECT  0.192 96.768 0.205 96.792 ;
     RECT  0.156 96.792 0.205 96.912 ;
     RECT  0.192 96.912 0.205 96.936 ;
     RECT  0.156 96.936 0.205 97.056 ;
     RECT  0.192 97.056 0.205 97.08 ;
     RECT  0.156 97.08 0.205 97.344 ;
     RECT  0.192 97.344 0.205 97.368 ;
     RECT  0.156 97.368 0.205 97.488 ;
     RECT  0.192 97.488 0.205 97.512 ;
     RECT  0.156 97.512 0.205 97.632 ;
     RECT  0.192 97.632 0.205 97.656 ;
     RECT  0.156 97.656 0.205 97.776 ;
     RECT  0.192 97.776 0.205 97.8 ;
     RECT  0.156 97.8 0.205 98.064 ;
     RECT  0.192 98.064 0.205 98.088 ;
     RECT  0.156 98.088 0.205 98.208 ;
     RECT  0.192 98.208 0.205 98.232 ;
     RECT  0.156 98.232 0.205 98.352 ;
     RECT  0.192 98.352 0.205 98.376 ;
     RECT  0.156 98.376 0.205 98.496 ;
     RECT  0.192 98.496 0.205 98.52 ;
     RECT  0.156 98.52 0.205 98.784 ;
     RECT  0.192 98.784 0.205 98.808 ;
     RECT  0.156 98.808 0.205 98.928 ;
     RECT  0.192 98.928 0.205 98.952 ;
     RECT  0.156 98.952 0.205 99.072 ;
     RECT  0.192 99.072 0.205 99.096 ;
     RECT  0.156 99.096 0.205 99.216 ;
     RECT  0.192 99.216 0.205 99.24 ;
     RECT  0.156 99.24 0.205 99.504 ;
     RECT  0.192 99.504 0.205 99.528 ;
     RECT  0.156 99.528 0.205 99.648 ;
     RECT  0.192 99.648 0.205 99.672 ;
     RECT  0.156 99.672 0.205 99.792 ;
     RECT  0.192 99.792 0.205 99.816 ;
     RECT  0.156 99.816 0.205 99.936 ;
     RECT  0.192 99.936 0.205 99.96 ;
     RECT  0.156 99.96 0.205 100.224 ;
     RECT  0.192 100.224 0.205 100.248 ;
     RECT  0.156 100.248 0.205 100.368 ;
     RECT  0.192 100.368 0.205 100.392 ;
     RECT  0.156 100.392 0.205 100.512 ;
     RECT  0.192 100.512 0.205 100.536 ;
     RECT  0.156 100.536 0.205 100.656 ;
     RECT  0.192 100.656 0.205 100.68 ;
     RECT  0.156 100.68 0.205 100.944 ;
     RECT  0.192 100.944 0.205 100.968 ;
     RECT  0.156 100.968 0.205 101.088 ;
     RECT  0.192 101.088 0.205 101.112 ;
     RECT  0.156 101.112 0.205 101.232 ;
     RECT  0.192 101.232 0.205 101.256 ;
     RECT  0.156 101.256 0.205 101.376 ;
     RECT  0.192 101.376 0.205 101.4 ;
     RECT  0.156 101.4 0.205 101.664 ;
     RECT  0.192 101.664 0.205 101.688 ;
     RECT  0.156 101.688 0.205 101.808 ;
     RECT  0.192 101.808 0.205 101.832 ;
     RECT  0.156 101.832 0.205 101.952 ;
     RECT  0.192 101.952 0.205 101.976 ;
     RECT  0.156 101.976 0.205 102.096 ;
     RECT  0.192 102.096 0.205 102.12 ;
     RECT  0.156 102.12 0.205 102.384 ;
     RECT  0.192 102.384 0.205 102.408 ;
     RECT  0.156 102.408 0.205 102.528 ;
     RECT  0.192 102.528 0.205 102.552 ;
     RECT  0.156 102.552 0.205 102.672 ;
     RECT  0.192 102.672 0.205 102.696 ;
     RECT  0.156 102.696 0.205 102.816 ;
     RECT  0.192 102.816 0.205 102.84 ;
     RECT  0.156 102.84 0.205 103.104 ;
     RECT  0.192 103.104 0.205 103.128 ;
     RECT  0.156 103.128 0.205 103.248 ;
     RECT  0.192 103.248 0.205 103.272 ;
     RECT  0.156 103.272 0.205 103.392 ;
     RECT  0.192 103.392 0.205 103.416 ;
     RECT  0.156 103.416 0.205 103.536 ;
     RECT  0.192 103.536 0.205 103.56 ;
     RECT  0.156 103.56 0.205 103.824 ;
     RECT  0.192 103.824 0.205 103.848 ;
     RECT  0.156 103.848 0.205 103.968 ;
     RECT  0.192 103.968 0.205 103.992 ;
     RECT  0.156 103.992 0.205 104.112 ;
     RECT  0.192 104.112 0.205 104.136 ;
     RECT  0.156 104.136 0.205 104.256 ;
     RECT  0.192 104.256 0.205 104.28 ;
     RECT  0.156 104.28 0.205 104.544 ;
     RECT  0.192 104.544 0.205 104.568 ;
     RECT  0.156 104.568 0.205 104.688 ;
     RECT  0.192 104.688 0.205 104.712 ;
     RECT  0.156 104.712 0.205 104.832 ;
     RECT  0.192 104.832 0.205 104.856 ;
     RECT  0.156 104.856 0.205 104.976 ;
     RECT  0.192 104.976 0.205 105 ;
     RECT  0.156 105 0.205 105.264 ;
     RECT  0.192 105.264 0.205 105.288 ;
     RECT  0.156 105.288 0.205 105.408 ;
     RECT  0.192 105.408 0.205 105.432 ;
     RECT  0.156 105.432 0.205 105.552 ;
     RECT  0.192 105.552 0.205 105.576 ;
     RECT  0.156 105.576 0.205 105.696 ;
     RECT  0.192 105.696 0.205 105.72 ;
     RECT  0.156 105.72 0.205 105.984 ;
     RECT  0.192 105.984 0.205 106.008 ;
     RECT  0.156 106.008 0.205 106.128 ;
     RECT  0.192 106.128 0.205 106.152 ;
     RECT  0.156 106.152 0.205 106.272 ;
     RECT  0.192 106.272 0.205 106.296 ;
     RECT  0.156 106.296 0.205 106.416 ;
     RECT  0.192 106.416 0.205 106.44 ;
     RECT  0.156 106.44 0.205 106.704 ;
     RECT  0.192 106.704 0.205 106.728 ;
     RECT  0.156 106.728 0.205 106.848 ;
     RECT  0.192 106.848 0.205 106.872 ;
     RECT  0.156 106.872 0.205 106.992 ;
     RECT  0.192 106.992 0.205 107.016 ;
     RECT  0.156 107.016 0.205 107.136 ;
     RECT  0.192 107.136 0.205 107.16 ;
     RECT  0.156 107.16 0.205 107.28 ;
     RECT  0.192 107.28 0.205 107.304 ;
     RECT  0.156 107.304 0.205 107.568 ;
     RECT  0.192 107.568 0.205 107.592 ;
     RECT  0.156 107.592 0.205 107.712 ;
     RECT  0.192 107.712 0.205 107.736 ;
     RECT  0.156 107.736 0.205 107.856 ;
     RECT  0.192 107.856 0.205 107.88 ;
     RECT  0.156 107.88 0.205 108 ;
     RECT  0.192 108 0.205 108.024 ;
     RECT  0.156 108.024 0.205 108.288 ;
     RECT  0.192 108.288 0.205 108.312 ;
     RECT  0.156 108.312 0.205 108.432 ;
     RECT  0.192 108.432 0.205 108.456 ;
     RECT  0.156 108.456 0.205 108.576 ;
     RECT  0.192 108.576 0.205 108.6 ;
     RECT  0.156 108.6 0.205 108.72 ;
     RECT  0.192 108.72 0.205 108.744 ;
     RECT  0.156 108.744 0.205 109.008 ;
     RECT  0.192 109.008 0.205 109.032 ;
     RECT  0.156 109.032 0.205 109.152 ;
     RECT  0.192 109.152 0.205 109.176 ;
     RECT  0.156 109.176 0.205 109.296 ;
     RECT  0.192 109.296 0.205 109.32 ;
     RECT  0.156 109.32 0.205 109.44 ;
     RECT  0.192 109.44 0.205 109.464 ;
     RECT  0.156 109.464 0.205 109.728 ;
     RECT  0.192 109.728 0.205 109.752 ;
     RECT  0.156 109.752 0.205 109.872 ;
     RECT  0.192 109.872 0.205 109.896 ;
     RECT  0.156 109.896 0.205 110.016 ;
     RECT  0.192 110.016 0.205 110.04 ;
     RECT  0.156 110.04 0.205 110.16 ;
     RECT  0.192 110.16 0.205 110.184 ;
     RECT  0.156 110.184 0.205 110.448 ;
     RECT  0.192 110.448 0.205 110.472 ;
     RECT  0.156 110.472 0.205 110.592 ;
     RECT  0.192 110.592 0.205 110.616 ;
     RECT  0.156 110.616 0.205 110.736 ;
     RECT  0.192 110.736 0.205 110.76 ;
     RECT  0.156 110.76 0.205 110.88 ;
     RECT  0.192 110.88 0.205 110.904 ;
     RECT  0.156 110.904 0.205 111.168 ;
     RECT  0.192 111.168 0.205 111.192 ;
     RECT  0.156 111.192 0.205 111.312 ;
     RECT  0.192 111.312 0.205 111.336 ;
     RECT  0.156 111.336 0.205 111.456 ;
     RECT  0.192 111.456 0.205 111.48 ;
     RECT  0.156 111.48 0.205 111.6 ;
     RECT  0.192 111.6 0.205 111.624 ;
     RECT  0.156 111.624 0.205 111.888 ;
     RECT  0.192 111.888 0.205 111.912 ;
     RECT  0.156 111.912 0.205 112.032 ;
     RECT  0.192 112.032 0.205 112.056 ;
     RECT  0.156 112.056 0.205 112.176 ;
     RECT  0.192 112.176 0.205 112.2 ;
     RECT  0.156 112.2 0.205 112.32 ;
     RECT  0.192 112.32 0.205 112.344 ;
     RECT  0.156 112.344 0.205 112.608 ;
     RECT  0.192 112.608 0.205 112.632 ;
     RECT  0.156 112.632 0.205 112.752 ;
     RECT  0.192 112.752 0.205 112.776 ;
     RECT  0.156 112.776 0.205 112.896 ;
     RECT  0.192 112.896 0.205 112.92 ;
     RECT  0.156 112.92 0.205 113.04 ;
     RECT  0.192 113.04 0.205 113.064 ;
     RECT  0.156 113.064 0.205 113.328 ;
     RECT  0.192 113.328 0.205 113.352 ;
     RECT  0.156 113.352 0.205 113.472 ;
     RECT  0.192 113.472 0.205 113.496 ;
     RECT  0.156 113.496 0.205 113.616 ;
     RECT  0.192 113.616 0.205 113.64 ;
     RECT  0.156 113.64 0.205 113.76 ;
     RECT  0.192 113.76 0.205 113.784 ;
     RECT  0.156 113.784 0.205 114.048 ;
     RECT  0.192 114.048 0.205 114.072 ;
     RECT  0.156 114.072 0.205 114.192 ;
     RECT  0.192 114.192 0.205 114.216 ;
     RECT  0.156 114.216 0.205 114.336 ;
     RECT  0.192 114.336 0.205 114.36 ;
     RECT  0.156 114.36 0.205 114.48 ;
     RECT  0.192 114.48 0.205 114.504 ;
     RECT  0.156 114.504 0.205 114.768 ;
     RECT  0.192 114.768 0.205 114.792 ;
     RECT  0.156 114.792 0.205 114.912 ;
     RECT  0.192 114.912 0.205 114.936 ;
     RECT  0.156 114.936 0.205 115.056 ;
     RECT  0.192 115.056 0.205 115.08 ;
     RECT  0.156 115.08 0.205 115.2 ;
     RECT  0.192 115.2 0.205 115.224 ;
     RECT  0.156 115.224 0.205 115.488 ;
     RECT  0.192 115.488 0.205 115.512 ;
     RECT  0.156 115.512 0.205 115.632 ;
     RECT  0.192 115.632 0.205 115.656 ;
     RECT  0.156 115.656 0.205 115.776 ;
     RECT  0.192 115.776 0.205 115.8 ;
     RECT  0.156 115.8 0.205 115.92 ;
     RECT  0.192 115.92 0.205 115.944 ;
     RECT  0.156 115.944 0.205 116.208 ;
     RECT  0.192 116.208 0.205 116.232 ;
     RECT  0.156 116.232 0.205 116.352 ;
     RECT  0.192 116.352 0.205 116.376 ;
     RECT  0.156 116.376 0.205 116.496 ;
     RECT  0.192 116.496 0.205 116.52 ;
     RECT  0.156 116.52 0.205 116.64 ;
     RECT  0.192 116.64 0.205 116.664 ;
     RECT  0.156 116.664 0.205 116.928 ;
     RECT  0.192 116.928 0.205 116.952 ;
     RECT  0.156 116.952 0.205 117.072 ;
     RECT  0.192 117.072 0.205 117.096 ;
     RECT  0.156 117.096 0.205 117.216 ;
     RECT  0.192 117.216 0.205 117.24 ;
     RECT  0.156 117.24 0.205 117.36 ;
     RECT  0.192 117.36 0.205 117.384 ;
     RECT  0.156 117.384 0.205 117.648 ;
     RECT  0.192 117.648 0.205 117.672 ;
     RECT  0.156 117.672 0.205 117.792 ;
     RECT  0.192 117.792 0.205 117.816 ;
     RECT  0.156 117.816 0.205 117.936 ;
     RECT  0.192 117.936 0.205 117.96 ;
     RECT  0.156 117.96 0.205 118.08 ;
     RECT  0.192 118.08 0.205 118.104 ;
     RECT  0.156 118.104 0.205 118.368 ;
     RECT  0.192 118.368 0.205 118.392 ;
     RECT  0.156 118.392 0.205 118.512 ;
     RECT  0.192 118.512 0.205 118.536 ;
     RECT  0.156 118.536 0.205 118.656 ;
     RECT  0.192 118.656 0.205 118.68 ;
     RECT  0.156 118.68 0.205 118.8 ;
     RECT  0.192 118.8 0.205 118.824 ;
     RECT  0.156 118.824 0.205 119.088 ;
     RECT  0.192 119.088 0.205 119.112 ;
     RECT  0.156 119.112 0.205 119.232 ;
     RECT  0.192 119.232 0.205 119.256 ;
     RECT  0.156 119.256 0.205 119.376 ;
     RECT  0.192 119.376 0.205 119.4 ;
     RECT  0.156 119.4 0.205 119.52 ;
     RECT  0.192 119.52 0.205 119.544 ;
     RECT  0.156 119.544 0.205 119.664 ;
     RECT  0.192 119.664 0.205 119.688 ;
     RECT  0.156 119.688 0.205 119.952 ;
     RECT  0.192 119.952 0.205 119.976 ;
     RECT  0.156 119.976 0.205 120.096 ;
     RECT  0.192 120.096 0.205 120.12 ;
     RECT  0.156 120.12 0.205 120.24 ;
     RECT  0.192 120.24 0.205 120.264 ;
     RECT  0.156 120.264 0.205 120.384 ;
     RECT  0.192 120.384 0.205 120.408 ;
     RECT  0.156 120.408 0.205 120.672 ;
     RECT  0.192 120.672 0.205 120.696 ;
     RECT  0.156 120.696 0.205 120.816 ;
     RECT  0.192 120.816 0.205 120.84 ;
     RECT  0.156 120.84 0.205 120.96 ;
     RECT  0.192 120.96 0.205 120.984 ;
     RECT  0.156 120.984 0.205 121.104 ;
     RECT  0.192 121.104 0.205 121.128 ;
     RECT  0.156 121.128 0.205 121.392 ;
     RECT  0.192 121.392 0.205 121.416 ;
     RECT  0.156 121.416 0.205 121.536 ;
     RECT  0.192 121.536 0.205 121.56 ;
     RECT  0.156 121.56 0.205 121.68 ;
     RECT  0.192 121.68 0.205 121.704 ;
     RECT  0.156 121.704 0.205 121.824 ;
     RECT  0.192 121.824 0.205 121.848 ;
     RECT  0.156 121.848 0.205 122.112 ;
     RECT  0.192 122.112 0.205 122.136 ;
     RECT  0.156 122.136 0.205 122.256 ;
     RECT  0.192 122.256 0.205 122.28 ;
     RECT  0.156 122.28 0.205 122.4 ;
     RECT  0.192 122.4 0.205 122.424 ;
     RECT  0.156 122.424 0.205 122.544 ;
     RECT  0.192 122.544 0.205 122.568 ;
     RECT  0.156 122.568 0.205 122.832 ;
     RECT  0.192 122.832 0.205 122.856 ;
     RECT  0.156 122.856 0.205 122.976 ;
     RECT  0.192 122.976 0.205 123 ;
     RECT  0.156 123 0.205 123.12 ;
     RECT  0.192 123.12 0.205 123.144 ;
     RECT  0.156 123.144 0.205 123.264 ;
     RECT  0.192 123.264 0.205 123.288 ;
     RECT  0.156 123.288 0.205 123.552 ;
     RECT  0.192 123.552 0.205 123.576 ;
     RECT  0.156 123.576 0.205 123.696 ;
     RECT  0.192 123.696 0.205 123.72 ;
     RECT  0.156 123.72 0.205 123.84 ;
     RECT  0.192 123.84 0.205 123.864 ;
     RECT  0.156 123.864 0.205 123.984 ;
     RECT  0.192 123.984 0.205 124.008 ;
     RECT  0.156 124.008 0.205 124.272 ;
     RECT  0.192 124.272 0.205 124.296 ;
     RECT  0.156 124.296 0.205 124.416 ;
     RECT  0.192 124.416 0.205 124.44 ;
     RECT  0.156 124.44 0.205 124.56 ;
     RECT  0.192 124.56 0.205 124.584 ;
     RECT  0.156 124.584 0.205 124.704 ;
     RECT  0.192 124.704 0.205 124.728 ;
     RECT  0.156 124.728 0.205 124.992 ;
     RECT  0.192 124.992 0.205 125.016 ;
     RECT  0.156 125.016 0.205 125.136 ;
     RECT  0.192 125.136 0.205 125.16 ;
     RECT  0.205 4.224 2.408 125.16 ;
     RECT  2.408 2.148 2.512 127.452 ;
     RECT  2.512 2.418 2.704 127.182 ;
     RECT  2.704 13.68 2.765 18.888 ;
     RECT  2.704 30.672 2.765 35.016 ;
     RECT  2.704 62.4 2.765 67.656 ;
     RECT  2.704 72.048 2.765 73.032 ;
     RECT  2.704 76.272 2.765 78.072 ;
     RECT  2.704 86.544 2.765 86.568 ;
     RECT  2.704 87.552 2.765 89.448 ;
     RECT  2.704 90.528 2.765 96.792 ;
     RECT  2.704 98.592 2.765 99.816 ;
     RECT  2.704 102.384 2.765 102.408 ;
     RECT  2.704 108.288 2.765 110.616 ;
     RECT  2.704 115.2 2.765 115.656 ;
     RECT  2.704 121.968 2.765 122.664 ;
     RECT  2.704 125.136 2.765 126.024 ;
     RECT  2.704 68.928 2.801 70.872 ;
     RECT  2.765 87.552 2.801 88.92 ;
     RECT  2.704 117.36 2.801 118.68 ;
     RECT  2.704 119.664 2.801 120.264 ;
     RECT  2.704 26.208 2.837 29.112 ;
     RECT  2.704 19.92 2.845 22.296 ;
     RECT  2.704 4.416 2.867 11.016 ;
     RECT  2.704 12 2.867 12.552 ;
     RECT  2.704 39.264 2.873 39.336 ;
     RECT  2.704 123.984 2.909 124.008 ;
     RECT  2.867 4.416 2.915 7.992 ;
     RECT  2.765 30.672 2.981 31.368 ;
     RECT  2.765 62.4 2.981 67.128 ;
     RECT  2.765 76.272 2.981 76.392 ;
     RECT  2.704 80.784 2.981 81.384 ;
     RECT  2.801 118.656 2.981 118.68 ;
     RECT  2.801 120.24 2.981 120.264 ;
     RECT  2.837 26.208 3.017 27.624 ;
     RECT  2.704 111.696 3.017 112.776 ;
     RECT  2.915 4.416 3.125 5.064 ;
     RECT  2.981 80.784 3.125 80.808 ;
     RECT  2.765 92.832 3.197 95.496 ;
     RECT  2.704 103.488 3.197 103.752 ;
     RECT  2.873 39.264 3.233 39.288 ;
     RECT  2.765 98.592 3.233 99.72 ;
     RECT  2.765 14.16 3.251 18.888 ;
     RECT  2.765 96.768 3.305 96.792 ;
     RECT  2.704 74.112 3.341 75.192 ;
     RECT  2.704 101.04 3.413 101.352 ;
     RECT  2.704 105.984 3.491 106.68 ;
     RECT  2.704 44.976 3.521 61.272 ;
     RECT  2.867 12.528 3.683 12.552 ;
     RECT  2.765 34.224 3.733 34.68 ;
     RECT  2.704 23.328 3.74 24.936 ;
     RECT  3.017 26.208 3.74 27.528 ;
     RECT  3.251 17.184 3.769 18.888 ;
     RECT  2.845 19.92 3.769 22.248 ;
     RECT  2.801 68.928 3.769 69.48 ;
     RECT  2.867 9.024 3.781 11.016 ;
     RECT  3.521 58.176 3.805 61.272 ;
     RECT  2.981 62.4 3.805 66.84 ;
     RECT  3.769 68.352 3.805 69.48 ;
     RECT  2.801 70.704 3.805 70.728 ;
     RECT  2.765 72.048 3.805 72.744 ;
     RECT  2.704 82.944 3.805 83.208 ;
     RECT  2.765 108.288 3.809 110.088 ;
     RECT  3.74 23.328 3.836 27.528 ;
     RECT  2.704 42.72 3.841 42.744 ;
     RECT  2.915 6.144 3.877 7.992 ;
     RECT  3.805 87.456 3.877 87.48 ;
     RECT  2.801 88.464 3.877 88.92 ;
     RECT  3.197 103.728 3.877 103.752 ;
     RECT  3.841 42.72 3.913 43.32 ;
     RECT  3.805 68.352 3.913 72.744 ;
     RECT  3.341 74.112 3.913 74.616 ;
     RECT  3.836 23.28 3.923 27.528 ;
     RECT  3.125 4.416 3.925 4.536 ;
     RECT  3.877 5.712 3.925 7.992 ;
     RECT  3.781 9.024 3.925 11.256 ;
     RECT  3.913 42.528 3.925 43.32 ;
     RECT  3.521 44.976 3.925 57.048 ;
     RECT  3.805 38.928 3.949 39.24 ;
     RECT  2.981 76.368 3.949 76.392 ;
     RECT  2.765 78.048 3.949 78.072 ;
     RECT  3.805 82.56 3.949 83.208 ;
     RECT  3.809 108.432 3.949 110.088 ;
     RECT  3.017 111.696 3.949 112.68 ;
     RECT  3.925 42.528 3.971 57.048 ;
     RECT  3.925 4.32 3.973 4.536 ;
     RECT  3.949 38.208 3.973 39.24 ;
     RECT  3.913 68.352 3.98 74.616 ;
     RECT  2.704 41.088 3.985 41.544 ;
     RECT  3.733 33.936 4.021 34.68 ;
     RECT  3.985 40.944 4.021 41.544 ;
     RECT  3.877 86.256 4.021 88.92 ;
     RECT  3.973 3.936 4.028 4.536 ;
     RECT  3.923 23.328 4.057 27.528 ;
     RECT  3.413 101.04 4.057 101.064 ;
     RECT  2.981 31.344 4.093 31.368 ;
     RECT  2.765 32.496 4.093 32.52 ;
     RECT  4.021 33.792 4.093 34.68 ;
     RECT  2.765 126 4.117 126.024 ;
     RECT  4.028 3.888 4.129 4.536 ;
     RECT  3.925 5.712 4.129 11.256 ;
     RECT  4.129 3.888 4.163 11.256 ;
     RECT  4.093 30.24 4.165 30.264 ;
     RECT  4.057 23.328 4.201 27.576 ;
     RECT  2.837 29.088 4.201 29.112 ;
     RECT  3.973 37.728 4.201 39.24 ;
     RECT  2.704 79.248 4.201 79.272 ;
     RECT  2.765 90.528 4.201 91.752 ;
     RECT  3.233 98.592 4.201 98.616 ;
     RECT  3.233 99.696 4.201 99.72 ;
     RECT  3.98 68.064 4.213 74.616 ;
     RECT  3.251 14.16 4.237 16.152 ;
     RECT  3.769 17.184 4.237 22.248 ;
     RECT  4.201 36.576 4.273 39.24 ;
     RECT  4.021 40.272 4.273 41.544 ;
     RECT  4.201 98.592 4.273 99.72 ;
     RECT  4.057 100.8 4.273 101.064 ;
     RECT  3.949 82.56 4.309 83.784 ;
     RECT  4.201 104.976 4.309 105 ;
     RECT  3.491 105.984 4.309 106.584 ;
     RECT  2.765 115.632 4.309 115.656 ;
     RECT  4.093 31.344 4.345 32.52 ;
     RECT  4.093 33.792 4.345 34.968 ;
     RECT  4.021 86.256 4.345 89.064 ;
     RECT  4.201 23.328 4.364 29.112 ;
     RECT  4.165 30.24 4.364 30.312 ;
     RECT  3.877 103.728 4.381 103.8 ;
     RECT  4.309 104.976 4.381 106.584 ;
     RECT  4.309 115.632 4.381 115.704 ;
     RECT  2.801 117.408 4.385 117.432 ;
     RECT  4.309 81.648 4.417 83.784 ;
     RECT  3.949 108.432 4.421 112.68 ;
     RECT  4.381 115.632 4.421 116.088 ;
     RECT  3.925 12.912 4.453 12.936 ;
     RECT  4.237 14.16 4.453 22.296 ;
     RECT  4.273 36.576 4.453 41.544 ;
     RECT  3.971 42.528 4.453 43.032 ;
     RECT  4.345 85.44 4.453 89.4 ;
     RECT  4.201 90.384 4.453 91.752 ;
     RECT  4.364 23.328 4.489 30.312 ;
     RECT  4.345 31.344 4.489 34.968 ;
     RECT  3.971 44.064 4.489 57.048 ;
     RECT  3.805 58.176 4.489 66.84 ;
     RECT  3.949 76.08 4.489 78.12 ;
     RECT  4.201 79.104 4.489 79.272 ;
     RECT  4.273 96.144 4.489 96.168 ;
     RECT  4.201 97.248 4.489 97.272 ;
     RECT  4.273 98.592 4.489 101.064 ;
     RECT  4.489 76.08 4.549 79.272 ;
     RECT  4.453 85.44 4.549 91.752 ;
     RECT  4.213 67.968 4.561 74.616 ;
     RECT  4.421 115.68 4.561 116.088 ;
     RECT  4.453 127.104 4.565 127.128 ;
     RECT  4.489 44.064 4.597 66.84 ;
     RECT  4.561 67.824 4.597 74.616 ;
     RECT  4.453 12.912 4.601 22.296 ;
     RECT  3.197 92.832 4.601 95.112 ;
     RECT  4.549 75.792 4.637 79.272 ;
     RECT  3.973 124.896 4.645 124.92 ;
     RECT  4.201 114.576 4.673 114.6 ;
     RECT  2.765 121.968 4.7 122.568 ;
     RECT  4.489 23.328 4.705 34.968 ;
     RECT  4.381 103.728 4.705 106.584 ;
     RECT  4.601 12.912 4.741 14.328 ;
     RECT  4.525 80.496 4.741 80.52 ;
     RECT  4.417 81.6 4.741 83.784 ;
     RECT  4.645 124.848 4.741 124.92 ;
     RECT  4.597 44.064 4.745 74.712 ;
     RECT  4.163 10.848 4.748 11.256 ;
     RECT  4.453 102.192 4.748 102.216 ;
     RECT  4.163 3.888 4.777 9.768 ;
     RECT  4.748 10.848 4.817 11.304 ;
     RECT  4.549 85.44 4.921 91.8 ;
     RECT  4.705 103.728 4.921 106.824 ;
     RECT  4.637 76.08 4.957 79.272 ;
     RECT  4.741 80.496 4.957 83.784 ;
     RECT  4.421 108.432 4.957 112.536 ;
     RECT  4.601 15.6 5.029 22.296 ;
     RECT  4.705 23.328 5.029 35.496 ;
     RECT  4.957 76.08 5.029 83.784 ;
     RECT  4.921 85.104 5.029 91.8 ;
     RECT  4.601 92.928 5.029 95.112 ;
     RECT  4.489 96.144 5.029 101.064 ;
     RECT  5.029 76.08 5.069 91.8 ;
     RECT  4.957 108.096 5.077 112.536 ;
     RECT  4.741 124.464 5.077 124.92 ;
     RECT  4.117 126 5.077 126.072 ;
     RECT  4.921 103.536 5.104 106.824 ;
     RECT  4.885 128.832 5.105 128.856 ;
     RECT  5.029 15.6 5.125 35.496 ;
     RECT  4.453 36.576 5.125 43.032 ;
     RECT  4.777 3.84 5.177 9.768 ;
     RECT  5.125 15.6 5.177 43.032 ;
     RECT  5.104 103.536 5.209 106.872 ;
     RECT  5.077 107.952 5.209 112.536 ;
     RECT  4.748 102.192 5.245 102.552 ;
     RECT  5.209 103.536 5.245 112.536 ;
     RECT  4.7 121.248 5.281 122.568 ;
     RECT  5.177 3.84 5.285 6.84 ;
     RECT  5.077 124.464 5.317 126.072 ;
     RECT  4.741 119.664 5.353 119.688 ;
     RECT  5.281 121.008 5.353 122.568 ;
     RECT  5.069 76.224 5.389 91.8 ;
     RECT  5.389 76.224 5.411 91.848 ;
     RECT  5.177 35.952 5.461 43.032 ;
     RECT  4.745 44.064 5.461 74.664 ;
     RECT  5.245 102.192 5.461 112.536 ;
     RECT  5.353 119.664 5.461 122.568 ;
     RECT  5.317 124.464 5.461 126.696 ;
     RECT  4.817 11.136 5.497 11.304 ;
     RECT  4.741 12.48 5.497 14.328 ;
     RECT  5.029 92.928 5.497 101.064 ;
     RECT  5.461 102.096 5.497 112.536 ;
     RECT  4.561 115.68 5.497 117 ;
     RECT  4.273 1.728 5.507 1.752 ;
     RECT  5.497 115.68 5.533 118.152 ;
     RECT  5.461 119.664 5.533 122.664 ;
     RECT  5.564 2.64 5.651 2.664 ;
     RECT  5.411 82.752 5.653 91.848 ;
     RECT  5.497 92.928 5.669 112.536 ;
     RECT  5.653 82.752 5.677 91.896 ;
     RECT  5.669 92.88 5.677 112.536 ;
     RECT  5.177 15.6 5.701 34.92 ;
     RECT  5.461 124.368 5.753 126.696 ;
     RECT  5.497 11.136 5.785 14.328 ;
     RECT  5.533 115.68 5.821 122.664 ;
     RECT  5.785 10.8 5.825 14.328 ;
     RECT  5.753 124.368 5.893 126.648 ;
     RECT  5.701 15.36 6.035 34.92 ;
     RECT  5.461 35.952 6.037 74.664 ;
     RECT  5.821 115.2 6.073 122.664 ;
     RECT  5.893 123.696 6.073 126.648 ;
     RECT  6.035 15.36 6.109 15.384 ;
     RECT  6.109 14.496 6.149 15.384 ;
     RECT  5.177 7.968 6.217 9.768 ;
     RECT  5.825 10.8 6.217 13.512 ;
     RECT  5.785 2.832 6.332 2.856 ;
     RECT  5.285 3.84 6.332 6.264 ;
     RECT  6.253 0.576 6.337 0.6 ;
     RECT  5.411 76.224 6.433 81.768 ;
     RECT  5.677 82.752 6.433 113.256 ;
     RECT  6.037 35.952 6.517 74.712 ;
     RECT  6.433 76.224 6.517 113.256 ;
     RECT  6.277 127.68 6.545 127.704 ;
     RECT  6.073 115.2 6.613 126.648 ;
     RECT  6.541 1.728 6.625 1.752 ;
     RECT  6.332 2.832 6.649 6.264 ;
     RECT  6.217 7.968 6.649 13.512 ;
     RECT  6.649 2.832 6.661 13.512 ;
     RECT  6.641 129.456 6.668 129.48 ;
     RECT  6.035 16.608 6.721 34.92 ;
     RECT  6.517 35.952 6.721 113.256 ;
     RECT  6.668 129.36 6.725 129.48 ;
     RECT  6.725 129.36 6.755 129.384 ;
     RECT  6.721 16.608 6.761 113.256 ;
     RECT  6.761 52.464 6.793 113.256 ;
     RECT  6.613 114.24 6.793 126.648 ;
     RECT  6.829 0.528 6.913 0.552 ;
     RECT  6.661 2.064 7.045 13.512 ;
     RECT  6.149 14.496 7.045 14.52 ;
     RECT  6.793 52.464 7.081 126.648 ;
     RECT  6.761 16.608 7.189 51.432 ;
     RECT  7.045 2.064 7.225 14.52 ;
     RECT  7.189 16.32 7.225 51.432 ;
     RECT  7.081 52.464 7.621 126.696 ;
     RECT  7.225 2.064 7.808 51.432 ;
     RECT  7.621 52.464 7.808 127.128 ;
     RECT  7.669 0.192 7.907 0.216 ;
     RECT  7.808 2.064 8.005 127.452 ;
     RECT  8.005 2.064 8.243 127.56 ;
     RECT  8.243 2.064 8.819 127.128 ;
     RECT  8.819 2.88 9.683 127.128 ;
     RECT  9.683 2.88 9.785 127.08 ;
     RECT  8.869 1.728 10.213 1.752 ;
     RECT  9.785 3.408 10.741 127.08 ;
     RECT  10.309 128.832 10.793 128.856 ;
     RECT  10.741 3.408 10.829 127.128 ;
     RECT  10.213 1.728 10.861 2.28 ;
     RECT  10.829 3.408 10.861 5.88 ;
     RECT  10.829 6.864 10.937 127.128 ;
     RECT  10.861 1.728 10.945 5.88 ;
     RECT  10.945 1.728 11.009 2.28 ;
     RECT  10.945 3.696 11.027 5.88 ;
     RECT  11.617 128.208 11.747 128.232 ;
     RECT  11.027 3.84 11.797 5.88 ;
     RECT  10.937 6.864 11.797 126.84 ;
     RECT  11.797 3.84 12.133 126.84 ;
     RECT  12.133 3.84 12.157 126.984 ;
     RECT  12.013 0.576 12.179 0.6 ;
     RECT  11.009 2.256 12.229 2.28 ;
     RECT  12.229 2.256 12.337 2.808 ;
     RECT  12.337 1.728 12.553 2.808 ;
     RECT  12.157 3.84 12.553 127.128 ;
     RECT  12.553 1.728 13.208 127.128 ;
     RECT  13.208 1.728 13.429 127.452 ;
     RECT  13.429 0.192 13.619 0.216 ;
     RECT  13.429 1.728 13.673 127.56 ;
     RECT  13.673 1.728 13.753 127.08 ;
     RECT  14.209 128.832 14.339 128.856 ;
     RECT  13.753 2.736 14.749 127.08 ;
     RECT  14.749 2.736 15.137 127.128 ;
     RECT  15.137 2.736 15.221 127.656 ;
     RECT  13.753 1.728 15.361 1.752 ;
     RECT  15.221 2.736 15.361 126.744 ;
     RECT  15.361 1.728 15.491 126.744 ;
     RECT  15.491 2.784 15.617 126.744 ;
     RECT  15.617 3.216 15.913 126.744 ;
     RECT  15.589 128.832 15.941 128.856 ;
     RECT  15.913 3.312 16.157 126.744 ;
     RECT  16.157 3.36 16.553 126.744 ;
     RECT  16.553 5.52 17.053 126.744 ;
     RECT  16.553 3.36 17.197 4.44 ;
     RECT  15.491 1.728 17.221 1.752 ;
     RECT  17.197 2.832 17.221 4.44 ;
     RECT  17.053 5.52 17.411 126.984 ;
     RECT  17.221 1.728 17.605 4.44 ;
     RECT  17.605 1.728 17.845 4.536 ;
     RECT  17.411 5.52 17.845 126.744 ;
     RECT  16.021 128.208 18.173 128.232 ;
     RECT  17.845 1.728 18.469 126.744 ;
     RECT  18.229 128.832 18.569 128.856 ;
     RECT  18.469 1.728 18.604 127.608 ;
     RECT  18.604 2.148 18.707 127.608 ;
     RECT  18.707 2.148 18.712 127.452 ;
     RECT  18.805 0.576 18.892 0.6 ;
     RECT  18.712 2.256 18.904 127.182 ;
     RECT  18.904 2.256 19.513 126.744 ;
     RECT  19.484 1.104 19.571 1.128 ;
     RECT  19.513 2.256 19.813 4.44 ;
     RECT  19.813 1.728 20.513 4.44 ;
     RECT  20.101 128.832 20.579 128.856 ;
     RECT  20.513 4.416 20.684 4.44 ;
     RECT  20.513 1.728 20.801 3.432 ;
     RECT  20.801 1.776 20.909 3.432 ;
     RECT  20.684 4.416 20.977 4.536 ;
     RECT  19.513 5.52 20.977 126.744 ;
     RECT  20.933 128.208 21.017 128.232 ;
     RECT  20.909 2.112 21.125 3.432 ;
     RECT  20.977 4.416 21.397 126.744 ;
     RECT  21.125 2.112 21.413 2.952 ;
     RECT  21.397 4.416 21.541 127.704 ;
     RECT  21.541 3.936 21.557 127.704 ;
     RECT  21.413 2.832 21.593 2.952 ;
     RECT  21.557 3.936 22.124 127.128 ;
     RECT  22.273 1.728 22.403 1.752 ;
     RECT  21.593 2.832 22.597 2.856 ;
     RECT  22.789 128.832 22.961 128.856 ;
     RECT  22.597 2.208 23.077 2.856 ;
     RECT  22.124 3.84 23.077 127.128 ;
     RECT  23.077 2.208 23.653 127.128 ;
     RECT  23.353 0.576 23.725 0.6 ;
     RECT  23.653 2.064 24.008 127.128 ;
     RECT  24.008 2.064 24.085 127.452 ;
     RECT  24.085 0.288 24.373 0.312 ;
     RECT  24.373 0.192 24.419 0.312 ;
     RECT  24.085 2.064 24.437 127.608 ;
     RECT  24.419 0.192 24.515 0.216 ;
     RECT  24.437 2.064 24.661 127.128 ;
     RECT  24.661 1.728 25.085 127.128 ;
     RECT  25.085 1.728 25.229 126.792 ;
     RECT  24.517 128.832 25.427 128.856 ;
     RECT  25.813 128.208 26.057 128.232 ;
     RECT  25.229 7.392 26.197 126.792 ;
     RECT  26.197 7.392 26.291 127.08 ;
     RECT  25.229 1.728 26.389 6.312 ;
     RECT  26.291 7.392 26.389 126.792 ;
     RECT  26.677 128.832 26.777 128.856 ;
     RECT  26.389 1.728 26.957 126.792 ;
     RECT  26.957 2.736 27.461 126.792 ;
     RECT  27.461 2.736 27.497 2.856 ;
     RECT  27.461 4.32 27.605 126.792 ;
     RECT  27.497 2.832 27.641 2.856 ;
     RECT  27.817 0.192 28.211 0.216 ;
     RECT  27.097 128.208 28.217 128.232 ;
     RECT  27.605 5.52 28.421 126.792 ;
     RECT  27.605 4.32 28.453 4.44 ;
     RECT  28.421 5.52 28.505 127.656 ;
     RECT  26.957 1.728 28.885 1.752 ;
     RECT  28.885 1.728 29.077 2.28 ;
     RECT  28.453 3.408 29.077 4.44 ;
     RECT  28.505 5.52 29.077 127.608 ;
     RECT  29.077 1.728 29.512 127.608 ;
     RECT  29.512 1.728 29.704 127.182 ;
     RECT  29.893 128.832 30.017 128.856 ;
     RECT  29.704 1.728 30.227 126.792 ;
     RECT  30.325 128.256 30.701 128.28 ;
     RECT  30.227 1.728 30.845 2.856 ;
     RECT  30.757 0.192 30.899 0.216 ;
     RECT  30.845 1.728 31.169 2.328 ;
     RECT  30.227 3.888 31.189 126.792 ;
     RECT  30.757 129.36 31.205 129.384 ;
     RECT  31.169 1.824 31.249 2.328 ;
     RECT  31.189 3.888 31.265 127.704 ;
     RECT  31.265 3.408 31.276 127.704 ;
     RECT  31.249 2.208 31.925 2.328 ;
     RECT  31.276 3.408 32.197 126.744 ;
     RECT  31.621 128.832 32.321 128.856 ;
     RECT  32.197 2.928 32.393 126.744 ;
     RECT  32.393 3.408 32.485 126.744 ;
     RECT  32.485 3.408 32.897 127.704 ;
     RECT  32.897 5.136 33.491 127.704 ;
     RECT  33.613 0.576 33.779 0.6 ;
     RECT  32.485 1.728 33.829 1.752 ;
     RECT  32.897 3.984 33.865 4.008 ;
     RECT  33.865 3.408 33.877 4.008 ;
     RECT  33.491 5.136 33.877 126.792 ;
     RECT  33.865 128.208 33.949 128.232 ;
     RECT  33.829 1.728 34.693 2.28 ;
     RECT  33.877 3.408 34.693 126.792 ;
     RECT  34.693 1.728 34.787 127.608 ;
     RECT  34.787 1.728 34.912 127.452 ;
     RECT  34.912 1.728 35.104 127.182 ;
     RECT  35.104 4.512 35.353 127.182 ;
     RECT  34.309 128.832 35.692 128.856 ;
     RECT  35.353 5.52 36.037 127.182 ;
     RECT  35.953 0.576 36.083 0.6 ;
     RECT  35.104 1.728 36.237 3.432 ;
     RECT  35.353 4.512 36.421 4.536 ;
     RECT  36.037 5.52 36.421 127.704 ;
     RECT  36.421 4.512 36.569 127.704 ;
     RECT  36.237 1.728 37.109 3.336 ;
     RECT  37.109 2.784 37.393 3.336 ;
     RECT  36.569 4.512 37.393 127.176 ;
     RECT  37.393 2.784 37.427 127.176 ;
     RECT  37.427 2.784 37.433 4.536 ;
     RECT  37.427 5.52 37.613 127.176 ;
     RECT  37.501 0.192 37.667 0.216 ;
     RECT  37.433 2.832 37.685 4.536 ;
     RECT  37.685 2.832 37.793 3.864 ;
     RECT  37.681 128.256 37.811 128.28 ;
     RECT  37.613 5.52 37.865 126.792 ;
     RECT  37.793 3.312 38.045 3.864 ;
     RECT  37.109 1.728 38.117 1.752 ;
     RECT  38.797 0.576 38.881 0.6 ;
     RECT  38.045 3.312 38.905 3.432 ;
     RECT  38.821 128.832 39.125 128.856 ;
     RECT  37.865 6.864 39.253 126.792 ;
     RECT  38.905 2.832 39.445 3.432 ;
     RECT  37.865 5.52 39.445 5.832 ;
     RECT  39.253 6.864 39.445 126.984 ;
     RECT  39.109 1.728 39.481 1.752 ;
     RECT  39.445 2.784 39.481 4.008 ;
     RECT  39.445 5.52 39.685 126.984 ;
     RECT  39.481 1.728 40.021 4.008 ;
     RECT  39.685 5.52 40.021 127.704 ;
     RECT  40.021 1.728 40.205 127.704 ;
     RECT  40.205 1.728 40.312 127.452 ;
     RECT  40.312 1.728 40.504 127.182 ;
     RECT  40.504 1.728 40.889 127.176 ;
     RECT  40.549 128.832 40.889 128.856 ;
     RECT  40.889 1.728 41.473 2.328 ;
     RECT  40.889 3.408 41.609 127.176 ;
     RECT  41.609 3.408 42.179 127.08 ;
     RECT  42.179 3.408 42.437 3.96 ;
     RECT  42.437 3.408 42.757 3.864 ;
     RECT  41.473 1.728 43.109 1.752 ;
     RECT  42.757 2.736 43.109 3.864 ;
     RECT  42.179 5.04 43.141 127.08 ;
     RECT  43.109 1.728 43.193 3.864 ;
     RECT  43.141 5.04 43.337 127.128 ;
     RECT  43.193 2.736 43.477 3.864 ;
     RECT  43.337 5.04 43.477 126.984 ;
     RECT  43.477 2.736 43.859 126.984 ;
     RECT  43.909 0.576 44.003 0.6 ;
     RECT  43.193 1.728 44.533 1.752 ;
     RECT  43.859 2.736 44.533 3.624 ;
     RECT  44.533 1.728 44.869 3.624 ;
     RECT  44.869 1.728 44.945 3.768 ;
     RECT  43.859 4.848 44.945 126.984 ;
     RECT  44.945 1.728 44.965 126.984 ;
     RECT  44.965 1.728 45.533 127.128 ;
     RECT  45.533 1.824 45.608 127.128 ;
     RECT  45.608 1.824 45.613 127.452 ;
     RECT  45.613 2.148 45.712 127.452 ;
     RECT  45.712 2.16 45.904 127.182 ;
     RECT  45.829 128.832 46.541 128.856 ;
     RECT  45.904 2.16 46.739 127.128 ;
     RECT  46.597 128.784 46.739 128.808 ;
     RECT  46.739 2.16 47.005 127.08 ;
     RECT  47.005 1.776 47.017 127.08 ;
     RECT  47.017 2.832 47.081 127.08 ;
     RECT  47.017 1.776 47.257 1.8 ;
     RECT  47.557 128.208 47.765 128.232 ;
     RECT  47.081 3.984 48.133 127.08 ;
     RECT  47.081 2.832 48.193 2.856 ;
     RECT  48.133 3.984 48.269 127.656 ;
     RECT  48.193 2.784 48.419 2.952 ;
     RECT  47.257 1.728 48.421 1.8 ;
     RECT  48.419 2.784 48.421 2.808 ;
     RECT  48.269 7.392 48.449 127.656 ;
     RECT  48.565 128.832 48.845 128.856 ;
     RECT  48.421 1.728 48.989 2.808 ;
     RECT  48.989 2.256 49.283 2.808 ;
     RECT  48.269 3.984 49.309 5.832 ;
     RECT  48.449 7.392 49.436 126.744 ;
     RECT  49.283 2.304 49.477 2.808 ;
     RECT  49.309 3.984 49.477 6.264 ;
     RECT  49.436 7.392 49.523 127.704 ;
     RECT  49.868 128.832 49.955 128.856 ;
     RECT  49.523 7.392 50.317 126.744 ;
     RECT  50.317 0.576 50.401 0.6 ;
     RECT  50.317 7.344 50.437 126.744 ;
     RECT  49.477 2.304 50.677 6.264 ;
     RECT  50.437 7.296 50.677 126.744 ;
     RECT  50.677 2.304 50.741 126.744 ;
     RECT  50.741 1.728 50.773 126.792 ;
     RECT  50.773 1.728 51.185 127.704 ;
     RECT  51.185 1.728 51.304 127.56 ;
     RECT  51.304 6.816 51.401 127.56 ;
     RECT  51.401 6.816 51.473 126.792 ;
     RECT  51.349 0.192 51.491 0.216 ;
     RECT  51.473 6.816 51.553 7.752 ;
     RECT  51.473 8.784 51.869 126.792 ;
     RECT  51.553 7.008 52.553 7.752 ;
     RECT  51.304 1.728 52.645 1.752 ;
     RECT  51.304 2.88 52.645 5.832 ;
     RECT  52.645 1.728 52.877 5.832 ;
     RECT  51.869 8.976 52.933 126.792 ;
     RECT  52.069 128.832 52.949 128.856 ;
     RECT  52.877 2.304 53.017 5.832 ;
     RECT  52.933 8.976 53.021 127.176 ;
     RECT  52.945 0.192 53.123 0.216 ;
     RECT  52.553 7.008 53.165 7.656 ;
     RECT  53.017 2.304 53.557 5.88 ;
     RECT  53.557 2.304 53.777 6.312 ;
     RECT  53.777 2.304 53.9 5.88 ;
     RECT  53.165 7.632 53.917 7.656 ;
     RECT  53.021 8.976 53.939 126.792 ;
     RECT  53.365 128.208 54.029 128.232 ;
     RECT  53.939 8.976 54.035 125.688 ;
     RECT  53.917 7.632 54.133 7.992 ;
     RECT  54.133 7.104 54.179 7.992 ;
     RECT  54.179 7.104 54.22 7.656 ;
     RECT  53.9 2.208 54.389 5.88 ;
     RECT  54.389 3.408 54.425 5.88 ;
     RECT  54.22 7.632 54.605 7.656 ;
     RECT  53.939 126.72 54.709 126.792 ;
     RECT  54.389 2.208 54.749 2.328 ;
     RECT  54.709 126.72 54.803 127.08 ;
     RECT  54.749 2.208 54.817 2.28 ;
     RECT  54.035 8.976 54.997 125.64 ;
     RECT  54.803 126.72 54.997 126.792 ;
     RECT  54.997 8.976 55.037 126.792 ;
     RECT  55.037 9.168 55.283 126.792 ;
     RECT  54.425 5.184 55.621 5.88 ;
     RECT  55.573 6.864 55.621 6.984 ;
     RECT  54.425 3.408 55.681 3.912 ;
     RECT  55.621 5.184 55.681 6.984 ;
     RECT  54.817 1.728 55.685 2.28 ;
     RECT  55.685 2.148 56.252 2.28 ;
     RECT  55.681 3.408 56.252 6.984 ;
     RECT  56.252 2.148 56.408 6.984 ;
     RECT  55.283 9.168 56.408 125.64 ;
     RECT  55.283 126.72 56.408 126.792 ;
     RECT  56.408 2.148 56.512 127.452 ;
     RECT  56.512 2.148 56.704 127.182 ;
     RECT  55.189 128.832 56.765 128.856 ;
     RECT  56.629 0.192 56.819 0.216 ;
     RECT  56.704 8.544 57.017 127.128 ;
     RECT  56.704 2.148 57.049 7.176 ;
     RECT  57.049 1.728 57.251 7.176 ;
     RECT  57.251 2.16 57.629 7.176 ;
     RECT  57.017 8.544 57.805 126.792 ;
     RECT  57.913 128.208 57.997 128.232 ;
     RECT  57.629 2.16 58.213 5.832 ;
     RECT  57.805 8.208 58.357 126.792 ;
     RECT  58.213 1.728 58.597 5.832 ;
     RECT  57.629 6.816 58.597 7.176 ;
     RECT  58.357 8.208 58.709 127.128 ;
     RECT  58.709 125.808 58.769 127.128 ;
     RECT  58.769 125.808 58.853 127.656 ;
     RECT  58.709 8.208 59.033 124.68 ;
     RECT  58.597 1.728 59.171 7.176 ;
     RECT  58.853 125.808 59.308 127.128 ;
     RECT  59.171 1.728 59.357 6.024 ;
     RECT  59.033 9.216 59.507 124.68 ;
     RECT  59.357 2.832 59.609 2.856 ;
     RECT  59.171 7.152 59.749 7.176 ;
     RECT  59.033 8.208 59.749 8.232 ;
     RECT  59.507 60.048 59.749 124.68 ;
     RECT  59.308 125.808 59.749 126.792 ;
     RECT  59.357 3.84 59.933 6.024 ;
     RECT  59.749 7.152 60.073 8.232 ;
     RECT  59.507 9.216 60.073 59.064 ;
     RECT  60.073 7.152 60.077 59.064 ;
     RECT  59.933 3.84 60.541 5.832 ;
     RECT  60.077 8.784 60.577 59.064 ;
     RECT  59.749 60.048 60.577 126.792 ;
     RECT  60.541 3.312 60.929 5.832 ;
     RECT  59.357 1.728 61.045 1.752 ;
     RECT  60.929 2.832 61.045 5.832 ;
     RECT  61.045 1.728 61.148 5.832 ;
     RECT  60.577 8.784 61.261 126.792 ;
     RECT  61.148 1.728 61.285 5.928 ;
     RECT  60.077 7.152 61.285 7.176 ;
     RECT  61.261 8.16 61.429 126.792 ;
     RECT  60.133 128.832 61.445 128.856 ;
     RECT  61.429 8.16 61.729 127.416 ;
     RECT  60.397 0.192 61.763 0.216 ;
     RECT  61.285 1.728 61.808 7.176 ;
     RECT  61.729 8.16 61.808 128.04 ;
     RECT  61.808 1.728 61.907 128.04 ;
     RECT  61.907 1.728 61.912 127.452 ;
     RECT  61.912 1.728 62.104 127.182 ;
     RECT  62.293 129.36 62.341 129.384 ;
     RECT  62.104 8.16 62.345 8.184 ;
     RECT  62.104 9.888 62.381 126.792 ;
     RECT  62.341 129.36 62.425 129.48 ;
     RECT  62.381 10.08 62.675 126.792 ;
     RECT  62.675 10.08 62.705 126.744 ;
     RECT  62.104 4.032 62.777 7.176 ;
     RECT  62.725 128.832 62.812 128.856 ;
     RECT  62.705 10.08 62.849 122.76 ;
     RECT  62.705 123.792 62.849 126.744 ;
     RECT  62.777 4.368 63.097 7.176 ;
     RECT  63.133 2.88 63.157 2.904 ;
     RECT  63.097 4.368 63.349 7.752 ;
     RECT  62.849 10.08 63.461 122.232 ;
     RECT  63.349 4.368 63.637 7.848 ;
     RECT  63.157 2.88 63.745 3.336 ;
     RECT  63.637 4.368 63.745 8.568 ;
     RECT  63.745 2.88 63.781 8.568 ;
     RECT  63.781 2.832 63.865 8.568 ;
     RECT  62.849 123.84 63.889 126.744 ;
     RECT  63.461 10.08 63.893 121.992 ;
     RECT  63.865 3.216 63.923 8.568 ;
     RECT  63.923 4.368 63.929 8.568 ;
     RECT  63.923 3.216 64.073 3.24 ;
     RECT  63.929 4.56 64.181 8.568 ;
     RECT  64.021 128.832 64.181 128.856 ;
     RECT  63.889 123.264 64.453 126.744 ;
     RECT  63.893 10.128 64.465 121.992 ;
     RECT  64.453 123.264 64.465 126.888 ;
     RECT  62.104 1.728 64.643 1.752 ;
     RECT  64.181 4.704 64.933 8.568 ;
     RECT  64.465 10.128 64.972 126.888 ;
     RECT  64.933 4.704 65.221 8.856 ;
     RECT  65.221 4.512 65.437 8.856 ;
     RECT  65.509 0.192 65.545 0.216 ;
     RECT  65.545 0.192 65.629 0.6 ;
     RECT  65.437 4.512 65.689 8.952 ;
     RECT  64.972 10.128 65.689 126.744 ;
     RECT  65.629 0.192 65.891 0.216 ;
     RECT  65.689 4.512 66.701 126.744 ;
     RECT  66.701 4.512 66.709 126.792 ;
     RECT  66.709 4.512 67.045 126.84 ;
     RECT  67.045 4.512 67.187 127.608 ;
     RECT  66.133 1.728 67.208 1.752 ;
     RECT  66.625 3.408 67.208 3.432 ;
     RECT  67.187 4.512 67.208 127.452 ;
     RECT  67.208 1.728 67.312 127.452 ;
     RECT  67.312 1.728 67.504 127.182 ;
     RECT  67.165 0.528 67.619 0.552 ;
     RECT  67.504 10.368 68.321 118.728 ;
     RECT  67.504 8.208 68.533 9.192 ;
     RECT  68.533 7.968 68.645 9.192 ;
     RECT  68.321 10.608 68.645 118.728 ;
     RECT  67.504 1.728 68.749 1.8 ;
     RECT  67.504 4.8 68.857 5.592 ;
     RECT  67.504 120 68.869 127.128 ;
     RECT  68.749 1.728 68.915 2.28 ;
     RECT  68.645 10.656 69.073 118.728 ;
     RECT  68.869 120 69.073 127.176 ;
     RECT  68.857 4.56 69.145 5.592 ;
     RECT  68.645 7.968 69.257 9.096 ;
     RECT  69.073 10.656 69.329 127.176 ;
     RECT  69.145 4.56 69.361 5.688 ;
     RECT  69.329 13.584 69.473 127.176 ;
     RECT  69.361 4.56 69.581 6.504 ;
     RECT  69.541 3.456 69.613 3.48 ;
     RECT  69.581 4.944 69.613 6.504 ;
     RECT  69.613 4.944 69.649 6.552 ;
     RECT  69.257 7.968 69.649 8.856 ;
     RECT  69.473 13.584 69.653 117.096 ;
     RECT  69.653 13.632 69.683 117.096 ;
     RECT  69.329 10.656 69.793 12.6 ;
     RECT  69.613 2.88 69.797 3.48 ;
     RECT  69.473 118.08 69.869 127.176 ;
     RECT  69.683 13.68 69.977 117.096 ;
     RECT  69.649 4.944 70.193 8.856 ;
     RECT  69.977 14.112 70.193 116.568 ;
     RECT  69.793 10.368 70.453 12.6 ;
     RECT  70.453 10.224 70.589 12.6 ;
     RECT  70.589 10.368 70.657 12.6 ;
     RECT  70.193 103.296 70.691 116.568 ;
     RECT  69.869 118.08 70.801 126.888 ;
     RECT  70.193 14.112 70.805 102.264 ;
     RECT  70.193 4.944 70.837 5.736 ;
     RECT  69.797 3.456 70.985 3.48 ;
     RECT  70.805 16.848 71.164 102.264 ;
     RECT  70.801 117.936 71.165 126.888 ;
     RECT  70.657 10.368 71.197 12.792 ;
     RECT  70.805 14.112 71.197 15.816 ;
     RECT  70.193 7.2 71.516 8.856 ;
     RECT  71.164 17.04 71.557 102.264 ;
     RECT  70.691 103.296 71.557 116.184 ;
     RECT  71.557 17.04 71.603 116.184 ;
     RECT  70.837 4.8 71.701 5.736 ;
     RECT  71.516 6.864 71.701 8.856 ;
     RECT  71.165 119.664 71.729 126.888 ;
     RECT  71.603 38.208 72.205 116.184 ;
     RECT  72.205 38.208 72.325 116.904 ;
     RECT  71.165 117.936 72.325 118.44 ;
     RECT  71.729 119.664 72.325 127.128 ;
     RECT  72.325 119.568 72.449 127.128 ;
     RECT  71.701 4.8 72.469 8.856 ;
     RECT  72.449 119.568 72.476 127.464 ;
     RECT  68.915 1.728 72.608 1.752 ;
     RECT  72.469 4.8 72.608 9 ;
     RECT  71.197 10.368 72.608 15.816 ;
     RECT  71.603 17.04 72.608 37.176 ;
     RECT  72.325 38.208 72.608 118.44 ;
     RECT  72.476 119.568 72.608 127.56 ;
     RECT  72.608 1.728 72.904 127.56 ;
     RECT  72.917 0.576 73.001 0.6 ;
     RECT  72.904 8.976 73.001 9.384 ;
     RECT  72.904 125.904 73.036 127.56 ;
     RECT  72.904 19.344 73.043 19.368 ;
     RECT  72.904 55.488 73.045 116.328 ;
     RECT  73.045 55.488 73.109 116.28 ;
     RECT  72.904 26.496 73.139 37.08 ;
     RECT  72.904 3.744 73.283 3.768 ;
     RECT  72.904 38.112 73.289 54.456 ;
     RECT  72.904 14.064 73.42 15.816 ;
     RECT  73.139 26.496 73.433 36.36 ;
     RECT  72.904 4.944 73.523 7.464 ;
     RECT  72.904 24.432 73.523 25.032 ;
     RECT  73.42 14.16 73.613 15.816 ;
     RECT  73.109 55.488 73.685 115.992 ;
     RECT  73.523 24.72 73.763 25.032 ;
     RECT  73.433 26.496 73.763 35.928 ;
     RECT  73.523 4.944 73.793 7.08 ;
     RECT  72.904 119.664 73.829 124.92 ;
     RECT  73.036 125.904 73.897 126.792 ;
     RECT  72.904 1.728 73.916 1.752 ;
     RECT  73.685 55.488 73.925 115.272 ;
     RECT  73.613 15.744 73.929 15.816 ;
     RECT  73.289 38.112 73.969 54.12 ;
     RECT  73.763 26.496 73.973 35.832 ;
     RECT  73.916 1.728 74.003 2.28 ;
     RECT  73.829 119.664 74.005 124.824 ;
     RECT  73.973 34.416 74.009 35.832 ;
     RECT  73.001 9.36 74.041 9.384 ;
     RECT  72.904 10.368 74.041 12.792 ;
     RECT  73.929 15.792 74.045 15.816 ;
     RECT  73.969 37.776 74.081 54.12 ;
     RECT  74.041 9.36 74.099 12.792 ;
     RECT  74.081 38.112 74.099 54.12 ;
     RECT  74.099 38.112 74.117 47.448 ;
     RECT  74.099 9.36 74.125 10.248 ;
     RECT  74.099 48.432 74.147 54.12 ;
     RECT  72.904 118.08 74.185 118.104 ;
     RECT  74.005 119.136 74.189 124.824 ;
     RECT  74.185 117.408 74.221 118.104 ;
     RECT  74.117 38.112 74.225 47.352 ;
     RECT  74.147 48.48 74.269 54.12 ;
     RECT  73.793 4.944 74.329 5.736 ;
     RECT  74.125 9.36 74.329 9.384 ;
     RECT  73.793 6.816 74.333 7.08 ;
     RECT  73.613 14.16 74.333 14.184 ;
     RECT  72.904 17.136 74.441 17.16 ;
     RECT  74.329 8.496 74.531 9.384 ;
     RECT  74.329 4.08 74.533 5.736 ;
     RECT  74.533 3.744 74.579 5.736 ;
     RECT  73.973 26.496 74.579 33.432 ;
     RECT  74.009 34.416 74.585 35.208 ;
     RECT  74.579 3.744 74.621 5.448 ;
     RECT  74.269 48.48 74.621 54.072 ;
     RECT  74.221 116.544 74.657 118.104 ;
     RECT  73.897 125.808 74.677 126.792 ;
     RECT  74.579 28.176 74.693 33.432 ;
     RECT  74.693 28.176 74.723 31.8 ;
     RECT  74.677 125.808 74.765 127.416 ;
     RECT  74.621 4.08 74.801 5.448 ;
     RECT  74.723 28.176 74.801 29.112 ;
     RECT  74.585 34.752 74.867 35.208 ;
     RECT  74.225 38.16 74.909 47.352 ;
     RECT  74.531 9.36 74.945 9.384 ;
     RECT  74.909 45.12 74.945 47.352 ;
     RECT  73.925 55.296 74.977 115.272 ;
     RECT  74.909 38.16 74.981 43.896 ;
     RECT  74.945 45.12 75.155 47.16 ;
     RECT  74.981 38.16 75.233 43.272 ;
     RECT  75.155 45.168 75.244 47.16 ;
     RECT  74.833 20.544 75.251 20.568 ;
     RECT  74.977 55.2 75.301 115.272 ;
     RECT  75.244 45.168 75.305 46.92 ;
     RECT  75.233 41.04 75.341 43.272 ;
     RECT  75.233 38.16 75.413 39.96 ;
     RECT  75.305 45.216 75.413 46.92 ;
     RECT  74.621 48.48 75.413 53.88 ;
     RECT  75.413 48.576 75.449 53.88 ;
     RECT  75.413 45.264 75.521 46.92 ;
     RECT  75.341 41.04 75.593 41.976 ;
     RECT  74.657 117.408 75.625 118.104 ;
     RECT  74.189 119.136 75.625 121.848 ;
     RECT  75.593 41.04 75.629 41.64 ;
     RECT  75.413 38.784 75.635 39.96 ;
     RECT  75.449 48.672 75.737 53.88 ;
     RECT  75.737 48.672 75.773 53.4 ;
     RECT  74.189 123.456 75.781 124.824 ;
     RECT  74.765 125.808 75.781 126.984 ;
     RECT  75.629 41.04 75.809 41.064 ;
     RECT  75.521 45.264 75.809 46.872 ;
     RECT  74.801 4.944 75.829 5.448 ;
     RECT  74.333 7.056 75.829 7.08 ;
     RECT  74.099 11.232 75.845 12.792 ;
     RECT  75.829 4.944 75.875 7.08 ;
     RECT  75.845 11.376 75.875 12.792 ;
     RECT  75.301 55.2 75.877 115.752 ;
     RECT  75.781 123.456 75.913 126.984 ;
     RECT  75.877 55.2 75.923 116.328 ;
     RECT  75.923 55.2 75.989 81.768 ;
     RECT  75.205 19.152 76.021 19.176 ;
     RECT  75.989 55.2 76.021 57.048 ;
     RECT  76.021 18.816 76.061 19.176 ;
     RECT  75.773 48.768 76.061 53.4 ;
     RECT  76.021 55.152 76.067 57.048 ;
     RECT  75.875 11.376 76.163 12.6 ;
     RECT  76.061 48.768 76.241 49.08 ;
     RECT  76.067 55.152 76.277 56.904 ;
     RECT  75.913 123.024 76.277 126.984 ;
     RECT  76.277 123.024 76.307 124.872 ;
     RECT  76.061 50.16 76.313 53.4 ;
     RECT  76.277 55.152 76.349 55.848 ;
     RECT  74.723 30.384 76.403 31.8 ;
     RECT  75.923 116.304 76.405 116.328 ;
     RECT  75.625 117.408 76.405 121.848 ;
     RECT  76.307 123.024 76.405 124.728 ;
     RECT  75.809 45.264 76.451 46.104 ;
     RECT  76.277 56.88 76.457 56.904 ;
     RECT  76.277 125.952 76.457 126.984 ;
     RECT  76.405 116.304 76.493 124.728 ;
     RECT  76.163 11.952 76.529 12.6 ;
     RECT  76.381 0.576 76.547 0.6 ;
     RECT  76.313 50.736 76.637 53.4 ;
     RECT  75.635 38.784 76.709 39.384 ;
     RECT  76.241 48.768 76.777 48.936 ;
     RECT  75.875 4.944 76.781 6.84 ;
     RECT  75.923 82.896 76.853 115.128 ;
     RECT  76.637 50.736 76.889 52.488 ;
     RECT  76.781 4.944 76.931 6.312 ;
     RECT  76.457 126.48 76.933 126.984 ;
     RECT  76.451 45.264 76.979 45.288 ;
     RECT  76.889 50.736 76.979 51.624 ;
     RECT  76.237 3.696 76.988 3.72 ;
     RECT  76.529 11.952 76.997 11.976 ;
     RECT  74.801 28.176 76.997 28.968 ;
     RECT  76.777 48.384 76.997 48.936 ;
     RECT  75.989 58.416 76.997 81.768 ;
     RECT  76.561 47.088 77.033 47.112 ;
     RECT  76.997 60.672 77.065 81.768 ;
     RECT  76.853 82.896 77.065 107.256 ;
     RECT  76.853 108.288 77.084 115.128 ;
     RECT  76.493 116.304 77.084 121.704 ;
     RECT  76.997 58.416 77.173 59.592 ;
     RECT  76.933 53.472 77.413 53.592 ;
     RECT  76.349 55.152 77.413 55.176 ;
     RECT  76.933 126.48 77.509 127.08 ;
     RECT  76.493 122.784 77.533 124.728 ;
     RECT  77.509 126.432 77.533 127.08 ;
     RECT  76.117 16.8 77.569 16.824 ;
     RECT  76.979 50.736 77.569 51.192 ;
     RECT  77.497 0.192 77.581 0.216 ;
     RECT  77.084 108.288 77.641 121.704 ;
     RECT  77.533 122.784 77.641 127.08 ;
     RECT  76.403 30.384 77.785 31.752 ;
     RECT  77.845 128.784 77.987 128.808 ;
     RECT  74.003 1.728 78.008 1.752 ;
     RECT  76.988 3.36 78.008 3.72 ;
     RECT  76.931 4.944 78.008 6.12 ;
     RECT  77.893 7.968 78.008 7.992 ;
     RECT  77.893 8.976 78.008 9 ;
     RECT  77.785 11.52 78.008 11.544 ;
     RECT  77.569 16.8 78.008 17.496 ;
     RECT  76.061 18.816 78.008 18.84 ;
     RECT  72.904 22.272 78.008 22.488 ;
     RECT  73.763 25.008 78.008 25.032 ;
     RECT  74.579 26.496 78.008 26.52 ;
     RECT  76.997 28.176 78.008 28.2 ;
     RECT  77.785 30.336 78.008 31.752 ;
     RECT  74.693 32.832 78.008 33.432 ;
     RECT  74.867 34.752 78.008 34.92 ;
     RECT  76.709 39.36 78.008 39.384 ;
     RECT  75.341 43.056 78.008 43.272 ;
     RECT  76.997 48.384 78.008 48.792 ;
     RECT  77.569 50.688 78.008 51.192 ;
     RECT  77.413 53.472 78.008 55.176 ;
     RECT  77.173 58.32 78.008 59.592 ;
     RECT  77.065 60.672 78.008 107.256 ;
     RECT  77.641 108.288 78.008 127.08 ;
     RECT  78.008 1.728 78.112 127.452 ;
     RECT  78.112 1.728 78.304 127.182 ;
     RECT  78.304 73.584 78.401 79.992 ;
     RECT  78.304 55.152 78.419 55.416 ;
     RECT  78.304 57.024 78.419 57.864 ;
     RECT  78.304 108.72 78.419 108.792 ;
     RECT  78.401 73.584 78.46 77.976 ;
     RECT  78.304 106.56 78.467 107.304 ;
     RECT  78.304 51.072 78.473 51.192 ;
     RECT  78.46 73.584 78.515 77.88 ;
     RECT  78.401 79.44 78.515 79.992 ;
     RECT  78.515 79.776 78.545 79.992 ;
     RECT  78.304 86.496 78.545 105.432 ;
     RECT  78.467 106.56 78.545 107.256 ;
     RECT  78.304 84.528 78.563 85.512 ;
     RECT  78.545 94.512 78.563 105.432 ;
     RECT  78.563 94.56 78.581 105.432 ;
     RECT  78.304 112.656 78.581 116.76 ;
     RECT  78.515 73.584 78.617 77.688 ;
     RECT  78.304 68.688 78.653 69.336 ;
     RECT  78.304 10.224 78.659 10.248 ;
     RECT  78.304 16.8 78.689 18.168 ;
     RECT  78.545 106.704 78.689 107.256 ;
     RECT  78.617 73.632 78.725 77.688 ;
     RECT  78.304 13.536 78.733 13.56 ;
     RECT  78.545 86.496 78.761 93.528 ;
     RECT  78.304 59.472 78.797 60.696 ;
     RECT  78.304 11.52 78.803 12.216 ;
     RECT  78.304 118.032 78.833 127.08 ;
     RECT  78.725 73.632 78.851 75.24 ;
     RECT  78.761 86.736 78.869 93.528 ;
     RECT  78.833 118.032 78.899 125.448 ;
     RECT  78.581 112.656 78.905 113.016 ;
     RECT  78.581 94.56 78.947 101.064 ;
     RECT  78.581 102.048 78.947 105.432 ;
     RECT  78.833 126.528 78.977 127.08 ;
     RECT  78.689 17.856 78.995 18.168 ;
     RECT  78.304 22.176 78.995 22.824 ;
     RECT  78.869 86.736 79.013 91.368 ;
     RECT  78.947 95.664 79.013 101.064 ;
     RECT  78.851 73.632 79.049 74.712 ;
     RECT  78.947 102.528 79.085 105.432 ;
     RECT  79.085 104.352 79.091 105.432 ;
     RECT  78.581 114.144 79.091 116.76 ;
     RECT  79.013 86.736 79.121 88.92 ;
     RECT  79.085 102.528 79.132 102.984 ;
     RECT  79.091 114.144 79.132 114.456 ;
     RECT  79.013 90.432 79.157 91.368 ;
     RECT  78.995 22.272 79.193 22.824 ;
     RECT  78.304 43.056 79.193 43.272 ;
     RECT  79.049 74.16 79.193 74.712 ;
     RECT  78.563 84.528 79.193 84.984 ;
     RECT  79.121 86.832 79.193 88.92 ;
     RECT  79.091 104.496 79.229 105.432 ;
     RECT  79.132 114.288 79.229 114.456 ;
     RECT  79.193 86.832 79.265 88.824 ;
     RECT  78.304 62.976 79.283 65.544 ;
     RECT  79.013 95.712 79.301 101.064 ;
     RECT  78.689 106.992 79.301 107.256 ;
     RECT  78.947 94.56 79.331 94.584 ;
     RECT  79.193 22.464 79.337 22.824 ;
     RECT  78.304 109.968 79.337 109.992 ;
     RECT  79.283 63.216 79.388 65.544 ;
     RECT  78.304 67.152 79.388 67.176 ;
     RECT  78.304 81.696 79.409 83.064 ;
     RECT  79.301 107.232 79.409 107.256 ;
     RECT  79.229 114.288 79.409 114.312 ;
     RECT  79.388 63.216 79.429 67.176 ;
     RECT  78.304 28.176 79.441 28.2 ;
     RECT  79.429 63.216 79.475 67.56 ;
     RECT  78.797 59.472 79.484 60.6 ;
     RECT  79.301 95.712 79.489 100.968 ;
     RECT  79.475 63.216 79.516 65.544 ;
     RECT  79.484 59.184 79.517 60.6 ;
     RECT  79.193 84.576 79.517 84.984 ;
     RECT  79.489 96.336 79.517 100.968 ;
     RECT  78.419 108.768 79.549 108.792 ;
     RECT  78.869 92.4 79.553 93.528 ;
     RECT  79.517 59.184 79.571 60.504 ;
     RECT  78.304 25.008 79.585 25.032 ;
     RECT  78.304 26.496 79.585 26.52 ;
     RECT  78.304 111.024 79.589 111.432 ;
     RECT  79.517 97.968 79.625 100.968 ;
     RECT  79.517 84.96 79.697 84.984 ;
     RECT  79.157 90.432 79.697 91.224 ;
     RECT  79.517 96.864 79.697 96.888 ;
     RECT  79.625 97.968 79.761 100.92 ;
     RECT  78.725 76.32 79.772 77.688 ;
     RECT  79.697 90.432 79.805 91.08 ;
     RECT  79.091 115.584 79.805 116.76 ;
     RECT  78.304 9.024 79.813 9.048 ;
     RECT  78.304 34.752 79.813 34.92 ;
     RECT  79.761 97.968 79.841 100.776 ;
     RECT  79.693 0.192 79.859 0.216 ;
     RECT  79.813 8.544 79.859 9.048 ;
     RECT  79.772 76.32 79.859 78.6 ;
     RECT  78.304 32.832 79.861 33.432 ;
     RECT  79.813 34.752 79.861 35.592 ;
     RECT  79.805 115.584 79.877 116.616 ;
     RECT  79.861 32.832 79.9 35.592 ;
     RECT  79.813 36.672 79.9 36.696 ;
     RECT  78.653 69.312 79.909 69.336 ;
     RECT  78.304 70.368 79.909 71.304 ;
     RECT  79.337 22.464 79.913 22.488 ;
     RECT  79.9 32.832 79.921 35.352 ;
     RECT  79.589 111.408 79.949 111.432 ;
     RECT  78.899 118.032 79.949 125.352 ;
     RECT  78.689 16.8 79.964 16.824 ;
     RECT  78.995 17.856 79.964 17.88 ;
     RECT  78.473 51.072 79.964 51.096 ;
     RECT  79.441 27.888 80.005 28.2 ;
     RECT  79.964 50.976 80.017 51.096 ;
     RECT  79.964 16.8 80.021 17.88 ;
     RECT  80.021 16.992 80.051 17.88 ;
     RECT  79.571 59.52 80.051 60.504 ;
     RECT  79.549 108.768 80.051 109.416 ;
     RECT  78.905 112.8 80.053 113.016 ;
     RECT  79.921 32.832 80.057 34.776 ;
     RECT  80.017 50.736 80.057 51.096 ;
     RECT  79.949 123.12 80.089 125.352 ;
     RECT  79.553 92.688 80.129 93.528 ;
     RECT  79.132 102.96 80.161 102.984 ;
     RECT  79.409 81.744 80.165 83.064 ;
     RECT  80.161 102.96 80.197 103.752 ;
     RECT  80.053 112.464 80.197 113.064 ;
     RECT  78.977 127.008 80.197 127.08 ;
     RECT  79.841 98.064 80.201 100.776 ;
     RECT  79.949 118.032 80.243 121.992 ;
     RECT  80.204 45.888 80.245 45.912 ;
     RECT  80.197 112.08 80.284 113.064 ;
     RECT  80.245 44.976 80.291 45.912 ;
     RECT  80.197 127.008 80.305 127.128 ;
     RECT  80.089 123.12 80.309 125.448 ;
     RECT  79.585 38.16 80.341 38.184 ;
     RECT  78.304 39.36 80.341 39.384 ;
     RECT  79.193 74.688 80.341 74.712 ;
     RECT  79.877 115.584 80.341 116.568 ;
     RECT  79.909 69.312 80.381 71.304 ;
     RECT  80.341 38.16 80.387 39.384 ;
     RECT  80.341 73.92 80.387 74.712 ;
     RECT  80.165 81.888 80.387 83.064 ;
     RECT  80.341 115.104 80.387 116.568 ;
     RECT  79.585 25.008 80.389 26.52 ;
     RECT  80.005 27.888 80.389 29.112 ;
     RECT  80.197 102 80.389 103.752 ;
     RECT  79.229 105.408 80.389 105.432 ;
     RECT  80.305 126.528 80.389 127.128 ;
     RECT  78.419 55.392 80.417 55.416 ;
     RECT  80.051 108.768 80.417 108.888 ;
     RECT  80.309 123.12 80.417 124.152 ;
     RECT  80.389 126.912 80.417 127.128 ;
     RECT  80.387 115.104 80.428 115.128 ;
     RECT  80.389 102 80.435 105.432 ;
     RECT  80.243 119.664 80.435 121.992 ;
     RECT  80.377 0.576 80.461 0.6 ;
     RECT  78.304 61.728 80.485 61.752 ;
     RECT  80.417 126.912 80.489 127.08 ;
     RECT  79.265 87.504 80.492 88.824 ;
     RECT  80.129 93.36 80.492 93.528 ;
     RECT  80.444 2.784 80.531 2.808 ;
     RECT  80.243 118.032 80.54 118.632 ;
     RECT  80.435 104.544 80.561 105.432 ;
     RECT  80.417 123.12 80.572 123.624 ;
     RECT  80.492 87.504 80.579 89.496 ;
     RECT  79.805 91.056 80.579 91.08 ;
     RECT  80.492 93.36 80.579 94.296 ;
     RECT  80.54 117.936 80.627 118.632 ;
     RECT  80.387 73.92 80.629 73.944 ;
     RECT  80.485 61.008 80.633 61.752 ;
     RECT  80.579 87.504 80.633 88.824 ;
     RECT  78.304 30.336 80.636 31.752 ;
     RECT  80.057 32.832 80.636 34.008 ;
     RECT  80.057 50.736 80.665 51 ;
     RECT  80.435 102 80.669 103.176 ;
     RECT  80.387 116.208 80.669 116.568 ;
     RECT  80.633 87.504 80.675 88.344 ;
     RECT  80.636 30.336 80.723 34.008 ;
     RECT  80.561 105.408 80.723 105.432 ;
     RECT  80.417 108.864 80.723 108.888 ;
     RECT  80.533 92.352 80.741 92.376 ;
     RECT  80.627 117.936 80.741 118.056 ;
     RECT  80.677 106.704 80.764 106.728 ;
     RECT  80.201 98.064 80.771 99.192 ;
     RECT  78.304 47.28 80.773 47.304 ;
     RECT  80.665 50.496 80.773 51 ;
     RECT  78.545 79.968 80.777 79.992 ;
     RECT  80.579 93.36 80.777 93.48 ;
     RECT  80.309 125.328 80.777 125.448 ;
     RECT  80.771 98.064 80.812 98.232 ;
     RECT  78.304 4.944 80.813 6.264 ;
     RECT  80.773 47.28 80.819 48.12 ;
     RECT  80.669 116.304 80.845 116.568 ;
     RECT  80.389 25.008 80.849 29.304 ;
     RECT  80.819 48.096 80.86 48.12 ;
     RECT  80.572 123.12 80.867 123.144 ;
     RECT  80.381 70.224 80.915 71.304 ;
     RECT  80.435 119.808 80.915 121.992 ;
     RECT  80.089 3.936 80.917 3.96 ;
     RECT  80.813 4.944 80.917 5.064 ;
     RECT  80.849 25.008 80.917 28.2 ;
     RECT  80.869 69.12 80.956 69.144 ;
     RECT  80.629 73.392 80.957 73.944 ;
     RECT  80.845 116.304 80.957 116.856 ;
     RECT  80.773 49.776 80.963 51 ;
     RECT  80.915 70.656 80.963 71.304 ;
     RECT  80.387 38.16 80.993 38.76 ;
     RECT  80.387 82.08 80.993 83.064 ;
     RECT  80.957 73.392 81.065 73.416 ;
     RECT  80.915 119.808 81.065 121.32 ;
     RECT  79.859 8.544 81.097 8.568 ;
     RECT  80.051 17.856 81.097 17.88 ;
     RECT  80.284 113.04 81.101 113.064 ;
     RECT  81.065 119.808 81.173 120.792 ;
     RECT  80.917 24.768 81.209 28.2 ;
     RECT  81.097 8.544 81.212 8.952 ;
     RECT  79.859 76.32 81.245 78.072 ;
     RECT  80.489 126.912 81.245 126.984 ;
     RECT  81.097 17.232 81.251 17.88 ;
     RECT  81.164 20.784 81.251 20.808 ;
     RECT  80.557 10.272 81.253 10.296 ;
     RECT  80.917 3.936 81.299 5.064 ;
     RECT  80.813 6.24 81.299 6.264 ;
     RECT  81.212 7.872 81.299 8.952 ;
     RECT  81.253 10.032 81.299 10.296 ;
     RECT  80.723 30.336 81.317 31.752 ;
     RECT  81.245 76.416 81.325 78.072 ;
     RECT  81.299 4.272 81.34 5.064 ;
     RECT  81.299 10.032 81.389 10.056 ;
     RECT  81.209 25.008 81.389 28.2 ;
     RECT  80.723 32.832 81.425 34.008 ;
     RECT  80.917 72.384 81.425 72.408 ;
     RECT  78.803 12.192 81.445 12.216 ;
     RECT  81.445 11.28 81.491 12.216 ;
     RECT  81.097 14.88 81.491 14.904 ;
     RECT  80.993 38.736 81.493 38.76 ;
     RECT  79.193 43.248 81.493 43.272 ;
     RECT  81.491 11.28 81.532 11.304 ;
     RECT  81.389 26.496 81.533 28.2 ;
     RECT  81.493 38.736 81.533 39.336 ;
     RECT  81.325 76.752 81.533 78.072 ;
     RECT  79.513 42.192 81.539 42.216 ;
     RECT  81.533 39.312 81.58 39.336 ;
     RECT  81.205 19.776 81.605 19.8 ;
     RECT  81.493 40.416 81.605 40.44 ;
     RECT  81.493 43.248 81.641 43.368 ;
     RECT  78.419 57.84 81.641 57.864 ;
     RECT  80.741 117.936 81.641 117.96 ;
     RECT  80.675 87.504 81.677 87.864 ;
     RECT  80.291 44.976 81.713 45 ;
     RECT  81.389 25.008 81.749 25.464 ;
     RECT  81.317 30.336 81.749 31.08 ;
     RECT  80.963 70.656 81.749 70.68 ;
     RECT  80.777 93.36 81.749 93.384 ;
     RECT  80.993 82.56 81.781 83.064 ;
     RECT  81.425 32.832 81.785 32.856 ;
     RECT  80.917 52.992 81.827 53.016 ;
     RECT  81.781 82.56 81.827 83.688 ;
     RECT  81.749 30.336 81.857 30.36 ;
     RECT  80.963 49.776 81.857 49.8 ;
     RECT  81.781 54.144 81.865 54.168 ;
     RECT  79.516 63.216 81.893 64.728 ;
     RECT  81.827 83.04 81.923 83.688 ;
     RECT  81.677 87.504 81.923 87.816 ;
     RECT  81.245 126.96 81.964 126.984 ;
     RECT  78.304 1.728 81.965 1.752 ;
     RECT  80.777 125.424 82.021 125.448 ;
     RECT  81.34 4.272 82.037 4.968 ;
     RECT  80.051 59.52 82.037 59.544 ;
     RECT  79.475 67.152 82.037 67.56 ;
     RECT  82.021 124.8 82.067 125.448 ;
     RECT  81.425 33.984 82.109 34.008 ;
     RECT  81.893 63.216 82.109 64.152 ;
     RECT  82.069 96.864 82.153 96.888 ;
     RECT  82.109 63.264 82.181 64.152 ;
     RECT  81.749 25.44 82.253 25.464 ;
     RECT  82.037 4.944 82.289 4.968 ;
     RECT  81.533 77.664 82.289 78.072 ;
     RECT  80.669 102 82.309 102.024 ;
     RECT  81.533 28.176 82.325 28.2 ;
     RECT  80.812 98.064 82.355 98.088 ;
     RECT  82.309 101.808 82.396 102.072 ;
     RECT  82.037 67.152 82.397 67.176 ;
     RECT  81.923 87.792 82.397 87.816 ;
     RECT  81.533 26.496 82.433 26.52 ;
     RECT  81.641 43.248 82.789 43.272 ;
     RECT  82.105 107.76 83.029 107.784 ;
     RECT  82.748 30.48 83.408 30.504 ;
     RECT  82.789 42.768 83.408 43.272 ;
     RECT  80.633 61.728 83.408 61.752 ;
     RECT  82.181 63.264 83.408 63.288 ;
     RECT  82.289 77.664 83.408 77.688 ;
     RECT  81.923 83.04 83.408 83.064 ;
     RECT  82.396 101.808 83.408 101.832 ;
     RECT  80.669 103.152 83.408 103.176 ;
     RECT  83.029 107.136 83.408 107.784 ;
     RECT  80.957 116.304 83.408 116.328 ;
     RECT  81.997 119.616 83.408 119.64 ;
     RECT  81.173 120.768 83.408 120.792 ;
     RECT  82.067 124.8 83.408 124.824 ;
     RECT  83.408 2.148 83.512 127.452 ;
     RECT  83.512 2.418 83.704 127.182 ;
    LAYER M5 ;
     RECT  4.488 0.144 4.752 0.192 ;
     RECT  4.776 0.144 5.04 0.192 ;
     RECT  5.064 0.144 5.472 0.192 ;
     RECT  5.496 0.144 6.288 0.192 ;
     RECT  6.312 0.144 6.576 0.192 ;
     RECT  6.6 0.144 6.864 0.192 ;
     RECT  6.888 0.144 7.296 0.192 ;
     RECT  7.32 0.144 7.584 0.192 ;
     RECT  7.608 0.144 7.872 0.192 ;
     RECT  7.896 0.144 8.304 0.192 ;
     RECT  8.328 0.144 8.592 0.192 ;
     RECT  8.616 0.144 8.88 0.192 ;
     RECT  8.904 0.144 9.312 0.192 ;
     RECT  9.336 0.144 9.6 0.192 ;
     RECT  9.624 0.144 9.888 0.192 ;
     RECT  9.912 0.144 10.176 0.192 ;
     RECT  10.2 0.144 10.608 0.192 ;
     RECT  10.632 0.144 10.896 0.192 ;
     RECT  10.92 0.144 11.712 0.192 ;
     RECT  11.736 0.144 12.144 0.192 ;
     RECT  12.168 0.144 12.432 0.192 ;
     RECT  12.456 0.144 12.72 0.192 ;
     RECT  12.744 0.144 13.152 0.192 ;
     RECT  13.176 0.144 13.44 0.192 ;
     RECT  13.464 0.144 13.728 0.192 ;
     RECT  13.752 0.144 14.16 0.192 ;
     RECT  14.184 0.144 14.448 0.192 ;
     RECT  14.472 0.144 14.736 0.192 ;
     RECT  14.76 0.144 15.024 0.192 ;
     RECT  15.048 0.144 15.456 0.192 ;
     RECT  15.48 0.144 15.744 0.192 ;
     RECT  15.768 0.144 16.032 0.192 ;
     RECT  16.056 0.144 16.944 0.192 ;
     RECT  16.968 0.144 17.232 0.192 ;
     RECT  17.256 0.144 17.52 0.192 ;
     RECT  17.544 0.144 17.952 0.192 ;
     RECT  17.976 0.144 18.24 0.192 ;
     RECT  18.264 0.144 18.528 0.192 ;
     RECT  18.552 0.144 18.816 0.192 ;
     RECT  18.84 0.144 19.248 0.192 ;
     RECT  19.272 0.144 19.536 0.192 ;
     RECT  19.56 0.144 19.824 0.192 ;
     RECT  19.848 0.144 20.256 0.192 ;
     RECT  20.28 0.144 20.544 0.192 ;
     RECT  20.568 0.144 20.832 0.192 ;
     RECT  20.856 0.144 21.264 0.192 ;
     RECT  21.288 0.144 21.552 0.192 ;
     RECT  21.576 0.144 22.368 0.192 ;
     RECT  22.392 0.144 22.656 0.192 ;
     RECT  22.68 0.144 23.088 0.192 ;
     RECT  23.112 0.144 23.376 0.192 ;
     RECT  23.4 0.144 23.664 0.192 ;
     RECT  23.688 0.144 24.096 0.192 ;
     RECT  24.12 0.144 24.384 0.192 ;
     RECT  24.408 0.144 24.672 0.192 ;
     RECT  24.696 0.144 25.104 0.192 ;
     RECT  25.128 0.144 25.392 0.192 ;
     RECT  25.416 0.144 25.68 0.192 ;
     RECT  25.704 0.144 25.968 0.192 ;
     RECT  25.992 0.144 26.4 0.192 ;
     RECT  26.424 0.144 26.688 0.192 ;
     RECT  26.712 0.144 26.976 0.192 ;
     RECT  27 0.144 27.888 0.192 ;
     RECT  27.912 0.144 28.176 0.192 ;
     RECT  28.2 0.144 28.464 0.192 ;
     RECT  28.488 0.144 28.896 0.192 ;
     RECT  28.92 0.144 29.184 0.192 ;
     RECT  29.208 0.144 29.472 0.192 ;
     RECT  29.496 0.144 29.76 0.192 ;
     RECT  29.784 0.144 30.192 0.192 ;
     RECT  30.216 0.144 30.48 0.192 ;
     RECT  30.504 0.144 30.768 0.192 ;
     RECT  30.792 0.144 31.2 0.192 ;
     RECT  31.224 0.144 31.488 0.192 ;
     RECT  31.512 0.144 31.776 0.192 ;
     RECT  31.8 0.144 32.208 0.192 ;
     RECT  32.232 0.144 32.496 0.192 ;
     RECT  32.52 0.144 33.312 0.192 ;
     RECT  33.336 0.144 33.744 0.192 ;
     RECT  33.768 0.144 34.032 0.192 ;
     RECT  34.056 0.144 34.32 0.192 ;
     RECT  34.344 0.144 34.608 0.192 ;
     RECT  34.632 0.144 35.04 0.192 ;
     RECT  35.064 0.144 35.328 0.192 ;
     RECT  35.352 0.144 35.616 0.192 ;
     RECT  35.64 0.144 36.048 0.192 ;
     RECT  36.072 0.144 36.336 0.192 ;
     RECT  36.36 0.144 36.624 0.192 ;
     RECT  36.648 0.144 37.056 0.192 ;
     RECT  37.08 0.144 37.344 0.192 ;
     RECT  37.368 0.144 37.632 0.192 ;
     RECT  37.656 0.144 37.92 0.192 ;
     RECT  37.944 0.144 38.832 0.192 ;
     RECT  38.856 0.144 39.12 0.192 ;
     RECT  39.144 0.144 39.408 0.192 ;
     RECT  39.432 0.144 39.84 0.192 ;
     RECT  39.864 0.144 40.128 0.192 ;
     RECT  40.152 0.144 40.416 0.192 ;
     RECT  40.44 0.144 40.848 0.192 ;
     RECT  40.872 0.144 41.136 0.192 ;
     RECT  41.16 0.144 41.424 0.192 ;
     RECT  41.448 0.144 41.712 0.192 ;
     RECT  41.736 0.144 42.144 0.192 ;
     RECT  42.168 0.144 42.432 0.192 ;
     RECT  42.456 0.144 42.72 0.192 ;
     RECT  42.744 0.144 43.152 0.192 ;
     RECT  43.176 0.144 43.968 0.192 ;
     RECT  43.992 0.144 44.256 0.192 ;
     RECT  44.28 0.144 44.688 0.192 ;
     RECT  44.712 0.144 44.976 0.192 ;
     RECT  45 0.144 45.264 0.192 ;
     RECT  45.288 0.144 45.552 0.192 ;
     RECT  45.576 0.144 45.984 0.192 ;
     RECT  46.008 0.144 46.272 0.192 ;
     RECT  46.296 0.144 46.56 0.192 ;
     RECT  46.584 0.144 46.992 0.192 ;
     RECT  47.016 0.144 47.28 0.192 ;
     RECT  47.304 0.144 47.568 0.192 ;
     RECT  47.592 0.144 48 0.192 ;
     RECT  48.024 0.144 48.288 0.192 ;
     RECT  48.312 0.144 48.576 0.192 ;
     RECT  48.6 0.144 49.344 0.192 ;
     RECT  49.368 0.144 49.776 0.192 ;
     RECT  49.8 0.144 50.064 0.192 ;
     RECT  50.088 0.144 50.352 0.192 ;
     RECT  50.376 0.144 50.784 0.192 ;
     RECT  50.808 0.144 51.072 0.192 ;
     RECT  51.096 0.144 51.36 0.192 ;
     RECT  51.384 0.144 51.792 0.192 ;
     RECT  51.816 0.144 52.08 0.192 ;
     RECT  52.104 0.144 52.368 0.192 ;
     RECT  52.392 0.144 52.8 0.192 ;
     RECT  52.824 0.144 53.088 0.192 ;
     RECT  53.112 0.144 53.376 0.192 ;
     RECT  53.4 0.144 53.664 0.192 ;
     RECT  53.688 0.144 54.096 0.192 ;
     RECT  54.12 0.144 54.912 0.192 ;
     RECT  54.936 0.144 55.2 0.192 ;
     RECT  55.224 0.144 55.632 0.192 ;
     RECT  55.656 0.144 55.92 0.192 ;
     RECT  55.944 0.144 56.208 0.192 ;
     RECT  56.232 0.144 56.64 0.192 ;
     RECT  56.664 0.144 56.928 0.192 ;
     RECT  56.952 0.144 57.216 0.192 ;
     RECT  57.24 0.144 57.504 0.192 ;
     RECT  57.528 0.144 57.936 0.192 ;
     RECT  57.96 0.144 58.224 0.192 ;
     RECT  58.248 0.144 58.512 0.192 ;
     RECT  58.536 0.144 58.944 0.192 ;
     RECT  58.968 0.144 59.232 0.192 ;
     RECT  59.256 0.144 59.52 0.192 ;
     RECT  59.544 0.144 60.432 0.192 ;
     RECT  60.456 0.144 60.72 0.192 ;
     RECT  60.744 0.144 61.008 0.192 ;
     RECT  61.032 0.144 61.296 0.192 ;
     RECT  61.32 0.144 61.728 0.192 ;
     RECT  61.752 0.144 62.016 0.192 ;
     RECT  62.04 0.144 62.304 0.192 ;
     RECT  62.328 0.144 62.736 0.192 ;
     RECT  62.76 0.144 63.024 0.192 ;
     RECT  63.048 0.144 63.312 0.192 ;
     RECT  63.336 0.144 63.744 0.192 ;
     RECT  63.768 0.144 64.032 0.192 ;
     RECT  64.056 0.144 64.32 0.192 ;
     RECT  64.344 0.144 64.608 0.192 ;
     RECT  64.632 0.144 65.568 0.192 ;
     RECT  65.592 0.144 65.856 0.192 ;
     RECT  65.88 0.144 66.144 0.192 ;
     RECT  66.168 0.144 66.576 0.192 ;
     RECT  66.6 0.144 66.864 0.192 ;
     RECT  66.888 0.144 67.152 0.192 ;
     RECT  67.176 0.144 67.584 0.192 ;
     RECT  67.608 0.144 67.872 0.192 ;
     RECT  67.896 0.144 68.16 0.192 ;
     RECT  68.184 0.144 68.448 0.192 ;
     RECT  68.472 0.144 68.88 0.192 ;
     RECT  68.904 0.144 69.168 0.192 ;
     RECT  69.192 0.144 69.456 0.192 ;
     RECT  69.48 0.144 69.888 0.192 ;
     RECT  69.912 0.144 70.176 0.192 ;
     RECT  70.2 0.144 70.944 0.192 ;
     RECT  70.968 0.144 71.376 0.192 ;
     RECT  71.4 0.144 71.664 0.192 ;
     RECT  71.688 0.144 71.952 0.192 ;
     RECT  71.976 0.144 72.384 0.192 ;
     RECT  72.408 0.144 72.672 0.192 ;
     RECT  72.696 0.144 72.96 0.192 ;
     RECT  72.984 0.144 73.248 0.192 ;
     RECT  73.272 0.144 73.68 0.192 ;
     RECT  73.704 0.144 73.968 0.192 ;
     RECT  73.992 0.144 74.256 0.192 ;
     RECT  74.28 0.144 74.688 0.192 ;
     RECT  74.712 0.144 74.976 0.192 ;
     RECT  75 0.144 75.264 0.192 ;
     RECT  75.288 0.144 75.696 0.192 ;
     RECT  75.72 0.144 76.512 0.192 ;
     RECT  76.536 0.144 76.8 0.192 ;
     RECT  76.824 0.144 77.088 0.192 ;
     RECT  77.112 0.144 77.52 0.192 ;
     RECT  77.544 0.144 77.808 0.192 ;
     RECT  77.832 0.144 78.096 0.192 ;
     RECT  78.12 0.144 78.528 0.192 ;
     RECT  78.552 0.144 78.816 0.192 ;
     RECT  78.84 0.144 79.104 0.192 ;
     RECT  79.128 0.144 79.536 0.192 ;
     RECT  79.56 0.144 79.824 0.192 ;
     RECT  79.848 0.144 80.112 0.192 ;
     RECT  80.136 0.144 80.4 0.192 ;
     RECT  80.424 0.144 80.832 0.192 ;
     RECT  80.856 0.144 81.12 0.192 ;
     RECT  81.144 0.144 81.888 0.192 ;
     RECT  4.464 0.192 81.912 0.611 ;
     RECT  4.464 0.611 5.496 1.763 ;
     RECT  6.576 0.611 23.112 1.763 ;
     RECT  24.384 0.611 37.944 1.763 ;
     RECT  39.12 0.611 43.176 1.763 ;
     RECT  44.256 0.611 64.632 1.763 ;
     RECT  66.144 0.611 75.72 1.763 ;
     RECT  76.8 0.611 81.912 1.763 ;
     RECT  42.432 1.763 43.176 1.811 ;
     RECT  44.544 1.763 54.12 1.811 ;
     RECT  67.2 1.763 68.904 1.811 ;
     RECT  22.608 1.763 23.112 2.053 ;
     RECT  24.384 1.763 26.712 2.053 ;
     RECT  2.4 2.137 2.52 2.151 ;
     RECT  83.4 2.137 83.52 2.151 ;
     RECT  6.672 1.763 13.704 2.291 ;
     RECT  68.88 1.811 68.904 2.291 ;
     RECT  73.968 1.763 73.992 2.291 ;
     RECT  17.232 1.763 21.576 2.339 ;
     RECT  22.608 2.053 26.712 2.339 ;
     RECT  28.464 1.763 32.232 2.339 ;
     RECT  39.84 1.763 41.448 2.339 ;
     RECT  48.432 1.811 54.12 2.339 ;
     RECT  26.688 2.339 26.712 2.387 ;
     RECT  12.672 2.291 13.704 2.773 ;
     RECT  15.456 1.763 15.48 2.773 ;
     RECT  36.144 1.763 37.08 2.773 ;
     RECT  39.84 2.339 41.256 2.773 ;
     RECT  5.616 2.629 5.64 2.821 ;
     RECT  6.672 2.291 11.064 2.821 ;
     RECT  26.736 2.725 26.952 2.821 ;
     RECT  28.464 2.339 30.216 2.821 ;
     RECT  39.456 2.773 41.256 2.821 ;
     RECT  44.544 1.811 47.016 2.821 ;
     RECT  48.432 2.339 49.56 2.821 ;
     RECT  61.632 1.763 62.112 2.821 ;
     RECT  63.312 1.763 63.336 2.821 ;
     RECT  5.616 2.821 11.064 2.915 ;
     RECT  22.608 2.339 25.656 2.915 ;
     RECT  48.384 2.821 49.56 2.963 ;
     RECT  63.312 2.821 63.816 3.157 ;
     RECT  12.672 2.773 15.48 3.205 ;
     RECT  33.84 1.763 35.112 3.205 ;
     RECT  36.144 2.773 37.416 3.205 ;
     RECT  42.432 1.811 42.456 3.205 ;
     RECT  43.824 2.821 47.016 3.205 ;
     RECT  63.168 3.157 63.816 3.205 ;
     RECT  38.928 2.821 41.256 3.347 ;
     RECT  12.672 3.205 15.864 3.349 ;
     RECT  78 1.763 78.312 3.349 ;
     RECT  33.84 3.205 37.416 3.397 ;
     RECT  39.456 3.347 41.256 3.397 ;
     RECT  42.432 3.205 47.016 3.397 ;
     RECT  50.64 2.339 54.12 3.397 ;
     RECT  55.92 1.763 59.256 3.397 ;
     RECT  26.736 2.821 30.216 3.443 ;
     RECT  33.84 3.397 37.704 3.443 ;
     RECT  26.736 3.443 27.624 3.541 ;
     RECT  31.296 2.339 32.232 3.685 ;
     RECT  12.672 3.349 16.296 3.733 ;
     RECT  17.52 2.339 21.576 3.733 ;
     RECT  48.432 2.963 49.56 3.733 ;
     RECT  50.592 3.397 54.12 3.733 ;
     RECT  72.6 1.763 72.912 3.733 ;
     RECT  10.224 2.915 11.064 3.829 ;
     RECT  12.672 3.733 21.576 3.829 ;
     RECT  22.608 2.915 24.744 3.829 ;
     RECT  60.96 2.821 62.112 3.829 ;
     RECT  31.296 3.685 32.424 3.877 ;
     RECT  4.08 3.877 4.104 3.925 ;
     RECT  63.168 3.205 63.864 3.925 ;
     RECT  80.496 2.773 80.52 3.925 ;
     RECT  80.496 3.925 81.288 3.971 ;
     RECT  33.84 3.443 35.256 4.019 ;
     RECT  39.456 3.397 47.016 4.019 ;
     RECT  48.432 3.733 54.12 4.019 ;
     RECT  10.224 3.829 24.744 4.067 ;
     RECT  49.248 4.019 54.12 4.067 ;
     RECT  5.616 2.915 9.096 4.117 ;
     RECT  10.224 4.067 13.896 4.117 ;
     RECT  5.616 4.117 13.896 4.163 ;
     RECT  15.168 4.067 24.744 4.261 ;
     RECT  3.984 3.925 4.104 4.309 ;
     RECT  39.984 4.019 47.016 4.405 ;
     RECT  3.936 4.309 4.104 4.501 ;
     RECT  26.208 3.541 27.624 4.595 ;
     RECT  33.888 4.019 35.256 4.595 ;
     RECT  49.488 4.067 54.12 4.595 ;
     RECT  55.824 3.397 59.256 4.595 ;
     RECT  63.168 3.925 63.912 4.595 ;
     RECT  6.384 4.163 13.896 4.691 ;
     RECT  60.336 3.829 62.112 4.789 ;
     RECT  30.72 3.877 32.424 4.837 ;
     RECT  29.088 3.443 29.712 4.885 ;
     RECT  30.72 4.837 32.856 4.885 ;
     RECT  15.168 4.261 25.032 4.981 ;
     RECT  34.176 4.595 35.256 5.077 ;
     RECT  72.6 3.733 73.272 5.077 ;
     RECT  15.168 4.981 25.08 5.171 ;
     RECT  29.088 4.885 32.856 5.171 ;
     RECT  49.488 4.595 54.072 5.171 ;
     RECT  60.192 4.789 62.112 5.171 ;
     RECT  77.04 3.349 78.312 5.171 ;
     RECT  6.624 4.691 13.896 5.173 ;
     RECT  15.168 5.171 25.032 5.173 ;
     RECT  55.824 4.595 59.16 5.173 ;
     RECT  29.232 5.171 32.856 5.219 ;
     RECT  39.984 4.405 47.4 5.219 ;
     RECT  6.624 5.173 25.032 5.267 ;
     RECT  3.936 4.501 4.632 5.365 ;
     RECT  75.84 5.077 75.864 5.413 ;
     RECT  76.896 5.365 76.92 5.413 ;
     RECT  2.4 2.151 2.712 5.509 ;
     RECT  39.984 5.219 42.936 5.557 ;
     RECT  2.4 5.509 2.856 5.605 ;
     RECT  71.712 5.077 73.272 5.605 ;
     RECT  6.624 5.267 8.616 5.747 ;
     RECT  29.28 5.219 32.856 5.747 ;
     RECT  49.488 5.171 53.592 5.747 ;
     RECT  55.632 5.173 59.16 5.747 ;
     RECT  60.336 5.171 62.112 5.747 ;
     RECT  63.216 4.595 63.912 5.747 ;
     RECT  74.544 3.733 74.568 5.747 ;
     RECT  9.6 5.267 24.792 5.795 ;
     RECT  34.176 5.077 35.304 5.795 ;
     RECT  39.936 5.557 42.936 5.795 ;
     RECT  17.52 5.795 24.792 5.843 ;
     RECT  67.2 1.811 67.512 5.989 ;
     RECT  2.4 5.605 2.904 6.133 ;
     RECT  3.936 5.365 4.824 6.133 ;
     RECT  39.936 5.795 42.12 6.133 ;
     RECT  44.256 5.219 47.4 6.229 ;
     RECT  34.224 5.795 35.304 6.277 ;
     RECT  36.336 3.443 37.704 6.277 ;
     RECT  9.6 5.795 16.104 6.323 ;
     RECT  29.28 5.747 32.424 6.323 ;
     RECT  39.744 6.133 42.12 6.323 ;
     RECT  53.568 5.747 53.592 6.323 ;
     RECT  75.84 5.413 76.92 6.323 ;
     RECT  63.312 5.747 63.864 6.371 ;
     RECT  17.52 5.843 22.008 6.419 ;
     RECT  23.184 5.843 24.792 6.611 ;
     RECT  24 6.611 24.792 6.805 ;
     RECT  26.4 4.595 27.624 6.805 ;
     RECT  34.224 6.277 37.704 6.805 ;
     RECT  50.4 5.747 51.312 6.805 ;
     RECT  71.712 5.605 73.512 6.805 ;
     RECT  10.224 6.323 16.104 6.851 ;
     RECT  75.84 6.323 76.728 6.851 ;
     RECT  44.256 6.229 47.928 6.853 ;
     RECT  71.712 6.805 73.896 6.853 ;
     RECT  6.624 5.747 8.568 6.899 ;
     RECT  10.224 6.851 14.808 6.899 ;
     RECT  17.904 6.419 22.008 6.899 ;
     RECT  26.4 6.805 27.912 6.899 ;
     RECT  44.256 6.853 48.024 6.899 ;
     RECT  57.84 5.747 59.16 6.899 ;
     RECT  64.512 6.805 64.536 6.901 ;
     RECT  26.64 6.899 27.912 6.947 ;
     RECT  67.056 5.989 67.512 6.997 ;
     RECT  27.888 6.947 27.912 7.043 ;
     RECT  61.2 5.747 62.112 7.141 ;
     RECT  15.792 6.851 16.104 7.189 ;
     RECT  10.224 6.899 14.616 7.331 ;
     RECT  50.4 6.805 51.528 7.381 ;
     RECT  24 6.805 24.888 7.427 ;
     RECT  45.6 6.899 48.024 7.475 ;
     RECT  10.224 7.331 10.824 7.571 ;
     RECT  66.24 6.997 67.512 7.715 ;
     RECT  17.904 6.899 21.24 7.957 ;
     RECT  78 5.171 78.312 7.957 ;
     RECT  54.144 7.093 54.168 8.003 ;
     RECT  6.624 6.899 6.648 8.051 ;
     RECT  64.512 6.901 64.968 8.197 ;
     RECT  71.568 6.853 73.896 8.243 ;
     RECT  33.408 6.805 37.704 8.437 ;
     RECT  67.104 7.715 67.512 8.485 ;
     RECT  71.712 8.243 73.896 8.485 ;
     RECT  15.792 7.189 16.632 8.533 ;
     RECT  17.904 7.957 21.288 8.533 ;
     RECT  29.4 6.323 32.424 8.533 ;
     RECT  33.408 8.437 38.28 8.533 ;
     RECT  39.744 6.323 41.784 8.579 ;
     RECT  0.288 8.485 0.312 8.629 ;
     RECT  57.84 6.899 57.864 8.677 ;
     RECT  64.512 8.197 65.208 8.821 ;
     RECT  2.4 6.133 4.824 8.869 ;
     RECT  28.176 7.333 28.2 8.869 ;
     RECT  29.4 8.533 38.28 8.869 ;
     RECT  22.8 8.389 22.824 8.915 ;
     RECT  10.704 8.869 10.728 8.917 ;
     RECT  12.096 7.331 14.616 8.917 ;
     RECT  77.904 7.957 78.312 9.011 ;
     RECT  79.824 8.533 79.848 9.059 ;
     RECT  0.288 8.629 0.36 9.061 ;
     RECT  7.68 6.899 8.568 9.061 ;
     RECT  9.6 8.917 9.624 9.061 ;
     RECT  10.704 8.917 14.616 9.061 ;
     RECT  45.6 7.475 46.824 9.061 ;
     RECT  48 7.475 48.024 9.061 ;
     RECT  57.84 8.677 57.912 9.061 ;
     RECT  2.4 8.869 5.064 9.107 ;
     RECT  50.4 7.381 51.576 9.109 ;
     RECT  15.792 8.533 21.288 9.157 ;
     RECT  45.6 9.061 48.024 9.157 ;
     RECT  67.104 8.485 68.424 9.203 ;
     RECT  55.632 5.747 56.712 9.253 ;
     RECT  15.696 9.157 21.288 9.349 ;
     RECT  71.712 8.485 74.52 9.395 ;
     RECT  2.4 9.107 4.824 9.539 ;
     RECT  15.696 9.349 21.336 9.635 ;
     RECT  24 7.427 24.792 9.637 ;
     RECT  25.92 9.589 25.944 9.637 ;
     RECT  49.152 8.485 49.176 9.637 ;
     RECT  50.4 9.109 51.624 9.637 ;
     RECT  61.2 7.141 62.952 9.637 ;
     RECT  53.136 9.109 53.16 9.685 ;
     RECT  45.6 9.157 48.168 9.877 ;
     RECT  49.152 9.637 51.624 9.877 ;
     RECT  0.288 9.061 0.408 9.925 ;
     RECT  57.84 9.061 58.488 9.925 ;
     RECT  24 9.637 25.944 9.973 ;
     RECT  28.176 8.869 38.28 9.973 ;
     RECT  27.84 9.973 38.28 10.115 ;
     RECT  9.6 9.061 14.616 10.165 ;
     RECT  15.696 9.635 21.288 10.165 ;
     RECT  53.088 9.685 53.16 10.213 ;
     RECT  55.488 9.253 56.712 10.213 ;
     RECT  57.84 9.925 59.16 10.213 ;
     RECT  78 9.011 78.312 10.213 ;
     RECT  55.488 10.213 59.16 10.259 ;
     RECT  4.128 9.539 4.824 10.307 ;
     RECT  45.6 9.877 51.624 10.307 ;
     RECT  81.264 3.971 81.288 10.307 ;
     RECT  0.192 9.925 0.408 10.355 ;
     RECT  28.176 10.115 38.28 10.357 ;
     RECT  61.008 9.637 62.952 10.357 ;
     RECT  64.512 8.821 65.688 10.357 ;
     RECT  0.192 10.355 0.312 10.499 ;
     RECT  53.04 10.213 53.16 10.549 ;
     RECT  43.104 10.021 43.128 10.597 ;
     RECT  44.256 6.899 44.28 10.597 ;
     RECT  48.048 10.307 51.624 10.597 ;
     RECT  2.4 9.539 3.096 10.693 ;
     RECT  53.04 10.549 53.496 10.739 ;
     RECT  53.04 10.739 53.16 10.787 ;
     RECT  6.096 9.061 8.568 10.789 ;
     RECT  67.104 9.203 67.512 10.789 ;
     RECT  48.048 10.597 51.72 10.837 ;
     RECT  61.008 10.357 65.688 10.837 ;
     RECT  67.104 10.789 68.28 10.837 ;
     RECT  0.288 10.499 0.312 10.883 ;
     RECT  61.008 10.837 68.28 10.883 ;
     RECT  39.792 8.579 41.784 10.885 ;
     RECT  43.104 10.597 44.28 10.885 ;
     RECT  61.296 10.883 68.28 10.981 ;
     RECT  28.176 10.357 38.808 11.077 ;
     RECT  45.6 10.307 46.824 11.125 ;
     RECT  39.792 10.885 44.28 11.171 ;
     RECT  48.048 10.837 51.816 11.171 ;
     RECT  2.304 10.693 3.096 11.221 ;
     RECT  9.6 10.165 21.288 11.267 ;
     RECT  23.616 9.973 25.944 11.317 ;
     RECT  27.456 11.077 38.808 11.317 ;
     RECT  23.616 11.317 38.808 11.365 ;
     RECT  39.792 11.171 42.216 11.365 ;
     RECT  70.464 10.213 70.488 11.365 ;
     RECT  75.84 6.851 75.864 11.365 ;
     RECT  5.808 10.789 8.568 11.411 ;
     RECT  23.616 11.365 42.216 11.411 ;
     RECT  71.712 9.395 74.088 11.411 ;
     RECT  75.84 11.365 76.152 11.411 ;
     RECT  45.264 11.125 46.824 11.413 ;
     RECT  48.048 11.171 51.72 11.413 ;
     RECT  5.808 11.411 6.12 11.459 ;
     RECT  78 10.213 78.648 11.509 ;
     RECT  23.616 11.411 24.792 11.605 ;
     RECT  7.152 11.411 8.568 11.941 ;
     RECT  10.128 11.267 21.288 11.941 ;
     RECT  23.04 11.605 24.792 11.941 ;
     RECT  53.088 10.787 53.16 11.941 ;
     RECT  43.344 11.171 44.28 11.989 ;
     RECT  45.264 11.413 51.72 11.989 ;
     RECT  53.088 11.941 54.072 12.037 ;
     RECT  61.296 10.981 68.568 12.037 ;
     RECT  61.296 12.037 68.808 12.133 ;
     RECT  69.984 11.365 70.488 12.133 ;
     RECT  43.344 11.989 51.72 12.181 ;
     RECT  53.04 12.037 54.072 12.181 ;
     RECT  2.304 11.221 3.816 12.227 ;
     RECT  78 11.509 78.792 12.227 ;
     RECT  55.488 10.259 58.584 12.421 ;
     RECT  59.712 11.461 59.736 12.421 ;
     RECT  25.92 11.411 42.216 12.517 ;
     RECT  43.344 12.181 54.072 12.517 ;
     RECT  25.92 12.517 54.456 12.709 ;
     RECT  76.128 11.411 76.152 12.757 ;
     RECT  7.152 11.941 9.096 12.853 ;
     RECT  10.128 11.941 24.792 12.853 ;
     RECT  25.776 12.709 54.456 12.853 ;
     RECT  2.4 12.227 3.816 12.901 ;
     RECT  4.8 10.307 4.824 12.901 ;
     RECT  2.4 12.901 4.824 12.997 ;
     RECT  5.808 11.459 6.024 12.997 ;
     RECT  61.296 12.133 70.488 12.997 ;
     RECT  55.488 12.421 59.736 13.045 ;
     RECT  60.864 12.997 70.488 13.045 ;
     RECT  78 12.227 78.696 13.571 ;
     RECT  55.488 13.045 70.488 13.715 ;
     RECT  7.152 12.853 54.456 13.859 ;
     RECT  55.632 13.715 70.488 14.197 ;
     RECT  71.712 11.411 73.896 14.197 ;
     RECT  2.4 12.997 6.024 14.291 ;
     RECT  81.456 11.269 81.48 14.915 ;
     RECT  2.4 14.291 4.824 15.349 ;
     RECT  5.808 14.291 6.024 15.349 ;
     RECT  0.288 13.957 0.312 15.491 ;
     RECT  55.632 14.197 73.896 15.779 ;
     RECT  2.4 15.349 6.024 16.019 ;
     RECT  75.84 12.757 76.152 16.835 ;
     RECT  7.152 13.859 53.784 16.837 ;
     RECT  2.4 16.019 5.832 17.123 ;
     RECT  7.152 16.837 54.504 17.221 ;
     RECT  55.632 15.779 72.912 17.221 ;
     RECT  2.4 17.123 3.96 17.605 ;
     RECT  78 13.571 78.312 17.845 ;
     RECT  2.304 17.605 3.96 18.181 ;
     RECT  5.088 17.123 5.832 18.181 ;
     RECT  7.152 17.221 72.912 18.181 ;
     RECT  2.304 18.181 72.912 18.899 ;
     RECT  75.84 16.835 75.864 19.141 ;
     RECT  3.792 18.899 72.912 19.187 ;
     RECT  21.36 19.187 72.912 19.333 ;
     RECT  0.288 18.757 0.312 19.763 ;
     RECT  3.792 19.187 20.136 19.859 ;
     RECT  2.304 18.899 2.712 20.099 ;
     RECT  2.4 20.099 2.712 20.197 ;
     RECT  3.792 19.859 19.944 20.197 ;
     RECT  75.216 19.141 75.864 20.579 ;
     RECT  81.216 17.221 81.24 20.819 ;
     RECT  2.4 20.197 19.944 20.869 ;
     RECT  21.36 19.333 73.032 21.299 ;
     RECT  0.288 20.869 0.312 21.493 ;
     RECT  2.4 20.869 20.04 21.731 ;
     RECT  3.792 21.731 20.04 21.733 ;
     RECT  21.36 21.299 54.984 21.733 ;
     RECT  0.288 21.493 0.36 21.973 ;
     RECT  0.192 21.973 0.36 22.021 ;
     RECT  3.792 21.733 54.984 22.259 ;
     RECT  2.4 21.731 2.808 22.307 ;
     RECT  4.56 22.259 54.984 22.355 ;
     RECT  18.096 22.355 54.984 22.403 ;
     RECT  0.192 22.021 0.552 22.499 ;
     RECT  0.528 22.499 0.552 22.787 ;
     RECT  4.56 22.355 16.68 22.835 ;
     RECT  78 17.845 78.984 22.835 ;
     RECT  4.56 22.835 4.776 23.269 ;
     RECT  27.312 22.403 54.984 23.317 ;
     RECT  56.112 21.299 73.032 23.317 ;
     RECT  2.4 22.307 2.712 23.797 ;
     RECT  3.888 23.269 4.776 23.797 ;
     RECT  27.312 23.317 73.032 23.939 ;
     RECT  2.4 23.797 4.776 23.987 ;
     RECT  53.76 23.939 73.032 24.421 ;
     RECT  2.4 23.987 4.584 24.563 ;
     RECT  5.808 22.835 16.68 24.709 ;
     RECT  18.096 22.403 26.328 24.709 ;
     RECT  53.76 24.421 73.512 24.709 ;
     RECT  80.016 16.981 80.04 24.757 ;
     RECT  27.312 23.939 52.728 24.947 ;
     RECT  3.792 24.563 4.584 24.997 ;
     RECT  5.808 24.709 26.328 24.997 ;
     RECT  52.56 24.947 52.728 25.043 ;
     RECT  3.792 24.997 26.328 25.669 ;
     RECT  27.312 24.947 51.48 25.669 ;
     RECT  53.76 24.709 73.752 25.669 ;
     RECT  53.616 25.669 73.752 25.715 ;
     RECT  52.56 25.043 52.632 26.053 ;
     RECT  53.616 25.715 55.368 26.053 ;
     RECT  80.016 24.757 80.952 26.339 ;
     RECT  52.56 26.053 55.368 26.437 ;
     RECT  3.792 25.669 51.48 26.677 ;
     RECT  52.464 26.437 55.368 26.677 ;
     RECT  2.4 24.563 2.712 26.869 ;
     RECT  3.792 26.677 55.368 26.869 ;
     RECT  56.4 25.715 73.752 27.109 ;
     RECT  80.016 26.339 80.52 27.301 ;
     RECT  56.4 27.109 73.848 27.349 ;
     RECT  2.4 26.869 55.368 27.971 ;
     RECT  2.4 27.971 4.296 28.643 ;
     RECT  5.376 27.971 55.368 28.933 ;
     RECT  4.416 28.933 55.368 28.979 ;
     RECT  2.4 28.643 3.432 29.123 ;
     RECT  80.016 27.301 81.288 29.123 ;
     RECT  80.4 29.123 81.288 29.315 ;
     RECT  52.464 28.979 55.368 29.605 ;
     RECT  56.4 27.349 74.568 29.605 ;
     RECT  52.464 29.605 74.568 29.797 ;
     RECT  52.464 29.797 74.712 30.227 ;
     RECT  78 22.835 78.312 30.325 ;
     RECT  81.264 29.315 81.288 30.325 ;
     RECT  83.4 2.151 83.712 30.469 ;
     RECT  78 30.325 78.552 31.667 ;
     RECT  75.84 20.579 75.864 31.765 ;
     RECT  80.688 30.325 81.288 32.195 ;
     RECT  4.416 28.979 51.48 32.291 ;
     RECT  4.416 32.291 51.312 33.155 ;
     RECT  4.656 33.155 51.312 34.165 ;
     RECT  4.656 34.165 51.528 34.741 ;
     RECT  52.56 30.227 74.712 35.173 ;
     RECT  79.872 33.973 79.896 35.363 ;
     RECT  4.128 34.741 51.528 35.795 ;
     RECT  7.392 35.795 51.528 36.083 ;
     RECT  7.632 36.083 51.528 36.517 ;
     RECT  52.56 35.173 74.856 36.517 ;
     RECT  4.128 35.795 6.264 37.717 ;
     RECT  79.824 35.557 79.848 38.195 ;
     RECT  7.632 36.517 74.856 38.725 ;
     RECT  75.84 31.765 76.392 38.725 ;
     RECT  81.264 32.195 81.288 38.725 ;
     RECT  7.632 38.725 76.392 38.773 ;
     RECT  3.984 37.717 6.264 39.301 ;
     RECT  7.488 38.773 76.392 39.301 ;
     RECT  80.352 38.725 81.288 39.301 ;
     RECT  80.352 39.301 81.528 39.349 ;
     RECT  80.016 39.349 81.528 39.395 ;
     RECT  82.8 30.469 83.712 42.803 ;
     RECT  3.984 39.301 76.392 43.285 ;
     RECT  81.264 39.395 81.528 43.379 ;
     RECT  80.016 39.395 80.04 44.965 ;
     RECT  3.936 43.285 76.392 45.253 ;
     RECT  2.4 29.123 2.712 45.541 ;
     RECT  3.936 45.253 76.968 45.541 ;
     RECT  80.016 44.965 80.28 47.269 ;
     RECT  81.264 43.379 81.288 47.269 ;
     RECT  2.4 45.541 76.968 47.363 ;
     RECT  3.936 47.363 76.968 47.987 ;
     RECT  0.24 47.701 0.264 48.421 ;
     RECT  0.192 48.421 0.264 48.707 ;
     RECT  0.24 48.707 0.264 48.851 ;
     RECT  2.4 47.363 2.856 49.525 ;
     RECT  3.984 47.987 76.968 49.525 ;
     RECT  0.288 48.997 0.312 50.389 ;
     RECT  2.4 49.525 76.968 50.677 ;
     RECT  78 31.667 78.312 50.677 ;
     RECT  0.192 50.389 0.312 51.347 ;
     RECT  0.288 51.347 0.312 51.491 ;
     RECT  2.4 50.677 78.312 52.213 ;
     RECT  80.016 47.269 81.288 52.981 ;
     RECT  80.016 52.981 81.816 53.027 ;
     RECT  0.192 53.845 0.216 54.179 ;
     RECT  81.264 53.027 81.816 54.179 ;
     RECT  2.304 52.213 78.312 54.419 ;
     RECT  2.4 54.419 78.312 54.563 ;
     RECT  2.4 54.563 76.968 54.755 ;
     RECT  0.384 54.421 0.408 55.141 ;
     RECT  78 54.563 78.312 55.141 ;
     RECT  2.4 54.755 21.96 55.765 ;
     RECT  23.088 54.755 76.968 55.765 ;
     RECT  2.4 55.765 76.968 56.773 ;
     RECT  0.192 55.141 0.408 57.059 ;
     RECT  0.384 57.059 0.408 57.635 ;
     RECT  80.016 53.027 80.04 57.829 ;
     RECT  78 55.141 78.408 57.875 ;
     RECT  2.304 56.773 76.968 58.211 ;
     RECT  2.304 58.211 2.712 58.259 ;
     RECT  3.984 58.211 76.968 58.309 ;
     RECT  78 57.875 78.312 58.309 ;
     RECT  3.984 58.309 78.312 59.555 ;
     RECT  0.288 58.597 0.312 59.939 ;
     RECT  79.536 57.829 80.04 60.323 ;
     RECT  3.984 59.555 41.352 60.371 ;
     RECT  2.4 58.259 2.712 60.373 ;
     RECT  3.984 60.371 41.16 60.373 ;
     RECT  79.536 60.323 79.56 60.515 ;
     RECT  42.336 59.555 78.312 60.853 ;
     RECT  2.4 60.373 41.16 61.091 ;
     RECT  42.192 60.853 78.312 61.619 ;
     RECT  3.984 61.091 41.16 62.195 ;
     RECT  42.336 61.619 78.312 62.965 ;
     RECT  2.4 61.091 2.952 63.205 ;
     RECT  3.984 62.195 39.144 63.205 ;
     RECT  81.264 54.179 81.288 63.205 ;
     RECT  0.288 63.205 0.312 63.347 ;
     RECT  80.88 63.205 81.288 63.875 ;
     RECT  42.336 62.965 79.272 64.211 ;
     RECT  42.336 64.211 60.12 64.261 ;
     RECT  2.4 63.205 39.144 64.309 ;
     RECT  40.2 62.195 41.016 64.309 ;
     RECT  0.192 63.925 0.216 64.451 ;
     RECT  2.4 64.309 41.016 64.645 ;
     RECT  42.24 64.261 60.12 64.645 ;
     RECT  2.4 64.645 60.12 64.693 ;
     RECT  2.304 64.693 60.12 65.027 ;
     RECT  61.248 64.211 79.272 65.509 ;
     RECT  2.304 65.027 2.856 65.603 ;
     RECT  3.936 65.027 60.12 65.653 ;
     RECT  61.248 65.509 79.464 65.653 ;
     RECT  2.304 65.603 2.808 65.747 ;
     RECT  3.936 65.653 79.464 66.227 ;
     RECT  2.4 65.747 2.808 66.275 ;
     RECT  3.936 66.227 41.352 66.851 ;
     RECT  81.264 63.875 81.288 67.525 ;
     RECT  42.336 66.227 79.464 67.571 ;
     RECT  3.984 66.851 41.352 68.435 ;
     RECT  3.984 68.435 41.256 69.637 ;
     RECT  42.336 67.571 79.272 69.637 ;
     RECT  80.88 67.525 81.288 70.259 ;
     RECT  3.984 69.637 79.272 70.357 ;
     RECT  81.264 70.259 81.288 71.269 ;
     RECT  80.928 71.269 81.288 72.419 ;
     RECT  3.984 70.357 79.752 73.381 ;
     RECT  81.264 72.419 81.288 73.381 ;
     RECT  3.984 73.381 81.288 76.451 ;
     RECT  81.792 82.549 81.816 83.653 ;
     RECT  81.792 83.653 81.912 83.699 ;
     RECT  81.888 83.699 81.912 87.539 ;
     RECT  3.984 76.451 80.664 88.355 ;
     RECT  3.984 88.355 79.8 89.461 ;
     RECT  3.984 89.461 80.568 89.699 ;
     RECT  3.984 89.699 22.104 91.381 ;
     RECT  23.088 89.699 80.568 91.381 ;
     RECT  3.984 91.381 80.568 91.619 ;
     RECT  55.344 91.619 80.568 91.907 ;
     RECT  55.536 91.907 80.568 92.387 ;
     RECT  55.536 92.387 79.8 93.445 ;
     RECT  3.984 91.619 54.312 93.539 ;
     RECT  55.536 93.445 80.568 94.307 ;
     RECT  3.984 93.539 54.12 95.557 ;
     RECT  55.536 94.307 79.8 95.557 ;
     RECT  82.08 96.853 82.104 98.053 ;
     RECT  82.08 98.053 82.344 98.099 ;
     RECT  3.984 95.557 79.8 98.197 ;
     RECT  3.984 98.197 80.76 98.675 ;
     RECT  80.736 98.675 80.76 99.203 ;
     RECT  3.984 98.675 79.752 101.989 ;
     RECT  82.32 98.099 82.344 102.083 ;
     RECT  3.984 101.989 80.232 102.949 ;
     RECT  83.4 42.803 83.712 103.141 ;
     RECT  3.984 102.949 80.424 105.397 ;
     RECT  2.4 66.275 2.712 105.973 ;
     RECT  3.984 105.397 80.712 105.973 ;
     RECT  2.4 105.973 80.712 106.691 ;
     RECT  83.184 103.141 83.712 107.125 ;
     RECT  3.984 106.691 80.712 107.795 ;
     RECT  83.04 107.125 83.712 107.795 ;
     RECT  6.144 107.795 80.712 108.899 ;
     RECT  3.984 107.795 5.16 109.381 ;
     RECT  6.144 108.899 80.232 109.381 ;
     RECT  3.984 109.381 80.232 113.029 ;
     RECT  3.984 113.029 80.376 113.939 ;
     RECT  3.984 113.939 73.656 114.947 ;
     RECT  74.64 113.939 80.376 115.043 ;
     RECT  72.24 114.947 73.56 115.379 ;
     RECT  3.984 114.947 71.208 115.427 ;
     RECT  75.12 115.043 80.376 115.763 ;
     RECT  3.984 115.427 57.096 115.811 ;
     RECT  58.08 115.427 71.208 116.147 ;
     RECT  76.416 115.763 80.376 116.197 ;
     RECT  72.24 115.379 73.032 116.339 ;
     RECT  58.272 116.147 71.208 116.579 ;
     RECT  23.088 115.811 57.096 116.723 ;
     RECT  72.24 116.339 72.912 116.915 ;
     RECT  3.984 115.811 20.232 116.965 ;
     RECT  21.216 115.811 22.056 116.965 ;
     RECT  23.088 116.723 54.456 117.059 ;
     RECT  58.272 116.579 70.008 117.299 ;
     RECT  76.416 116.197 80.616 117.443 ;
     RECT  55.728 116.723 57.096 117.637 ;
     RECT  58.272 117.299 63.576 117.637 ;
     RECT  55.728 117.637 63.576 117.731 ;
     RECT  3.984 116.965 22.056 117.733 ;
     RECT  23.088 117.059 26.424 117.733 ;
     RECT  3.984 117.733 26.424 117.923 ;
     RECT  23.088 117.923 26.424 118.019 ;
     RECT  75.12 115.763 75.144 118.069 ;
     RECT  55.728 117.731 62.424 118.115 ;
     RECT  72.336 116.915 72.912 118.309 ;
     RECT  55.728 118.115 59.352 118.355 ;
     RECT  3.984 117.923 22.056 118.451 ;
     RECT  77.376 117.443 80.616 118.549 ;
     RECT  77.28 118.549 80.616 118.643 ;
     RECT  64.56 117.299 70.008 118.739 ;
     RECT  55.728 118.355 57.048 118.835 ;
     RECT  23.184 118.019 26.424 118.837 ;
     RECT  27.504 117.059 54.456 118.837 ;
     RECT  77.28 118.643 80.232 118.981 ;
     RECT  23.184 118.837 54.456 119.075 ;
     RECT  27.504 119.075 54.456 119.077 ;
     RECT  55.728 118.835 56.808 119.219 ;
     RECT  3.984 118.451 6.168 119.509 ;
     RECT  60.336 118.115 62.424 119.555 ;
     RECT  75.12 118.069 75.864 119.555 ;
     RECT  76.896 118.981 80.232 119.653 ;
     RECT  72.24 118.309 72.912 119.699 ;
     RECT  60.336 119.555 62.232 119.747 ;
     RECT  7.536 118.451 22.056 119.795 ;
     RECT  12.528 119.795 22.056 119.797 ;
     RECT  23.184 119.075 26.424 119.939 ;
     RECT  75.264 119.555 75.864 119.941 ;
     RECT  76.896 119.653 80.424 119.941 ;
     RECT  60.336 119.747 62.112 119.987 ;
     RECT  75.264 119.941 80.424 119.987 ;
     RECT  27.504 119.077 54.552 120.083 ;
     RECT  12.528 119.797 22.152 120.179 ;
     RECT  58.272 118.355 59.352 120.229 ;
     RECT  27.504 120.083 46.824 120.371 ;
     RECT  60.816 119.987 62.112 120.371 ;
     RECT  21.216 120.179 22.152 120.467 ;
     RECT  48.144 120.083 54.552 120.515 ;
     RECT  3.984 119.509 6.552 120.709 ;
     RECT  7.536 119.795 11.4 120.709 ;
     RECT  76.416 119.987 80.424 120.757 ;
     RECT  3.984 120.709 11.4 120.805 ;
     RECT  12.528 120.179 20.232 120.805 ;
     RECT  64.56 118.739 68.904 120.805 ;
     RECT  69.984 118.739 70.008 120.805 ;
     RECT  27.504 120.371 46.776 120.851 ;
     RECT  76.416 120.757 80.952 120.899 ;
     RECT  58.032 120.229 59.352 120.947 ;
     RECT  70.992 116.579 71.208 121.189 ;
     RECT  72.336 119.699 72.912 121.189 ;
     RECT  3.984 120.805 20.232 121.331 ;
     RECT  44.784 120.851 46.776 121.331 ;
     RECT  76.416 120.899 80.904 121.475 ;
     RECT  23.616 119.939 26.424 121.667 ;
     RECT  75.264 119.987 75.288 121.859 ;
     RECT  6.144 121.331 20.232 121.955 ;
     RECT  70.992 121.189 72.912 122.003 ;
     RECT  80.832 121.475 80.904 122.003 ;
     RECT  6.144 121.955 8.664 122.099 ;
     RECT  27.504 120.851 43.608 122.387 ;
     RECT  48.144 120.515 54.216 122.387 ;
     RECT  23.76 121.667 26.424 122.485 ;
     RECT  27.504 122.387 38.088 122.485 ;
     RECT  10.272 121.955 20.232 122.531 ;
     RECT  10.272 122.531 10.296 122.579 ;
     RECT  7.536 122.099 8.664 122.723 ;
     RECT  21.216 120.467 22.056 122.771 ;
     RECT  58.992 120.947 59.352 122.773 ;
     RECT  11.856 122.531 20.232 122.915 ;
     RECT  11.856 122.915 11.88 123.011 ;
     RECT  50.4 122.387 54.216 123.155 ;
     RECT  60.96 120.371 62.112 123.155 ;
     RECT  80.832 122.003 80.856 123.155 ;
     RECT  44.976 121.331 46.776 123.203 ;
     RECT  39.168 122.387 43.608 123.347 ;
     RECT  72.192 122.003 72.912 123.491 ;
     RECT  76.416 121.475 79.8 123.491 ;
     RECT  72.6 123.491 72.912 123.493 ;
     RECT  76.416 123.491 76.44 123.589 ;
     RECT  77.808 123.491 79.8 123.589 ;
     RECT  76.272 123.589 76.44 123.635 ;
     RECT  6.144 122.099 6.552 123.637 ;
     RECT  7.536 122.723 8.616 123.637 ;
     RECT  58.992 122.773 59.88 123.731 ;
     RECT  64.56 120.805 70.008 123.731 ;
     RECT  57.744 122.917 57.768 123.877 ;
     RECT  58.992 123.731 59.016 123.877 ;
     RECT  12.864 122.915 20.232 123.971 ;
     RECT  57.744 123.877 59.016 123.971 ;
     RECT  50.448 123.155 54.168 124.019 ;
     RECT  6.144 123.637 8.616 124.067 ;
     RECT  58.224 123.971 59.016 124.163 ;
     RECT  70.992 122.003 71.208 124.213 ;
     RECT  21.216 122.771 21.912 124.307 ;
     RECT  74.448 123.925 74.472 124.307 ;
     RECT  77.808 123.589 80.52 124.355 ;
     RECT  55.728 119.219 56.712 124.453 ;
     RECT  23.76 122.485 38.088 124.547 ;
     RECT  77.808 124.355 79.272 124.547 ;
     RECT  55.728 124.453 56.856 124.739 ;
     RECT  39.264 123.347 43.608 124.789 ;
     RECT  77.808 124.547 78.888 124.835 ;
     RECT  13.2 123.971 20.232 124.883 ;
     RECT  21.216 124.307 21.864 124.883 ;
     RECT  27.504 124.547 38.088 124.883 ;
     RECT  39.264 124.789 43.896 124.883 ;
     RECT  50.448 124.019 54.024 124.883 ;
     RECT  72.6 123.493 73.032 124.883 ;
     RECT  76.272 123.635 76.296 124.883 ;
     RECT  3.984 121.331 5.16 124.931 ;
     RECT  14.496 124.883 16.632 124.931 ;
     RECT  6.144 124.067 8.112 124.979 ;
     RECT  70.992 124.213 71.256 125.075 ;
     RECT  29.088 124.883 38.088 125.219 ;
     RECT  63.552 117.731 63.576 125.219 ;
     RECT  11.952 124.789 11.976 125.221 ;
     RECT  11.568 125.221 11.976 125.269 ;
     RECT  13.2 124.883 13.512 125.269 ;
     RECT  29.4 125.219 38.088 125.315 ;
     RECT  80.496 124.355 80.52 125.363 ;
     RECT  55.728 124.739 56.712 125.365 ;
     RECT  48.144 122.387 49.272 125.411 ;
     RECT  14.496 124.931 14.52 125.459 ;
     RECT  21.456 124.883 21.864 125.459 ;
     RECT  23.76 124.547 26.424 125.459 ;
     RECT  27.504 124.883 27.864 125.459 ;
     RECT  29.4 125.315 35.112 125.459 ;
     RECT  36.72 125.315 38.088 125.459 ;
     RECT  39.264 124.883 41.976 125.459 ;
     RECT  44.976 123.203 45.912 125.459 ;
     RECT  51 124.883 54.024 125.459 ;
     RECT  70.992 125.075 71.208 125.459 ;
     RECT  78 124.835 78.888 125.459 ;
     RECT  82.032 124.789 82.056 125.459 ;
     RECT  21.552 125.459 21.864 125.507 ;
     RECT  23.76 125.459 24.984 125.507 ;
     RECT  29.4 125.459 30.744 125.507 ;
     RECT  69.696 123.731 70.008 125.507 ;
     RECT  15.6 124.931 16.632 125.555 ;
     RECT  33.936 125.459 35.112 125.603 ;
     RECT  48.192 125.411 49.272 125.651 ;
     RECT  64.56 123.731 68.712 125.651 ;
     RECT  45.6 125.459 45.912 125.653 ;
     RECT  11.568 125.269 13.512 125.699 ;
     RECT  53.808 125.459 54.024 125.699 ;
     RECT  64.704 125.651 68.712 125.699 ;
     RECT  15.6 125.555 15.624 125.747 ;
     RECT  64.704 125.699 64.728 125.747 ;
     RECT  10.224 125.221 10.248 125.797 ;
     RECT  4.128 124.931 5.16 125.891 ;
     RECT  7.056 124.979 8.112 125.893 ;
     RECT  40.2 125.459 41.976 125.893 ;
     RECT  43.392 124.883 43.896 125.893 ;
     RECT  7.056 125.893 8.52 125.941 ;
     RECT  51 125.459 52.248 125.987 ;
     RECT  5.136 125.891 5.16 126.035 ;
     RECT  16.608 125.555 16.632 126.035 ;
     RECT  17.712 124.883 20.04 126.035 ;
     RECT  21.84 125.507 21.864 126.035 ;
     RECT  27.504 125.459 27.768 126.035 ;
     RECT  36.72 125.459 37.944 126.035 ;
     RECT  55.248 125.365 56.712 126.035 ;
     RECT  58.992 124.163 59.016 126.035 ;
     RECT  4.128 125.891 4.152 126.083 ;
     RECT  40.2 125.893 43.896 126.083 ;
     RECT  37.92 126.035 37.944 126.131 ;
     RECT  60.384 125.893 60.408 126.133 ;
     RECT  18.48 126.035 20.04 126.179 ;
     RECT  49.248 125.651 49.272 126.179 ;
     RECT  53.808 125.699 53.928 126.227 ;
     RECT  48.192 125.651 48.216 126.275 ;
     RECT  29.4 125.507 29.712 126.421 ;
     RECT  55.632 126.035 56.712 126.421 ;
     RECT  61.8 123.155 62.112 126.421 ;
     RECT  63.216 125.941 63.24 126.421 ;
     RECT  72.6 124.883 72.912 126.421 ;
     RECT  78 125.459 78.312 126.421 ;
     RECT  65.856 125.699 68.712 126.469 ;
     RECT  69.696 125.507 69.72 126.469 ;
     RECT  72.48 126.421 72.912 126.469 ;
     RECT  74.64 125.845 74.664 126.469 ;
     RECT  75.792 125.365 75.816 126.469 ;
     RECT  6.432 125.941 8.52 126.517 ;
     RECT  9.648 125.797 10.248 126.517 ;
     RECT  14.784 126.181 14.808 126.517 ;
     RECT  34.8 125.603 35.112 126.517 ;
     RECT  51 125.987 51.672 126.517 ;
     RECT  65.856 126.469 69.912 126.517 ;
     RECT  77.52 126.421 78.312 126.517 ;
     RECT  60.384 126.133 60.6 126.563 ;
     RECT  6.432 126.517 10.248 126.659 ;
     RECT  50.688 126.517 51.672 126.661 ;
     RECT  30.72 125.507 30.744 126.803 ;
     RECT  38.688 126.517 38.808 126.803 ;
     RECT  61.8 126.421 63.624 126.853 ;
     RECT  65.856 126.517 70.728 126.853 ;
     RECT  71.76 126.469 74.664 126.853 ;
     RECT  80.208 125.365 80.376 126.901 ;
     RECT  12.528 125.699 13.512 126.949 ;
     RECT  40.2 126.083 42.744 126.949 ;
     RECT  61.8 126.853 74.664 126.949 ;
     RECT  75.792 126.469 76.536 126.949 ;
     RECT  80.208 126.901 80.568 126.949 ;
     RECT  77.52 126.517 78.84 126.997 ;
     RECT  80.208 126.949 81.912 126.997 ;
     RECT  12.144 126.949 13.512 127.045 ;
     RECT  14.736 126.517 14.808 127.045 ;
     RECT  44.112 126.949 44.568 127.045 ;
     RECT  45.6 125.653 46.728 127.045 ;
     RECT  55.632 126.421 57.384 127.045 ;
     RECT  61.8 126.949 76.536 127.045 ;
     RECT  77.52 126.997 81.912 127.045 ;
     RECT  5.328 126.661 5.352 127.093 ;
     RECT  6.672 126.659 10.248 127.093 ;
     RECT  22.8 126.517 22.824 127.093 ;
     RECT  24 125.507 24.984 127.093 ;
     RECT  29.28 126.421 29.712 127.093 ;
     RECT  39.264 126.949 42.744 127.093 ;
     RECT  44.112 127.045 47.16 127.093 ;
     RECT  36.912 127.093 36.936 127.141 ;
     RECT  60.576 126.563 60.6 127.381 ;
     RECT  61.8 127.045 81.912 127.381 ;
     RECT  2.4 106.691 2.712 127.449 ;
     RECT  83.4 107.795 83.712 127.449 ;
     RECT  2.4 127.449 2.52 127.463 ;
     RECT  39.264 127.093 47.16 127.463 ;
     RECT  54.768 127.045 57.384 127.463 ;
     RECT  83.4 127.449 83.52 127.463 ;
     RECT  34.8 126.517 35.208 127.573 ;
     RECT  12.144 127.045 14.808 127.621 ;
     RECT  29.04 127.093 29.712 127.621 ;
     RECT  4.464 127.093 5.352 127.669 ;
     RECT  6.672 127.093 10.776 127.669 ;
     RECT  22.368 127.093 24.984 127.669 ;
     RECT  34.752 127.573 35.208 127.669 ;
     RECT  36.912 127.141 37.368 127.669 ;
     RECT  50.352 126.661 51.672 127.669 ;
     RECT  4.464 127.669 10.776 128.197 ;
     RECT  12.144 127.621 15.192 128.197 ;
     RECT  17.376 126.949 17.4 128.197 ;
     RECT  18.48 126.179 19.704 128.197 ;
     RECT  21.408 127.669 24.984 128.197 ;
     RECT  26.256 127.045 26.28 128.197 ;
     RECT  28.464 127.621 29.712 128.197 ;
     RECT  32.496 127.669 33.48 128.197 ;
     RECT  34.752 127.669 37.368 128.197 ;
     RECT  46.608 127.463 47.16 128.197 ;
     RECT  48.144 127.621 48.168 128.197 ;
     RECT  52.944 127.141 52.968 128.197 ;
     RECT  54.768 127.463 55.656 128.197 ;
     RECT  56.928 127.463 57.384 128.197 ;
     RECT  58.368 127.093 59.256 128.197 ;
     RECT  20.976 128.197 29.712 128.245 ;
     RECT  31.2 127.669 31.224 128.245 ;
     RECT  32.496 128.197 37.368 128.245 ;
     RECT  4.464 128.197 19.704 128.821 ;
     RECT  20.976 128.245 31.224 128.821 ;
     RECT  32.496 128.245 37.8 128.821 ;
     RECT  39.264 127.463 45.432 128.821 ;
     RECT  46.608 128.197 48.168 128.821 ;
     RECT  49.488 127.669 51.672 128.821 ;
     RECT  52.944 128.197 55.656 128.821 ;
     RECT  56.928 128.197 59.256 128.821 ;
     RECT  60.576 127.381 81.912 128.821 ;
     RECT  4.464 128.821 37.8 129.408 ;
     RECT  4.488 129.408 4.896 129.424 ;
     RECT  4.92 129.408 5.328 129.424 ;
     RECT  5.352 129.408 6.288 129.424 ;
     RECT  6.312 129.408 6.72 129.424 ;
     RECT  6.744 129.408 7.152 129.424 ;
     RECT  7.176 129.408 7.584 129.424 ;
     RECT  7.608 129.408 8.016 129.424 ;
     RECT  8.04 129.408 8.448 129.424 ;
     RECT  8.472 129.408 8.88 129.424 ;
     RECT  8.904 129.408 9.456 129.424 ;
     RECT  9.48 129.408 9.888 129.424 ;
     RECT  9.912 129.408 10.32 129.424 ;
     RECT  10.344 129.408 10.752 129.424 ;
     RECT  10.776 129.408 11.712 129.424 ;
     RECT  11.736 129.408 12.144 129.424 ;
     RECT  12.168 129.408 12.576 129.424 ;
     RECT  12.6 129.408 13.008 129.424 ;
     RECT  13.032 129.408 13.44 129.424 ;
     RECT  13.464 129.408 13.872 129.424 ;
     RECT  13.896 129.408 14.304 129.424 ;
     RECT  14.328 129.408 14.736 129.424 ;
     RECT  14.76 129.408 15.168 129.424 ;
     RECT  15.192 129.408 15.6 129.424 ;
     RECT  15.624 129.408 16.032 129.424 ;
     RECT  16.056 129.408 16.944 129.424 ;
     RECT  16.968 129.408 17.376 129.424 ;
     RECT  17.4 129.408 17.808 129.424 ;
     RECT  17.832 129.408 18.24 129.424 ;
     RECT  18.264 129.408 18.672 129.424 ;
     RECT  18.696 129.408 19.248 129.424 ;
     RECT  19.272 129.408 19.68 129.424 ;
     RECT  19.704 129.408 20.112 129.424 ;
     RECT  20.136 129.408 20.544 129.424 ;
     RECT  20.568 129.408 20.976 129.424 ;
     RECT  21 129.408 21.408 129.424 ;
     RECT  21.432 129.408 22.368 129.424 ;
     RECT  22.392 129.408 22.8 129.424 ;
     RECT  22.824 129.408 23.232 129.424 ;
     RECT  23.256 129.408 23.664 129.424 ;
     RECT  23.688 129.408 24.096 129.424 ;
     RECT  24.12 129.408 24.528 129.424 ;
     RECT  24.552 129.408 24.96 129.424 ;
     RECT  24.984 129.408 25.392 129.424 ;
     RECT  25.416 129.408 25.824 129.424 ;
     RECT  25.848 129.408 26.256 129.424 ;
     RECT  26.28 129.408 26.688 129.424 ;
     RECT  26.712 129.408 27.12 129.424 ;
     RECT  27.144 129.408 28.032 129.424 ;
     RECT  28.056 129.408 28.464 129.424 ;
     RECT  28.488 129.408 29.04 129.424 ;
     RECT  29.064 129.408 29.472 129.424 ;
     RECT  29.496 129.408 29.904 129.424 ;
     RECT  29.928 129.408 30.336 129.424 ;
     RECT  30.36 129.408 30.768 129.424 ;
     RECT  30.792 129.408 31.2 129.424 ;
     RECT  31.224 129.408 31.632 129.424 ;
     RECT  31.656 129.408 32.064 129.424 ;
     RECT  32.088 129.408 32.496 129.424 ;
     RECT  32.52 129.408 33.456 129.424 ;
     RECT  33.48 129.408 33.888 129.424 ;
     RECT  33.912 129.408 34.32 129.424 ;
     RECT  34.344 129.408 34.752 129.424 ;
     RECT  34.776 129.408 35.184 129.424 ;
     RECT  35.208 129.408 35.616 129.424 ;
     RECT  35.64 129.408 36.048 129.424 ;
     RECT  36.072 129.408 36.48 129.424 ;
     RECT  36.504 129.408 36.912 129.424 ;
     RECT  36.936 129.408 37.344 129.424 ;
     RECT  37.368 129.408 37.776 129.424 ;
     RECT  38.832 128.821 81.912 129.408 ;
     RECT  38.856 129.408 39.264 129.424 ;
     RECT  39.288 129.408 39.696 129.424 ;
     RECT  39.72 129.408 40.128 129.424 ;
     RECT  40.152 129.408 40.56 129.424 ;
     RECT  40.584 129.408 40.992 129.424 ;
     RECT  41.016 129.408 41.424 129.424 ;
     RECT  41.448 129.408 41.856 129.424 ;
     RECT  41.88 129.408 42.288 129.424 ;
     RECT  42.312 129.408 42.72 129.424 ;
     RECT  42.744 129.408 43.152 129.424 ;
     RECT  43.176 129.408 44.112 129.424 ;
     RECT  44.136 129.408 44.544 129.424 ;
     RECT  44.568 129.408 44.976 129.424 ;
     RECT  45 129.408 45.408 129.424 ;
     RECT  45.432 129.408 45.84 129.424 ;
     RECT  45.864 129.408 46.272 129.424 ;
     RECT  46.296 129.408 46.704 129.424 ;
     RECT  46.728 129.408 47.136 129.424 ;
     RECT  47.16 129.408 47.568 129.424 ;
     RECT  47.592 129.408 48.144 129.424 ;
     RECT  48.168 129.408 48.576 129.424 ;
     RECT  48.6 129.408 49.488 129.424 ;
     RECT  49.512 129.408 49.92 129.424 ;
     RECT  49.944 129.408 50.352 129.424 ;
     RECT  50.376 129.408 50.784 129.424 ;
     RECT  50.808 129.408 51.216 129.424 ;
     RECT  51.24 129.408 51.648 129.424 ;
     RECT  51.672 129.408 52.08 129.424 ;
     RECT  52.104 129.408 52.512 129.424 ;
     RECT  52.536 129.408 52.944 129.424 ;
     RECT  52.968 129.408 53.376 129.424 ;
     RECT  53.4 129.408 53.808 129.424 ;
     RECT  53.832 129.408 54.768 129.424 ;
     RECT  54.792 129.408 55.2 129.424 ;
     RECT  55.224 129.408 55.632 129.424 ;
     RECT  55.656 129.408 56.064 129.424 ;
     RECT  56.088 129.408 56.496 129.424 ;
     RECT  56.52 129.408 56.928 129.424 ;
     RECT  56.952 129.408 57.36 129.424 ;
     RECT  57.384 129.408 57.936 129.424 ;
     RECT  57.96 129.408 58.368 129.424 ;
     RECT  58.392 129.408 58.8 129.424 ;
     RECT  58.824 129.408 59.232 129.424 ;
     RECT  59.256 129.408 60.144 129.424 ;
     RECT  60.168 129.408 60.576 129.424 ;
     RECT  60.6 129.408 61.008 129.424 ;
     RECT  61.032 129.408 61.44 129.424 ;
     RECT  61.464 129.408 61.872 129.424 ;
     RECT  61.896 129.408 62.304 129.424 ;
     RECT  62.328 129.408 62.736 129.424 ;
     RECT  62.76 129.408 63.168 129.424 ;
     RECT  63.192 129.408 63.6 129.424 ;
     RECT  63.624 129.408 64.032 129.424 ;
     RECT  64.056 129.408 64.464 129.424 ;
     RECT  64.488 129.408 64.896 129.424 ;
     RECT  64.92 129.408 65.856 129.424 ;
     RECT  65.88 129.408 66.288 129.424 ;
     RECT  66.312 129.408 66.72 129.424 ;
     RECT  66.744 129.408 67.152 129.424 ;
     RECT  67.176 129.408 67.728 129.424 ;
     RECT  67.752 129.408 68.16 129.424 ;
     RECT  68.184 129.408 68.592 129.424 ;
     RECT  68.616 129.408 69.024 129.424 ;
     RECT  69.048 129.408 69.456 129.424 ;
     RECT  69.48 129.408 69.888 129.424 ;
     RECT  69.912 129.408 70.32 129.424 ;
     RECT  70.344 129.408 71.232 129.424 ;
     RECT  71.256 129.408 71.664 129.424 ;
     RECT  71.688 129.408 72.096 129.424 ;
     RECT  72.12 129.408 72.528 129.424 ;
     RECT  72.552 129.408 72.96 129.424 ;
     RECT  72.984 129.408 73.392 129.424 ;
     RECT  73.416 129.408 73.824 129.424 ;
     RECT  73.848 129.408 74.256 129.424 ;
     RECT  74.28 129.408 74.688 129.424 ;
     RECT  74.712 129.408 75.12 129.424 ;
     RECT  75.144 129.408 75.552 129.424 ;
     RECT  75.576 129.408 76.512 129.424 ;
     RECT  76.536 129.408 76.944 129.424 ;
     RECT  76.968 129.408 77.52 129.424 ;
     RECT  77.544 129.408 77.952 129.424 ;
     RECT  77.976 129.408 78.384 129.424 ;
     RECT  78.408 129.408 78.816 129.424 ;
     RECT  78.84 129.408 79.248 129.424 ;
     RECT  79.272 129.408 79.68 129.424 ;
     RECT  79.704 129.408 80.112 129.424 ;
     RECT  80.136 129.408 80.544 129.424 ;
     RECT  80.568 129.408 80.976 129.424 ;
     RECT  81 129.408 81.888 129.424 ;
     RECT  6.672 129.424 6.696 129.491 ;
     RECT  62.352 129.424 62.376 129.491 ;
     RECT  5.496 0.611 6.576 1.763 ;
     RECT  23.112 0.611 24.384 2.053 ;
     RECT  37.944 0.611 39.12 1.763 ;
     RECT  43.176 0.611 44.256 1.763 ;
     RECT  64.632 0.611 66.144 1.763 ;
     RECT  75.72 0.611 76.8 1.763 ;
     RECT  5.616 1.763 6.672 2.629 ;
     RECT  13.704 1.763 15.456 2.773 ;
     RECT  15.48 1.763 17.232 2.339 ;
     RECT  21.576 1.763 22.608 3.829 ;
     RECT  26.712 1.763 28.464 2.387 ;
     RECT  35.112 1.763 36.144 3.205 ;
     RECT  37.08 1.763 39.84 2.773 ;
     RECT  41.448 1.763 42.432 2.339 ;
     RECT  43.176 1.763 44.544 1.811 ;
     RECT  60.96 1.763 61.632 2.821 ;
     RECT  62.112 1.763 63.312 3.157 ;
     RECT  63.336 1.763 63.864 2.821 ;
     RECT  72.912 1.763 73.968 2.291 ;
     RECT  80.496 1.763 80.52 2.773 ;
     RECT  42.456 1.811 44.544 2.821 ;
     RECT  47.016 1.811 48.432 2.821 ;
     RECT  67.512 1.811 68.88 2.291 ;
     RECT  72.912 2.291 73.992 3.733 ;
     RECT  15.48 2.339 17.52 3.205 ;
     RECT  25.656 2.339 26.688 2.387 ;
     RECT  30.216 2.339 31.296 3.443 ;
     RECT  41.256 2.339 42.432 3.397 ;
     RECT  49.56 2.339 50.64 3.397 ;
     RECT  25.656 2.387 28.464 2.725 ;
     RECT  5.64 2.629 6.672 2.821 ;
     RECT  25.656 2.725 26.736 2.915 ;
     RECT  26.952 2.725 28.464 2.821 ;
     RECT  37.416 2.773 39.456 2.821 ;
     RECT  37.416 2.821 38.928 3.347 ;
     RECT  42.456 2.821 43.824 3.205 ;
     RECT  47.016 2.821 48.384 2.963 ;
     RECT  63.816 2.821 63.864 3.205 ;
     RECT  9.096 2.915 10.224 4.117 ;
     RECT  24.744 2.915 26.736 3.541 ;
     RECT  47.016 2.963 48.432 4.019 ;
     RECT  62.112 3.157 63.168 4.595 ;
     RECT  15.864 3.205 17.52 3.349 ;
     RECT  37.416 3.347 37.704 3.397 ;
     RECT  16.296 3.349 17.52 3.733 ;
     RECT  49.56 3.397 50.592 3.733 ;
     RECT  27.624 3.443 29.088 5.171 ;
     RECT  29.712 3.443 31.296 3.877 ;
     RECT  35.256 3.443 36.336 5.077 ;
     RECT  24.744 3.541 26.208 4.261 ;
     RECT  32.424 3.685 33.84 4.019 ;
     RECT  73.272 3.733 74.544 5.605 ;
     RECT  59.256 3.829 60.336 4.595 ;
     RECT  2.712 3.877 4.08 3.925 ;
     RECT  4.104 3.877 5.616 4.163 ;
     RECT  29.712 3.877 30.72 4.885 ;
     RECT  2.712 3.925 3.984 4.309 ;
     RECT  32.424 4.019 33.888 4.595 ;
     RECT  47.016 4.019 47.4 4.405 ;
     RECT  13.896 4.067 15.168 5.173 ;
     RECT  4.104 4.163 4.824 4.501 ;
     RECT  25.032 4.261 26.208 4.595 ;
     RECT  2.712 4.309 3.936 5.509 ;
     RECT  4.632 4.501 4.824 5.365 ;
     RECT  25.032 4.595 26.4 4.981 ;
     RECT  32.424 4.595 34.176 4.837 ;
     RECT  59.16 4.595 60.336 4.789 ;
     RECT  62.112 4.595 63.216 5.747 ;
     RECT  59.16 4.789 60.192 5.171 ;
     RECT  32.856 4.837 34.176 5.747 ;
     RECT  25.08 4.981 26.4 5.171 ;
     RECT  35.304 5.077 36.336 6.277 ;
     RECT  74.568 5.077 75.84 5.747 ;
     RECT  75.864 5.077 77.04 5.171 ;
     RECT  25.032 5.171 26.4 5.267 ;
     RECT  59.16 5.171 60.336 5.747 ;
     RECT  75.864 5.171 78 5.365 ;
     RECT  42.936 5.219 44.256 5.795 ;
     RECT  8.616 5.267 9.6 5.747 ;
     RECT  75.864 5.365 76.896 5.413 ;
     RECT  76.92 5.365 78 6.323 ;
     RECT  2.856 5.509 3.936 5.605 ;
     RECT  2.904 5.605 3.936 6.133 ;
     RECT  73.512 5.605 74.544 5.747 ;
     RECT  8.568 5.747 9.6 6.323 ;
     RECT  32.424 5.747 34.176 5.795 ;
     RECT  51.312 5.747 51.528 6.805 ;
     RECT  56.712 5.747 57.84 10.213 ;
     RECT  62.112 5.747 63.312 6.371 ;
     RECT  73.512 5.747 73.896 6.805 ;
     RECT  16.104 5.795 17.52 6.419 ;
     RECT  32.424 5.795 34.224 6.805 ;
     RECT  22.008 5.843 23.184 6.611 ;
     RECT  29.28 6.323 29.4 6.805 ;
     RECT  76.728 6.323 78 6.851 ;
     RECT  62.112 6.371 62.952 7.141 ;
     RECT  16.104 6.419 17.904 7.189 ;
     RECT  24.888 6.805 26.4 6.899 ;
     RECT  27.912 6.805 29.4 7.043 ;
     RECT  32.424 6.805 33.408 8.533 ;
     RECT  14.808 6.851 15.792 6.899 ;
     RECT  77.904 6.851 78 7.957 ;
     RECT  6.648 6.899 7.68 8.051 ;
     RECT  14.616 6.899 15.792 9.157 ;
     RECT  21.24 6.899 22.008 7.957 ;
     RECT  44.28 6.899 45.6 11.125 ;
     RECT  64.968 6.997 66.24 7.715 ;
     RECT  28.176 7.043 29.4 7.333 ;
     RECT  54.168 7.093 55.632 8.003 ;
     RECT  16.632 7.189 17.904 8.533 ;
     RECT  10.824 7.331 12.096 7.571 ;
     RECT  28.2 7.333 29.4 8.869 ;
     RECT  46.824 7.475 48 9.061 ;
     RECT  10.224 7.571 12.096 8.869 ;
     RECT  64.968 7.715 67.104 8.197 ;
     RECT  21.288 7.957 22.008 8.389 ;
     RECT  55.488 8.003 55.632 9.253 ;
     RECT  6.624 8.051 7.68 9.061 ;
     RECT  65.208 8.197 67.104 8.821 ;
     RECT  21.288 8.389 22.8 8.915 ;
     RECT  22.824 8.389 24 8.915 ;
     RECT  38.28 8.437 39.744 8.579 ;
     RECT  48.024 8.485 49.152 9.157 ;
     RECT  49.176 8.485 50.4 9.637 ;
     RECT  74.52 8.485 75.84 9.395 ;
     RECT  78.312 8.533 79.824 9.059 ;
     RECT  79.848 8.533 81.264 9.059 ;
     RECT  38.28 8.579 39.792 10.357 ;
     RECT  65.688 8.821 67.104 10.837 ;
     RECT  10.224 8.869 10.704 8.917 ;
     RECT  10.728 8.869 12.096 8.917 ;
     RECT  21.288 8.915 21.336 9.349 ;
     RECT  23.616 8.915 24 9.973 ;
     RECT  8.568 8.917 9.6 11.267 ;
     RECT  9.624 8.917 10.704 9.061 ;
     RECT  78.312 9.059 78.648 10.213 ;
     RECT  5.064 9.061 6.096 9.107 ;
     RECT  4.824 9.107 6.096 10.789 ;
     RECT  51.624 9.109 53.136 9.685 ;
     RECT  14.616 9.157 15.696 10.165 ;
     RECT  48.168 9.157 49.152 9.877 ;
     RECT  3.096 9.539 4.128 10.307 ;
     RECT  24.792 9.589 25.92 9.637 ;
     RECT  51.624 9.685 53.088 10.213 ;
     RECT  41.784 10.021 43.104 10.885 ;
     RECT  43.128 10.021 44.256 10.597 ;
     RECT  27.84 10.115 28.176 11.077 ;
     RECT  51.624 10.213 53.04 10.597 ;
     RECT  70.488 10.213 71.712 14.197 ;
     RECT  58.584 10.259 59.16 11.461 ;
     RECT  3.096 10.307 4.8 11.221 ;
     RECT  46.824 10.307 48.048 11.413 ;
     RECT  38.808 10.357 39.792 11.365 ;
     RECT  51.72 10.597 53.04 10.787 ;
     RECT  53.16 10.739 53.496 11.941 ;
     RECT  51.72 10.787 53.088 10.837 ;
     RECT  4.824 10.789 5.808 12.997 ;
     RECT  51.816 10.837 53.088 11.171 ;
     RECT  25.944 11.077 27.456 11.317 ;
     RECT  44.28 11.125 45.264 11.989 ;
     RECT  42.216 11.171 43.344 12.517 ;
     RECT  51.72 11.171 53.088 12.037 ;
     RECT  3.816 11.221 4.8 12.901 ;
     RECT  8.568 11.267 10.128 11.941 ;
     RECT  68.568 11.365 69.984 12.037 ;
     RECT  6.12 11.411 7.152 11.459 ;
     RECT  24.792 11.411 25.92 12.709 ;
     RECT  75.84 11.411 76.128 12.757 ;
     RECT  6.024 11.459 7.152 16.019 ;
     RECT  58.584 11.461 59.712 12.421 ;
     RECT  9.096 11.941 10.128 12.853 ;
     RECT  54.072 11.941 55.488 12.517 ;
     RECT  51.72 12.037 53.04 12.181 ;
     RECT  68.808 12.037 69.984 12.133 ;
     RECT  54.456 12.517 55.488 13.715 ;
     RECT  24.792 12.709 25.776 12.853 ;
     RECT  59.736 12.997 60.864 13.045 ;
     RECT  54.456 13.715 55.632 13.859 ;
     RECT  4.824 14.291 5.808 15.349 ;
     RECT  5.832 16.019 7.152 18.181 ;
     RECT  54.504 16.837 55.632 17.221 ;
     RECT  3.96 17.123 5.088 18.181 ;
     RECT  80.04 17.221 81.216 20.819 ;
     RECT  78.984 17.845 80.016 22.835 ;
     RECT  2.712 18.899 3.792 20.197 ;
     RECT  20.136 19.187 21.36 19.859 ;
     RECT  0.288 19.763 0.312 20.869 ;
     RECT  19.944 19.859 21.36 20.869 ;
     RECT  20.04 20.869 21.36 21.733 ;
     RECT  54.984 21.299 56.112 23.317 ;
     RECT  2.808 21.731 3.792 22.259 ;
     RECT  2.808 22.259 4.56 22.307 ;
     RECT  2.712 22.307 4.56 23.269 ;
     RECT  16.68 22.355 18.096 24.709 ;
     RECT  26.328 22.403 27.312 25.669 ;
     RECT  4.776 22.835 5.808 23.987 ;
     RECT  2.712 23.269 3.888 23.797 ;
     RECT  52.728 23.939 53.76 25.043 ;
     RECT  4.584 23.987 5.808 24.997 ;
     RECT  2.712 24.563 3.792 26.869 ;
     RECT  51.48 24.947 52.56 26.437 ;
     RECT  52.632 25.043 53.76 25.669 ;
     RECT  52.632 25.669 53.616 26.053 ;
     RECT  55.368 25.715 56.4 29.605 ;
     RECT  80.52 26.339 80.952 27.301 ;
     RECT  51.48 26.437 52.464 26.677 ;
     RECT  74.568 27.349 75.84 29.797 ;
     RECT  4.296 27.971 5.376 28.643 ;
     RECT  3.432 28.643 5.376 28.933 ;
     RECT  3.432 28.933 4.416 29.123 ;
     RECT  51.48 28.979 52.464 30.227 ;
     RECT  80.688 29.315 81.264 30.325 ;
     RECT  74.712 29.797 75.84 35.173 ;
     RECT  51.48 30.227 52.56 32.291 ;
     RECT  81.288 30.469 82.8 39.301 ;
     RECT  51.312 32.291 52.56 34.165 ;
     RECT  79.896 33.973 81.264 35.363 ;
     RECT  51.528 34.165 52.56 36.517 ;
     RECT  2.712 34.741 4.128 37.717 ;
     RECT  74.856 35.173 75.84 38.725 ;
     RECT  79.872 35.363 81.264 35.557 ;
     RECT  78.312 35.557 79.824 38.195 ;
     RECT  79.848 35.557 81.264 38.195 ;
     RECT  6.264 35.795 7.392 36.083 ;
     RECT  6.264 36.083 7.632 38.773 ;
     RECT  2.712 37.717 3.984 43.285 ;
     RECT  80.016 38.195 81.264 38.725 ;
     RECT  80.016 38.725 80.352 39.349 ;
     RECT  6.264 38.773 7.488 39.301 ;
     RECT  81.528 39.301 82.8 42.803 ;
     RECT  80.04 39.395 81.264 44.965 ;
     RECT  2.712 43.285 3.936 45.541 ;
     RECT  80.28 44.965 81.264 47.269 ;
     RECT  76.968 45.253 78 50.677 ;
     RECT  2.856 47.363 3.936 47.987 ;
     RECT  2.856 47.987 3.984 49.525 ;
     RECT  80.04 53.027 81.264 60.323 ;
     RECT  0.192 54.179 0.216 54.24 ;
     RECT  0.192 54.36 0.216 54.384 ;
     RECT  0.192 54.504 0.384 54.528 ;
     RECT  0.24 54.528 0.384 54.648 ;
     RECT  76.968 54.563 78 58.309 ;
     RECT  0.192 54.648 0.384 54.672 ;
     RECT  0.24 54.672 0.384 54.792 ;
     RECT  21.96 54.755 23.088 55.765 ;
     RECT  0.192 54.792 0.384 54.96 ;
     RECT  0.24 54.96 0.384 55.08 ;
     RECT  0.192 55.08 0.384 55.104 ;
     RECT  0.24 55.104 0.384 55.141 ;
     RECT  78.408 57.829 79.536 57.875 ;
     RECT  78.312 57.875 79.536 60.515 ;
     RECT  2.712 58.211 3.984 60.373 ;
     RECT  41.352 59.555 42.336 60.371 ;
     RECT  41.16 60.371 42.336 60.853 ;
     RECT  41.16 60.853 42.192 61.619 ;
     RECT  2.952 61.091 3.984 63.205 ;
     RECT  41.16 61.619 42.336 62.195 ;
     RECT  39.144 62.195 40.2 64.309 ;
     RECT  41.016 62.195 42.336 64.261 ;
     RECT  60.12 64.211 61.248 65.653 ;
     RECT  41.016 64.261 42.24 64.645 ;
     RECT  2.856 65.027 3.936 65.603 ;
     RECT  2.808 65.603 3.936 66.275 ;
     RECT  41.352 66.227 42.336 68.435 ;
     RECT  2.712 66.275 3.936 66.851 ;
     RECT  2.712 66.851 3.984 105.973 ;
     RECT  79.464 67.525 80.88 67.571 ;
     RECT  41.256 68.435 42.336 69.637 ;
     RECT  80.88 70.259 81.264 70.357 ;
     RECT  79.752 70.357 81.264 71.269 ;
     RECT  79.752 71.269 80.928 72.419 ;
     RECT  79.752 72.419 81.264 73.381 ;
     RECT  80.664 82.549 81.792 83.699 ;
     RECT  81.912 83.653 83.4 87.539 ;
     RECT  80.664 83.699 81.888 87.539 ;
     RECT  79.8 88.355 80.568 89.461 ;
     RECT  22.104 89.699 23.088 91.381 ;
     RECT  54.312 91.619 55.344 91.907 ;
     RECT  54.312 91.907 55.536 93.539 ;
     RECT  79.8 92.387 80.568 93.445 ;
     RECT  54.12 93.539 55.536 95.557 ;
     RECT  82.104 96.853 83.4 98.053 ;
     RECT  82.344 98.053 83.4 102.083 ;
     RECT  79.752 98.675 80.736 99.203 ;
     RECT  83.184 102.083 83.4 103.141 ;
     RECT  2.712 106.691 3.984 124.931 ;
     RECT  5.16 107.795 6.144 109.381 ;
     RECT  73.656 113.939 74.64 114.947 ;
     RECT  71.208 114.947 72.24 116.915 ;
     RECT  73.56 114.947 74.64 115.043 ;
     RECT  57.096 115.427 58.08 116.147 ;
     RECT  75.144 115.763 76.416 117.443 ;
     RECT  20.232 115.811 21.216 116.965 ;
     RECT  22.056 115.811 23.088 117.733 ;
     RECT  57.096 116.147 58.272 117.637 ;
     RECT  70.008 116.579 70.992 125.459 ;
     RECT  54.456 116.723 55.728 119.077 ;
     RECT  71.208 116.915 72.336 118.309 ;
     RECT  26.424 117.059 27.504 118.837 ;
     RECT  63.576 117.299 64.56 125.219 ;
     RECT  75.144 117.443 77.376 118.069 ;
     RECT  62.424 117.731 63.552 119.555 ;
     RECT  22.056 117.923 23.088 118.019 ;
     RECT  22.056 118.019 23.184 119.797 ;
     RECT  75.864 118.069 77.376 118.549 ;
     RECT  59.352 118.115 60.336 119.987 ;
     RECT  71.208 118.309 72.24 119.699 ;
     RECT  57.048 118.355 58.272 118.835 ;
     RECT  6.168 118.451 7.536 119.509 ;
     RECT  75.864 118.549 77.28 118.981 ;
     RECT  80.232 118.643 80.424 119.653 ;
     RECT  68.904 118.739 69.984 120.805 ;
     RECT  56.808 118.835 58.272 119.219 ;
     RECT  75.864 118.981 76.896 119.941 ;
     RECT  26.424 119.075 27.504 122.485 ;
     RECT  54.552 119.077 55.728 120.515 ;
     RECT  56.712 119.219 58.272 120.229 ;
     RECT  6.552 119.509 7.536 120.709 ;
     RECT  62.232 119.555 63.552 119.747 ;
     RECT  71.208 119.699 72.336 121.189 ;
     RECT  62.112 119.747 63.552 125.219 ;
     RECT  11.4 119.795 12.528 120.805 ;
     RECT  22.152 119.797 23.184 119.939 ;
     RECT  22.152 119.939 23.616 120.467 ;
     RECT  59.352 119.987 60.816 120.371 ;
     RECT  75.288 119.987 76.416 121.859 ;
     RECT  46.824 120.083 48.144 120.371 ;
     RECT  20.232 120.179 21.216 124.883 ;
     RECT  56.712 120.229 58.032 120.947 ;
     RECT  46.776 120.371 48.144 123.203 ;
     RECT  54.216 120.515 55.728 123.155 ;
     RECT  43.608 120.851 44.784 121.331 ;
     RECT  5.16 121.331 6.144 124.979 ;
     RECT  43.608 121.331 44.976 124.789 ;
     RECT  79.8 121.475 80.832 123.155 ;
     RECT  71.208 122.003 72.192 123.491 ;
     RECT  6.552 122.099 7.536 123.637 ;
     RECT  38.088 122.387 39.168 123.347 ;
     RECT  49.272 122.387 50.4 123.155 ;
     RECT  59.88 122.773 60.96 123.155 ;
     RECT  11.88 122.915 12.864 123.011 ;
     RECT  56.712 122.917 57.744 123.971 ;
     RECT  57.768 122.917 58.992 123.877 ;
     RECT  49.272 123.155 50.448 124.883 ;
     RECT  79.8 123.155 80.52 123.589 ;
     RECT  38.088 123.347 39.264 125.459 ;
     RECT  71.208 123.491 72.6 124.213 ;
     RECT  76.44 123.491 77.808 123.635 ;
     RECT  76.296 123.635 77.808 124.835 ;
     RECT  68.712 123.731 69.696 126.469 ;
     RECT  73.032 123.925 74.448 124.307 ;
     RECT  12.864 123.971 13.2 124.789 ;
     RECT  56.712 123.971 58.224 124.163 ;
     RECT  54.024 124.019 54.168 125.365 ;
     RECT  56.712 124.163 56.856 124.453 ;
     RECT  71.256 124.213 72.6 125.075 ;
     RECT  79.272 124.355 80.496 124.547 ;
     RECT  26.424 124.547 27.504 125.459 ;
     RECT  78.888 124.547 80.496 125.363 ;
     RECT  11.976 124.789 13.2 125.269 ;
     RECT  43.896 124.789 44.976 125.459 ;
     RECT  80.52 124.789 82.032 125.363 ;
     RECT  82.056 124.789 83.4 125.459 ;
     RECT  13.512 124.883 14.496 125.459 ;
     RECT  16.632 124.883 17.712 126.035 ;
     RECT  20.04 124.883 21.456 125.459 ;
     RECT  27.864 124.883 29.088 125.219 ;
     RECT  41.976 124.883 43.392 125.893 ;
     RECT  2.712 124.931 4.128 126.083 ;
     RECT  14.52 124.931 15.6 125.459 ;
     RECT  5.16 124.979 7.056 125.941 ;
     RECT  71.208 125.075 72.6 125.459 ;
     RECT  27.864 125.219 29.4 125.459 ;
     RECT  62.112 125.219 64.56 125.651 ;
     RECT  10.248 125.221 11.568 125.699 ;
     RECT  35.112 125.315 36.72 126.035 ;
     RECT  78.888 125.363 80.376 125.365 ;
     RECT  54.024 125.365 55.248 125.699 ;
     RECT  78.888 125.365 80.208 125.459 ;
     RECT  48.144 125.411 48.192 125.653 ;
     RECT  13.512 125.459 15.6 125.747 ;
     RECT  20.04 125.459 21.552 125.507 ;
     RECT  27.768 125.459 29.4 126.035 ;
     RECT  37.944 125.459 40.2 126.131 ;
     RECT  43.896 125.459 45.6 126.083 ;
     RECT  70.008 125.459 72.6 125.507 ;
     RECT  78.312 125.459 80.208 126.517 ;
     RECT  82.032 125.459 83.4 126.901 ;
     RECT  23.76 125.507 24 126.517 ;
     RECT  29.712 125.507 30.72 126.803 ;
     RECT  69.72 125.507 72.6 126.421 ;
     RECT  15.624 125.555 16.608 125.747 ;
     RECT  48.216 125.651 49.248 126.179 ;
     RECT  62.112 125.651 64.704 125.747 ;
     RECT  46.728 125.653 48.192 126.275 ;
     RECT  10.248 125.699 12.528 126.949 ;
     RECT  53.928 125.699 55.248 126.035 ;
     RECT  64.728 125.699 65.856 125.747 ;
     RECT  13.512 125.747 14.808 126.181 ;
     RECT  62.112 125.747 65.856 125.941 ;
     RECT  74.664 125.845 75.792 126.949 ;
     RECT  4.152 125.891 5.136 126.035 ;
     RECT  8.52 125.893 9.648 126.517 ;
     RECT  59.016 125.893 60.384 126.035 ;
     RECT  60.408 125.893 61.8 126.133 ;
     RECT  5.16 125.941 6.432 126.035 ;
     RECT  62.112 125.941 63.216 126.421 ;
     RECT  63.24 125.941 65.856 126.421 ;
     RECT  51.672 125.987 52.248 127.141 ;
     RECT  4.152 126.035 6.432 126.083 ;
     RECT  17.376 126.035 18.48 126.949 ;
     RECT  29.04 126.035 29.4 126.421 ;
     RECT  35.112 126.035 35.208 126.517 ;
     RECT  36.912 126.035 37.92 126.131 ;
     RECT  53.928 126.035 55.632 126.227 ;
     RECT  58.992 126.035 60.384 126.563 ;
     RECT  4.464 126.083 6.432 126.659 ;
     RECT  42.744 126.083 45.6 126.949 ;
     RECT  36.912 126.131 40.2 126.517 ;
     RECT  60.6 126.133 61.8 127.381 ;
     RECT  48.216 126.179 49.272 126.275 ;
     RECT  13.512 126.181 14.784 126.517 ;
     RECT  54.768 126.227 55.632 127.045 ;
     RECT  46.728 126.275 49.272 126.517 ;
     RECT  29.04 126.421 29.28 127.093 ;
     RECT  63.624 126.421 65.856 126.853 ;
     RECT  69.72 126.421 72.48 126.469 ;
     RECT  69.912 126.469 71.76 126.517 ;
     RECT  76.536 126.469 77.52 127.045 ;
     RECT  13.512 126.517 14.736 127.045 ;
     RECT  22.824 126.517 24 127.093 ;
     RECT  36.912 126.517 38.688 126.803 ;
     RECT  38.808 126.517 40.2 126.803 ;
     RECT  46.728 126.517 50.688 126.661 ;
     RECT  70.728 126.517 71.76 126.853 ;
     RECT  78.84 126.517 80.208 126.997 ;
     RECT  58.992 126.563 60.576 127.093 ;
     RECT  4.464 126.659 6.672 126.661 ;
     RECT  4.464 126.661 5.328 127.093 ;
     RECT  5.352 126.661 6.672 127.669 ;
     RECT  46.728 126.661 50.352 127.045 ;
     RECT  29.712 126.803 30.744 127.669 ;
     RECT  36.912 126.803 40.2 126.949 ;
     RECT  80.568 126.901 83.4 126.949 ;
     RECT  10.248 126.949 12.144 127.093 ;
     RECT  17.4 126.949 18.48 128.197 ;
     RECT  36.912 126.949 39.264 127.093 ;
     RECT  42.744 126.949 44.112 127.093 ;
     RECT  44.568 126.949 45.6 127.045 ;
     RECT  81.912 126.949 83.4 127.463 ;
     RECT  24.984 127.045 26.256 128.197 ;
     RECT  47.16 127.045 50.352 127.621 ;
     RECT  10.776 127.093 12.144 128.197 ;
     RECT  36.936 127.093 39.264 127.141 ;
     RECT  57.384 127.093 58.368 128.197 ;
     RECT  59.256 127.093 60.576 128.821 ;
     RECT  37.368 127.141 39.264 128.245 ;
     RECT  51.672 127.141 52.944 128.821 ;
     RECT  45.432 127.463 46.608 128.821 ;
     RECT  55.656 127.463 56.928 128.821 ;
     RECT  47.16 127.621 48.144 128.197 ;
     RECT  48.168 127.621 50.352 127.669 ;
     RECT  29.712 127.669 31.2 128.245 ;
     RECT  31.224 127.669 32.496 128.821 ;
     RECT  33.48 127.669 34.752 128.197 ;
     RECT  48.168 127.669 49.488 128.821 ;
     RECT  19.704 128.197 20.976 128.821 ;
     RECT  37.8 128.245 39.264 128.821 ;
     RECT  37.8 128.821 38.832 129.36 ;
     RECT  37.848 129.36 38.784 129.424 ;
  END
END s81_a2f_field4
END LIBRARY
